# Generated deterministically by seda-macro-lef-normalizer-v1; recipe orfs-asap7-fakeram-m4-v1.
VERSION 5.8 ;
BUSBITCHARS "[]" ;
DIVIDERCHAR "/" ;

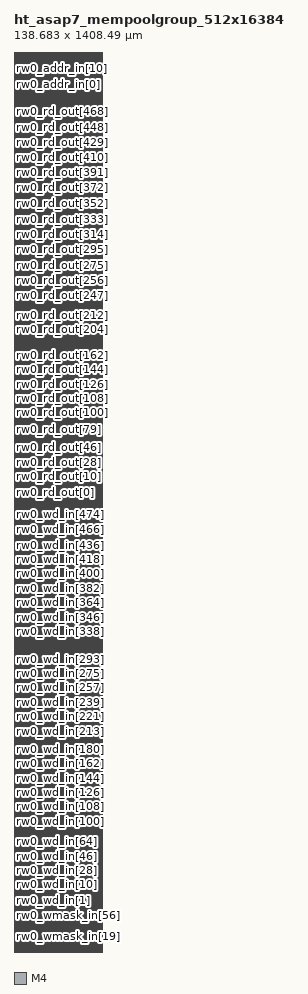
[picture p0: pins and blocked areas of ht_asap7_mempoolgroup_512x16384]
MACRO ht_asap7_mempoolgroup_512x16384
  FOREIGN ht_asap7_mempoolgroup_512x16384 0 0 ;
  CLASS BLOCK ;
  ORIGIN 0 0 ;
  SIZE 138.683 BY 1408.493 ;
  SYMMETRY X Y R90 ;
  PIN rw0_wmask_in[0]
    DIRECTION INPUT ;
    USE SIGNAL ;
    SHAPE ABUTMENT ;
    PORT
      LAYER M4 ;
      RECT 0 0.048 0.024 0.072 ;
    END
  END rw0_wmask_in[0]
  PIN rw0_wmask_in[1]
    DIRECTION INPUT ;
    USE SIGNAL ;
    SHAPE ABUTMENT ;
    PORT
      LAYER M4 ;
      RECT 0 1.296 0.024 1.32 ;
    END
  END rw0_wmask_in[1]
  PIN rw0_wmask_in[2]
    DIRECTION INPUT ;
    USE SIGNAL ;
    SHAPE ABUTMENT ;
    PORT
      LAYER M4 ;
      RECT 0 2.544 0.024 2.568 ;
    END
  END rw0_wmask_in[2]
  PIN rw0_wmask_in[3]
    DIRECTION INPUT ;
    USE SIGNAL ;
    SHAPE ABUTMENT ;
    PORT
      LAYER M4 ;
      RECT 0 3.792 0.024 3.816 ;
    END
  END rw0_wmask_in[3]
  PIN rw0_wmask_in[4]
    DIRECTION INPUT ;
    USE SIGNAL ;
    SHAPE ABUTMENT ;
    PORT
      LAYER M4 ;
      RECT 0 5.04 0.024 5.064 ;
    END
  END rw0_wmask_in[4]
  PIN rw0_wmask_in[5]
    DIRECTION INPUT ;
    USE SIGNAL ;
    SHAPE ABUTMENT ;
    PORT
      LAYER M4 ;
      RECT 0 6.288 0.024 6.312 ;
    END
  END rw0_wmask_in[5]
  PIN rw0_wmask_in[6]
    DIRECTION INPUT ;
    USE SIGNAL ;
    SHAPE ABUTMENT ;
    PORT
      LAYER M4 ;
      RECT 0 7.536 0.024 7.56 ;
    END
  END rw0_wmask_in[6]
  PIN rw0_wmask_in[7]
    DIRECTION INPUT ;
    USE SIGNAL ;
    SHAPE ABUTMENT ;
    PORT
      LAYER M4 ;
      RECT 0 8.784 0.024 8.808 ;
    END
  END rw0_wmask_in[7]
  PIN rw0_wmask_in[8]
    DIRECTION INPUT ;
    USE SIGNAL ;
    SHAPE ABUTMENT ;
    PORT
      LAYER M4 ;
      RECT 0 10.032 0.024 10.056 ;
    END
  END rw0_wmask_in[8]
  PIN rw0_wmask_in[9]
    DIRECTION INPUT ;
    USE SIGNAL ;
    SHAPE ABUTMENT ;
    PORT
      LAYER M4 ;
      RECT 0 11.28 0.024 11.304 ;
    END
  END rw0_wmask_in[9]
  PIN rw0_wmask_in[10]
    DIRECTION INPUT ;
    USE SIGNAL ;
    SHAPE ABUTMENT ;
    PORT
      LAYER M4 ;
      RECT 0 12.528 0.024 12.552 ;
    END
  END rw0_wmask_in[10]
  PIN rw0_wmask_in[11]
    DIRECTION INPUT ;
    USE SIGNAL ;
    SHAPE ABUTMENT ;
    PORT
      LAYER M4 ;
      RECT 0 13.776 0.024 13.8 ;
    END
  END rw0_wmask_in[11]
  PIN rw0_wmask_in[12]
    DIRECTION INPUT ;
    USE SIGNAL ;
    SHAPE ABUTMENT ;
    PORT
      LAYER M4 ;
      RECT 0 15.024 0.024 15.048 ;
    END
  END rw0_wmask_in[12]
  PIN rw0_wmask_in[13]
    DIRECTION INPUT ;
    USE SIGNAL ;
    SHAPE ABUTMENT ;
    PORT
      LAYER M4 ;
      RECT 0 16.272 0.024 16.296 ;
    END
  END rw0_wmask_in[13]
  PIN rw0_wmask_in[14]
    DIRECTION INPUT ;
    USE SIGNAL ;
    SHAPE ABUTMENT ;
    PORT
      LAYER M4 ;
      RECT 0 17.52 0.024 17.544 ;
    END
  END rw0_wmask_in[14]
  PIN rw0_wmask_in[15]
    DIRECTION INPUT ;
    USE SIGNAL ;
    SHAPE ABUTMENT ;
    PORT
      LAYER M4 ;
      RECT 0 18.768 0.024 18.792 ;
    END
  END rw0_wmask_in[15]
  PIN rw0_wmask_in[16]
    DIRECTION INPUT ;
    USE SIGNAL ;
    SHAPE ABUTMENT ;
    PORT
      LAYER M4 ;
      RECT 0 20.016 0.024 20.04 ;
    END
  END rw0_wmask_in[16]
  PIN rw0_wmask_in[17]
    DIRECTION INPUT ;
    USE SIGNAL ;
    SHAPE ABUTMENT ;
    PORT
      LAYER M4 ;
      RECT 0 21.264 0.024 21.288 ;
    END
  END rw0_wmask_in[17]
  PIN rw0_wmask_in[18]
    DIRECTION INPUT ;
    USE SIGNAL ;
    SHAPE ABUTMENT ;
    PORT
      LAYER M4 ;
      RECT 0 22.512 0.024 22.536 ;
    END
  END rw0_wmask_in[18]
  PIN rw0_wmask_in[19]
    DIRECTION INPUT ;
    USE SIGNAL ;
    SHAPE ABUTMENT ;
    PORT
      LAYER M4 ;
      RECT 0 23.76 0.024 23.784 ;
    END
  END rw0_wmask_in[19]
  PIN rw0_wmask_in[20]
    DIRECTION INPUT ;
    USE SIGNAL ;
    SHAPE ABUTMENT ;
    PORT
      LAYER M4 ;
      RECT 0 25.008 0.024 25.032 ;
    END
  END rw0_wmask_in[20]
  PIN rw0_wmask_in[21]
    DIRECTION INPUT ;
    USE SIGNAL ;
    SHAPE ABUTMENT ;
    PORT
      LAYER M4 ;
      RECT 0 26.256 0.024 26.28 ;
    END
  END rw0_wmask_in[21]
  PIN rw0_wmask_in[22]
    DIRECTION INPUT ;
    USE SIGNAL ;
    SHAPE ABUTMENT ;
    PORT
      LAYER M4 ;
      RECT 0 27.504 0.024 27.528 ;
    END
  END rw0_wmask_in[22]
  PIN rw0_wmask_in[23]
    DIRECTION INPUT ;
    USE SIGNAL ;
    SHAPE ABUTMENT ;
    PORT
      LAYER M4 ;
      RECT 0 28.752 0.024 28.776 ;
    END
  END rw0_wmask_in[23]
  PIN rw0_wmask_in[24]
    DIRECTION INPUT ;
    USE SIGNAL ;
    SHAPE ABUTMENT ;
    PORT
      LAYER M4 ;
      RECT 0 30 0.024 30.024 ;
    END
  END rw0_wmask_in[24]
  PIN rw0_wmask_in[25]
    DIRECTION INPUT ;
    USE SIGNAL ;
    SHAPE ABUTMENT ;
    PORT
      LAYER M4 ;
      RECT 0 31.248 0.024 31.272 ;
    END
  END rw0_wmask_in[25]
  PIN rw0_wmask_in[26]
    DIRECTION INPUT ;
    USE SIGNAL ;
    SHAPE ABUTMENT ;
    PORT
      LAYER M4 ;
      RECT 0 32.496 0.024 32.52 ;
    END
  END rw0_wmask_in[26]
  PIN rw0_wmask_in[27]
    DIRECTION INPUT ;
    USE SIGNAL ;
    SHAPE ABUTMENT ;
    PORT
      LAYER M4 ;
      RECT 0 33.744 0.024 33.768 ;
    END
  END rw0_wmask_in[27]
  PIN rw0_wmask_in[28]
    DIRECTION INPUT ;
    USE SIGNAL ;
    SHAPE ABUTMENT ;
    PORT
      LAYER M4 ;
      RECT 0 34.992 0.024 35.016 ;
    END
  END rw0_wmask_in[28]
  PIN rw0_wmask_in[29]
    DIRECTION INPUT ;
    USE SIGNAL ;
    SHAPE ABUTMENT ;
    PORT
      LAYER M4 ;
      RECT 0 36.24 0.024 36.264 ;
    END
  END rw0_wmask_in[29]
  PIN rw0_wmask_in[30]
    DIRECTION INPUT ;
    USE SIGNAL ;
    SHAPE ABUTMENT ;
    PORT
      LAYER M4 ;
      RECT 0 37.488 0.024 37.512 ;
    END
  END rw0_wmask_in[30]
  PIN rw0_wmask_in[31]
    DIRECTION INPUT ;
    USE SIGNAL ;
    SHAPE ABUTMENT ;
    PORT
      LAYER M4 ;
      RECT 0 38.736 0.024 38.76 ;
    END
  END rw0_wmask_in[31]
  PIN rw0_wmask_in[32]
    DIRECTION INPUT ;
    USE SIGNAL ;
    SHAPE ABUTMENT ;
    PORT
      LAYER M4 ;
      RECT 0 39.984 0.024 40.008 ;
    END
  END rw0_wmask_in[32]
  PIN rw0_wmask_in[33]
    DIRECTION INPUT ;
    USE SIGNAL ;
    SHAPE ABUTMENT ;
    PORT
      LAYER M4 ;
      RECT 0 41.232 0.024 41.256 ;
    END
  END rw0_wmask_in[33]
  PIN rw0_wmask_in[34]
    DIRECTION INPUT ;
    USE SIGNAL ;
    SHAPE ABUTMENT ;
    PORT
      LAYER M4 ;
      RECT 0 42.48 0.024 42.504 ;
    END
  END rw0_wmask_in[34]
  PIN rw0_wmask_in[35]
    DIRECTION INPUT ;
    USE SIGNAL ;
    SHAPE ABUTMENT ;
    PORT
      LAYER M4 ;
      RECT 0 43.728 0.024 43.752 ;
    END
  END rw0_wmask_in[35]
  PIN rw0_wmask_in[36]
    DIRECTION INPUT ;
    USE SIGNAL ;
    SHAPE ABUTMENT ;
    PORT
      LAYER M4 ;
      RECT 0 44.976 0.024 45 ;
    END
  END rw0_wmask_in[36]
  PIN rw0_wmask_in[37]
    DIRECTION INPUT ;
    USE SIGNAL ;
    SHAPE ABUTMENT ;
    PORT
      LAYER M4 ;
      RECT 0 46.224 0.024 46.248 ;
    END
  END rw0_wmask_in[37]
  PIN rw0_wmask_in[38]
    DIRECTION INPUT ;
    USE SIGNAL ;
    SHAPE ABUTMENT ;
    PORT
      LAYER M4 ;
      RECT 0 47.472 0.024 47.496 ;
    END
  END rw0_wmask_in[38]
  PIN rw0_wmask_in[39]
    DIRECTION INPUT ;
    USE SIGNAL ;
    SHAPE ABUTMENT ;
    PORT
      LAYER M4 ;
      RECT 0 48.72 0.024 48.744 ;
    END
  END rw0_wmask_in[39]
  PIN rw0_wmask_in[40]
    DIRECTION INPUT ;
    USE SIGNAL ;
    SHAPE ABUTMENT ;
    PORT
      LAYER M4 ;
      RECT 0 49.968 0.024 49.992 ;
    END
  END rw0_wmask_in[40]
  PIN rw0_wmask_in[41]
    DIRECTION INPUT ;
    USE SIGNAL ;
    SHAPE ABUTMENT ;
    PORT
      LAYER M4 ;
      RECT 0 51.216 0.024 51.24 ;
    END
  END rw0_wmask_in[41]
  PIN rw0_wmask_in[42]
    DIRECTION INPUT ;
    USE SIGNAL ;
    SHAPE ABUTMENT ;
    PORT
      LAYER M4 ;
      RECT 0 52.464 0.024 52.488 ;
    END
  END rw0_wmask_in[42]
  PIN rw0_wmask_in[43]
    DIRECTION INPUT ;
    USE SIGNAL ;
    SHAPE ABUTMENT ;
    PORT
      LAYER M4 ;
      RECT 0 53.712 0.024 53.736 ;
    END
  END rw0_wmask_in[43]
  PIN rw0_wmask_in[44]
    DIRECTION INPUT ;
    USE SIGNAL ;
    SHAPE ABUTMENT ;
    PORT
      LAYER M4 ;
      RECT 0 54.96 0.024 54.984 ;
    END
  END rw0_wmask_in[44]
  PIN rw0_wmask_in[45]
    DIRECTION INPUT ;
    USE SIGNAL ;
    SHAPE ABUTMENT ;
    PORT
      LAYER M4 ;
      RECT 0 56.208 0.024 56.232 ;
    END
  END rw0_wmask_in[45]
  PIN rw0_wmask_in[46]
    DIRECTION INPUT ;
    USE SIGNAL ;
    SHAPE ABUTMENT ;
    PORT
      LAYER M4 ;
      RECT 0 57.456 0.024 57.48 ;
    END
  END rw0_wmask_in[46]
  PIN rw0_wmask_in[47]
    DIRECTION INPUT ;
    USE SIGNAL ;
    SHAPE ABUTMENT ;
    PORT
      LAYER M4 ;
      RECT 0 58.704 0.024 58.728 ;
    END
  END rw0_wmask_in[47]
  PIN rw0_wmask_in[48]
    DIRECTION INPUT ;
    USE SIGNAL ;
    SHAPE ABUTMENT ;
    PORT
      LAYER M4 ;
      RECT 0 59.952 0.024 59.976 ;
    END
  END rw0_wmask_in[48]
  PIN rw0_wmask_in[49]
    DIRECTION INPUT ;
    USE SIGNAL ;
    SHAPE ABUTMENT ;
    PORT
      LAYER M4 ;
      RECT 0 61.2 0.024 61.224 ;
    END
  END rw0_wmask_in[49]
  PIN rw0_wmask_in[50]
    DIRECTION INPUT ;
    USE SIGNAL ;
    SHAPE ABUTMENT ;
    PORT
      LAYER M4 ;
      RECT 0 62.448 0.024 62.472 ;
    END
  END rw0_wmask_in[50]
  PIN rw0_wmask_in[51]
    DIRECTION INPUT ;
    USE SIGNAL ;
    SHAPE ABUTMENT ;
    PORT
      LAYER M4 ;
      RECT 0 63.696 0.024 63.72 ;
    END
  END rw0_wmask_in[51]
  PIN rw0_wmask_in[52]
    DIRECTION INPUT ;
    USE SIGNAL ;
    SHAPE ABUTMENT ;
    PORT
      LAYER M4 ;
      RECT 0 64.944 0.024 64.968 ;
    END
  END rw0_wmask_in[52]
  PIN rw0_wmask_in[53]
    DIRECTION INPUT ;
    USE SIGNAL ;
    SHAPE ABUTMENT ;
    PORT
      LAYER M4 ;
      RECT 0 66.192 0.024 66.216 ;
    END
  END rw0_wmask_in[53]
  PIN rw0_wmask_in[54]
    DIRECTION INPUT ;
    USE SIGNAL ;
    SHAPE ABUTMENT ;
    PORT
      LAYER M4 ;
      RECT 0 67.44 0.024 67.464 ;
    END
  END rw0_wmask_in[54]
  PIN rw0_wmask_in[55]
    DIRECTION INPUT ;
    USE SIGNAL ;
    SHAPE ABUTMENT ;
    PORT
      LAYER M4 ;
      RECT 0 68.688 0.024 68.712 ;
    END
  END rw0_wmask_in[55]
  PIN rw0_wmask_in[56]
    DIRECTION INPUT ;
    USE SIGNAL ;
    SHAPE ABUTMENT ;
    PORT
      LAYER M4 ;
      RECT 0 69.936 0.024 69.96 ;
    END
  END rw0_wmask_in[56]
  PIN rw0_wmask_in[57]
    DIRECTION INPUT ;
    USE SIGNAL ;
    SHAPE ABUTMENT ;
    PORT
      LAYER M4 ;
      RECT 0 71.184 0.024 71.208 ;
    END
  END rw0_wmask_in[57]
  PIN rw0_wmask_in[58]
    DIRECTION INPUT ;
    USE SIGNAL ;
    SHAPE ABUTMENT ;
    PORT
      LAYER M4 ;
      RECT 0 72.432 0.024 72.456 ;
    END
  END rw0_wmask_in[58]
  PIN rw0_wmask_in[59]
    DIRECTION INPUT ;
    USE SIGNAL ;
    SHAPE ABUTMENT ;
    PORT
      LAYER M4 ;
      RECT 0 73.68 0.024 73.704 ;
    END
  END rw0_wmask_in[59]
  PIN rw0_wmask_in[60]
    DIRECTION INPUT ;
    USE SIGNAL ;
    SHAPE ABUTMENT ;
    PORT
      LAYER M4 ;
      RECT 0 74.928 0.024 74.952 ;
    END
  END rw0_wmask_in[60]
  PIN rw0_wmask_in[61]
    DIRECTION INPUT ;
    USE SIGNAL ;
    SHAPE ABUTMENT ;
    PORT
      LAYER M4 ;
      RECT 0 76.176 0.024 76.2 ;
    END
  END rw0_wmask_in[61]
  PIN rw0_wmask_in[62]
    DIRECTION INPUT ;
    USE SIGNAL ;
    SHAPE ABUTMENT ;
    PORT
      LAYER M4 ;
      RECT 0 77.424 0.024 77.448 ;
    END
  END rw0_wmask_in[62]
  PIN rw0_wmask_in[63]
    DIRECTION INPUT ;
    USE SIGNAL ;
    SHAPE ABUTMENT ;
    PORT
      LAYER M4 ;
      RECT 0 78.672 0.024 78.696 ;
    END
  END rw0_wmask_in[63]
  PIN rw0_wd_in[0]
    DIRECTION INPUT ;
    USE SIGNAL ;
    SHAPE ABUTMENT ;
    PORT
      LAYER M4 ;
      RECT 0 79.92 0.024 79.944 ;
    END
  END rw0_wd_in[0]
  PIN rw0_wd_in[1]
    DIRECTION INPUT ;
    USE SIGNAL ;
    SHAPE ABUTMENT ;
    PORT
      LAYER M4 ;
      RECT 0 81.168 0.024 81.192 ;
    END
  END rw0_wd_in[1]
  PIN rw0_wd_in[2]
    DIRECTION INPUT ;
    USE SIGNAL ;
    SHAPE ABUTMENT ;
    PORT
      LAYER M4 ;
      RECT 0 82.416 0.024 82.44 ;
    END
  END rw0_wd_in[2]
  PIN rw0_wd_in[3]
    DIRECTION INPUT ;
    USE SIGNAL ;
    SHAPE ABUTMENT ;
    PORT
      LAYER M4 ;
      RECT 0 83.664 0.024 83.688 ;
    END
  END rw0_wd_in[3]
  PIN rw0_wd_in[4]
    DIRECTION INPUT ;
    USE SIGNAL ;
    SHAPE ABUTMENT ;
    PORT
      LAYER M4 ;
      RECT 0 84.912 0.024 84.936 ;
    END
  END rw0_wd_in[4]
  PIN rw0_wd_in[5]
    DIRECTION INPUT ;
    USE SIGNAL ;
    SHAPE ABUTMENT ;
    PORT
      LAYER M4 ;
      RECT 0 86.16 0.024 86.184 ;
    END
  END rw0_wd_in[5]
  PIN rw0_wd_in[6]
    DIRECTION INPUT ;
    USE SIGNAL ;
    SHAPE ABUTMENT ;
    PORT
      LAYER M4 ;
      RECT 0 87.408 0.024 87.432 ;
    END
  END rw0_wd_in[6]
  PIN rw0_wd_in[7]
    DIRECTION INPUT ;
    USE SIGNAL ;
    SHAPE ABUTMENT ;
    PORT
      LAYER M4 ;
      RECT 0 88.656 0.024 88.68 ;
    END
  END rw0_wd_in[7]
  PIN rw0_wd_in[8]
    DIRECTION INPUT ;
    USE SIGNAL ;
    SHAPE ABUTMENT ;
    PORT
      LAYER M4 ;
      RECT 0 89.904 0.024 89.928 ;
    END
  END rw0_wd_in[8]
  PIN rw0_wd_in[9]
    DIRECTION INPUT ;
    USE SIGNAL ;
    SHAPE ABUTMENT ;
    PORT
      LAYER M4 ;
      RECT 0 91.152 0.024 91.176 ;
    END
  END rw0_wd_in[9]
  PIN rw0_wd_in[10]
    DIRECTION INPUT ;
    USE SIGNAL ;
    SHAPE ABUTMENT ;
    PORT
      LAYER M4 ;
      RECT 0 92.4 0.024 92.424 ;
    END
  END rw0_wd_in[10]
  PIN rw0_wd_in[11]
    DIRECTION INPUT ;
    USE SIGNAL ;
    SHAPE ABUTMENT ;
    PORT
      LAYER M4 ;
      RECT 0 93.648 0.024 93.672 ;
    END
  END rw0_wd_in[11]
  PIN rw0_wd_in[12]
    DIRECTION INPUT ;
    USE SIGNAL ;
    SHAPE ABUTMENT ;
    PORT
      LAYER M4 ;
      RECT 0 94.896 0.024 94.92 ;
    END
  END rw0_wd_in[12]
  PIN rw0_wd_in[13]
    DIRECTION INPUT ;
    USE SIGNAL ;
    SHAPE ABUTMENT ;
    PORT
      LAYER M4 ;
      RECT 0 96.144 0.024 96.168 ;
    END
  END rw0_wd_in[13]
  PIN rw0_wd_in[14]
    DIRECTION INPUT ;
    USE SIGNAL ;
    SHAPE ABUTMENT ;
    PORT
      LAYER M4 ;
      RECT 0 97.392 0.024 97.416 ;
    END
  END rw0_wd_in[14]
  PIN rw0_wd_in[15]
    DIRECTION INPUT ;
    USE SIGNAL ;
    SHAPE ABUTMENT ;
    PORT
      LAYER M4 ;
      RECT 0 98.64 0.024 98.664 ;
    END
  END rw0_wd_in[15]
  PIN rw0_wd_in[16]
    DIRECTION INPUT ;
    USE SIGNAL ;
    SHAPE ABUTMENT ;
    PORT
      LAYER M4 ;
      RECT 0 99.888 0.024 99.912 ;
    END
  END rw0_wd_in[16]
  PIN rw0_wd_in[17]
    DIRECTION INPUT ;
    USE SIGNAL ;
    SHAPE ABUTMENT ;
    PORT
      LAYER M4 ;
      RECT 0 101.136 0.024 101.16 ;
    END
  END rw0_wd_in[17]
  PIN rw0_wd_in[18]
    DIRECTION INPUT ;
    USE SIGNAL ;
    SHAPE ABUTMENT ;
    PORT
      LAYER M4 ;
      RECT 0 102.384 0.024 102.408 ;
    END
  END rw0_wd_in[18]
  PIN rw0_wd_in[19]
    DIRECTION INPUT ;
    USE SIGNAL ;
    SHAPE ABUTMENT ;
    PORT
      LAYER M4 ;
      RECT 0 103.632 0.024 103.656 ;
    END
  END rw0_wd_in[19]
  PIN rw0_wd_in[20]
    DIRECTION INPUT ;
    USE SIGNAL ;
    SHAPE ABUTMENT ;
    PORT
      LAYER M4 ;
      RECT 0 104.88 0.024 104.904 ;
    END
  END rw0_wd_in[20]
  PIN rw0_wd_in[21]
    DIRECTION INPUT ;
    USE SIGNAL ;
    SHAPE ABUTMENT ;
    PORT
      LAYER M4 ;
      RECT 0 106.128 0.024 106.152 ;
    END
  END rw0_wd_in[21]
  PIN rw0_wd_in[22]
    DIRECTION INPUT ;
    USE SIGNAL ;
    SHAPE ABUTMENT ;
    PORT
      LAYER M4 ;
      RECT 0 107.376 0.024 107.4 ;
    END
  END rw0_wd_in[22]
  PIN rw0_wd_in[23]
    DIRECTION INPUT ;
    USE SIGNAL ;
    SHAPE ABUTMENT ;
    PORT
      LAYER M4 ;
      RECT 0 108.624 0.024 108.648 ;
    END
  END rw0_wd_in[23]
  PIN rw0_wd_in[24]
    DIRECTION INPUT ;
    USE SIGNAL ;
    SHAPE ABUTMENT ;
    PORT
      LAYER M4 ;
      RECT 0 109.872 0.024 109.896 ;
    END
  END rw0_wd_in[24]
  PIN rw0_wd_in[25]
    DIRECTION INPUT ;
    USE SIGNAL ;
    SHAPE ABUTMENT ;
    PORT
      LAYER M4 ;
      RECT 0 111.12 0.024 111.144 ;
    END
  END rw0_wd_in[25]
  PIN rw0_wd_in[26]
    DIRECTION INPUT ;
    USE SIGNAL ;
    SHAPE ABUTMENT ;
    PORT
      LAYER M4 ;
      RECT 0 112.368 0.024 112.392 ;
    END
  END rw0_wd_in[26]
  PIN rw0_wd_in[27]
    DIRECTION INPUT ;
    USE SIGNAL ;
    SHAPE ABUTMENT ;
    PORT
      LAYER M4 ;
      RECT 0 113.616 0.024 113.64 ;
    END
  END rw0_wd_in[27]
  PIN rw0_wd_in[28]
    DIRECTION INPUT ;
    USE SIGNAL ;
    SHAPE ABUTMENT ;
    PORT
      LAYER M4 ;
      RECT 0 114.864 0.024 114.888 ;
    END
  END rw0_wd_in[28]
  PIN rw0_wd_in[29]
    DIRECTION INPUT ;
    USE SIGNAL ;
    SHAPE ABUTMENT ;
    PORT
      LAYER M4 ;
      RECT 0 116.112 0.024 116.136 ;
    END
  END rw0_wd_in[29]
  PIN rw0_wd_in[30]
    DIRECTION INPUT ;
    USE SIGNAL ;
    SHAPE ABUTMENT ;
    PORT
      LAYER M4 ;
      RECT 0 117.36 0.024 117.384 ;
    END
  END rw0_wd_in[30]
  PIN rw0_wd_in[31]
    DIRECTION INPUT ;
    USE SIGNAL ;
    SHAPE ABUTMENT ;
    PORT
      LAYER M4 ;
      RECT 0 118.608 0.024 118.632 ;
    END
  END rw0_wd_in[31]
  PIN rw0_wd_in[32]
    DIRECTION INPUT ;
    USE SIGNAL ;
    SHAPE ABUTMENT ;
    PORT
      LAYER M4 ;
      RECT 0 119.856 0.024 119.88 ;
    END
  END rw0_wd_in[32]
  PIN rw0_wd_in[33]
    DIRECTION INPUT ;
    USE SIGNAL ;
    SHAPE ABUTMENT ;
    PORT
      LAYER M4 ;
      RECT 0 121.104 0.024 121.128 ;
    END
  END rw0_wd_in[33]
  PIN rw0_wd_in[34]
    DIRECTION INPUT ;
    USE SIGNAL ;
    SHAPE ABUTMENT ;
    PORT
      LAYER M4 ;
      RECT 0 122.352 0.024 122.376 ;
    END
  END rw0_wd_in[34]
  PIN rw0_wd_in[35]
    DIRECTION INPUT ;
    USE SIGNAL ;
    SHAPE ABUTMENT ;
    PORT
      LAYER M4 ;
      RECT 0 123.6 0.024 123.624 ;
    END
  END rw0_wd_in[35]
  PIN rw0_wd_in[36]
    DIRECTION INPUT ;
    USE SIGNAL ;
    SHAPE ABUTMENT ;
    PORT
      LAYER M4 ;
      RECT 0 124.848 0.024 124.872 ;
    END
  END rw0_wd_in[36]
  PIN rw0_wd_in[37]
    DIRECTION INPUT ;
    USE SIGNAL ;
    SHAPE ABUTMENT ;
    PORT
      LAYER M4 ;
      RECT 0 126.096 0.024 126.12 ;
    END
  END rw0_wd_in[37]
  PIN rw0_wd_in[38]
    DIRECTION INPUT ;
    USE SIGNAL ;
    SHAPE ABUTMENT ;
    PORT
      LAYER M4 ;
      RECT 0 127.344 0.024 127.368 ;
    END
  END rw0_wd_in[38]
  PIN rw0_wd_in[39]
    DIRECTION INPUT ;
    USE SIGNAL ;
    SHAPE ABUTMENT ;
    PORT
      LAYER M4 ;
      RECT 0 128.592 0.024 128.616 ;
    END
  END rw0_wd_in[39]
  PIN rw0_wd_in[40]
    DIRECTION INPUT ;
    USE SIGNAL ;
    SHAPE ABUTMENT ;
    PORT
      LAYER M4 ;
      RECT 0 129.84 0.024 129.864 ;
    END
  END rw0_wd_in[40]
  PIN rw0_wd_in[41]
    DIRECTION INPUT ;
    USE SIGNAL ;
    SHAPE ABUTMENT ;
    PORT
      LAYER M4 ;
      RECT 0 131.088 0.024 131.112 ;
    END
  END rw0_wd_in[41]
  PIN rw0_wd_in[42]
    DIRECTION INPUT ;
    USE SIGNAL ;
    SHAPE ABUTMENT ;
    PORT
      LAYER M4 ;
      RECT 0 132.336 0.024 132.36 ;
    END
  END rw0_wd_in[42]
  PIN rw0_wd_in[43]
    DIRECTION INPUT ;
    USE SIGNAL ;
    SHAPE ABUTMENT ;
    PORT
      LAYER M4 ;
      RECT 0 133.584 0.024 133.608 ;
    END
  END rw0_wd_in[43]
  PIN rw0_wd_in[44]
    DIRECTION INPUT ;
    USE SIGNAL ;
    SHAPE ABUTMENT ;
    PORT
      LAYER M4 ;
      RECT 0 134.832 0.024 134.856 ;
    END
  END rw0_wd_in[44]
  PIN rw0_wd_in[45]
    DIRECTION INPUT ;
    USE SIGNAL ;
    SHAPE ABUTMENT ;
    PORT
      LAYER M4 ;
      RECT 0 136.08 0.024 136.104 ;
    END
  END rw0_wd_in[45]
  PIN rw0_wd_in[46]
    DIRECTION INPUT ;
    USE SIGNAL ;
    SHAPE ABUTMENT ;
    PORT
      LAYER M4 ;
      RECT 0 137.328 0.024 137.352 ;
    END
  END rw0_wd_in[46]
  PIN rw0_wd_in[47]
    DIRECTION INPUT ;
    USE SIGNAL ;
    SHAPE ABUTMENT ;
    PORT
      LAYER M4 ;
      RECT 0 138.576 0.024 138.6 ;
    END
  END rw0_wd_in[47]
  PIN rw0_wd_in[48]
    DIRECTION INPUT ;
    USE SIGNAL ;
    SHAPE ABUTMENT ;
    PORT
      LAYER M4 ;
      RECT 0 139.824 0.024 139.848 ;
    END
  END rw0_wd_in[48]
  PIN rw0_wd_in[49]
    DIRECTION INPUT ;
    USE SIGNAL ;
    SHAPE ABUTMENT ;
    PORT
      LAYER M4 ;
      RECT 0 141.072 0.024 141.096 ;
    END
  END rw0_wd_in[49]
  PIN rw0_wd_in[50]
    DIRECTION INPUT ;
    USE SIGNAL ;
    SHAPE ABUTMENT ;
    PORT
      LAYER M4 ;
      RECT 0 142.32 0.024 142.344 ;
    END
  END rw0_wd_in[50]
  PIN rw0_wd_in[51]
    DIRECTION INPUT ;
    USE SIGNAL ;
    SHAPE ABUTMENT ;
    PORT
      LAYER M4 ;
      RECT 0 143.568 0.024 143.592 ;
    END
  END rw0_wd_in[51]
  PIN rw0_wd_in[52]
    DIRECTION INPUT ;
    USE SIGNAL ;
    SHAPE ABUTMENT ;
    PORT
      LAYER M4 ;
      RECT 0 144.816 0.024 144.84 ;
    END
  END rw0_wd_in[52]
  PIN rw0_wd_in[53]
    DIRECTION INPUT ;
    USE SIGNAL ;
    SHAPE ABUTMENT ;
    PORT
      LAYER M4 ;
      RECT 0 146.064 0.024 146.088 ;
    END
  END rw0_wd_in[53]
  PIN rw0_wd_in[54]
    DIRECTION INPUT ;
    USE SIGNAL ;
    SHAPE ABUTMENT ;
    PORT
      LAYER M4 ;
      RECT 0 147.312 0.024 147.336 ;
    END
  END rw0_wd_in[54]
  PIN rw0_wd_in[55]
    DIRECTION INPUT ;
    USE SIGNAL ;
    SHAPE ABUTMENT ;
    PORT
      LAYER M4 ;
      RECT 0 148.56 0.024 148.584 ;
    END
  END rw0_wd_in[55]
  PIN rw0_wd_in[56]
    DIRECTION INPUT ;
    USE SIGNAL ;
    SHAPE ABUTMENT ;
    PORT
      LAYER M4 ;
      RECT 0 149.808 0.024 149.832 ;
    END
  END rw0_wd_in[56]
  PIN rw0_wd_in[57]
    DIRECTION INPUT ;
    USE SIGNAL ;
    SHAPE ABUTMENT ;
    PORT
      LAYER M4 ;
      RECT 0 151.056 0.024 151.08 ;
    END
  END rw0_wd_in[57]
  PIN rw0_wd_in[58]
    DIRECTION INPUT ;
    USE SIGNAL ;
    SHAPE ABUTMENT ;
    PORT
      LAYER M4 ;
      RECT 0 152.304 0.024 152.328 ;
    END
  END rw0_wd_in[58]
  PIN rw0_wd_in[59]
    DIRECTION INPUT ;
    USE SIGNAL ;
    SHAPE ABUTMENT ;
    PORT
      LAYER M4 ;
      RECT 0 153.552 0.024 153.576 ;
    END
  END rw0_wd_in[59]
  PIN rw0_wd_in[60]
    DIRECTION INPUT ;
    USE SIGNAL ;
    SHAPE ABUTMENT ;
    PORT
      LAYER M4 ;
      RECT 0 154.8 0.024 154.824 ;
    END
  END rw0_wd_in[60]
  PIN rw0_wd_in[61]
    DIRECTION INPUT ;
    USE SIGNAL ;
    SHAPE ABUTMENT ;
    PORT
      LAYER M4 ;
      RECT 0 156.048 0.024 156.072 ;
    END
  END rw0_wd_in[61]
  PIN rw0_wd_in[62]
    DIRECTION INPUT ;
    USE SIGNAL ;
    SHAPE ABUTMENT ;
    PORT
      LAYER M4 ;
      RECT 0 157.296 0.024 157.32 ;
    END
  END rw0_wd_in[62]
  PIN rw0_wd_in[63]
    DIRECTION INPUT ;
    USE SIGNAL ;
    SHAPE ABUTMENT ;
    PORT
      LAYER M4 ;
      RECT 0 158.544 0.024 158.568 ;
    END
  END rw0_wd_in[63]
  PIN rw0_wd_in[64]
    DIRECTION INPUT ;
    USE SIGNAL ;
    SHAPE ABUTMENT ;
    PORT
      LAYER M4 ;
      RECT 0 159.792 0.024 159.816 ;
    END
  END rw0_wd_in[64]
  PIN rw0_wd_in[65]
    DIRECTION INPUT ;
    USE SIGNAL ;
    SHAPE ABUTMENT ;
    PORT
      LAYER M4 ;
      RECT 0 161.04 0.024 161.064 ;
    END
  END rw0_wd_in[65]
  PIN rw0_wd_in[66]
    DIRECTION INPUT ;
    USE SIGNAL ;
    SHAPE ABUTMENT ;
    PORT
      LAYER M4 ;
      RECT 0 162.288 0.024 162.312 ;
    END
  END rw0_wd_in[66]
  PIN rw0_wd_in[67]
    DIRECTION INPUT ;
    USE SIGNAL ;
    SHAPE ABUTMENT ;
    PORT
      LAYER M4 ;
      RECT 0 163.536 0.024 163.56 ;
    END
  END rw0_wd_in[67]
  PIN rw0_wd_in[68]
    DIRECTION INPUT ;
    USE SIGNAL ;
    SHAPE ABUTMENT ;
    PORT
      LAYER M4 ;
      RECT 0 164.784 0.024 164.808 ;
    END
  END rw0_wd_in[68]
  PIN rw0_wd_in[69]
    DIRECTION INPUT ;
    USE SIGNAL ;
    SHAPE ABUTMENT ;
    PORT
      LAYER M4 ;
      RECT 0 166.032 0.024 166.056 ;
    END
  END rw0_wd_in[69]
  PIN rw0_wd_in[70]
    DIRECTION INPUT ;
    USE SIGNAL ;
    SHAPE ABUTMENT ;
    PORT
      LAYER M4 ;
      RECT 0 167.28 0.024 167.304 ;
    END
  END rw0_wd_in[70]
  PIN rw0_wd_in[71]
    DIRECTION INPUT ;
    USE SIGNAL ;
    SHAPE ABUTMENT ;
    PORT
      LAYER M4 ;
      RECT 0 168.528 0.024 168.552 ;
    END
  END rw0_wd_in[71]
  PIN rw0_wd_in[72]
    DIRECTION INPUT ;
    USE SIGNAL ;
    SHAPE ABUTMENT ;
    PORT
      LAYER M4 ;
      RECT 0 169.776 0.024 169.8 ;
    END
  END rw0_wd_in[72]
  PIN rw0_wd_in[73]
    DIRECTION INPUT ;
    USE SIGNAL ;
    SHAPE ABUTMENT ;
    PORT
      LAYER M4 ;
      RECT 0 171.024 0.024 171.048 ;
    END
  END rw0_wd_in[73]
  PIN rw0_wd_in[74]
    DIRECTION INPUT ;
    USE SIGNAL ;
    SHAPE ABUTMENT ;
    PORT
      LAYER M4 ;
      RECT 0 172.272 0.024 172.296 ;
    END
  END rw0_wd_in[74]
  PIN rw0_wd_in[75]
    DIRECTION INPUT ;
    USE SIGNAL ;
    SHAPE ABUTMENT ;
    PORT
      LAYER M4 ;
      RECT 0 173.52 0.024 173.544 ;
    END
  END rw0_wd_in[75]
  PIN rw0_wd_in[76]
    DIRECTION INPUT ;
    USE SIGNAL ;
    SHAPE ABUTMENT ;
    PORT
      LAYER M4 ;
      RECT 0 174.768 0.024 174.792 ;
    END
  END rw0_wd_in[76]
  PIN rw0_wd_in[77]
    DIRECTION INPUT ;
    USE SIGNAL ;
    SHAPE ABUTMENT ;
    PORT
      LAYER M4 ;
      RECT 0 176.016 0.024 176.04 ;
    END
  END rw0_wd_in[77]
  PIN rw0_wd_in[78]
    DIRECTION INPUT ;
    USE SIGNAL ;
    SHAPE ABUTMENT ;
    PORT
      LAYER M4 ;
      RECT 0 177.264 0.024 177.288 ;
    END
  END rw0_wd_in[78]
  PIN rw0_wd_in[79]
    DIRECTION INPUT ;
    USE SIGNAL ;
    SHAPE ABUTMENT ;
    PORT
      LAYER M4 ;
      RECT 0 178.512 0.024 178.536 ;
    END
  END rw0_wd_in[79]
  PIN rw0_wd_in[80]
    DIRECTION INPUT ;
    USE SIGNAL ;
    SHAPE ABUTMENT ;
    PORT
      LAYER M4 ;
      RECT 0 179.76 0.024 179.784 ;
    END
  END rw0_wd_in[80]
  PIN rw0_wd_in[81]
    DIRECTION INPUT ;
    USE SIGNAL ;
    SHAPE ABUTMENT ;
    PORT
      LAYER M4 ;
      RECT 0 181.008 0.024 181.032 ;
    END
  END rw0_wd_in[81]
  PIN rw0_wd_in[82]
    DIRECTION INPUT ;
    USE SIGNAL ;
    SHAPE ABUTMENT ;
    PORT
      LAYER M4 ;
      RECT 0 182.256 0.024 182.28 ;
    END
  END rw0_wd_in[82]
  PIN rw0_wd_in[83]
    DIRECTION INPUT ;
    USE SIGNAL ;
    SHAPE ABUTMENT ;
    PORT
      LAYER M4 ;
      RECT 0 183.504 0.024 183.528 ;
    END
  END rw0_wd_in[83]
  PIN rw0_wd_in[84]
    DIRECTION INPUT ;
    USE SIGNAL ;
    SHAPE ABUTMENT ;
    PORT
      LAYER M4 ;
      RECT 0 184.752 0.024 184.776 ;
    END
  END rw0_wd_in[84]
  PIN rw0_wd_in[85]
    DIRECTION INPUT ;
    USE SIGNAL ;
    SHAPE ABUTMENT ;
    PORT
      LAYER M4 ;
      RECT 0 186 0.024 186.024 ;
    END
  END rw0_wd_in[85]
  PIN rw0_wd_in[86]
    DIRECTION INPUT ;
    USE SIGNAL ;
    SHAPE ABUTMENT ;
    PORT
      LAYER M4 ;
      RECT 0 187.248 0.024 187.272 ;
    END
  END rw0_wd_in[86]
  PIN rw0_wd_in[87]
    DIRECTION INPUT ;
    USE SIGNAL ;
    SHAPE ABUTMENT ;
    PORT
      LAYER M4 ;
      RECT 0 188.496 0.024 188.52 ;
    END
  END rw0_wd_in[87]
  PIN rw0_wd_in[88]
    DIRECTION INPUT ;
    USE SIGNAL ;
    SHAPE ABUTMENT ;
    PORT
      LAYER M4 ;
      RECT 0 189.744 0.024 189.768 ;
    END
  END rw0_wd_in[88]
  PIN rw0_wd_in[89]
    DIRECTION INPUT ;
    USE SIGNAL ;
    SHAPE ABUTMENT ;
    PORT
      LAYER M4 ;
      RECT 0 190.992 0.024 191.016 ;
    END
  END rw0_wd_in[89]
  PIN rw0_wd_in[90]
    DIRECTION INPUT ;
    USE SIGNAL ;
    SHAPE ABUTMENT ;
    PORT
      LAYER M4 ;
      RECT 0 192.24 0.024 192.264 ;
    END
  END rw0_wd_in[90]
  PIN rw0_wd_in[91]
    DIRECTION INPUT ;
    USE SIGNAL ;
    SHAPE ABUTMENT ;
    PORT
      LAYER M4 ;
      RECT 0 193.488 0.024 193.512 ;
    END
  END rw0_wd_in[91]
  PIN rw0_wd_in[92]
    DIRECTION INPUT ;
    USE SIGNAL ;
    SHAPE ABUTMENT ;
    PORT
      LAYER M4 ;
      RECT 0 194.736 0.024 194.76 ;
    END
  END rw0_wd_in[92]
  PIN rw0_wd_in[93]
    DIRECTION INPUT ;
    USE SIGNAL ;
    SHAPE ABUTMENT ;
    PORT
      LAYER M4 ;
      RECT 0 195.984 0.024 196.008 ;
    END
  END rw0_wd_in[93]
  PIN rw0_wd_in[94]
    DIRECTION INPUT ;
    USE SIGNAL ;
    SHAPE ABUTMENT ;
    PORT
      LAYER M4 ;
      RECT 0 197.232 0.024 197.256 ;
    END
  END rw0_wd_in[94]
  PIN rw0_wd_in[95]
    DIRECTION INPUT ;
    USE SIGNAL ;
    SHAPE ABUTMENT ;
    PORT
      LAYER M4 ;
      RECT 0 198.48 0.024 198.504 ;
    END
  END rw0_wd_in[95]
  PIN rw0_wd_in[96]
    DIRECTION INPUT ;
    USE SIGNAL ;
    SHAPE ABUTMENT ;
    PORT
      LAYER M4 ;
      RECT 0 199.728 0.024 199.752 ;
    END
  END rw0_wd_in[96]
  PIN rw0_wd_in[97]
    DIRECTION INPUT ;
    USE SIGNAL ;
    SHAPE ABUTMENT ;
    PORT
      LAYER M4 ;
      RECT 0 200.976 0.024 201 ;
    END
  END rw0_wd_in[97]
  PIN rw0_wd_in[98]
    DIRECTION INPUT ;
    USE SIGNAL ;
    SHAPE ABUTMENT ;
    PORT
      LAYER M4 ;
      RECT 0 202.224 0.024 202.248 ;
    END
  END rw0_wd_in[98]
  PIN rw0_wd_in[99]
    DIRECTION INPUT ;
    USE SIGNAL ;
    SHAPE ABUTMENT ;
    PORT
      LAYER M4 ;
      RECT 0 203.472 0.024 203.496 ;
    END
  END rw0_wd_in[99]
  PIN rw0_wd_in[100]
    DIRECTION INPUT ;
    USE SIGNAL ;
    SHAPE ABUTMENT ;
    PORT
      LAYER M4 ;
      RECT 0 204.72 0.024 204.744 ;
    END
  END rw0_wd_in[100]
  PIN rw0_wd_in[101]
    DIRECTION INPUT ;
    USE SIGNAL ;
    SHAPE ABUTMENT ;
    PORT
      LAYER M4 ;
      RECT 0 205.968 0.024 205.992 ;
    END
  END rw0_wd_in[101]
  PIN rw0_wd_in[102]
    DIRECTION INPUT ;
    USE SIGNAL ;
    SHAPE ABUTMENT ;
    PORT
      LAYER M4 ;
      RECT 0 207.216 0.024 207.24 ;
    END
  END rw0_wd_in[102]
  PIN rw0_wd_in[103]
    DIRECTION INPUT ;
    USE SIGNAL ;
    SHAPE ABUTMENT ;
    PORT
      LAYER M4 ;
      RECT 0 208.464 0.024 208.488 ;
    END
  END rw0_wd_in[103]
  PIN rw0_wd_in[104]
    DIRECTION INPUT ;
    USE SIGNAL ;
    SHAPE ABUTMENT ;
    PORT
      LAYER M4 ;
      RECT 0 209.712 0.024 209.736 ;
    END
  END rw0_wd_in[104]
  PIN rw0_wd_in[105]
    DIRECTION INPUT ;
    USE SIGNAL ;
    SHAPE ABUTMENT ;
    PORT
      LAYER M4 ;
      RECT 0 210.96 0.024 210.984 ;
    END
  END rw0_wd_in[105]
  PIN rw0_wd_in[106]
    DIRECTION INPUT ;
    USE SIGNAL ;
    SHAPE ABUTMENT ;
    PORT
      LAYER M4 ;
      RECT 0 212.208 0.024 212.232 ;
    END
  END rw0_wd_in[106]
  PIN rw0_wd_in[107]
    DIRECTION INPUT ;
    USE SIGNAL ;
    SHAPE ABUTMENT ;
    PORT
      LAYER M4 ;
      RECT 0 213.456 0.024 213.48 ;
    END
  END rw0_wd_in[107]
  PIN rw0_wd_in[108]
    DIRECTION INPUT ;
    USE SIGNAL ;
    SHAPE ABUTMENT ;
    PORT
      LAYER M4 ;
      RECT 0 214.704 0.024 214.728 ;
    END
  END rw0_wd_in[108]
  PIN rw0_wd_in[109]
    DIRECTION INPUT ;
    USE SIGNAL ;
    SHAPE ABUTMENT ;
    PORT
      LAYER M4 ;
      RECT 0 215.952 0.024 215.976 ;
    END
  END rw0_wd_in[109]
  PIN rw0_wd_in[110]
    DIRECTION INPUT ;
    USE SIGNAL ;
    SHAPE ABUTMENT ;
    PORT
      LAYER M4 ;
      RECT 0 217.2 0.024 217.224 ;
    END
  END rw0_wd_in[110]
  PIN rw0_wd_in[111]
    DIRECTION INPUT ;
    USE SIGNAL ;
    SHAPE ABUTMENT ;
    PORT
      LAYER M4 ;
      RECT 0 218.448 0.024 218.472 ;
    END
  END rw0_wd_in[111]
  PIN rw0_wd_in[112]
    DIRECTION INPUT ;
    USE SIGNAL ;
    SHAPE ABUTMENT ;
    PORT
      LAYER M4 ;
      RECT 0 219.696 0.024 219.72 ;
    END
  END rw0_wd_in[112]
  PIN rw0_wd_in[113]
    DIRECTION INPUT ;
    USE SIGNAL ;
    SHAPE ABUTMENT ;
    PORT
      LAYER M4 ;
      RECT 0 220.944 0.024 220.968 ;
    END
  END rw0_wd_in[113]
  PIN rw0_wd_in[114]
    DIRECTION INPUT ;
    USE SIGNAL ;
    SHAPE ABUTMENT ;
    PORT
      LAYER M4 ;
      RECT 0 222.192 0.024 222.216 ;
    END
  END rw0_wd_in[114]
  PIN rw0_wd_in[115]
    DIRECTION INPUT ;
    USE SIGNAL ;
    SHAPE ABUTMENT ;
    PORT
      LAYER M4 ;
      RECT 0 223.44 0.024 223.464 ;
    END
  END rw0_wd_in[115]
  PIN rw0_wd_in[116]
    DIRECTION INPUT ;
    USE SIGNAL ;
    SHAPE ABUTMENT ;
    PORT
      LAYER M4 ;
      RECT 0 224.688 0.024 224.712 ;
    END
  END rw0_wd_in[116]
  PIN rw0_wd_in[117]
    DIRECTION INPUT ;
    USE SIGNAL ;
    SHAPE ABUTMENT ;
    PORT
      LAYER M4 ;
      RECT 0 225.936 0.024 225.96 ;
    END
  END rw0_wd_in[117]
  PIN rw0_wd_in[118]
    DIRECTION INPUT ;
    USE SIGNAL ;
    SHAPE ABUTMENT ;
    PORT
      LAYER M4 ;
      RECT 0 227.184 0.024 227.208 ;
    END
  END rw0_wd_in[118]
  PIN rw0_wd_in[119]
    DIRECTION INPUT ;
    USE SIGNAL ;
    SHAPE ABUTMENT ;
    PORT
      LAYER M4 ;
      RECT 0 228.432 0.024 228.456 ;
    END
  END rw0_wd_in[119]
  PIN rw0_wd_in[120]
    DIRECTION INPUT ;
    USE SIGNAL ;
    SHAPE ABUTMENT ;
    PORT
      LAYER M4 ;
      RECT 0 229.68 0.024 229.704 ;
    END
  END rw0_wd_in[120]
  PIN rw0_wd_in[121]
    DIRECTION INPUT ;
    USE SIGNAL ;
    SHAPE ABUTMENT ;
    PORT
      LAYER M4 ;
      RECT 0 230.928 0.024 230.952 ;
    END
  END rw0_wd_in[121]
  PIN rw0_wd_in[122]
    DIRECTION INPUT ;
    USE SIGNAL ;
    SHAPE ABUTMENT ;
    PORT
      LAYER M4 ;
      RECT 0 232.176 0.024 232.2 ;
    END
  END rw0_wd_in[122]
  PIN rw0_wd_in[123]
    DIRECTION INPUT ;
    USE SIGNAL ;
    SHAPE ABUTMENT ;
    PORT
      LAYER M4 ;
      RECT 0 233.424 0.024 233.448 ;
    END
  END rw0_wd_in[123]
  PIN rw0_wd_in[124]
    DIRECTION INPUT ;
    USE SIGNAL ;
    SHAPE ABUTMENT ;
    PORT
      LAYER M4 ;
      RECT 0 234.672 0.024 234.696 ;
    END
  END rw0_wd_in[124]
  PIN rw0_wd_in[125]
    DIRECTION INPUT ;
    USE SIGNAL ;
    SHAPE ABUTMENT ;
    PORT
      LAYER M4 ;
      RECT 0 235.92 0.024 235.944 ;
    END
  END rw0_wd_in[125]
  PIN rw0_wd_in[126]
    DIRECTION INPUT ;
    USE SIGNAL ;
    SHAPE ABUTMENT ;
    PORT
      LAYER M4 ;
      RECT 0 237.168 0.024 237.192 ;
    END
  END rw0_wd_in[126]
  PIN rw0_wd_in[127]
    DIRECTION INPUT ;
    USE SIGNAL ;
    SHAPE ABUTMENT ;
    PORT
      LAYER M4 ;
      RECT 0 238.416 0.024 238.44 ;
    END
  END rw0_wd_in[127]
  PIN rw0_wd_in[128]
    DIRECTION INPUT ;
    USE SIGNAL ;
    SHAPE ABUTMENT ;
    PORT
      LAYER M4 ;
      RECT 0 239.664 0.024 239.688 ;
    END
  END rw0_wd_in[128]
  PIN rw0_wd_in[129]
    DIRECTION INPUT ;
    USE SIGNAL ;
    SHAPE ABUTMENT ;
    PORT
      LAYER M4 ;
      RECT 0 240.912 0.024 240.936 ;
    END
  END rw0_wd_in[129]
  PIN rw0_wd_in[130]
    DIRECTION INPUT ;
    USE SIGNAL ;
    SHAPE ABUTMENT ;
    PORT
      LAYER M4 ;
      RECT 0 242.16 0.024 242.184 ;
    END
  END rw0_wd_in[130]
  PIN rw0_wd_in[131]
    DIRECTION INPUT ;
    USE SIGNAL ;
    SHAPE ABUTMENT ;
    PORT
      LAYER M4 ;
      RECT 0 243.408 0.024 243.432 ;
    END
  END rw0_wd_in[131]
  PIN rw0_wd_in[132]
    DIRECTION INPUT ;
    USE SIGNAL ;
    SHAPE ABUTMENT ;
    PORT
      LAYER M4 ;
      RECT 0 244.656 0.024 244.68 ;
    END
  END rw0_wd_in[132]
  PIN rw0_wd_in[133]
    DIRECTION INPUT ;
    USE SIGNAL ;
    SHAPE ABUTMENT ;
    PORT
      LAYER M4 ;
      RECT 0 245.904 0.024 245.928 ;
    END
  END rw0_wd_in[133]
  PIN rw0_wd_in[134]
    DIRECTION INPUT ;
    USE SIGNAL ;
    SHAPE ABUTMENT ;
    PORT
      LAYER M4 ;
      RECT 0 247.152 0.024 247.176 ;
    END
  END rw0_wd_in[134]
  PIN rw0_wd_in[135]
    DIRECTION INPUT ;
    USE SIGNAL ;
    SHAPE ABUTMENT ;
    PORT
      LAYER M4 ;
      RECT 0 248.4 0.024 248.424 ;
    END
  END rw0_wd_in[135]
  PIN rw0_wd_in[136]
    DIRECTION INPUT ;
    USE SIGNAL ;
    SHAPE ABUTMENT ;
    PORT
      LAYER M4 ;
      RECT 0 249.648 0.024 249.672 ;
    END
  END rw0_wd_in[136]
  PIN rw0_wd_in[137]
    DIRECTION INPUT ;
    USE SIGNAL ;
    SHAPE ABUTMENT ;
    PORT
      LAYER M4 ;
      RECT 0 250.896 0.024 250.92 ;
    END
  END rw0_wd_in[137]
  PIN rw0_wd_in[138]
    DIRECTION INPUT ;
    USE SIGNAL ;
    SHAPE ABUTMENT ;
    PORT
      LAYER M4 ;
      RECT 0 252.144 0.024 252.168 ;
    END
  END rw0_wd_in[138]
  PIN rw0_wd_in[139]
    DIRECTION INPUT ;
    USE SIGNAL ;
    SHAPE ABUTMENT ;
    PORT
      LAYER M4 ;
      RECT 0 253.392 0.024 253.416 ;
    END
  END rw0_wd_in[139]
  PIN rw0_wd_in[140]
    DIRECTION INPUT ;
    USE SIGNAL ;
    SHAPE ABUTMENT ;
    PORT
      LAYER M4 ;
      RECT 0 254.64 0.024 254.664 ;
    END
  END rw0_wd_in[140]
  PIN rw0_wd_in[141]
    DIRECTION INPUT ;
    USE SIGNAL ;
    SHAPE ABUTMENT ;
    PORT
      LAYER M4 ;
      RECT 0 255.888 0.024 255.912 ;
    END
  END rw0_wd_in[141]
  PIN rw0_wd_in[142]
    DIRECTION INPUT ;
    USE SIGNAL ;
    SHAPE ABUTMENT ;
    PORT
      LAYER M4 ;
      RECT 0 257.136 0.024 257.16 ;
    END
  END rw0_wd_in[142]
  PIN rw0_wd_in[143]
    DIRECTION INPUT ;
    USE SIGNAL ;
    SHAPE ABUTMENT ;
    PORT
      LAYER M4 ;
      RECT 0 258.384 0.024 258.408 ;
    END
  END rw0_wd_in[143]
  PIN rw0_wd_in[144]
    DIRECTION INPUT ;
    USE SIGNAL ;
    SHAPE ABUTMENT ;
    PORT
      LAYER M4 ;
      RECT 0 259.632 0.024 259.656 ;
    END
  END rw0_wd_in[144]
  PIN rw0_wd_in[145]
    DIRECTION INPUT ;
    USE SIGNAL ;
    SHAPE ABUTMENT ;
    PORT
      LAYER M4 ;
      RECT 0 260.88 0.024 260.904 ;
    END
  END rw0_wd_in[145]
  PIN rw0_wd_in[146]
    DIRECTION INPUT ;
    USE SIGNAL ;
    SHAPE ABUTMENT ;
    PORT
      LAYER M4 ;
      RECT 0 262.128 0.024 262.152 ;
    END
  END rw0_wd_in[146]
  PIN rw0_wd_in[147]
    DIRECTION INPUT ;
    USE SIGNAL ;
    SHAPE ABUTMENT ;
    PORT
      LAYER M4 ;
      RECT 0 263.376 0.024 263.4 ;
    END
  END rw0_wd_in[147]
  PIN rw0_wd_in[148]
    DIRECTION INPUT ;
    USE SIGNAL ;
    SHAPE ABUTMENT ;
    PORT
      LAYER M4 ;
      RECT 0 264.624 0.024 264.648 ;
    END
  END rw0_wd_in[148]
  PIN rw0_wd_in[149]
    DIRECTION INPUT ;
    USE SIGNAL ;
    SHAPE ABUTMENT ;
    PORT
      LAYER M4 ;
      RECT 0 265.872 0.024 265.896 ;
    END
  END rw0_wd_in[149]
  PIN rw0_wd_in[150]
    DIRECTION INPUT ;
    USE SIGNAL ;
    SHAPE ABUTMENT ;
    PORT
      LAYER M4 ;
      RECT 0 267.12 0.024 267.144 ;
    END
  END rw0_wd_in[150]
  PIN rw0_wd_in[151]
    DIRECTION INPUT ;
    USE SIGNAL ;
    SHAPE ABUTMENT ;
    PORT
      LAYER M4 ;
      RECT 0 268.368 0.024 268.392 ;
    END
  END rw0_wd_in[151]
  PIN rw0_wd_in[152]
    DIRECTION INPUT ;
    USE SIGNAL ;
    SHAPE ABUTMENT ;
    PORT
      LAYER M4 ;
      RECT 0 269.616 0.024 269.64 ;
    END
  END rw0_wd_in[152]
  PIN rw0_wd_in[153]
    DIRECTION INPUT ;
    USE SIGNAL ;
    SHAPE ABUTMENT ;
    PORT
      LAYER M4 ;
      RECT 0 270.864 0.024 270.888 ;
    END
  END rw0_wd_in[153]
  PIN rw0_wd_in[154]
    DIRECTION INPUT ;
    USE SIGNAL ;
    SHAPE ABUTMENT ;
    PORT
      LAYER M4 ;
      RECT 0 272.112 0.024 272.136 ;
    END
  END rw0_wd_in[154]
  PIN rw0_wd_in[155]
    DIRECTION INPUT ;
    USE SIGNAL ;
    SHAPE ABUTMENT ;
    PORT
      LAYER M4 ;
      RECT 0 273.36 0.024 273.384 ;
    END
  END rw0_wd_in[155]
  PIN rw0_wd_in[156]
    DIRECTION INPUT ;
    USE SIGNAL ;
    SHAPE ABUTMENT ;
    PORT
      LAYER M4 ;
      RECT 0 274.608 0.024 274.632 ;
    END
  END rw0_wd_in[156]
  PIN rw0_wd_in[157]
    DIRECTION INPUT ;
    USE SIGNAL ;
    SHAPE ABUTMENT ;
    PORT
      LAYER M4 ;
      RECT 0 275.856 0.024 275.88 ;
    END
  END rw0_wd_in[157]
  PIN rw0_wd_in[158]
    DIRECTION INPUT ;
    USE SIGNAL ;
    SHAPE ABUTMENT ;
    PORT
      LAYER M4 ;
      RECT 0 277.104 0.024 277.128 ;
    END
  END rw0_wd_in[158]
  PIN rw0_wd_in[159]
    DIRECTION INPUT ;
    USE SIGNAL ;
    SHAPE ABUTMENT ;
    PORT
      LAYER M4 ;
      RECT 0 278.352 0.024 278.376 ;
    END
  END rw0_wd_in[159]
  PIN rw0_wd_in[160]
    DIRECTION INPUT ;
    USE SIGNAL ;
    SHAPE ABUTMENT ;
    PORT
      LAYER M4 ;
      RECT 0 279.6 0.024 279.624 ;
    END
  END rw0_wd_in[160]
  PIN rw0_wd_in[161]
    DIRECTION INPUT ;
    USE SIGNAL ;
    SHAPE ABUTMENT ;
    PORT
      LAYER M4 ;
      RECT 0 280.848 0.024 280.872 ;
    END
  END rw0_wd_in[161]
  PIN rw0_wd_in[162]
    DIRECTION INPUT ;
    USE SIGNAL ;
    SHAPE ABUTMENT ;
    PORT
      LAYER M4 ;
      RECT 0 282.096 0.024 282.12 ;
    END
  END rw0_wd_in[162]
  PIN rw0_wd_in[163]
    DIRECTION INPUT ;
    USE SIGNAL ;
    SHAPE ABUTMENT ;
    PORT
      LAYER M4 ;
      RECT 0 283.344 0.024 283.368 ;
    END
  END rw0_wd_in[163]
  PIN rw0_wd_in[164]
    DIRECTION INPUT ;
    USE SIGNAL ;
    SHAPE ABUTMENT ;
    PORT
      LAYER M4 ;
      RECT 0 284.592 0.024 284.616 ;
    END
  END rw0_wd_in[164]
  PIN rw0_wd_in[165]
    DIRECTION INPUT ;
    USE SIGNAL ;
    SHAPE ABUTMENT ;
    PORT
      LAYER M4 ;
      RECT 0 285.84 0.024 285.864 ;
    END
  END rw0_wd_in[165]
  PIN rw0_wd_in[166]
    DIRECTION INPUT ;
    USE SIGNAL ;
    SHAPE ABUTMENT ;
    PORT
      LAYER M4 ;
      RECT 0 287.088 0.024 287.112 ;
    END
  END rw0_wd_in[166]
  PIN rw0_wd_in[167]
    DIRECTION INPUT ;
    USE SIGNAL ;
    SHAPE ABUTMENT ;
    PORT
      LAYER M4 ;
      RECT 0 288.336 0.024 288.36 ;
    END
  END rw0_wd_in[167]
  PIN rw0_wd_in[168]
    DIRECTION INPUT ;
    USE SIGNAL ;
    SHAPE ABUTMENT ;
    PORT
      LAYER M4 ;
      RECT 0 289.584 0.024 289.608 ;
    END
  END rw0_wd_in[168]
  PIN rw0_wd_in[169]
    DIRECTION INPUT ;
    USE SIGNAL ;
    SHAPE ABUTMENT ;
    PORT
      LAYER M4 ;
      RECT 0 290.832 0.024 290.856 ;
    END
  END rw0_wd_in[169]
  PIN rw0_wd_in[170]
    DIRECTION INPUT ;
    USE SIGNAL ;
    SHAPE ABUTMENT ;
    PORT
      LAYER M4 ;
      RECT 0 292.08 0.024 292.104 ;
    END
  END rw0_wd_in[170]
  PIN rw0_wd_in[171]
    DIRECTION INPUT ;
    USE SIGNAL ;
    SHAPE ABUTMENT ;
    PORT
      LAYER M4 ;
      RECT 0 293.328 0.024 293.352 ;
    END
  END rw0_wd_in[171]
  PIN rw0_wd_in[172]
    DIRECTION INPUT ;
    USE SIGNAL ;
    SHAPE ABUTMENT ;
    PORT
      LAYER M4 ;
      RECT 0 294.576 0.024 294.6 ;
    END
  END rw0_wd_in[172]
  PIN rw0_wd_in[173]
    DIRECTION INPUT ;
    USE SIGNAL ;
    SHAPE ABUTMENT ;
    PORT
      LAYER M4 ;
      RECT 0 295.824 0.024 295.848 ;
    END
  END rw0_wd_in[173]
  PIN rw0_wd_in[174]
    DIRECTION INPUT ;
    USE SIGNAL ;
    SHAPE ABUTMENT ;
    PORT
      LAYER M4 ;
      RECT 0 297.072 0.024 297.096 ;
    END
  END rw0_wd_in[174]
  PIN rw0_wd_in[175]
    DIRECTION INPUT ;
    USE SIGNAL ;
    SHAPE ABUTMENT ;
    PORT
      LAYER M4 ;
      RECT 0 298.32 0.024 298.344 ;
    END
  END rw0_wd_in[175]
  PIN rw0_wd_in[176]
    DIRECTION INPUT ;
    USE SIGNAL ;
    SHAPE ABUTMENT ;
    PORT
      LAYER M4 ;
      RECT 0 299.568 0.024 299.592 ;
    END
  END rw0_wd_in[176]
  PIN rw0_wd_in[177]
    DIRECTION INPUT ;
    USE SIGNAL ;
    SHAPE ABUTMENT ;
    PORT
      LAYER M4 ;
      RECT 0 300.816 0.024 300.84 ;
    END
  END rw0_wd_in[177]
  PIN rw0_wd_in[178]
    DIRECTION INPUT ;
    USE SIGNAL ;
    SHAPE ABUTMENT ;
    PORT
      LAYER M4 ;
      RECT 0 302.064 0.024 302.088 ;
    END
  END rw0_wd_in[178]
  PIN rw0_wd_in[179]
    DIRECTION INPUT ;
    USE SIGNAL ;
    SHAPE ABUTMENT ;
    PORT
      LAYER M4 ;
      RECT 0 303.312 0.024 303.336 ;
    END
  END rw0_wd_in[179]
  PIN rw0_wd_in[180]
    DIRECTION INPUT ;
    USE SIGNAL ;
    SHAPE ABUTMENT ;
    PORT
      LAYER M4 ;
      RECT 0 304.56 0.024 304.584 ;
    END
  END rw0_wd_in[180]
  PIN rw0_wd_in[181]
    DIRECTION INPUT ;
    USE SIGNAL ;
    SHAPE ABUTMENT ;
    PORT
      LAYER M4 ;
      RECT 0 305.808 0.024 305.832 ;
    END
  END rw0_wd_in[181]
  PIN rw0_wd_in[182]
    DIRECTION INPUT ;
    USE SIGNAL ;
    SHAPE ABUTMENT ;
    PORT
      LAYER M4 ;
      RECT 0 307.056 0.024 307.08 ;
    END
  END rw0_wd_in[182]
  PIN rw0_wd_in[183]
    DIRECTION INPUT ;
    USE SIGNAL ;
    SHAPE ABUTMENT ;
    PORT
      LAYER M4 ;
      RECT 0 308.304 0.024 308.328 ;
    END
  END rw0_wd_in[183]
  PIN rw0_wd_in[184]
    DIRECTION INPUT ;
    USE SIGNAL ;
    SHAPE ABUTMENT ;
    PORT
      LAYER M4 ;
      RECT 0 309.552 0.024 309.576 ;
    END
  END rw0_wd_in[184]
  PIN rw0_wd_in[185]
    DIRECTION INPUT ;
    USE SIGNAL ;
    SHAPE ABUTMENT ;
    PORT
      LAYER M4 ;
      RECT 0 310.8 0.024 310.824 ;
    END
  END rw0_wd_in[185]
  PIN rw0_wd_in[186]
    DIRECTION INPUT ;
    USE SIGNAL ;
    SHAPE ABUTMENT ;
    PORT
      LAYER M4 ;
      RECT 0 312.048 0.024 312.072 ;
    END
  END rw0_wd_in[186]
  PIN rw0_wd_in[187]
    DIRECTION INPUT ;
    USE SIGNAL ;
    SHAPE ABUTMENT ;
    PORT
      LAYER M4 ;
      RECT 0 313.296 0.024 313.32 ;
    END
  END rw0_wd_in[187]
  PIN rw0_wd_in[188]
    DIRECTION INPUT ;
    USE SIGNAL ;
    SHAPE ABUTMENT ;
    PORT
      LAYER M4 ;
      RECT 0 314.544 0.024 314.568 ;
    END
  END rw0_wd_in[188]
  PIN rw0_wd_in[189]
    DIRECTION INPUT ;
    USE SIGNAL ;
    SHAPE ABUTMENT ;
    PORT
      LAYER M4 ;
      RECT 0 315.792 0.024 315.816 ;
    END
  END rw0_wd_in[189]
  PIN rw0_wd_in[190]
    DIRECTION INPUT ;
    USE SIGNAL ;
    SHAPE ABUTMENT ;
    PORT
      LAYER M4 ;
      RECT 0 317.04 0.024 317.064 ;
    END
  END rw0_wd_in[190]
  PIN rw0_wd_in[191]
    DIRECTION INPUT ;
    USE SIGNAL ;
    SHAPE ABUTMENT ;
    PORT
      LAYER M4 ;
      RECT 0 318.288 0.024 318.312 ;
    END
  END rw0_wd_in[191]
  PIN rw0_wd_in[192]
    DIRECTION INPUT ;
    USE SIGNAL ;
    SHAPE ABUTMENT ;
    PORT
      LAYER M4 ;
      RECT 0 319.536 0.024 319.56 ;
    END
  END rw0_wd_in[192]
  PIN rw0_wd_in[193]
    DIRECTION INPUT ;
    USE SIGNAL ;
    SHAPE ABUTMENT ;
    PORT
      LAYER M4 ;
      RECT 0 320.784 0.024 320.808 ;
    END
  END rw0_wd_in[193]
  PIN rw0_wd_in[194]
    DIRECTION INPUT ;
    USE SIGNAL ;
    SHAPE ABUTMENT ;
    PORT
      LAYER M4 ;
      RECT 0 322.032 0.024 322.056 ;
    END
  END rw0_wd_in[194]
  PIN rw0_wd_in[195]
    DIRECTION INPUT ;
    USE SIGNAL ;
    SHAPE ABUTMENT ;
    PORT
      LAYER M4 ;
      RECT 0 323.28 0.024 323.304 ;
    END
  END rw0_wd_in[195]
  PIN rw0_wd_in[196]
    DIRECTION INPUT ;
    USE SIGNAL ;
    SHAPE ABUTMENT ;
    PORT
      LAYER M4 ;
      RECT 0 324.528 0.024 324.552 ;
    END
  END rw0_wd_in[196]
  PIN rw0_wd_in[197]
    DIRECTION INPUT ;
    USE SIGNAL ;
    SHAPE ABUTMENT ;
    PORT
      LAYER M4 ;
      RECT 0 325.776 0.024 325.8 ;
    END
  END rw0_wd_in[197]
  PIN rw0_wd_in[198]
    DIRECTION INPUT ;
    USE SIGNAL ;
    SHAPE ABUTMENT ;
    PORT
      LAYER M4 ;
      RECT 0 327.024 0.024 327.048 ;
    END
  END rw0_wd_in[198]
  PIN rw0_wd_in[199]
    DIRECTION INPUT ;
    USE SIGNAL ;
    SHAPE ABUTMENT ;
    PORT
      LAYER M4 ;
      RECT 0 328.272 0.024 328.296 ;
    END
  END rw0_wd_in[199]
  PIN rw0_wd_in[200]
    DIRECTION INPUT ;
    USE SIGNAL ;
    SHAPE ABUTMENT ;
    PORT
      LAYER M4 ;
      RECT 0 329.52 0.024 329.544 ;
    END
  END rw0_wd_in[200]
  PIN rw0_wd_in[201]
    DIRECTION INPUT ;
    USE SIGNAL ;
    SHAPE ABUTMENT ;
    PORT
      LAYER M4 ;
      RECT 0 330.768 0.024 330.792 ;
    END
  END rw0_wd_in[201]
  PIN rw0_wd_in[202]
    DIRECTION INPUT ;
    USE SIGNAL ;
    SHAPE ABUTMENT ;
    PORT
      LAYER M4 ;
      RECT 0 332.016 0.024 332.04 ;
    END
  END rw0_wd_in[202]
  PIN rw0_wd_in[203]
    DIRECTION INPUT ;
    USE SIGNAL ;
    SHAPE ABUTMENT ;
    PORT
      LAYER M4 ;
      RECT 0 333.264 0.024 333.288 ;
    END
  END rw0_wd_in[203]
  PIN rw0_wd_in[204]
    DIRECTION INPUT ;
    USE SIGNAL ;
    SHAPE ABUTMENT ;
    PORT
      LAYER M4 ;
      RECT 0 334.512 0.024 334.536 ;
    END
  END rw0_wd_in[204]
  PIN rw0_wd_in[205]
    DIRECTION INPUT ;
    USE SIGNAL ;
    SHAPE ABUTMENT ;
    PORT
      LAYER M4 ;
      RECT 0 335.76 0.024 335.784 ;
    END
  END rw0_wd_in[205]
  PIN rw0_wd_in[206]
    DIRECTION INPUT ;
    USE SIGNAL ;
    SHAPE ABUTMENT ;
    PORT
      LAYER M4 ;
      RECT 0 337.008 0.024 337.032 ;
    END
  END rw0_wd_in[206]
  PIN rw0_wd_in[207]
    DIRECTION INPUT ;
    USE SIGNAL ;
    SHAPE ABUTMENT ;
    PORT
      LAYER M4 ;
      RECT 0 338.256 0.024 338.28 ;
    END
  END rw0_wd_in[207]
  PIN rw0_wd_in[208]
    DIRECTION INPUT ;
    USE SIGNAL ;
    SHAPE ABUTMENT ;
    PORT
      LAYER M4 ;
      RECT 0 339.504 0.024 339.528 ;
    END
  END rw0_wd_in[208]
  PIN rw0_wd_in[209]
    DIRECTION INPUT ;
    USE SIGNAL ;
    SHAPE ABUTMENT ;
    PORT
      LAYER M4 ;
      RECT 0 340.752 0.024 340.776 ;
    END
  END rw0_wd_in[209]
  PIN rw0_wd_in[210]
    DIRECTION INPUT ;
    USE SIGNAL ;
    SHAPE ABUTMENT ;
    PORT
      LAYER M4 ;
      RECT 0 342 0.024 342.024 ;
    END
  END rw0_wd_in[210]
  PIN rw0_wd_in[211]
    DIRECTION INPUT ;
    USE SIGNAL ;
    SHAPE ABUTMENT ;
    PORT
      LAYER M4 ;
      RECT 0 343.248 0.024 343.272 ;
    END
  END rw0_wd_in[211]
  PIN rw0_wd_in[212]
    DIRECTION INPUT ;
    USE SIGNAL ;
    SHAPE ABUTMENT ;
    PORT
      LAYER M4 ;
      RECT 0 344.496 0.024 344.52 ;
    END
  END rw0_wd_in[212]
  PIN rw0_wd_in[213]
    DIRECTION INPUT ;
    USE SIGNAL ;
    SHAPE ABUTMENT ;
    PORT
      LAYER M4 ;
      RECT 0 345.744 0.024 345.768 ;
    END
  END rw0_wd_in[213]
  PIN rw0_wd_in[214]
    DIRECTION INPUT ;
    USE SIGNAL ;
    SHAPE ABUTMENT ;
    PORT
      LAYER M4 ;
      RECT 0 346.992 0.024 347.016 ;
    END
  END rw0_wd_in[214]
  PIN rw0_wd_in[215]
    DIRECTION INPUT ;
    USE SIGNAL ;
    SHAPE ABUTMENT ;
    PORT
      LAYER M4 ;
      RECT 0 348.24 0.024 348.264 ;
    END
  END rw0_wd_in[215]
  PIN rw0_wd_in[216]
    DIRECTION INPUT ;
    USE SIGNAL ;
    SHAPE ABUTMENT ;
    PORT
      LAYER M4 ;
      RECT 0 349.488 0.024 349.512 ;
    END
  END rw0_wd_in[216]
  PIN rw0_wd_in[217]
    DIRECTION INPUT ;
    USE SIGNAL ;
    SHAPE ABUTMENT ;
    PORT
      LAYER M4 ;
      RECT 0 350.736 0.024 350.76 ;
    END
  END rw0_wd_in[217]
  PIN rw0_wd_in[218]
    DIRECTION INPUT ;
    USE SIGNAL ;
    SHAPE ABUTMENT ;
    PORT
      LAYER M4 ;
      RECT 0 351.984 0.024 352.008 ;
    END
  END rw0_wd_in[218]
  PIN rw0_wd_in[219]
    DIRECTION INPUT ;
    USE SIGNAL ;
    SHAPE ABUTMENT ;
    PORT
      LAYER M4 ;
      RECT 0 353.232 0.024 353.256 ;
    END
  END rw0_wd_in[219]
  PIN rw0_wd_in[220]
    DIRECTION INPUT ;
    USE SIGNAL ;
    SHAPE ABUTMENT ;
    PORT
      LAYER M4 ;
      RECT 0 354.48 0.024 354.504 ;
    END
  END rw0_wd_in[220]
  PIN rw0_wd_in[221]
    DIRECTION INPUT ;
    USE SIGNAL ;
    SHAPE ABUTMENT ;
    PORT
      LAYER M4 ;
      RECT 0 355.728 0.024 355.752 ;
    END
  END rw0_wd_in[221]
  PIN rw0_wd_in[222]
    DIRECTION INPUT ;
    USE SIGNAL ;
    SHAPE ABUTMENT ;
    PORT
      LAYER M4 ;
      RECT 0 356.976 0.024 357 ;
    END
  END rw0_wd_in[222]
  PIN rw0_wd_in[223]
    DIRECTION INPUT ;
    USE SIGNAL ;
    SHAPE ABUTMENT ;
    PORT
      LAYER M4 ;
      RECT 0 358.224 0.024 358.248 ;
    END
  END rw0_wd_in[223]
  PIN rw0_wd_in[224]
    DIRECTION INPUT ;
    USE SIGNAL ;
    SHAPE ABUTMENT ;
    PORT
      LAYER M4 ;
      RECT 0 359.472 0.024 359.496 ;
    END
  END rw0_wd_in[224]
  PIN rw0_wd_in[225]
    DIRECTION INPUT ;
    USE SIGNAL ;
    SHAPE ABUTMENT ;
    PORT
      LAYER M4 ;
      RECT 0 360.72 0.024 360.744 ;
    END
  END rw0_wd_in[225]
  PIN rw0_wd_in[226]
    DIRECTION INPUT ;
    USE SIGNAL ;
    SHAPE ABUTMENT ;
    PORT
      LAYER M4 ;
      RECT 0 361.968 0.024 361.992 ;
    END
  END rw0_wd_in[226]
  PIN rw0_wd_in[227]
    DIRECTION INPUT ;
    USE SIGNAL ;
    SHAPE ABUTMENT ;
    PORT
      LAYER M4 ;
      RECT 0 363.216 0.024 363.24 ;
    END
  END rw0_wd_in[227]
  PIN rw0_wd_in[228]
    DIRECTION INPUT ;
    USE SIGNAL ;
    SHAPE ABUTMENT ;
    PORT
      LAYER M4 ;
      RECT 0 364.464 0.024 364.488 ;
    END
  END rw0_wd_in[228]
  PIN rw0_wd_in[229]
    DIRECTION INPUT ;
    USE SIGNAL ;
    SHAPE ABUTMENT ;
    PORT
      LAYER M4 ;
      RECT 0 365.712 0.024 365.736 ;
    END
  END rw0_wd_in[229]
  PIN rw0_wd_in[230]
    DIRECTION INPUT ;
    USE SIGNAL ;
    SHAPE ABUTMENT ;
    PORT
      LAYER M4 ;
      RECT 0 366.96 0.024 366.984 ;
    END
  END rw0_wd_in[230]
  PIN rw0_wd_in[231]
    DIRECTION INPUT ;
    USE SIGNAL ;
    SHAPE ABUTMENT ;
    PORT
      LAYER M4 ;
      RECT 0 368.208 0.024 368.232 ;
    END
  END rw0_wd_in[231]
  PIN rw0_wd_in[232]
    DIRECTION INPUT ;
    USE SIGNAL ;
    SHAPE ABUTMENT ;
    PORT
      LAYER M4 ;
      RECT 0 369.456 0.024 369.48 ;
    END
  END rw0_wd_in[232]
  PIN rw0_wd_in[233]
    DIRECTION INPUT ;
    USE SIGNAL ;
    SHAPE ABUTMENT ;
    PORT
      LAYER M4 ;
      RECT 0 370.704 0.024 370.728 ;
    END
  END rw0_wd_in[233]
  PIN rw0_wd_in[234]
    DIRECTION INPUT ;
    USE SIGNAL ;
    SHAPE ABUTMENT ;
    PORT
      LAYER M4 ;
      RECT 0 371.952 0.024 371.976 ;
    END
  END rw0_wd_in[234]
  PIN rw0_wd_in[235]
    DIRECTION INPUT ;
    USE SIGNAL ;
    SHAPE ABUTMENT ;
    PORT
      LAYER M4 ;
      RECT 0 373.2 0.024 373.224 ;
    END
  END rw0_wd_in[235]
  PIN rw0_wd_in[236]
    DIRECTION INPUT ;
    USE SIGNAL ;
    SHAPE ABUTMENT ;
    PORT
      LAYER M4 ;
      RECT 0 374.448 0.024 374.472 ;
    END
  END rw0_wd_in[236]
  PIN rw0_wd_in[237]
    DIRECTION INPUT ;
    USE SIGNAL ;
    SHAPE ABUTMENT ;
    PORT
      LAYER M4 ;
      RECT 0 375.696 0.024 375.72 ;
    END
  END rw0_wd_in[237]
  PIN rw0_wd_in[238]
    DIRECTION INPUT ;
    USE SIGNAL ;
    SHAPE ABUTMENT ;
    PORT
      LAYER M4 ;
      RECT 0 376.944 0.024 376.968 ;
    END
  END rw0_wd_in[238]
  PIN rw0_wd_in[239]
    DIRECTION INPUT ;
    USE SIGNAL ;
    SHAPE ABUTMENT ;
    PORT
      LAYER M4 ;
      RECT 0 378.192 0.024 378.216 ;
    END
  END rw0_wd_in[239]
  PIN rw0_wd_in[240]
    DIRECTION INPUT ;
    USE SIGNAL ;
    SHAPE ABUTMENT ;
    PORT
      LAYER M4 ;
      RECT 0 379.44 0.024 379.464 ;
    END
  END rw0_wd_in[240]
  PIN rw0_wd_in[241]
    DIRECTION INPUT ;
    USE SIGNAL ;
    SHAPE ABUTMENT ;
    PORT
      LAYER M4 ;
      RECT 0 380.688 0.024 380.712 ;
    END
  END rw0_wd_in[241]
  PIN rw0_wd_in[242]
    DIRECTION INPUT ;
    USE SIGNAL ;
    SHAPE ABUTMENT ;
    PORT
      LAYER M4 ;
      RECT 0 381.936 0.024 381.96 ;
    END
  END rw0_wd_in[242]
  PIN rw0_wd_in[243]
    DIRECTION INPUT ;
    USE SIGNAL ;
    SHAPE ABUTMENT ;
    PORT
      LAYER M4 ;
      RECT 0 383.184 0.024 383.208 ;
    END
  END rw0_wd_in[243]
  PIN rw0_wd_in[244]
    DIRECTION INPUT ;
    USE SIGNAL ;
    SHAPE ABUTMENT ;
    PORT
      LAYER M4 ;
      RECT 0 384.432 0.024 384.456 ;
    END
  END rw0_wd_in[244]
  PIN rw0_wd_in[245]
    DIRECTION INPUT ;
    USE SIGNAL ;
    SHAPE ABUTMENT ;
    PORT
      LAYER M4 ;
      RECT 0 385.68 0.024 385.704 ;
    END
  END rw0_wd_in[245]
  PIN rw0_wd_in[246]
    DIRECTION INPUT ;
    USE SIGNAL ;
    SHAPE ABUTMENT ;
    PORT
      LAYER M4 ;
      RECT 0 386.928 0.024 386.952 ;
    END
  END rw0_wd_in[246]
  PIN rw0_wd_in[247]
    DIRECTION INPUT ;
    USE SIGNAL ;
    SHAPE ABUTMENT ;
    PORT
      LAYER M4 ;
      RECT 0 388.176 0.024 388.2 ;
    END
  END rw0_wd_in[247]
  PIN rw0_wd_in[248]
    DIRECTION INPUT ;
    USE SIGNAL ;
    SHAPE ABUTMENT ;
    PORT
      LAYER M4 ;
      RECT 0 389.424 0.024 389.448 ;
    END
  END rw0_wd_in[248]
  PIN rw0_wd_in[249]
    DIRECTION INPUT ;
    USE SIGNAL ;
    SHAPE ABUTMENT ;
    PORT
      LAYER M4 ;
      RECT 0 390.672 0.024 390.696 ;
    END
  END rw0_wd_in[249]
  PIN rw0_wd_in[250]
    DIRECTION INPUT ;
    USE SIGNAL ;
    SHAPE ABUTMENT ;
    PORT
      LAYER M4 ;
      RECT 0 391.92 0.024 391.944 ;
    END
  END rw0_wd_in[250]
  PIN rw0_wd_in[251]
    DIRECTION INPUT ;
    USE SIGNAL ;
    SHAPE ABUTMENT ;
    PORT
      LAYER M4 ;
      RECT 0 393.168 0.024 393.192 ;
    END
  END rw0_wd_in[251]
  PIN rw0_wd_in[252]
    DIRECTION INPUT ;
    USE SIGNAL ;
    SHAPE ABUTMENT ;
    PORT
      LAYER M4 ;
      RECT 0 394.416 0.024 394.44 ;
    END
  END rw0_wd_in[252]
  PIN rw0_wd_in[253]
    DIRECTION INPUT ;
    USE SIGNAL ;
    SHAPE ABUTMENT ;
    PORT
      LAYER M4 ;
      RECT 0 395.664 0.024 395.688 ;
    END
  END rw0_wd_in[253]
  PIN rw0_wd_in[254]
    DIRECTION INPUT ;
    USE SIGNAL ;
    SHAPE ABUTMENT ;
    PORT
      LAYER M4 ;
      RECT 0 396.912 0.024 396.936 ;
    END
  END rw0_wd_in[254]
  PIN rw0_wd_in[255]
    DIRECTION INPUT ;
    USE SIGNAL ;
    SHAPE ABUTMENT ;
    PORT
      LAYER M4 ;
      RECT 0 398.16 0.024 398.184 ;
    END
  END rw0_wd_in[255]
  PIN rw0_wd_in[256]
    DIRECTION INPUT ;
    USE SIGNAL ;
    SHAPE ABUTMENT ;
    PORT
      LAYER M4 ;
      RECT 0 399.408 0.024 399.432 ;
    END
  END rw0_wd_in[256]
  PIN rw0_wd_in[257]
    DIRECTION INPUT ;
    USE SIGNAL ;
    SHAPE ABUTMENT ;
    PORT
      LAYER M4 ;
      RECT 0 400.656 0.024 400.68 ;
    END
  END rw0_wd_in[257]
  PIN rw0_wd_in[258]
    DIRECTION INPUT ;
    USE SIGNAL ;
    SHAPE ABUTMENT ;
    PORT
      LAYER M4 ;
      RECT 0 401.904 0.024 401.928 ;
    END
  END rw0_wd_in[258]
  PIN rw0_wd_in[259]
    DIRECTION INPUT ;
    USE SIGNAL ;
    SHAPE ABUTMENT ;
    PORT
      LAYER M4 ;
      RECT 0 403.152 0.024 403.176 ;
    END
  END rw0_wd_in[259]
  PIN rw0_wd_in[260]
    DIRECTION INPUT ;
    USE SIGNAL ;
    SHAPE ABUTMENT ;
    PORT
      LAYER M4 ;
      RECT 0 404.4 0.024 404.424 ;
    END
  END rw0_wd_in[260]
  PIN rw0_wd_in[261]
    DIRECTION INPUT ;
    USE SIGNAL ;
    SHAPE ABUTMENT ;
    PORT
      LAYER M4 ;
      RECT 0 405.648 0.024 405.672 ;
    END
  END rw0_wd_in[261]
  PIN rw0_wd_in[262]
    DIRECTION INPUT ;
    USE SIGNAL ;
    SHAPE ABUTMENT ;
    PORT
      LAYER M4 ;
      RECT 0 406.896 0.024 406.92 ;
    END
  END rw0_wd_in[262]
  PIN rw0_wd_in[263]
    DIRECTION INPUT ;
    USE SIGNAL ;
    SHAPE ABUTMENT ;
    PORT
      LAYER M4 ;
      RECT 0 408.144 0.024 408.168 ;
    END
  END rw0_wd_in[263]
  PIN rw0_wd_in[264]
    DIRECTION INPUT ;
    USE SIGNAL ;
    SHAPE ABUTMENT ;
    PORT
      LAYER M4 ;
      RECT 0 409.392 0.024 409.416 ;
    END
  END rw0_wd_in[264]
  PIN rw0_wd_in[265]
    DIRECTION INPUT ;
    USE SIGNAL ;
    SHAPE ABUTMENT ;
    PORT
      LAYER M4 ;
      RECT 0 410.64 0.024 410.664 ;
    END
  END rw0_wd_in[265]
  PIN rw0_wd_in[266]
    DIRECTION INPUT ;
    USE SIGNAL ;
    SHAPE ABUTMENT ;
    PORT
      LAYER M4 ;
      RECT 0 411.888 0.024 411.912 ;
    END
  END rw0_wd_in[266]
  PIN rw0_wd_in[267]
    DIRECTION INPUT ;
    USE SIGNAL ;
    SHAPE ABUTMENT ;
    PORT
      LAYER M4 ;
      RECT 0 413.136 0.024 413.16 ;
    END
  END rw0_wd_in[267]
  PIN rw0_wd_in[268]
    DIRECTION INPUT ;
    USE SIGNAL ;
    SHAPE ABUTMENT ;
    PORT
      LAYER M4 ;
      RECT 0 414.384 0.024 414.408 ;
    END
  END rw0_wd_in[268]
  PIN rw0_wd_in[269]
    DIRECTION INPUT ;
    USE SIGNAL ;
    SHAPE ABUTMENT ;
    PORT
      LAYER M4 ;
      RECT 0 415.632 0.024 415.656 ;
    END
  END rw0_wd_in[269]
  PIN rw0_wd_in[270]
    DIRECTION INPUT ;
    USE SIGNAL ;
    SHAPE ABUTMENT ;
    PORT
      LAYER M4 ;
      RECT 0 416.88 0.024 416.904 ;
    END
  END rw0_wd_in[270]
  PIN rw0_wd_in[271]
    DIRECTION INPUT ;
    USE SIGNAL ;
    SHAPE ABUTMENT ;
    PORT
      LAYER M4 ;
      RECT 0 418.128 0.024 418.152 ;
    END
  END rw0_wd_in[271]
  PIN rw0_wd_in[272]
    DIRECTION INPUT ;
    USE SIGNAL ;
    SHAPE ABUTMENT ;
    PORT
      LAYER M4 ;
      RECT 0 419.376 0.024 419.4 ;
    END
  END rw0_wd_in[272]
  PIN rw0_wd_in[273]
    DIRECTION INPUT ;
    USE SIGNAL ;
    SHAPE ABUTMENT ;
    PORT
      LAYER M4 ;
      RECT 0 420.624 0.024 420.648 ;
    END
  END rw0_wd_in[273]
  PIN rw0_wd_in[274]
    DIRECTION INPUT ;
    USE SIGNAL ;
    SHAPE ABUTMENT ;
    PORT
      LAYER M4 ;
      RECT 0 421.872 0.024 421.896 ;
    END
  END rw0_wd_in[274]
  PIN rw0_wd_in[275]
    DIRECTION INPUT ;
    USE SIGNAL ;
    SHAPE ABUTMENT ;
    PORT
      LAYER M4 ;
      RECT 0 423.12 0.024 423.144 ;
    END
  END rw0_wd_in[275]
  PIN rw0_wd_in[276]
    DIRECTION INPUT ;
    USE SIGNAL ;
    SHAPE ABUTMENT ;
    PORT
      LAYER M4 ;
      RECT 0 424.368 0.024 424.392 ;
    END
  END rw0_wd_in[276]
  PIN rw0_wd_in[277]
    DIRECTION INPUT ;
    USE SIGNAL ;
    SHAPE ABUTMENT ;
    PORT
      LAYER M4 ;
      RECT 0 425.616 0.024 425.64 ;
    END
  END rw0_wd_in[277]
  PIN rw0_wd_in[278]
    DIRECTION INPUT ;
    USE SIGNAL ;
    SHAPE ABUTMENT ;
    PORT
      LAYER M4 ;
      RECT 0 426.864 0.024 426.888 ;
    END
  END rw0_wd_in[278]
  PIN rw0_wd_in[279]
    DIRECTION INPUT ;
    USE SIGNAL ;
    SHAPE ABUTMENT ;
    PORT
      LAYER M4 ;
      RECT 0 428.112 0.024 428.136 ;
    END
  END rw0_wd_in[279]
  PIN rw0_wd_in[280]
    DIRECTION INPUT ;
    USE SIGNAL ;
    SHAPE ABUTMENT ;
    PORT
      LAYER M4 ;
      RECT 0 429.36 0.024 429.384 ;
    END
  END rw0_wd_in[280]
  PIN rw0_wd_in[281]
    DIRECTION INPUT ;
    USE SIGNAL ;
    SHAPE ABUTMENT ;
    PORT
      LAYER M4 ;
      RECT 0 430.608 0.024 430.632 ;
    END
  END rw0_wd_in[281]
  PIN rw0_wd_in[282]
    DIRECTION INPUT ;
    USE SIGNAL ;
    SHAPE ABUTMENT ;
    PORT
      LAYER M4 ;
      RECT 0 431.856 0.024 431.88 ;
    END
  END rw0_wd_in[282]
  PIN rw0_wd_in[283]
    DIRECTION INPUT ;
    USE SIGNAL ;
    SHAPE ABUTMENT ;
    PORT
      LAYER M4 ;
      RECT 0 433.104 0.024 433.128 ;
    END
  END rw0_wd_in[283]
  PIN rw0_wd_in[284]
    DIRECTION INPUT ;
    USE SIGNAL ;
    SHAPE ABUTMENT ;
    PORT
      LAYER M4 ;
      RECT 0 434.352 0.024 434.376 ;
    END
  END rw0_wd_in[284]
  PIN rw0_wd_in[285]
    DIRECTION INPUT ;
    USE SIGNAL ;
    SHAPE ABUTMENT ;
    PORT
      LAYER M4 ;
      RECT 0 435.6 0.024 435.624 ;
    END
  END rw0_wd_in[285]
  PIN rw0_wd_in[286]
    DIRECTION INPUT ;
    USE SIGNAL ;
    SHAPE ABUTMENT ;
    PORT
      LAYER M4 ;
      RECT 0 436.848 0.024 436.872 ;
    END
  END rw0_wd_in[286]
  PIN rw0_wd_in[287]
    DIRECTION INPUT ;
    USE SIGNAL ;
    SHAPE ABUTMENT ;
    PORT
      LAYER M4 ;
      RECT 0 438.096 0.024 438.12 ;
    END
  END rw0_wd_in[287]
  PIN rw0_wd_in[288]
    DIRECTION INPUT ;
    USE SIGNAL ;
    SHAPE ABUTMENT ;
    PORT
      LAYER M4 ;
      RECT 0 439.344 0.024 439.368 ;
    END
  END rw0_wd_in[288]
  PIN rw0_wd_in[289]
    DIRECTION INPUT ;
    USE SIGNAL ;
    SHAPE ABUTMENT ;
    PORT
      LAYER M4 ;
      RECT 0 440.592 0.024 440.616 ;
    END
  END rw0_wd_in[289]
  PIN rw0_wd_in[290]
    DIRECTION INPUT ;
    USE SIGNAL ;
    SHAPE ABUTMENT ;
    PORT
      LAYER M4 ;
      RECT 0 441.84 0.024 441.864 ;
    END
  END rw0_wd_in[290]
  PIN rw0_wd_in[291]
    DIRECTION INPUT ;
    USE SIGNAL ;
    SHAPE ABUTMENT ;
    PORT
      LAYER M4 ;
      RECT 0 443.088 0.024 443.112 ;
    END
  END rw0_wd_in[291]
  PIN rw0_wd_in[292]
    DIRECTION INPUT ;
    USE SIGNAL ;
    SHAPE ABUTMENT ;
    PORT
      LAYER M4 ;
      RECT 0 444.336 0.024 444.36 ;
    END
  END rw0_wd_in[292]
  PIN rw0_wd_in[293]
    DIRECTION INPUT ;
    USE SIGNAL ;
    SHAPE ABUTMENT ;
    PORT
      LAYER M4 ;
      RECT 0 445.584 0.024 445.608 ;
    END
  END rw0_wd_in[293]
  PIN rw0_wd_in[294]
    DIRECTION INPUT ;
    USE SIGNAL ;
    SHAPE ABUTMENT ;
    PORT
      LAYER M4 ;
      RECT 0 446.832 0.024 446.856 ;
    END
  END rw0_wd_in[294]
  PIN rw0_wd_in[295]
    DIRECTION INPUT ;
    USE SIGNAL ;
    SHAPE ABUTMENT ;
    PORT
      LAYER M4 ;
      RECT 0 448.08 0.024 448.104 ;
    END
  END rw0_wd_in[295]
  PIN rw0_wd_in[296]
    DIRECTION INPUT ;
    USE SIGNAL ;
    SHAPE ABUTMENT ;
    PORT
      LAYER M4 ;
      RECT 0 449.328 0.024 449.352 ;
    END
  END rw0_wd_in[296]
  PIN rw0_wd_in[297]
    DIRECTION INPUT ;
    USE SIGNAL ;
    SHAPE ABUTMENT ;
    PORT
      LAYER M4 ;
      RECT 0 450.576 0.024 450.6 ;
    END
  END rw0_wd_in[297]
  PIN rw0_wd_in[298]
    DIRECTION INPUT ;
    USE SIGNAL ;
    SHAPE ABUTMENT ;
    PORT
      LAYER M4 ;
      RECT 0 451.824 0.024 451.848 ;
    END
  END rw0_wd_in[298]
  PIN rw0_wd_in[299]
    DIRECTION INPUT ;
    USE SIGNAL ;
    SHAPE ABUTMENT ;
    PORT
      LAYER M4 ;
      RECT 0 453.072 0.024 453.096 ;
    END
  END rw0_wd_in[299]
  PIN rw0_wd_in[300]
    DIRECTION INPUT ;
    USE SIGNAL ;
    SHAPE ABUTMENT ;
    PORT
      LAYER M4 ;
      RECT 0 454.32 0.024 454.344 ;
    END
  END rw0_wd_in[300]
  PIN rw0_wd_in[301]
    DIRECTION INPUT ;
    USE SIGNAL ;
    SHAPE ABUTMENT ;
    PORT
      LAYER M4 ;
      RECT 0 455.568 0.024 455.592 ;
    END
  END rw0_wd_in[301]
  PIN rw0_wd_in[302]
    DIRECTION INPUT ;
    USE SIGNAL ;
    SHAPE ABUTMENT ;
    PORT
      LAYER M4 ;
      RECT 0 456.816 0.024 456.84 ;
    END
  END rw0_wd_in[302]
  PIN rw0_wd_in[303]
    DIRECTION INPUT ;
    USE SIGNAL ;
    SHAPE ABUTMENT ;
    PORT
      LAYER M4 ;
      RECT 0 458.064 0.024 458.088 ;
    END
  END rw0_wd_in[303]
  PIN rw0_wd_in[304]
    DIRECTION INPUT ;
    USE SIGNAL ;
    SHAPE ABUTMENT ;
    PORT
      LAYER M4 ;
      RECT 0 459.312 0.024 459.336 ;
    END
  END rw0_wd_in[304]
  PIN rw0_wd_in[305]
    DIRECTION INPUT ;
    USE SIGNAL ;
    SHAPE ABUTMENT ;
    PORT
      LAYER M4 ;
      RECT 0 460.56 0.024 460.584 ;
    END
  END rw0_wd_in[305]
  PIN rw0_wd_in[306]
    DIRECTION INPUT ;
    USE SIGNAL ;
    SHAPE ABUTMENT ;
    PORT
      LAYER M4 ;
      RECT 0 461.808 0.024 461.832 ;
    END
  END rw0_wd_in[306]
  PIN rw0_wd_in[307]
    DIRECTION INPUT ;
    USE SIGNAL ;
    SHAPE ABUTMENT ;
    PORT
      LAYER M4 ;
      RECT 0 463.056 0.024 463.08 ;
    END
  END rw0_wd_in[307]
  PIN rw0_wd_in[308]
    DIRECTION INPUT ;
    USE SIGNAL ;
    SHAPE ABUTMENT ;
    PORT
      LAYER M4 ;
      RECT 0 464.304 0.024 464.328 ;
    END
  END rw0_wd_in[308]
  PIN rw0_wd_in[309]
    DIRECTION INPUT ;
    USE SIGNAL ;
    SHAPE ABUTMENT ;
    PORT
      LAYER M4 ;
      RECT 0 465.552 0.024 465.576 ;
    END
  END rw0_wd_in[309]
  PIN rw0_wd_in[310]
    DIRECTION INPUT ;
    USE SIGNAL ;
    SHAPE ABUTMENT ;
    PORT
      LAYER M4 ;
      RECT 0 466.8 0.024 466.824 ;
    END
  END rw0_wd_in[310]
  PIN rw0_wd_in[311]
    DIRECTION INPUT ;
    USE SIGNAL ;
    SHAPE ABUTMENT ;
    PORT
      LAYER M4 ;
      RECT 0 468.048 0.024 468.072 ;
    END
  END rw0_wd_in[311]
  PIN rw0_wd_in[312]
    DIRECTION INPUT ;
    USE SIGNAL ;
    SHAPE ABUTMENT ;
    PORT
      LAYER M4 ;
      RECT 0 469.296 0.024 469.32 ;
    END
  END rw0_wd_in[312]
  PIN rw0_wd_in[313]
    DIRECTION INPUT ;
    USE SIGNAL ;
    SHAPE ABUTMENT ;
    PORT
      LAYER M4 ;
      RECT 0 470.544 0.024 470.568 ;
    END
  END rw0_wd_in[313]
  PIN rw0_wd_in[314]
    DIRECTION INPUT ;
    USE SIGNAL ;
    SHAPE ABUTMENT ;
    PORT
      LAYER M4 ;
      RECT 0 471.792 0.024 471.816 ;
    END
  END rw0_wd_in[314]
  PIN rw0_wd_in[315]
    DIRECTION INPUT ;
    USE SIGNAL ;
    SHAPE ABUTMENT ;
    PORT
      LAYER M4 ;
      RECT 0 473.04 0.024 473.064 ;
    END
  END rw0_wd_in[315]
  PIN rw0_wd_in[316]
    DIRECTION INPUT ;
    USE SIGNAL ;
    SHAPE ABUTMENT ;
    PORT
      LAYER M4 ;
      RECT 0 474.288 0.024 474.312 ;
    END
  END rw0_wd_in[316]
  PIN rw0_wd_in[317]
    DIRECTION INPUT ;
    USE SIGNAL ;
    SHAPE ABUTMENT ;
    PORT
      LAYER M4 ;
      RECT 0 475.536 0.024 475.56 ;
    END
  END rw0_wd_in[317]
  PIN rw0_wd_in[318]
    DIRECTION INPUT ;
    USE SIGNAL ;
    SHAPE ABUTMENT ;
    PORT
      LAYER M4 ;
      RECT 0 476.784 0.024 476.808 ;
    END
  END rw0_wd_in[318]
  PIN rw0_wd_in[319]
    DIRECTION INPUT ;
    USE SIGNAL ;
    SHAPE ABUTMENT ;
    PORT
      LAYER M4 ;
      RECT 0 478.032 0.024 478.056 ;
    END
  END rw0_wd_in[319]
  PIN rw0_wd_in[320]
    DIRECTION INPUT ;
    USE SIGNAL ;
    SHAPE ABUTMENT ;
    PORT
      LAYER M4 ;
      RECT 0 479.28 0.024 479.304 ;
    END
  END rw0_wd_in[320]
  PIN rw0_wd_in[321]
    DIRECTION INPUT ;
    USE SIGNAL ;
    SHAPE ABUTMENT ;
    PORT
      LAYER M4 ;
      RECT 0 480.528 0.024 480.552 ;
    END
  END rw0_wd_in[321]
  PIN rw0_wd_in[322]
    DIRECTION INPUT ;
    USE SIGNAL ;
    SHAPE ABUTMENT ;
    PORT
      LAYER M4 ;
      RECT 0 481.776 0.024 481.8 ;
    END
  END rw0_wd_in[322]
  PIN rw0_wd_in[323]
    DIRECTION INPUT ;
    USE SIGNAL ;
    SHAPE ABUTMENT ;
    PORT
      LAYER M4 ;
      RECT 0 483.024 0.024 483.048 ;
    END
  END rw0_wd_in[323]
  PIN rw0_wd_in[324]
    DIRECTION INPUT ;
    USE SIGNAL ;
    SHAPE ABUTMENT ;
    PORT
      LAYER M4 ;
      RECT 0 484.272 0.024 484.296 ;
    END
  END rw0_wd_in[324]
  PIN rw0_wd_in[325]
    DIRECTION INPUT ;
    USE SIGNAL ;
    SHAPE ABUTMENT ;
    PORT
      LAYER M4 ;
      RECT 0 485.52 0.024 485.544 ;
    END
  END rw0_wd_in[325]
  PIN rw0_wd_in[326]
    DIRECTION INPUT ;
    USE SIGNAL ;
    SHAPE ABUTMENT ;
    PORT
      LAYER M4 ;
      RECT 0 486.768 0.024 486.792 ;
    END
  END rw0_wd_in[326]
  PIN rw0_wd_in[327]
    DIRECTION INPUT ;
    USE SIGNAL ;
    SHAPE ABUTMENT ;
    PORT
      LAYER M4 ;
      RECT 0 488.016 0.024 488.04 ;
    END
  END rw0_wd_in[327]
  PIN rw0_wd_in[328]
    DIRECTION INPUT ;
    USE SIGNAL ;
    SHAPE ABUTMENT ;
    PORT
      LAYER M4 ;
      RECT 0 489.264 0.024 489.288 ;
    END
  END rw0_wd_in[328]
  PIN rw0_wd_in[329]
    DIRECTION INPUT ;
    USE SIGNAL ;
    SHAPE ABUTMENT ;
    PORT
      LAYER M4 ;
      RECT 0 490.512 0.024 490.536 ;
    END
  END rw0_wd_in[329]
  PIN rw0_wd_in[330]
    DIRECTION INPUT ;
    USE SIGNAL ;
    SHAPE ABUTMENT ;
    PORT
      LAYER M4 ;
      RECT 0 491.76 0.024 491.784 ;
    END
  END rw0_wd_in[330]
  PIN rw0_wd_in[331]
    DIRECTION INPUT ;
    USE SIGNAL ;
    SHAPE ABUTMENT ;
    PORT
      LAYER M4 ;
      RECT 0 493.008 0.024 493.032 ;
    END
  END rw0_wd_in[331]
  PIN rw0_wd_in[332]
    DIRECTION INPUT ;
    USE SIGNAL ;
    SHAPE ABUTMENT ;
    PORT
      LAYER M4 ;
      RECT 0 494.256 0.024 494.28 ;
    END
  END rw0_wd_in[332]
  PIN rw0_wd_in[333]
    DIRECTION INPUT ;
    USE SIGNAL ;
    SHAPE ABUTMENT ;
    PORT
      LAYER M4 ;
      RECT 0 495.504 0.024 495.528 ;
    END
  END rw0_wd_in[333]
  PIN rw0_wd_in[334]
    DIRECTION INPUT ;
    USE SIGNAL ;
    SHAPE ABUTMENT ;
    PORT
      LAYER M4 ;
      RECT 0 496.752 0.024 496.776 ;
    END
  END rw0_wd_in[334]
  PIN rw0_wd_in[335]
    DIRECTION INPUT ;
    USE SIGNAL ;
    SHAPE ABUTMENT ;
    PORT
      LAYER M4 ;
      RECT 0 498 0.024 498.024 ;
    END
  END rw0_wd_in[335]
  PIN rw0_wd_in[336]
    DIRECTION INPUT ;
    USE SIGNAL ;
    SHAPE ABUTMENT ;
    PORT
      LAYER M4 ;
      RECT 0 499.248 0.024 499.272 ;
    END
  END rw0_wd_in[336]
  PIN rw0_wd_in[337]
    DIRECTION INPUT ;
    USE SIGNAL ;
    SHAPE ABUTMENT ;
    PORT
      LAYER M4 ;
      RECT 0 500.496 0.024 500.52 ;
    END
  END rw0_wd_in[337]
  PIN rw0_wd_in[338]
    DIRECTION INPUT ;
    USE SIGNAL ;
    SHAPE ABUTMENT ;
    PORT
      LAYER M4 ;
      RECT 0 501.744 0.024 501.768 ;
    END
  END rw0_wd_in[338]
  PIN rw0_wd_in[339]
    DIRECTION INPUT ;
    USE SIGNAL ;
    SHAPE ABUTMENT ;
    PORT
      LAYER M4 ;
      RECT 0 502.992 0.024 503.016 ;
    END
  END rw0_wd_in[339]
  PIN rw0_wd_in[340]
    DIRECTION INPUT ;
    USE SIGNAL ;
    SHAPE ABUTMENT ;
    PORT
      LAYER M4 ;
      RECT 0 504.24 0.024 504.264 ;
    END
  END rw0_wd_in[340]
  PIN rw0_wd_in[341]
    DIRECTION INPUT ;
    USE SIGNAL ;
    SHAPE ABUTMENT ;
    PORT
      LAYER M4 ;
      RECT 0 505.488 0.024 505.512 ;
    END
  END rw0_wd_in[341]
  PIN rw0_wd_in[342]
    DIRECTION INPUT ;
    USE SIGNAL ;
    SHAPE ABUTMENT ;
    PORT
      LAYER M4 ;
      RECT 0 506.736 0.024 506.76 ;
    END
  END rw0_wd_in[342]
  PIN rw0_wd_in[343]
    DIRECTION INPUT ;
    USE SIGNAL ;
    SHAPE ABUTMENT ;
    PORT
      LAYER M4 ;
      RECT 0 507.984 0.024 508.008 ;
    END
  END rw0_wd_in[343]
  PIN rw0_wd_in[344]
    DIRECTION INPUT ;
    USE SIGNAL ;
    SHAPE ABUTMENT ;
    PORT
      LAYER M4 ;
      RECT 0 509.232 0.024 509.256 ;
    END
  END rw0_wd_in[344]
  PIN rw0_wd_in[345]
    DIRECTION INPUT ;
    USE SIGNAL ;
    SHAPE ABUTMENT ;
    PORT
      LAYER M4 ;
      RECT 0 510.48 0.024 510.504 ;
    END
  END rw0_wd_in[345]
  PIN rw0_wd_in[346]
    DIRECTION INPUT ;
    USE SIGNAL ;
    SHAPE ABUTMENT ;
    PORT
      LAYER M4 ;
      RECT 0 511.728 0.024 511.752 ;
    END
  END rw0_wd_in[346]
  PIN rw0_wd_in[347]
    DIRECTION INPUT ;
    USE SIGNAL ;
    SHAPE ABUTMENT ;
    PORT
      LAYER M4 ;
      RECT 0 512.976 0.024 513 ;
    END
  END rw0_wd_in[347]
  PIN rw0_wd_in[348]
    DIRECTION INPUT ;
    USE SIGNAL ;
    SHAPE ABUTMENT ;
    PORT
      LAYER M4 ;
      RECT 0 514.224 0.024 514.248 ;
    END
  END rw0_wd_in[348]
  PIN rw0_wd_in[349]
    DIRECTION INPUT ;
    USE SIGNAL ;
    SHAPE ABUTMENT ;
    PORT
      LAYER M4 ;
      RECT 0 515.472 0.024 515.496 ;
    END
  END rw0_wd_in[349]
  PIN rw0_wd_in[350]
    DIRECTION INPUT ;
    USE SIGNAL ;
    SHAPE ABUTMENT ;
    PORT
      LAYER M4 ;
      RECT 0 516.72 0.024 516.744 ;
    END
  END rw0_wd_in[350]
  PIN rw0_wd_in[351]
    DIRECTION INPUT ;
    USE SIGNAL ;
    SHAPE ABUTMENT ;
    PORT
      LAYER M4 ;
      RECT 0 517.968 0.024 517.992 ;
    END
  END rw0_wd_in[351]
  PIN rw0_wd_in[352]
    DIRECTION INPUT ;
    USE SIGNAL ;
    SHAPE ABUTMENT ;
    PORT
      LAYER M4 ;
      RECT 0 519.216 0.024 519.24 ;
    END
  END rw0_wd_in[352]
  PIN rw0_wd_in[353]
    DIRECTION INPUT ;
    USE SIGNAL ;
    SHAPE ABUTMENT ;
    PORT
      LAYER M4 ;
      RECT 0 520.464 0.024 520.488 ;
    END
  END rw0_wd_in[353]
  PIN rw0_wd_in[354]
    DIRECTION INPUT ;
    USE SIGNAL ;
    SHAPE ABUTMENT ;
    PORT
      LAYER M4 ;
      RECT 0 521.712 0.024 521.736 ;
    END
  END rw0_wd_in[354]
  PIN rw0_wd_in[355]
    DIRECTION INPUT ;
    USE SIGNAL ;
    SHAPE ABUTMENT ;
    PORT
      LAYER M4 ;
      RECT 0 522.96 0.024 522.984 ;
    END
  END rw0_wd_in[355]
  PIN rw0_wd_in[356]
    DIRECTION INPUT ;
    USE SIGNAL ;
    SHAPE ABUTMENT ;
    PORT
      LAYER M4 ;
      RECT 0 524.208 0.024 524.232 ;
    END
  END rw0_wd_in[356]
  PIN rw0_wd_in[357]
    DIRECTION INPUT ;
    USE SIGNAL ;
    SHAPE ABUTMENT ;
    PORT
      LAYER M4 ;
      RECT 0 525.456 0.024 525.48 ;
    END
  END rw0_wd_in[357]
  PIN rw0_wd_in[358]
    DIRECTION INPUT ;
    USE SIGNAL ;
    SHAPE ABUTMENT ;
    PORT
      LAYER M4 ;
      RECT 0 526.704 0.024 526.728 ;
    END
  END rw0_wd_in[358]
  PIN rw0_wd_in[359]
    DIRECTION INPUT ;
    USE SIGNAL ;
    SHAPE ABUTMENT ;
    PORT
      LAYER M4 ;
      RECT 0 527.952 0.024 527.976 ;
    END
  END rw0_wd_in[359]
  PIN rw0_wd_in[360]
    DIRECTION INPUT ;
    USE SIGNAL ;
    SHAPE ABUTMENT ;
    PORT
      LAYER M4 ;
      RECT 0 529.2 0.024 529.224 ;
    END
  END rw0_wd_in[360]
  PIN rw0_wd_in[361]
    DIRECTION INPUT ;
    USE SIGNAL ;
    SHAPE ABUTMENT ;
    PORT
      LAYER M4 ;
      RECT 0 530.448 0.024 530.472 ;
    END
  END rw0_wd_in[361]
  PIN rw0_wd_in[362]
    DIRECTION INPUT ;
    USE SIGNAL ;
    SHAPE ABUTMENT ;
    PORT
      LAYER M4 ;
      RECT 0 531.696 0.024 531.72 ;
    END
  END rw0_wd_in[362]
  PIN rw0_wd_in[363]
    DIRECTION INPUT ;
    USE SIGNAL ;
    SHAPE ABUTMENT ;
    PORT
      LAYER M4 ;
      RECT 0 532.944 0.024 532.968 ;
    END
  END rw0_wd_in[363]
  PIN rw0_wd_in[364]
    DIRECTION INPUT ;
    USE SIGNAL ;
    SHAPE ABUTMENT ;
    PORT
      LAYER M4 ;
      RECT 0 534.192 0.024 534.216 ;
    END
  END rw0_wd_in[364]
  PIN rw0_wd_in[365]
    DIRECTION INPUT ;
    USE SIGNAL ;
    SHAPE ABUTMENT ;
    PORT
      LAYER M4 ;
      RECT 0 535.44 0.024 535.464 ;
    END
  END rw0_wd_in[365]
  PIN rw0_wd_in[366]
    DIRECTION INPUT ;
    USE SIGNAL ;
    SHAPE ABUTMENT ;
    PORT
      LAYER M4 ;
      RECT 0 536.688 0.024 536.712 ;
    END
  END rw0_wd_in[366]
  PIN rw0_wd_in[367]
    DIRECTION INPUT ;
    USE SIGNAL ;
    SHAPE ABUTMENT ;
    PORT
      LAYER M4 ;
      RECT 0 537.936 0.024 537.96 ;
    END
  END rw0_wd_in[367]
  PIN rw0_wd_in[368]
    DIRECTION INPUT ;
    USE SIGNAL ;
    SHAPE ABUTMENT ;
    PORT
      LAYER M4 ;
      RECT 0 539.184 0.024 539.208 ;
    END
  END rw0_wd_in[368]
  PIN rw0_wd_in[369]
    DIRECTION INPUT ;
    USE SIGNAL ;
    SHAPE ABUTMENT ;
    PORT
      LAYER M4 ;
      RECT 0 540.432 0.024 540.456 ;
    END
  END rw0_wd_in[369]
  PIN rw0_wd_in[370]
    DIRECTION INPUT ;
    USE SIGNAL ;
    SHAPE ABUTMENT ;
    PORT
      LAYER M4 ;
      RECT 0 541.68 0.024 541.704 ;
    END
  END rw0_wd_in[370]
  PIN rw0_wd_in[371]
    DIRECTION INPUT ;
    USE SIGNAL ;
    SHAPE ABUTMENT ;
    PORT
      LAYER M4 ;
      RECT 0 542.928 0.024 542.952 ;
    END
  END rw0_wd_in[371]
  PIN rw0_wd_in[372]
    DIRECTION INPUT ;
    USE SIGNAL ;
    SHAPE ABUTMENT ;
    PORT
      LAYER M4 ;
      RECT 0 544.176 0.024 544.2 ;
    END
  END rw0_wd_in[372]
  PIN rw0_wd_in[373]
    DIRECTION INPUT ;
    USE SIGNAL ;
    SHAPE ABUTMENT ;
    PORT
      LAYER M4 ;
      RECT 0 545.424 0.024 545.448 ;
    END
  END rw0_wd_in[373]
  PIN rw0_wd_in[374]
    DIRECTION INPUT ;
    USE SIGNAL ;
    SHAPE ABUTMENT ;
    PORT
      LAYER M4 ;
      RECT 0 546.672 0.024 546.696 ;
    END
  END rw0_wd_in[374]
  PIN rw0_wd_in[375]
    DIRECTION INPUT ;
    USE SIGNAL ;
    SHAPE ABUTMENT ;
    PORT
      LAYER M4 ;
      RECT 0 547.92 0.024 547.944 ;
    END
  END rw0_wd_in[375]
  PIN rw0_wd_in[376]
    DIRECTION INPUT ;
    USE SIGNAL ;
    SHAPE ABUTMENT ;
    PORT
      LAYER M4 ;
      RECT 0 549.168 0.024 549.192 ;
    END
  END rw0_wd_in[376]
  PIN rw0_wd_in[377]
    DIRECTION INPUT ;
    USE SIGNAL ;
    SHAPE ABUTMENT ;
    PORT
      LAYER M4 ;
      RECT 0 550.416 0.024 550.44 ;
    END
  END rw0_wd_in[377]
  PIN rw0_wd_in[378]
    DIRECTION INPUT ;
    USE SIGNAL ;
    SHAPE ABUTMENT ;
    PORT
      LAYER M4 ;
      RECT 0 551.664 0.024 551.688 ;
    END
  END rw0_wd_in[378]
  PIN rw0_wd_in[379]
    DIRECTION INPUT ;
    USE SIGNAL ;
    SHAPE ABUTMENT ;
    PORT
      LAYER M4 ;
      RECT 0 552.912 0.024 552.936 ;
    END
  END rw0_wd_in[379]
  PIN rw0_wd_in[380]
    DIRECTION INPUT ;
    USE SIGNAL ;
    SHAPE ABUTMENT ;
    PORT
      LAYER M4 ;
      RECT 0 554.16 0.024 554.184 ;
    END
  END rw0_wd_in[380]
  PIN rw0_wd_in[381]
    DIRECTION INPUT ;
    USE SIGNAL ;
    SHAPE ABUTMENT ;
    PORT
      LAYER M4 ;
      RECT 0 555.408 0.024 555.432 ;
    END
  END rw0_wd_in[381]
  PIN rw0_wd_in[382]
    DIRECTION INPUT ;
    USE SIGNAL ;
    SHAPE ABUTMENT ;
    PORT
      LAYER M4 ;
      RECT 0 556.656 0.024 556.68 ;
    END
  END rw0_wd_in[382]
  PIN rw0_wd_in[383]
    DIRECTION INPUT ;
    USE SIGNAL ;
    SHAPE ABUTMENT ;
    PORT
      LAYER M4 ;
      RECT 0 557.904 0.024 557.928 ;
    END
  END rw0_wd_in[383]
  PIN rw0_wd_in[384]
    DIRECTION INPUT ;
    USE SIGNAL ;
    SHAPE ABUTMENT ;
    PORT
      LAYER M4 ;
      RECT 0 559.152 0.024 559.176 ;
    END
  END rw0_wd_in[384]
  PIN rw0_wd_in[385]
    DIRECTION INPUT ;
    USE SIGNAL ;
    SHAPE ABUTMENT ;
    PORT
      LAYER M4 ;
      RECT 0 560.4 0.024 560.424 ;
    END
  END rw0_wd_in[385]
  PIN rw0_wd_in[386]
    DIRECTION INPUT ;
    USE SIGNAL ;
    SHAPE ABUTMENT ;
    PORT
      LAYER M4 ;
      RECT 0 561.648 0.024 561.672 ;
    END
  END rw0_wd_in[386]
  PIN rw0_wd_in[387]
    DIRECTION INPUT ;
    USE SIGNAL ;
    SHAPE ABUTMENT ;
    PORT
      LAYER M4 ;
      RECT 0 562.896 0.024 562.92 ;
    END
  END rw0_wd_in[387]
  PIN rw0_wd_in[388]
    DIRECTION INPUT ;
    USE SIGNAL ;
    SHAPE ABUTMENT ;
    PORT
      LAYER M4 ;
      RECT 0 564.144 0.024 564.168 ;
    END
  END rw0_wd_in[388]
  PIN rw0_wd_in[389]
    DIRECTION INPUT ;
    USE SIGNAL ;
    SHAPE ABUTMENT ;
    PORT
      LAYER M4 ;
      RECT 0 565.392 0.024 565.416 ;
    END
  END rw0_wd_in[389]
  PIN rw0_wd_in[390]
    DIRECTION INPUT ;
    USE SIGNAL ;
    SHAPE ABUTMENT ;
    PORT
      LAYER M4 ;
      RECT 0 566.64 0.024 566.664 ;
    END
  END rw0_wd_in[390]
  PIN rw0_wd_in[391]
    DIRECTION INPUT ;
    USE SIGNAL ;
    SHAPE ABUTMENT ;
    PORT
      LAYER M4 ;
      RECT 0 567.888 0.024 567.912 ;
    END
  END rw0_wd_in[391]
  PIN rw0_wd_in[392]
    DIRECTION INPUT ;
    USE SIGNAL ;
    SHAPE ABUTMENT ;
    PORT
      LAYER M4 ;
      RECT 0 569.136 0.024 569.16 ;
    END
  END rw0_wd_in[392]
  PIN rw0_wd_in[393]
    DIRECTION INPUT ;
    USE SIGNAL ;
    SHAPE ABUTMENT ;
    PORT
      LAYER M4 ;
      RECT 0 570.384 0.024 570.408 ;
    END
  END rw0_wd_in[393]
  PIN rw0_wd_in[394]
    DIRECTION INPUT ;
    USE SIGNAL ;
    SHAPE ABUTMENT ;
    PORT
      LAYER M4 ;
      RECT 0 571.632 0.024 571.656 ;
    END
  END rw0_wd_in[394]
  PIN rw0_wd_in[395]
    DIRECTION INPUT ;
    USE SIGNAL ;
    SHAPE ABUTMENT ;
    PORT
      LAYER M4 ;
      RECT 0 572.88 0.024 572.904 ;
    END
  END rw0_wd_in[395]
  PIN rw0_wd_in[396]
    DIRECTION INPUT ;
    USE SIGNAL ;
    SHAPE ABUTMENT ;
    PORT
      LAYER M4 ;
      RECT 0 574.128 0.024 574.152 ;
    END
  END rw0_wd_in[396]
  PIN rw0_wd_in[397]
    DIRECTION INPUT ;
    USE SIGNAL ;
    SHAPE ABUTMENT ;
    PORT
      LAYER M4 ;
      RECT 0 575.376 0.024 575.4 ;
    END
  END rw0_wd_in[397]
  PIN rw0_wd_in[398]
    DIRECTION INPUT ;
    USE SIGNAL ;
    SHAPE ABUTMENT ;
    PORT
      LAYER M4 ;
      RECT 0 576.624 0.024 576.648 ;
    END
  END rw0_wd_in[398]
  PIN rw0_wd_in[399]
    DIRECTION INPUT ;
    USE SIGNAL ;
    SHAPE ABUTMENT ;
    PORT
      LAYER M4 ;
      RECT 0 577.872 0.024 577.896 ;
    END
  END rw0_wd_in[399]
  PIN rw0_wd_in[400]
    DIRECTION INPUT ;
    USE SIGNAL ;
    SHAPE ABUTMENT ;
    PORT
      LAYER M4 ;
      RECT 0 579.12 0.024 579.144 ;
    END
  END rw0_wd_in[400]
  PIN rw0_wd_in[401]
    DIRECTION INPUT ;
    USE SIGNAL ;
    SHAPE ABUTMENT ;
    PORT
      LAYER M4 ;
      RECT 0 580.368 0.024 580.392 ;
    END
  END rw0_wd_in[401]
  PIN rw0_wd_in[402]
    DIRECTION INPUT ;
    USE SIGNAL ;
    SHAPE ABUTMENT ;
    PORT
      LAYER M4 ;
      RECT 0 581.616 0.024 581.64 ;
    END
  END rw0_wd_in[402]
  PIN rw0_wd_in[403]
    DIRECTION INPUT ;
    USE SIGNAL ;
    SHAPE ABUTMENT ;
    PORT
      LAYER M4 ;
      RECT 0 582.864 0.024 582.888 ;
    END
  END rw0_wd_in[403]
  PIN rw0_wd_in[404]
    DIRECTION INPUT ;
    USE SIGNAL ;
    SHAPE ABUTMENT ;
    PORT
      LAYER M4 ;
      RECT 0 584.112 0.024 584.136 ;
    END
  END rw0_wd_in[404]
  PIN rw0_wd_in[405]
    DIRECTION INPUT ;
    USE SIGNAL ;
    SHAPE ABUTMENT ;
    PORT
      LAYER M4 ;
      RECT 0 585.36 0.024 585.384 ;
    END
  END rw0_wd_in[405]
  PIN rw0_wd_in[406]
    DIRECTION INPUT ;
    USE SIGNAL ;
    SHAPE ABUTMENT ;
    PORT
      LAYER M4 ;
      RECT 0 586.608 0.024 586.632 ;
    END
  END rw0_wd_in[406]
  PIN rw0_wd_in[407]
    DIRECTION INPUT ;
    USE SIGNAL ;
    SHAPE ABUTMENT ;
    PORT
      LAYER M4 ;
      RECT 0 587.856 0.024 587.88 ;
    END
  END rw0_wd_in[407]
  PIN rw0_wd_in[408]
    DIRECTION INPUT ;
    USE SIGNAL ;
    SHAPE ABUTMENT ;
    PORT
      LAYER M4 ;
      RECT 0 589.104 0.024 589.128 ;
    END
  END rw0_wd_in[408]
  PIN rw0_wd_in[409]
    DIRECTION INPUT ;
    USE SIGNAL ;
    SHAPE ABUTMENT ;
    PORT
      LAYER M4 ;
      RECT 0 590.352 0.024 590.376 ;
    END
  END rw0_wd_in[409]
  PIN rw0_wd_in[410]
    DIRECTION INPUT ;
    USE SIGNAL ;
    SHAPE ABUTMENT ;
    PORT
      LAYER M4 ;
      RECT 0 591.6 0.024 591.624 ;
    END
  END rw0_wd_in[410]
  PIN rw0_wd_in[411]
    DIRECTION INPUT ;
    USE SIGNAL ;
    SHAPE ABUTMENT ;
    PORT
      LAYER M4 ;
      RECT 0 592.848 0.024 592.872 ;
    END
  END rw0_wd_in[411]
  PIN rw0_wd_in[412]
    DIRECTION INPUT ;
    USE SIGNAL ;
    SHAPE ABUTMENT ;
    PORT
      LAYER M4 ;
      RECT 0 594.096 0.024 594.12 ;
    END
  END rw0_wd_in[412]
  PIN rw0_wd_in[413]
    DIRECTION INPUT ;
    USE SIGNAL ;
    SHAPE ABUTMENT ;
    PORT
      LAYER M4 ;
      RECT 0 595.344 0.024 595.368 ;
    END
  END rw0_wd_in[413]
  PIN rw0_wd_in[414]
    DIRECTION INPUT ;
    USE SIGNAL ;
    SHAPE ABUTMENT ;
    PORT
      LAYER M4 ;
      RECT 0 596.592 0.024 596.616 ;
    END
  END rw0_wd_in[414]
  PIN rw0_wd_in[415]
    DIRECTION INPUT ;
    USE SIGNAL ;
    SHAPE ABUTMENT ;
    PORT
      LAYER M4 ;
      RECT 0 597.84 0.024 597.864 ;
    END
  END rw0_wd_in[415]
  PIN rw0_wd_in[416]
    DIRECTION INPUT ;
    USE SIGNAL ;
    SHAPE ABUTMENT ;
    PORT
      LAYER M4 ;
      RECT 0 599.088 0.024 599.112 ;
    END
  END rw0_wd_in[416]
  PIN rw0_wd_in[417]
    DIRECTION INPUT ;
    USE SIGNAL ;
    SHAPE ABUTMENT ;
    PORT
      LAYER M4 ;
      RECT 0 600.336 0.024 600.36 ;
    END
  END rw0_wd_in[417]
  PIN rw0_wd_in[418]
    DIRECTION INPUT ;
    USE SIGNAL ;
    SHAPE ABUTMENT ;
    PORT
      LAYER M4 ;
      RECT 0 601.584 0.024 601.608 ;
    END
  END rw0_wd_in[418]
  PIN rw0_wd_in[419]
    DIRECTION INPUT ;
    USE SIGNAL ;
    SHAPE ABUTMENT ;
    PORT
      LAYER M4 ;
      RECT 0 602.832 0.024 602.856 ;
    END
  END rw0_wd_in[419]
  PIN rw0_wd_in[420]
    DIRECTION INPUT ;
    USE SIGNAL ;
    SHAPE ABUTMENT ;
    PORT
      LAYER M4 ;
      RECT 0 604.08 0.024 604.104 ;
    END
  END rw0_wd_in[420]
  PIN rw0_wd_in[421]
    DIRECTION INPUT ;
    USE SIGNAL ;
    SHAPE ABUTMENT ;
    PORT
      LAYER M4 ;
      RECT 0 605.328 0.024 605.352 ;
    END
  END rw0_wd_in[421]
  PIN rw0_wd_in[422]
    DIRECTION INPUT ;
    USE SIGNAL ;
    SHAPE ABUTMENT ;
    PORT
      LAYER M4 ;
      RECT 0 606.576 0.024 606.6 ;
    END
  END rw0_wd_in[422]
  PIN rw0_wd_in[423]
    DIRECTION INPUT ;
    USE SIGNAL ;
    SHAPE ABUTMENT ;
    PORT
      LAYER M4 ;
      RECT 0 607.824 0.024 607.848 ;
    END
  END rw0_wd_in[423]
  PIN rw0_wd_in[424]
    DIRECTION INPUT ;
    USE SIGNAL ;
    SHAPE ABUTMENT ;
    PORT
      LAYER M4 ;
      RECT 0 609.072 0.024 609.096 ;
    END
  END rw0_wd_in[424]
  PIN rw0_wd_in[425]
    DIRECTION INPUT ;
    USE SIGNAL ;
    SHAPE ABUTMENT ;
    PORT
      LAYER M4 ;
      RECT 0 610.32 0.024 610.344 ;
    END
  END rw0_wd_in[425]
  PIN rw0_wd_in[426]
    DIRECTION INPUT ;
    USE SIGNAL ;
    SHAPE ABUTMENT ;
    PORT
      LAYER M4 ;
      RECT 0 611.568 0.024 611.592 ;
    END
  END rw0_wd_in[426]
  PIN rw0_wd_in[427]
    DIRECTION INPUT ;
    USE SIGNAL ;
    SHAPE ABUTMENT ;
    PORT
      LAYER M4 ;
      RECT 0 612.816 0.024 612.84 ;
    END
  END rw0_wd_in[427]
  PIN rw0_wd_in[428]
    DIRECTION INPUT ;
    USE SIGNAL ;
    SHAPE ABUTMENT ;
    PORT
      LAYER M4 ;
      RECT 0 614.064 0.024 614.088 ;
    END
  END rw0_wd_in[428]
  PIN rw0_wd_in[429]
    DIRECTION INPUT ;
    USE SIGNAL ;
    SHAPE ABUTMENT ;
    PORT
      LAYER M4 ;
      RECT 0 615.312 0.024 615.336 ;
    END
  END rw0_wd_in[429]
  PIN rw0_wd_in[430]
    DIRECTION INPUT ;
    USE SIGNAL ;
    SHAPE ABUTMENT ;
    PORT
      LAYER M4 ;
      RECT 0 616.56 0.024 616.584 ;
    END
  END rw0_wd_in[430]
  PIN rw0_wd_in[431]
    DIRECTION INPUT ;
    USE SIGNAL ;
    SHAPE ABUTMENT ;
    PORT
      LAYER M4 ;
      RECT 0 617.808 0.024 617.832 ;
    END
  END rw0_wd_in[431]
  PIN rw0_wd_in[432]
    DIRECTION INPUT ;
    USE SIGNAL ;
    SHAPE ABUTMENT ;
    PORT
      LAYER M4 ;
      RECT 0 619.056 0.024 619.08 ;
    END
  END rw0_wd_in[432]
  PIN rw0_wd_in[433]
    DIRECTION INPUT ;
    USE SIGNAL ;
    SHAPE ABUTMENT ;
    PORT
      LAYER M4 ;
      RECT 0 620.304 0.024 620.328 ;
    END
  END rw0_wd_in[433]
  PIN rw0_wd_in[434]
    DIRECTION INPUT ;
    USE SIGNAL ;
    SHAPE ABUTMENT ;
    PORT
      LAYER M4 ;
      RECT 0 621.552 0.024 621.576 ;
    END
  END rw0_wd_in[434]
  PIN rw0_wd_in[435]
    DIRECTION INPUT ;
    USE SIGNAL ;
    SHAPE ABUTMENT ;
    PORT
      LAYER M4 ;
      RECT 0 622.8 0.024 622.824 ;
    END
  END rw0_wd_in[435]
  PIN rw0_wd_in[436]
    DIRECTION INPUT ;
    USE SIGNAL ;
    SHAPE ABUTMENT ;
    PORT
      LAYER M4 ;
      RECT 0 624.048 0.024 624.072 ;
    END
  END rw0_wd_in[436]
  PIN rw0_wd_in[437]
    DIRECTION INPUT ;
    USE SIGNAL ;
    SHAPE ABUTMENT ;
    PORT
      LAYER M4 ;
      RECT 0 625.296 0.024 625.32 ;
    END
  END rw0_wd_in[437]
  PIN rw0_wd_in[438]
    DIRECTION INPUT ;
    USE SIGNAL ;
    SHAPE ABUTMENT ;
    PORT
      LAYER M4 ;
      RECT 0 626.544 0.024 626.568 ;
    END
  END rw0_wd_in[438]
  PIN rw0_wd_in[439]
    DIRECTION INPUT ;
    USE SIGNAL ;
    SHAPE ABUTMENT ;
    PORT
      LAYER M4 ;
      RECT 0 627.792 0.024 627.816 ;
    END
  END rw0_wd_in[439]
  PIN rw0_wd_in[440]
    DIRECTION INPUT ;
    USE SIGNAL ;
    SHAPE ABUTMENT ;
    PORT
      LAYER M4 ;
      RECT 0 629.04 0.024 629.064 ;
    END
  END rw0_wd_in[440]
  PIN rw0_wd_in[441]
    DIRECTION INPUT ;
    USE SIGNAL ;
    SHAPE ABUTMENT ;
    PORT
      LAYER M4 ;
      RECT 0 630.288 0.024 630.312 ;
    END
  END rw0_wd_in[441]
  PIN rw0_wd_in[442]
    DIRECTION INPUT ;
    USE SIGNAL ;
    SHAPE ABUTMENT ;
    PORT
      LAYER M4 ;
      RECT 0 631.536 0.024 631.56 ;
    END
  END rw0_wd_in[442]
  PIN rw0_wd_in[443]
    DIRECTION INPUT ;
    USE SIGNAL ;
    SHAPE ABUTMENT ;
    PORT
      LAYER M4 ;
      RECT 0 632.784 0.024 632.808 ;
    END
  END rw0_wd_in[443]
  PIN rw0_wd_in[444]
    DIRECTION INPUT ;
    USE SIGNAL ;
    SHAPE ABUTMENT ;
    PORT
      LAYER M4 ;
      RECT 0 634.032 0.024 634.056 ;
    END
  END rw0_wd_in[444]
  PIN rw0_wd_in[445]
    DIRECTION INPUT ;
    USE SIGNAL ;
    SHAPE ABUTMENT ;
    PORT
      LAYER M4 ;
      RECT 0 635.28 0.024 635.304 ;
    END
  END rw0_wd_in[445]
  PIN rw0_wd_in[446]
    DIRECTION INPUT ;
    USE SIGNAL ;
    SHAPE ABUTMENT ;
    PORT
      LAYER M4 ;
      RECT 0 636.528 0.024 636.552 ;
    END
  END rw0_wd_in[446]
  PIN rw0_wd_in[447]
    DIRECTION INPUT ;
    USE SIGNAL ;
    SHAPE ABUTMENT ;
    PORT
      LAYER M4 ;
      RECT 0 637.776 0.024 637.8 ;
    END
  END rw0_wd_in[447]
  PIN rw0_wd_in[448]
    DIRECTION INPUT ;
    USE SIGNAL ;
    SHAPE ABUTMENT ;
    PORT
      LAYER M4 ;
      RECT 0 639.024 0.024 639.048 ;
    END
  END rw0_wd_in[448]
  PIN rw0_wd_in[449]
    DIRECTION INPUT ;
    USE SIGNAL ;
    SHAPE ABUTMENT ;
    PORT
      LAYER M4 ;
      RECT 0 640.272 0.024 640.296 ;
    END
  END rw0_wd_in[449]
  PIN rw0_wd_in[450]
    DIRECTION INPUT ;
    USE SIGNAL ;
    SHAPE ABUTMENT ;
    PORT
      LAYER M4 ;
      RECT 0 641.52 0.024 641.544 ;
    END
  END rw0_wd_in[450]
  PIN rw0_wd_in[451]
    DIRECTION INPUT ;
    USE SIGNAL ;
    SHAPE ABUTMENT ;
    PORT
      LAYER M4 ;
      RECT 0 642.768 0.024 642.792 ;
    END
  END rw0_wd_in[451]
  PIN rw0_wd_in[452]
    DIRECTION INPUT ;
    USE SIGNAL ;
    SHAPE ABUTMENT ;
    PORT
      LAYER M4 ;
      RECT 0 644.016 0.024 644.04 ;
    END
  END rw0_wd_in[452]
  PIN rw0_wd_in[453]
    DIRECTION INPUT ;
    USE SIGNAL ;
    SHAPE ABUTMENT ;
    PORT
      LAYER M4 ;
      RECT 0 645.264 0.024 645.288 ;
    END
  END rw0_wd_in[453]
  PIN rw0_wd_in[454]
    DIRECTION INPUT ;
    USE SIGNAL ;
    SHAPE ABUTMENT ;
    PORT
      LAYER M4 ;
      RECT 0 646.512 0.024 646.536 ;
    END
  END rw0_wd_in[454]
  PIN rw0_wd_in[455]
    DIRECTION INPUT ;
    USE SIGNAL ;
    SHAPE ABUTMENT ;
    PORT
      LAYER M4 ;
      RECT 0 647.76 0.024 647.784 ;
    END
  END rw0_wd_in[455]
  PIN rw0_wd_in[456]
    DIRECTION INPUT ;
    USE SIGNAL ;
    SHAPE ABUTMENT ;
    PORT
      LAYER M4 ;
      RECT 0 649.008 0.024 649.032 ;
    END
  END rw0_wd_in[456]
  PIN rw0_wd_in[457]
    DIRECTION INPUT ;
    USE SIGNAL ;
    SHAPE ABUTMENT ;
    PORT
      LAYER M4 ;
      RECT 0 650.256 0.024 650.28 ;
    END
  END rw0_wd_in[457]
  PIN rw0_wd_in[458]
    DIRECTION INPUT ;
    USE SIGNAL ;
    SHAPE ABUTMENT ;
    PORT
      LAYER M4 ;
      RECT 0 651.504 0.024 651.528 ;
    END
  END rw0_wd_in[458]
  PIN rw0_wd_in[459]
    DIRECTION INPUT ;
    USE SIGNAL ;
    SHAPE ABUTMENT ;
    PORT
      LAYER M4 ;
      RECT 0 652.752 0.024 652.776 ;
    END
  END rw0_wd_in[459]
  PIN rw0_wd_in[460]
    DIRECTION INPUT ;
    USE SIGNAL ;
    SHAPE ABUTMENT ;
    PORT
      LAYER M4 ;
      RECT 0 654 0.024 654.024 ;
    END
  END rw0_wd_in[460]
  PIN rw0_wd_in[461]
    DIRECTION INPUT ;
    USE SIGNAL ;
    SHAPE ABUTMENT ;
    PORT
      LAYER M4 ;
      RECT 0 655.248 0.024 655.272 ;
    END
  END rw0_wd_in[461]
  PIN rw0_wd_in[462]
    DIRECTION INPUT ;
    USE SIGNAL ;
    SHAPE ABUTMENT ;
    PORT
      LAYER M4 ;
      RECT 0 656.496 0.024 656.52 ;
    END
  END rw0_wd_in[462]
  PIN rw0_wd_in[463]
    DIRECTION INPUT ;
    USE SIGNAL ;
    SHAPE ABUTMENT ;
    PORT
      LAYER M4 ;
      RECT 0 657.744 0.024 657.768 ;
    END
  END rw0_wd_in[463]
  PIN rw0_wd_in[464]
    DIRECTION INPUT ;
    USE SIGNAL ;
    SHAPE ABUTMENT ;
    PORT
      LAYER M4 ;
      RECT 0 658.992 0.024 659.016 ;
    END
  END rw0_wd_in[464]
  PIN rw0_wd_in[465]
    DIRECTION INPUT ;
    USE SIGNAL ;
    SHAPE ABUTMENT ;
    PORT
      LAYER M4 ;
      RECT 0 660.24 0.024 660.264 ;
    END
  END rw0_wd_in[465]
  PIN rw0_wd_in[466]
    DIRECTION INPUT ;
    USE SIGNAL ;
    SHAPE ABUTMENT ;
    PORT
      LAYER M4 ;
      RECT 0 661.488 0.024 661.512 ;
    END
  END rw0_wd_in[466]
  PIN rw0_wd_in[467]
    DIRECTION INPUT ;
    USE SIGNAL ;
    SHAPE ABUTMENT ;
    PORT
      LAYER M4 ;
      RECT 0 662.736 0.024 662.76 ;
    END
  END rw0_wd_in[467]
  PIN rw0_wd_in[468]
    DIRECTION INPUT ;
    USE SIGNAL ;
    SHAPE ABUTMENT ;
    PORT
      LAYER M4 ;
      RECT 0 663.984 0.024 664.008 ;
    END
  END rw0_wd_in[468]
  PIN rw0_wd_in[469]
    DIRECTION INPUT ;
    USE SIGNAL ;
    SHAPE ABUTMENT ;
    PORT
      LAYER M4 ;
      RECT 0 665.232 0.024 665.256 ;
    END
  END rw0_wd_in[469]
  PIN rw0_wd_in[470]
    DIRECTION INPUT ;
    USE SIGNAL ;
    SHAPE ABUTMENT ;
    PORT
      LAYER M4 ;
      RECT 0 666.48 0.024 666.504 ;
    END
  END rw0_wd_in[470]
  PIN rw0_wd_in[471]
    DIRECTION INPUT ;
    USE SIGNAL ;
    SHAPE ABUTMENT ;
    PORT
      LAYER M4 ;
      RECT 0 667.728 0.024 667.752 ;
    END
  END rw0_wd_in[471]
  PIN rw0_wd_in[472]
    DIRECTION INPUT ;
    USE SIGNAL ;
    SHAPE ABUTMENT ;
    PORT
      LAYER M4 ;
      RECT 0 668.976 0.024 669 ;
    END
  END rw0_wd_in[472]
  PIN rw0_wd_in[473]
    DIRECTION INPUT ;
    USE SIGNAL ;
    SHAPE ABUTMENT ;
    PORT
      LAYER M4 ;
      RECT 0 670.224 0.024 670.248 ;
    END
  END rw0_wd_in[473]
  PIN rw0_wd_in[474]
    DIRECTION INPUT ;
    USE SIGNAL ;
    SHAPE ABUTMENT ;
    PORT
      LAYER M4 ;
      RECT 0 671.472 0.024 671.496 ;
    END
  END rw0_wd_in[474]
  PIN rw0_wd_in[475]
    DIRECTION INPUT ;
    USE SIGNAL ;
    SHAPE ABUTMENT ;
    PORT
      LAYER M4 ;
      RECT 0 672.72 0.024 672.744 ;
    END
  END rw0_wd_in[475]
  PIN rw0_wd_in[476]
    DIRECTION INPUT ;
    USE SIGNAL ;
    SHAPE ABUTMENT ;
    PORT
      LAYER M4 ;
      RECT 0 673.968 0.024 673.992 ;
    END
  END rw0_wd_in[476]
  PIN rw0_wd_in[477]
    DIRECTION INPUT ;
    USE SIGNAL ;
    SHAPE ABUTMENT ;
    PORT
      LAYER M4 ;
      RECT 0 675.216 0.024 675.24 ;
    END
  END rw0_wd_in[477]
  PIN rw0_wd_in[478]
    DIRECTION INPUT ;
    USE SIGNAL ;
    SHAPE ABUTMENT ;
    PORT
      LAYER M4 ;
      RECT 0 676.464 0.024 676.488 ;
    END
  END rw0_wd_in[478]
  PIN rw0_wd_in[479]
    DIRECTION INPUT ;
    USE SIGNAL ;
    SHAPE ABUTMENT ;
    PORT
      LAYER M4 ;
      RECT 0 677.712 0.024 677.736 ;
    END
  END rw0_wd_in[479]
  PIN rw0_wd_in[480]
    DIRECTION INPUT ;
    USE SIGNAL ;
    SHAPE ABUTMENT ;
    PORT
      LAYER M4 ;
      RECT 0 678.96 0.024 678.984 ;
    END
  END rw0_wd_in[480]
  PIN rw0_wd_in[481]
    DIRECTION INPUT ;
    USE SIGNAL ;
    SHAPE ABUTMENT ;
    PORT
      LAYER M4 ;
      RECT 0 680.208 0.024 680.232 ;
    END
  END rw0_wd_in[481]
  PIN rw0_wd_in[482]
    DIRECTION INPUT ;
    USE SIGNAL ;
    SHAPE ABUTMENT ;
    PORT
      LAYER M4 ;
      RECT 0 681.456 0.024 681.48 ;
    END
  END rw0_wd_in[482]
  PIN rw0_wd_in[483]
    DIRECTION INPUT ;
    USE SIGNAL ;
    SHAPE ABUTMENT ;
    PORT
      LAYER M4 ;
      RECT 0 682.704 0.024 682.728 ;
    END
  END rw0_wd_in[483]
  PIN rw0_wd_in[484]
    DIRECTION INPUT ;
    USE SIGNAL ;
    SHAPE ABUTMENT ;
    PORT
      LAYER M4 ;
      RECT 0 683.952 0.024 683.976 ;
    END
  END rw0_wd_in[484]
  PIN rw0_wd_in[485]
    DIRECTION INPUT ;
    USE SIGNAL ;
    SHAPE ABUTMENT ;
    PORT
      LAYER M4 ;
      RECT 0 685.2 0.024 685.224 ;
    END
  END rw0_wd_in[485]
  PIN rw0_wd_in[486]
    DIRECTION INPUT ;
    USE SIGNAL ;
    SHAPE ABUTMENT ;
    PORT
      LAYER M4 ;
      RECT 0 686.448 0.024 686.472 ;
    END
  END rw0_wd_in[486]
  PIN rw0_wd_in[487]
    DIRECTION INPUT ;
    USE SIGNAL ;
    SHAPE ABUTMENT ;
    PORT
      LAYER M4 ;
      RECT 0 687.696 0.024 687.72 ;
    END
  END rw0_wd_in[487]
  PIN rw0_wd_in[488]
    DIRECTION INPUT ;
    USE SIGNAL ;
    SHAPE ABUTMENT ;
    PORT
      LAYER M4 ;
      RECT 0 688.944 0.024 688.968 ;
    END
  END rw0_wd_in[488]
  PIN rw0_wd_in[489]
    DIRECTION INPUT ;
    USE SIGNAL ;
    SHAPE ABUTMENT ;
    PORT
      LAYER M4 ;
      RECT 0 690.192 0.024 690.216 ;
    END
  END rw0_wd_in[489]
  PIN rw0_wd_in[490]
    DIRECTION INPUT ;
    USE SIGNAL ;
    SHAPE ABUTMENT ;
    PORT
      LAYER M4 ;
      RECT 0 691.44 0.024 691.464 ;
    END
  END rw0_wd_in[490]
  PIN rw0_wd_in[491]
    DIRECTION INPUT ;
    USE SIGNAL ;
    SHAPE ABUTMENT ;
    PORT
      LAYER M4 ;
      RECT 0 692.688 0.024 692.712 ;
    END
  END rw0_wd_in[491]
  PIN rw0_wd_in[492]
    DIRECTION INPUT ;
    USE SIGNAL ;
    SHAPE ABUTMENT ;
    PORT
      LAYER M4 ;
      RECT 0 693.936 0.024 693.96 ;
    END
  END rw0_wd_in[492]
  PIN rw0_wd_in[493]
    DIRECTION INPUT ;
    USE SIGNAL ;
    SHAPE ABUTMENT ;
    PORT
      LAYER M4 ;
      RECT 0 695.184 0.024 695.208 ;
    END
  END rw0_wd_in[493]
  PIN rw0_wd_in[494]
    DIRECTION INPUT ;
    USE SIGNAL ;
    SHAPE ABUTMENT ;
    PORT
      LAYER M4 ;
      RECT 0 696.432 0.024 696.456 ;
    END
  END rw0_wd_in[494]
  PIN rw0_wd_in[495]
    DIRECTION INPUT ;
    USE SIGNAL ;
    SHAPE ABUTMENT ;
    PORT
      LAYER M4 ;
      RECT 0 697.68 0.024 697.704 ;
    END
  END rw0_wd_in[495]
  PIN rw0_wd_in[496]
    DIRECTION INPUT ;
    USE SIGNAL ;
    SHAPE ABUTMENT ;
    PORT
      LAYER M4 ;
      RECT 0 698.928 0.024 698.952 ;
    END
  END rw0_wd_in[496]
  PIN rw0_wd_in[497]
    DIRECTION INPUT ;
    USE SIGNAL ;
    SHAPE ABUTMENT ;
    PORT
      LAYER M4 ;
      RECT 0 700.176 0.024 700.2 ;
    END
  END rw0_wd_in[497]
  PIN rw0_wd_in[498]
    DIRECTION INPUT ;
    USE SIGNAL ;
    SHAPE ABUTMENT ;
    PORT
      LAYER M4 ;
      RECT 0 701.424 0.024 701.448 ;
    END
  END rw0_wd_in[498]
  PIN rw0_wd_in[499]
    DIRECTION INPUT ;
    USE SIGNAL ;
    SHAPE ABUTMENT ;
    PORT
      LAYER M4 ;
      RECT 0 702.672 0.024 702.696 ;
    END
  END rw0_wd_in[499]
  PIN rw0_wd_in[500]
    DIRECTION INPUT ;
    USE SIGNAL ;
    SHAPE ABUTMENT ;
    PORT
      LAYER M4 ;
      RECT 0 703.92 0.024 703.944 ;
    END
  END rw0_wd_in[500]
  PIN rw0_wd_in[501]
    DIRECTION INPUT ;
    USE SIGNAL ;
    SHAPE ABUTMENT ;
    PORT
      LAYER M4 ;
      RECT 0 705.168 0.024 705.192 ;
    END
  END rw0_wd_in[501]
  PIN rw0_wd_in[502]
    DIRECTION INPUT ;
    USE SIGNAL ;
    SHAPE ABUTMENT ;
    PORT
      LAYER M4 ;
      RECT 0 706.416 0.024 706.44 ;
    END
  END rw0_wd_in[502]
  PIN rw0_wd_in[503]
    DIRECTION INPUT ;
    USE SIGNAL ;
    SHAPE ABUTMENT ;
    PORT
      LAYER M4 ;
      RECT 0 707.664 0.024 707.688 ;
    END
  END rw0_wd_in[503]
  PIN rw0_wd_in[504]
    DIRECTION INPUT ;
    USE SIGNAL ;
    SHAPE ABUTMENT ;
    PORT
      LAYER M4 ;
      RECT 0 708.912 0.024 708.936 ;
    END
  END rw0_wd_in[504]
  PIN rw0_wd_in[505]
    DIRECTION INPUT ;
    USE SIGNAL ;
    SHAPE ABUTMENT ;
    PORT
      LAYER M4 ;
      RECT 0 710.16 0.024 710.184 ;
    END
  END rw0_wd_in[505]
  PIN rw0_wd_in[506]
    DIRECTION INPUT ;
    USE SIGNAL ;
    SHAPE ABUTMENT ;
    PORT
      LAYER M4 ;
      RECT 0 711.408 0.024 711.432 ;
    END
  END rw0_wd_in[506]
  PIN rw0_wd_in[507]
    DIRECTION INPUT ;
    USE SIGNAL ;
    SHAPE ABUTMENT ;
    PORT
      LAYER M4 ;
      RECT 0 712.656 0.024 712.68 ;
    END
  END rw0_wd_in[507]
  PIN rw0_wd_in[508]
    DIRECTION INPUT ;
    USE SIGNAL ;
    SHAPE ABUTMENT ;
    PORT
      LAYER M4 ;
      RECT 0 713.904 0.024 713.928 ;
    END
  END rw0_wd_in[508]
  PIN rw0_wd_in[509]
    DIRECTION INPUT ;
    USE SIGNAL ;
    SHAPE ABUTMENT ;
    PORT
      LAYER M4 ;
      RECT 0 715.152 0.024 715.176 ;
    END
  END rw0_wd_in[509]
  PIN rw0_wd_in[510]
    DIRECTION INPUT ;
    USE SIGNAL ;
    SHAPE ABUTMENT ;
    PORT
      LAYER M4 ;
      RECT 0 716.4 0.024 716.424 ;
    END
  END rw0_wd_in[510]
  PIN rw0_wd_in[511]
    DIRECTION INPUT ;
    USE SIGNAL ;
    SHAPE ABUTMENT ;
    PORT
      LAYER M4 ;
      RECT 0 717.648 0.024 717.672 ;
    END
  END rw0_wd_in[511]
  PIN rw0_rd_out[0]
    DIRECTION OUTPUT ;
    USE SIGNAL ;
    SHAPE ABUTMENT ;
    PORT
      LAYER M4 ;
      RECT 0 718.896 0.024 718.92 ;
    END
  END rw0_rd_out[0]
  PIN rw0_rd_out[1]
    DIRECTION OUTPUT ;
    USE SIGNAL ;
    SHAPE ABUTMENT ;
    PORT
      LAYER M4 ;
      RECT 0 720.144 0.024 720.168 ;
    END
  END rw0_rd_out[1]
  PIN rw0_rd_out[2]
    DIRECTION OUTPUT ;
    USE SIGNAL ;
    SHAPE ABUTMENT ;
    PORT
      LAYER M4 ;
      RECT 0 721.392 0.024 721.416 ;
    END
  END rw0_rd_out[2]
  PIN rw0_rd_out[3]
    DIRECTION OUTPUT ;
    USE SIGNAL ;
    SHAPE ABUTMENT ;
    PORT
      LAYER M4 ;
      RECT 0 722.64 0.024 722.664 ;
    END
  END rw0_rd_out[3]
  PIN rw0_rd_out[4]
    DIRECTION OUTPUT ;
    USE SIGNAL ;
    SHAPE ABUTMENT ;
    PORT
      LAYER M4 ;
      RECT 0 723.888 0.024 723.912 ;
    END
  END rw0_rd_out[4]
  PIN rw0_rd_out[5]
    DIRECTION OUTPUT ;
    USE SIGNAL ;
    SHAPE ABUTMENT ;
    PORT
      LAYER M4 ;
      RECT 0 725.136 0.024 725.16 ;
    END
  END rw0_rd_out[5]
  PIN rw0_rd_out[6]
    DIRECTION OUTPUT ;
    USE SIGNAL ;
    SHAPE ABUTMENT ;
    PORT
      LAYER M4 ;
      RECT 0 726.384 0.024 726.408 ;
    END
  END rw0_rd_out[6]
  PIN rw0_rd_out[7]
    DIRECTION OUTPUT ;
    USE SIGNAL ;
    SHAPE ABUTMENT ;
    PORT
      LAYER M4 ;
      RECT 0 727.632 0.024 727.656 ;
    END
  END rw0_rd_out[7]
  PIN rw0_rd_out[8]
    DIRECTION OUTPUT ;
    USE SIGNAL ;
    SHAPE ABUTMENT ;
    PORT
      LAYER M4 ;
      RECT 0 728.88 0.024 728.904 ;
    END
  END rw0_rd_out[8]
  PIN rw0_rd_out[9]
    DIRECTION OUTPUT ;
    USE SIGNAL ;
    SHAPE ABUTMENT ;
    PORT
      LAYER M4 ;
      RECT 0 730.128 0.024 730.152 ;
    END
  END rw0_rd_out[9]
  PIN rw0_rd_out[10]
    DIRECTION OUTPUT ;
    USE SIGNAL ;
    SHAPE ABUTMENT ;
    PORT
      LAYER M4 ;
      RECT 0 731.376 0.024 731.4 ;
    END
  END rw0_rd_out[10]
  PIN rw0_rd_out[11]
    DIRECTION OUTPUT ;
    USE SIGNAL ;
    SHAPE ABUTMENT ;
    PORT
      LAYER M4 ;
      RECT 0 732.624 0.024 732.648 ;
    END
  END rw0_rd_out[11]
  PIN rw0_rd_out[12]
    DIRECTION OUTPUT ;
    USE SIGNAL ;
    SHAPE ABUTMENT ;
    PORT
      LAYER M4 ;
      RECT 0 733.872 0.024 733.896 ;
    END
  END rw0_rd_out[12]
  PIN rw0_rd_out[13]
    DIRECTION OUTPUT ;
    USE SIGNAL ;
    SHAPE ABUTMENT ;
    PORT
      LAYER M4 ;
      RECT 0 735.12 0.024 735.144 ;
    END
  END rw0_rd_out[13]
  PIN rw0_rd_out[14]
    DIRECTION OUTPUT ;
    USE SIGNAL ;
    SHAPE ABUTMENT ;
    PORT
      LAYER M4 ;
      RECT 0 736.368 0.024 736.392 ;
    END
  END rw0_rd_out[14]
  PIN rw0_rd_out[15]
    DIRECTION OUTPUT ;
    USE SIGNAL ;
    SHAPE ABUTMENT ;
    PORT
      LAYER M4 ;
      RECT 0 737.616 0.024 737.64 ;
    END
  END rw0_rd_out[15]
  PIN rw0_rd_out[16]
    DIRECTION OUTPUT ;
    USE SIGNAL ;
    SHAPE ABUTMENT ;
    PORT
      LAYER M4 ;
      RECT 0 738.864 0.024 738.888 ;
    END
  END rw0_rd_out[16]
  PIN rw0_rd_out[17]
    DIRECTION OUTPUT ;
    USE SIGNAL ;
    SHAPE ABUTMENT ;
    PORT
      LAYER M4 ;
      RECT 0 740.112 0.024 740.136 ;
    END
  END rw0_rd_out[17]
  PIN rw0_rd_out[18]
    DIRECTION OUTPUT ;
    USE SIGNAL ;
    SHAPE ABUTMENT ;
    PORT
      LAYER M4 ;
      RECT 0 741.36 0.024 741.384 ;
    END
  END rw0_rd_out[18]
  PIN rw0_rd_out[19]
    DIRECTION OUTPUT ;
    USE SIGNAL ;
    SHAPE ABUTMENT ;
    PORT
      LAYER M4 ;
      RECT 0 742.608 0.024 742.632 ;
    END
  END rw0_rd_out[19]
  PIN rw0_rd_out[20]
    DIRECTION OUTPUT ;
    USE SIGNAL ;
    SHAPE ABUTMENT ;
    PORT
      LAYER M4 ;
      RECT 0 743.856 0.024 743.88 ;
    END
  END rw0_rd_out[20]
  PIN rw0_rd_out[21]
    DIRECTION OUTPUT ;
    USE SIGNAL ;
    SHAPE ABUTMENT ;
    PORT
      LAYER M4 ;
      RECT 0 745.104 0.024 745.128 ;
    END
  END rw0_rd_out[21]
  PIN rw0_rd_out[22]
    DIRECTION OUTPUT ;
    USE SIGNAL ;
    SHAPE ABUTMENT ;
    PORT
      LAYER M4 ;
      RECT 0 746.352 0.024 746.376 ;
    END
  END rw0_rd_out[22]
  PIN rw0_rd_out[23]
    DIRECTION OUTPUT ;
    USE SIGNAL ;
    SHAPE ABUTMENT ;
    PORT
      LAYER M4 ;
      RECT 0 747.6 0.024 747.624 ;
    END
  END rw0_rd_out[23]
  PIN rw0_rd_out[24]
    DIRECTION OUTPUT ;
    USE SIGNAL ;
    SHAPE ABUTMENT ;
    PORT
      LAYER M4 ;
      RECT 0 748.848 0.024 748.872 ;
    END
  END rw0_rd_out[24]
  PIN rw0_rd_out[25]
    DIRECTION OUTPUT ;
    USE SIGNAL ;
    SHAPE ABUTMENT ;
    PORT
      LAYER M4 ;
      RECT 0 750.096 0.024 750.12 ;
    END
  END rw0_rd_out[25]
  PIN rw0_rd_out[26]
    DIRECTION OUTPUT ;
    USE SIGNAL ;
    SHAPE ABUTMENT ;
    PORT
      LAYER M4 ;
      RECT 0 751.344 0.024 751.368 ;
    END
  END rw0_rd_out[26]
  PIN rw0_rd_out[27]
    DIRECTION OUTPUT ;
    USE SIGNAL ;
    SHAPE ABUTMENT ;
    PORT
      LAYER M4 ;
      RECT 0 752.592 0.024 752.616 ;
    END
  END rw0_rd_out[27]
  PIN rw0_rd_out[28]
    DIRECTION OUTPUT ;
    USE SIGNAL ;
    SHAPE ABUTMENT ;
    PORT
      LAYER M4 ;
      RECT 0 753.84 0.024 753.864 ;
    END
  END rw0_rd_out[28]
  PIN rw0_rd_out[29]
    DIRECTION OUTPUT ;
    USE SIGNAL ;
    SHAPE ABUTMENT ;
    PORT
      LAYER M4 ;
      RECT 0 755.088 0.024 755.112 ;
    END
  END rw0_rd_out[29]
  PIN rw0_rd_out[30]
    DIRECTION OUTPUT ;
    USE SIGNAL ;
    SHAPE ABUTMENT ;
    PORT
      LAYER M4 ;
      RECT 0 756.336 0.024 756.36 ;
    END
  END rw0_rd_out[30]
  PIN rw0_rd_out[31]
    DIRECTION OUTPUT ;
    USE SIGNAL ;
    SHAPE ABUTMENT ;
    PORT
      LAYER M4 ;
      RECT 0 757.584 0.024 757.608 ;
    END
  END rw0_rd_out[31]
  PIN rw0_rd_out[32]
    DIRECTION OUTPUT ;
    USE SIGNAL ;
    SHAPE ABUTMENT ;
    PORT
      LAYER M4 ;
      RECT 0 758.832 0.024 758.856 ;
    END
  END rw0_rd_out[32]
  PIN rw0_rd_out[33]
    DIRECTION OUTPUT ;
    USE SIGNAL ;
    SHAPE ABUTMENT ;
    PORT
      LAYER M4 ;
      RECT 0 760.08 0.024 760.104 ;
    END
  END rw0_rd_out[33]
  PIN rw0_rd_out[34]
    DIRECTION OUTPUT ;
    USE SIGNAL ;
    SHAPE ABUTMENT ;
    PORT
      LAYER M4 ;
      RECT 0 761.328 0.024 761.352 ;
    END
  END rw0_rd_out[34]
  PIN rw0_rd_out[35]
    DIRECTION OUTPUT ;
    USE SIGNAL ;
    SHAPE ABUTMENT ;
    PORT
      LAYER M4 ;
      RECT 0 762.576 0.024 762.6 ;
    END
  END rw0_rd_out[35]
  PIN rw0_rd_out[36]
    DIRECTION OUTPUT ;
    USE SIGNAL ;
    SHAPE ABUTMENT ;
    PORT
      LAYER M4 ;
      RECT 0 763.824 0.024 763.848 ;
    END
  END rw0_rd_out[36]
  PIN rw0_rd_out[37]
    DIRECTION OUTPUT ;
    USE SIGNAL ;
    SHAPE ABUTMENT ;
    PORT
      LAYER M4 ;
      RECT 0 765.072 0.024 765.096 ;
    END
  END rw0_rd_out[37]
  PIN rw0_rd_out[38]
    DIRECTION OUTPUT ;
    USE SIGNAL ;
    SHAPE ABUTMENT ;
    PORT
      LAYER M4 ;
      RECT 0 766.32 0.024 766.344 ;
    END
  END rw0_rd_out[38]
  PIN rw0_rd_out[39]
    DIRECTION OUTPUT ;
    USE SIGNAL ;
    SHAPE ABUTMENT ;
    PORT
      LAYER M4 ;
      RECT 0 767.568 0.024 767.592 ;
    END
  END rw0_rd_out[39]
  PIN rw0_rd_out[40]
    DIRECTION OUTPUT ;
    USE SIGNAL ;
    SHAPE ABUTMENT ;
    PORT
      LAYER M4 ;
      RECT 0 768.816 0.024 768.84 ;
    END
  END rw0_rd_out[40]
  PIN rw0_rd_out[41]
    DIRECTION OUTPUT ;
    USE SIGNAL ;
    SHAPE ABUTMENT ;
    PORT
      LAYER M4 ;
      RECT 0 770.064 0.024 770.088 ;
    END
  END rw0_rd_out[41]
  PIN rw0_rd_out[42]
    DIRECTION OUTPUT ;
    USE SIGNAL ;
    SHAPE ABUTMENT ;
    PORT
      LAYER M4 ;
      RECT 0 771.312 0.024 771.336 ;
    END
  END rw0_rd_out[42]
  PIN rw0_rd_out[43]
    DIRECTION OUTPUT ;
    USE SIGNAL ;
    SHAPE ABUTMENT ;
    PORT
      LAYER M4 ;
      RECT 0 772.56 0.024 772.584 ;
    END
  END rw0_rd_out[43]
  PIN rw0_rd_out[44]
    DIRECTION OUTPUT ;
    USE SIGNAL ;
    SHAPE ABUTMENT ;
    PORT
      LAYER M4 ;
      RECT 0 773.808 0.024 773.832 ;
    END
  END rw0_rd_out[44]
  PIN rw0_rd_out[45]
    DIRECTION OUTPUT ;
    USE SIGNAL ;
    SHAPE ABUTMENT ;
    PORT
      LAYER M4 ;
      RECT 0 775.056 0.024 775.08 ;
    END
  END rw0_rd_out[45]
  PIN rw0_rd_out[46]
    DIRECTION OUTPUT ;
    USE SIGNAL ;
    SHAPE ABUTMENT ;
    PORT
      LAYER M4 ;
      RECT 0 776.304 0.024 776.328 ;
    END
  END rw0_rd_out[46]
  PIN rw0_rd_out[47]
    DIRECTION OUTPUT ;
    USE SIGNAL ;
    SHAPE ABUTMENT ;
    PORT
      LAYER M4 ;
      RECT 0 777.552 0.024 777.576 ;
    END
  END rw0_rd_out[47]
  PIN rw0_rd_out[48]
    DIRECTION OUTPUT ;
    USE SIGNAL ;
    SHAPE ABUTMENT ;
    PORT
      LAYER M4 ;
      RECT 0 778.8 0.024 778.824 ;
    END
  END rw0_rd_out[48]
  PIN rw0_rd_out[49]
    DIRECTION OUTPUT ;
    USE SIGNAL ;
    SHAPE ABUTMENT ;
    PORT
      LAYER M4 ;
      RECT 0 780.048 0.024 780.072 ;
    END
  END rw0_rd_out[49]
  PIN rw0_rd_out[50]
    DIRECTION OUTPUT ;
    USE SIGNAL ;
    SHAPE ABUTMENT ;
    PORT
      LAYER M4 ;
      RECT 0 781.296 0.024 781.32 ;
    END
  END rw0_rd_out[50]
  PIN rw0_rd_out[51]
    DIRECTION OUTPUT ;
    USE SIGNAL ;
    SHAPE ABUTMENT ;
    PORT
      LAYER M4 ;
      RECT 0 782.544 0.024 782.568 ;
    END
  END rw0_rd_out[51]
  PIN rw0_rd_out[52]
    DIRECTION OUTPUT ;
    USE SIGNAL ;
    SHAPE ABUTMENT ;
    PORT
      LAYER M4 ;
      RECT 0 783.792 0.024 783.816 ;
    END
  END rw0_rd_out[52]
  PIN rw0_rd_out[53]
    DIRECTION OUTPUT ;
    USE SIGNAL ;
    SHAPE ABUTMENT ;
    PORT
      LAYER M4 ;
      RECT 0 785.04 0.024 785.064 ;
    END
  END rw0_rd_out[53]
  PIN rw0_rd_out[54]
    DIRECTION OUTPUT ;
    USE SIGNAL ;
    SHAPE ABUTMENT ;
    PORT
      LAYER M4 ;
      RECT 0 786.288 0.024 786.312 ;
    END
  END rw0_rd_out[54]
  PIN rw0_rd_out[55]
    DIRECTION OUTPUT ;
    USE SIGNAL ;
    SHAPE ABUTMENT ;
    PORT
      LAYER M4 ;
      RECT 0 787.536 0.024 787.56 ;
    END
  END rw0_rd_out[55]
  PIN rw0_rd_out[56]
    DIRECTION OUTPUT ;
    USE SIGNAL ;
    SHAPE ABUTMENT ;
    PORT
      LAYER M4 ;
      RECT 0 788.784 0.024 788.808 ;
    END
  END rw0_rd_out[56]
  PIN rw0_rd_out[57]
    DIRECTION OUTPUT ;
    USE SIGNAL ;
    SHAPE ABUTMENT ;
    PORT
      LAYER M4 ;
      RECT 0 790.032 0.024 790.056 ;
    END
  END rw0_rd_out[57]
  PIN rw0_rd_out[58]
    DIRECTION OUTPUT ;
    USE SIGNAL ;
    SHAPE ABUTMENT ;
    PORT
      LAYER M4 ;
      RECT 0 791.28 0.024 791.304 ;
    END
  END rw0_rd_out[58]
  PIN rw0_rd_out[59]
    DIRECTION OUTPUT ;
    USE SIGNAL ;
    SHAPE ABUTMENT ;
    PORT
      LAYER M4 ;
      RECT 0 792.528 0.024 792.552 ;
    END
  END rw0_rd_out[59]
  PIN rw0_rd_out[60]
    DIRECTION OUTPUT ;
    USE SIGNAL ;
    SHAPE ABUTMENT ;
    PORT
      LAYER M4 ;
      RECT 0 793.776 0.024 793.8 ;
    END
  END rw0_rd_out[60]
  PIN rw0_rd_out[61]
    DIRECTION OUTPUT ;
    USE SIGNAL ;
    SHAPE ABUTMENT ;
    PORT
      LAYER M4 ;
      RECT 0 795.024 0.024 795.048 ;
    END
  END rw0_rd_out[61]
  PIN rw0_rd_out[62]
    DIRECTION OUTPUT ;
    USE SIGNAL ;
    SHAPE ABUTMENT ;
    PORT
      LAYER M4 ;
      RECT 0 796.272 0.024 796.296 ;
    END
  END rw0_rd_out[62]
  PIN rw0_rd_out[63]
    DIRECTION OUTPUT ;
    USE SIGNAL ;
    SHAPE ABUTMENT ;
    PORT
      LAYER M4 ;
      RECT 0 797.52 0.024 797.544 ;
    END
  END rw0_rd_out[63]
  PIN rw0_rd_out[64]
    DIRECTION OUTPUT ;
    USE SIGNAL ;
    SHAPE ABUTMENT ;
    PORT
      LAYER M4 ;
      RECT 0 798.768 0.024 798.792 ;
    END
  END rw0_rd_out[64]
  PIN rw0_rd_out[65]
    DIRECTION OUTPUT ;
    USE SIGNAL ;
    SHAPE ABUTMENT ;
    PORT
      LAYER M4 ;
      RECT 0 800.016 0.024 800.04 ;
    END
  END rw0_rd_out[65]
  PIN rw0_rd_out[66]
    DIRECTION OUTPUT ;
    USE SIGNAL ;
    SHAPE ABUTMENT ;
    PORT
      LAYER M4 ;
      RECT 0 801.264 0.024 801.288 ;
    END
  END rw0_rd_out[66]
  PIN rw0_rd_out[67]
    DIRECTION OUTPUT ;
    USE SIGNAL ;
    SHAPE ABUTMENT ;
    PORT
      LAYER M4 ;
      RECT 0 802.512 0.024 802.536 ;
    END
  END rw0_rd_out[67]
  PIN rw0_rd_out[68]
    DIRECTION OUTPUT ;
    USE SIGNAL ;
    SHAPE ABUTMENT ;
    PORT
      LAYER M4 ;
      RECT 0 803.76 0.024 803.784 ;
    END
  END rw0_rd_out[68]
  PIN rw0_rd_out[69]
    DIRECTION OUTPUT ;
    USE SIGNAL ;
    SHAPE ABUTMENT ;
    PORT
      LAYER M4 ;
      RECT 0 805.008 0.024 805.032 ;
    END
  END rw0_rd_out[69]
  PIN rw0_rd_out[70]
    DIRECTION OUTPUT ;
    USE SIGNAL ;
    SHAPE ABUTMENT ;
    PORT
      LAYER M4 ;
      RECT 0 806.256 0.024 806.28 ;
    END
  END rw0_rd_out[70]
  PIN rw0_rd_out[71]
    DIRECTION OUTPUT ;
    USE SIGNAL ;
    SHAPE ABUTMENT ;
    PORT
      LAYER M4 ;
      RECT 0 807.504 0.024 807.528 ;
    END
  END rw0_rd_out[71]
  PIN rw0_rd_out[72]
    DIRECTION OUTPUT ;
    USE SIGNAL ;
    SHAPE ABUTMENT ;
    PORT
      LAYER M4 ;
      RECT 0 808.752 0.024 808.776 ;
    END
  END rw0_rd_out[72]
  PIN rw0_rd_out[73]
    DIRECTION OUTPUT ;
    USE SIGNAL ;
    SHAPE ABUTMENT ;
    PORT
      LAYER M4 ;
      RECT 0 810 0.024 810.024 ;
    END
  END rw0_rd_out[73]
  PIN rw0_rd_out[74]
    DIRECTION OUTPUT ;
    USE SIGNAL ;
    SHAPE ABUTMENT ;
    PORT
      LAYER M4 ;
      RECT 0 811.248 0.024 811.272 ;
    END
  END rw0_rd_out[74]
  PIN rw0_rd_out[75]
    DIRECTION OUTPUT ;
    USE SIGNAL ;
    SHAPE ABUTMENT ;
    PORT
      LAYER M4 ;
      RECT 0 812.496 0.024 812.52 ;
    END
  END rw0_rd_out[75]
  PIN rw0_rd_out[76]
    DIRECTION OUTPUT ;
    USE SIGNAL ;
    SHAPE ABUTMENT ;
    PORT
      LAYER M4 ;
      RECT 0 813.744 0.024 813.768 ;
    END
  END rw0_rd_out[76]
  PIN rw0_rd_out[77]
    DIRECTION OUTPUT ;
    USE SIGNAL ;
    SHAPE ABUTMENT ;
    PORT
      LAYER M4 ;
      RECT 0 814.992 0.024 815.016 ;
    END
  END rw0_rd_out[77]
  PIN rw0_rd_out[78]
    DIRECTION OUTPUT ;
    USE SIGNAL ;
    SHAPE ABUTMENT ;
    PORT
      LAYER M4 ;
      RECT 0 816.24 0.024 816.264 ;
    END
  END rw0_rd_out[78]
  PIN rw0_rd_out[79]
    DIRECTION OUTPUT ;
    USE SIGNAL ;
    SHAPE ABUTMENT ;
    PORT
      LAYER M4 ;
      RECT 0 817.488 0.024 817.512 ;
    END
  END rw0_rd_out[79]
  PIN rw0_rd_out[80]
    DIRECTION OUTPUT ;
    USE SIGNAL ;
    SHAPE ABUTMENT ;
    PORT
      LAYER M4 ;
      RECT 0 818.736 0.024 818.76 ;
    END
  END rw0_rd_out[80]
  PIN rw0_rd_out[81]
    DIRECTION OUTPUT ;
    USE SIGNAL ;
    SHAPE ABUTMENT ;
    PORT
      LAYER M4 ;
      RECT 0 819.984 0.024 820.008 ;
    END
  END rw0_rd_out[81]
  PIN rw0_rd_out[82]
    DIRECTION OUTPUT ;
    USE SIGNAL ;
    SHAPE ABUTMENT ;
    PORT
      LAYER M4 ;
      RECT 0 821.232 0.024 821.256 ;
    END
  END rw0_rd_out[82]
  PIN rw0_rd_out[83]
    DIRECTION OUTPUT ;
    USE SIGNAL ;
    SHAPE ABUTMENT ;
    PORT
      LAYER M4 ;
      RECT 0 822.48 0.024 822.504 ;
    END
  END rw0_rd_out[83]
  PIN rw0_rd_out[84]
    DIRECTION OUTPUT ;
    USE SIGNAL ;
    SHAPE ABUTMENT ;
    PORT
      LAYER M4 ;
      RECT 0 823.728 0.024 823.752 ;
    END
  END rw0_rd_out[84]
  PIN rw0_rd_out[85]
    DIRECTION OUTPUT ;
    USE SIGNAL ;
    SHAPE ABUTMENT ;
    PORT
      LAYER M4 ;
      RECT 0 824.976 0.024 825 ;
    END
  END rw0_rd_out[85]
  PIN rw0_rd_out[86]
    DIRECTION OUTPUT ;
    USE SIGNAL ;
    SHAPE ABUTMENT ;
    PORT
      LAYER M4 ;
      RECT 0 826.224 0.024 826.248 ;
    END
  END rw0_rd_out[86]
  PIN rw0_rd_out[87]
    DIRECTION OUTPUT ;
    USE SIGNAL ;
    SHAPE ABUTMENT ;
    PORT
      LAYER M4 ;
      RECT 0 827.472 0.024 827.496 ;
    END
  END rw0_rd_out[87]
  PIN rw0_rd_out[88]
    DIRECTION OUTPUT ;
    USE SIGNAL ;
    SHAPE ABUTMENT ;
    PORT
      LAYER M4 ;
      RECT 0 828.72 0.024 828.744 ;
    END
  END rw0_rd_out[88]
  PIN rw0_rd_out[89]
    DIRECTION OUTPUT ;
    USE SIGNAL ;
    SHAPE ABUTMENT ;
    PORT
      LAYER M4 ;
      RECT 0 829.968 0.024 829.992 ;
    END
  END rw0_rd_out[89]
  PIN rw0_rd_out[90]
    DIRECTION OUTPUT ;
    USE SIGNAL ;
    SHAPE ABUTMENT ;
    PORT
      LAYER M4 ;
      RECT 0 831.216 0.024 831.24 ;
    END
  END rw0_rd_out[90]
  PIN rw0_rd_out[91]
    DIRECTION OUTPUT ;
    USE SIGNAL ;
    SHAPE ABUTMENT ;
    PORT
      LAYER M4 ;
      RECT 0 832.464 0.024 832.488 ;
    END
  END rw0_rd_out[91]
  PIN rw0_rd_out[92]
    DIRECTION OUTPUT ;
    USE SIGNAL ;
    SHAPE ABUTMENT ;
    PORT
      LAYER M4 ;
      RECT 0 833.712 0.024 833.736 ;
    END
  END rw0_rd_out[92]
  PIN rw0_rd_out[93]
    DIRECTION OUTPUT ;
    USE SIGNAL ;
    SHAPE ABUTMENT ;
    PORT
      LAYER M4 ;
      RECT 0 834.96 0.024 834.984 ;
    END
  END rw0_rd_out[93]
  PIN rw0_rd_out[94]
    DIRECTION OUTPUT ;
    USE SIGNAL ;
    SHAPE ABUTMENT ;
    PORT
      LAYER M4 ;
      RECT 0 836.208 0.024 836.232 ;
    END
  END rw0_rd_out[94]
  PIN rw0_rd_out[95]
    DIRECTION OUTPUT ;
    USE SIGNAL ;
    SHAPE ABUTMENT ;
    PORT
      LAYER M4 ;
      RECT 0 837.456 0.024 837.48 ;
    END
  END rw0_rd_out[95]
  PIN rw0_rd_out[96]
    DIRECTION OUTPUT ;
    USE SIGNAL ;
    SHAPE ABUTMENT ;
    PORT
      LAYER M4 ;
      RECT 0 838.704 0.024 838.728 ;
    END
  END rw0_rd_out[96]
  PIN rw0_rd_out[97]
    DIRECTION OUTPUT ;
    USE SIGNAL ;
    SHAPE ABUTMENT ;
    PORT
      LAYER M4 ;
      RECT 0 839.952 0.024 839.976 ;
    END
  END rw0_rd_out[97]
  PIN rw0_rd_out[98]
    DIRECTION OUTPUT ;
    USE SIGNAL ;
    SHAPE ABUTMENT ;
    PORT
      LAYER M4 ;
      RECT 0 841.2 0.024 841.224 ;
    END
  END rw0_rd_out[98]
  PIN rw0_rd_out[99]
    DIRECTION OUTPUT ;
    USE SIGNAL ;
    SHAPE ABUTMENT ;
    PORT
      LAYER M4 ;
      RECT 0 842.448 0.024 842.472 ;
    END
  END rw0_rd_out[99]
  PIN rw0_rd_out[100]
    DIRECTION OUTPUT ;
    USE SIGNAL ;
    SHAPE ABUTMENT ;
    PORT
      LAYER M4 ;
      RECT 0 843.696 0.024 843.72 ;
    END
  END rw0_rd_out[100]
  PIN rw0_rd_out[101]
    DIRECTION OUTPUT ;
    USE SIGNAL ;
    SHAPE ABUTMENT ;
    PORT
      LAYER M4 ;
      RECT 0 844.944 0.024 844.968 ;
    END
  END rw0_rd_out[101]
  PIN rw0_rd_out[102]
    DIRECTION OUTPUT ;
    USE SIGNAL ;
    SHAPE ABUTMENT ;
    PORT
      LAYER M4 ;
      RECT 0 846.192 0.024 846.216 ;
    END
  END rw0_rd_out[102]
  PIN rw0_rd_out[103]
    DIRECTION OUTPUT ;
    USE SIGNAL ;
    SHAPE ABUTMENT ;
    PORT
      LAYER M4 ;
      RECT 0 847.44 0.024 847.464 ;
    END
  END rw0_rd_out[103]
  PIN rw0_rd_out[104]
    DIRECTION OUTPUT ;
    USE SIGNAL ;
    SHAPE ABUTMENT ;
    PORT
      LAYER M4 ;
      RECT 0 848.688 0.024 848.712 ;
    END
  END rw0_rd_out[104]
  PIN rw0_rd_out[105]
    DIRECTION OUTPUT ;
    USE SIGNAL ;
    SHAPE ABUTMENT ;
    PORT
      LAYER M4 ;
      RECT 0 849.936 0.024 849.96 ;
    END
  END rw0_rd_out[105]
  PIN rw0_rd_out[106]
    DIRECTION OUTPUT ;
    USE SIGNAL ;
    SHAPE ABUTMENT ;
    PORT
      LAYER M4 ;
      RECT 0 851.184 0.024 851.208 ;
    END
  END rw0_rd_out[106]
  PIN rw0_rd_out[107]
    DIRECTION OUTPUT ;
    USE SIGNAL ;
    SHAPE ABUTMENT ;
    PORT
      LAYER M4 ;
      RECT 0 852.432 0.024 852.456 ;
    END
  END rw0_rd_out[107]
  PIN rw0_rd_out[108]
    DIRECTION OUTPUT ;
    USE SIGNAL ;
    SHAPE ABUTMENT ;
    PORT
      LAYER M4 ;
      RECT 0 853.68 0.024 853.704 ;
    END
  END rw0_rd_out[108]
  PIN rw0_rd_out[109]
    DIRECTION OUTPUT ;
    USE SIGNAL ;
    SHAPE ABUTMENT ;
    PORT
      LAYER M4 ;
      RECT 0 854.928 0.024 854.952 ;
    END
  END rw0_rd_out[109]
  PIN rw0_rd_out[110]
    DIRECTION OUTPUT ;
    USE SIGNAL ;
    SHAPE ABUTMENT ;
    PORT
      LAYER M4 ;
      RECT 0 856.176 0.024 856.2 ;
    END
  END rw0_rd_out[110]
  PIN rw0_rd_out[111]
    DIRECTION OUTPUT ;
    USE SIGNAL ;
    SHAPE ABUTMENT ;
    PORT
      LAYER M4 ;
      RECT 0 857.424 0.024 857.448 ;
    END
  END rw0_rd_out[111]
  PIN rw0_rd_out[112]
    DIRECTION OUTPUT ;
    USE SIGNAL ;
    SHAPE ABUTMENT ;
    PORT
      LAYER M4 ;
      RECT 0 858.672 0.024 858.696 ;
    END
  END rw0_rd_out[112]
  PIN rw0_rd_out[113]
    DIRECTION OUTPUT ;
    USE SIGNAL ;
    SHAPE ABUTMENT ;
    PORT
      LAYER M4 ;
      RECT 0 859.92 0.024 859.944 ;
    END
  END rw0_rd_out[113]
  PIN rw0_rd_out[114]
    DIRECTION OUTPUT ;
    USE SIGNAL ;
    SHAPE ABUTMENT ;
    PORT
      LAYER M4 ;
      RECT 0 861.168 0.024 861.192 ;
    END
  END rw0_rd_out[114]
  PIN rw0_rd_out[115]
    DIRECTION OUTPUT ;
    USE SIGNAL ;
    SHAPE ABUTMENT ;
    PORT
      LAYER M4 ;
      RECT 0 862.416 0.024 862.44 ;
    END
  END rw0_rd_out[115]
  PIN rw0_rd_out[116]
    DIRECTION OUTPUT ;
    USE SIGNAL ;
    SHAPE ABUTMENT ;
    PORT
      LAYER M4 ;
      RECT 0 863.664 0.024 863.688 ;
    END
  END rw0_rd_out[116]
  PIN rw0_rd_out[117]
    DIRECTION OUTPUT ;
    USE SIGNAL ;
    SHAPE ABUTMENT ;
    PORT
      LAYER M4 ;
      RECT 0 864.912 0.024 864.936 ;
    END
  END rw0_rd_out[117]
  PIN rw0_rd_out[118]
    DIRECTION OUTPUT ;
    USE SIGNAL ;
    SHAPE ABUTMENT ;
    PORT
      LAYER M4 ;
      RECT 0 866.16 0.024 866.184 ;
    END
  END rw0_rd_out[118]
  PIN rw0_rd_out[119]
    DIRECTION OUTPUT ;
    USE SIGNAL ;
    SHAPE ABUTMENT ;
    PORT
      LAYER M4 ;
      RECT 0 867.408 0.024 867.432 ;
    END
  END rw0_rd_out[119]
  PIN rw0_rd_out[120]
    DIRECTION OUTPUT ;
    USE SIGNAL ;
    SHAPE ABUTMENT ;
    PORT
      LAYER M4 ;
      RECT 0 868.656 0.024 868.68 ;
    END
  END rw0_rd_out[120]
  PIN rw0_rd_out[121]
    DIRECTION OUTPUT ;
    USE SIGNAL ;
    SHAPE ABUTMENT ;
    PORT
      LAYER M4 ;
      RECT 0 869.904 0.024 869.928 ;
    END
  END rw0_rd_out[121]
  PIN rw0_rd_out[122]
    DIRECTION OUTPUT ;
    USE SIGNAL ;
    SHAPE ABUTMENT ;
    PORT
      LAYER M4 ;
      RECT 0 871.152 0.024 871.176 ;
    END
  END rw0_rd_out[122]
  PIN rw0_rd_out[123]
    DIRECTION OUTPUT ;
    USE SIGNAL ;
    SHAPE ABUTMENT ;
    PORT
      LAYER M4 ;
      RECT 0 872.4 0.024 872.424 ;
    END
  END rw0_rd_out[123]
  PIN rw0_rd_out[124]
    DIRECTION OUTPUT ;
    USE SIGNAL ;
    SHAPE ABUTMENT ;
    PORT
      LAYER M4 ;
      RECT 0 873.648 0.024 873.672 ;
    END
  END rw0_rd_out[124]
  PIN rw0_rd_out[125]
    DIRECTION OUTPUT ;
    USE SIGNAL ;
    SHAPE ABUTMENT ;
    PORT
      LAYER M4 ;
      RECT 0 874.896 0.024 874.92 ;
    END
  END rw0_rd_out[125]
  PIN rw0_rd_out[126]
    DIRECTION OUTPUT ;
    USE SIGNAL ;
    SHAPE ABUTMENT ;
    PORT
      LAYER M4 ;
      RECT 0 876.144 0.024 876.168 ;
    END
  END rw0_rd_out[126]
  PIN rw0_rd_out[127]
    DIRECTION OUTPUT ;
    USE SIGNAL ;
    SHAPE ABUTMENT ;
    PORT
      LAYER M4 ;
      RECT 0 877.392 0.024 877.416 ;
    END
  END rw0_rd_out[127]
  PIN rw0_rd_out[128]
    DIRECTION OUTPUT ;
    USE SIGNAL ;
    SHAPE ABUTMENT ;
    PORT
      LAYER M4 ;
      RECT 0 878.64 0.024 878.664 ;
    END
  END rw0_rd_out[128]
  PIN rw0_rd_out[129]
    DIRECTION OUTPUT ;
    USE SIGNAL ;
    SHAPE ABUTMENT ;
    PORT
      LAYER M4 ;
      RECT 0 879.888 0.024 879.912 ;
    END
  END rw0_rd_out[129]
  PIN rw0_rd_out[130]
    DIRECTION OUTPUT ;
    USE SIGNAL ;
    SHAPE ABUTMENT ;
    PORT
      LAYER M4 ;
      RECT 0 881.136 0.024 881.16 ;
    END
  END rw0_rd_out[130]
  PIN rw0_rd_out[131]
    DIRECTION OUTPUT ;
    USE SIGNAL ;
    SHAPE ABUTMENT ;
    PORT
      LAYER M4 ;
      RECT 0 882.384 0.024 882.408 ;
    END
  END rw0_rd_out[131]
  PIN rw0_rd_out[132]
    DIRECTION OUTPUT ;
    USE SIGNAL ;
    SHAPE ABUTMENT ;
    PORT
      LAYER M4 ;
      RECT 0 883.632 0.024 883.656 ;
    END
  END rw0_rd_out[132]
  PIN rw0_rd_out[133]
    DIRECTION OUTPUT ;
    USE SIGNAL ;
    SHAPE ABUTMENT ;
    PORT
      LAYER M4 ;
      RECT 0 884.88 0.024 884.904 ;
    END
  END rw0_rd_out[133]
  PIN rw0_rd_out[134]
    DIRECTION OUTPUT ;
    USE SIGNAL ;
    SHAPE ABUTMENT ;
    PORT
      LAYER M4 ;
      RECT 0 886.128 0.024 886.152 ;
    END
  END rw0_rd_out[134]
  PIN rw0_rd_out[135]
    DIRECTION OUTPUT ;
    USE SIGNAL ;
    SHAPE ABUTMENT ;
    PORT
      LAYER M4 ;
      RECT 0 887.376 0.024 887.4 ;
    END
  END rw0_rd_out[135]
  PIN rw0_rd_out[136]
    DIRECTION OUTPUT ;
    USE SIGNAL ;
    SHAPE ABUTMENT ;
    PORT
      LAYER M4 ;
      RECT 0 888.624 0.024 888.648 ;
    END
  END rw0_rd_out[136]
  PIN rw0_rd_out[137]
    DIRECTION OUTPUT ;
    USE SIGNAL ;
    SHAPE ABUTMENT ;
    PORT
      LAYER M4 ;
      RECT 0 889.872 0.024 889.896 ;
    END
  END rw0_rd_out[137]
  PIN rw0_rd_out[138]
    DIRECTION OUTPUT ;
    USE SIGNAL ;
    SHAPE ABUTMENT ;
    PORT
      LAYER M4 ;
      RECT 0 891.12 0.024 891.144 ;
    END
  END rw0_rd_out[138]
  PIN rw0_rd_out[139]
    DIRECTION OUTPUT ;
    USE SIGNAL ;
    SHAPE ABUTMENT ;
    PORT
      LAYER M4 ;
      RECT 0 892.368 0.024 892.392 ;
    END
  END rw0_rd_out[139]
  PIN rw0_rd_out[140]
    DIRECTION OUTPUT ;
    USE SIGNAL ;
    SHAPE ABUTMENT ;
    PORT
      LAYER M4 ;
      RECT 0 893.616 0.024 893.64 ;
    END
  END rw0_rd_out[140]
  PIN rw0_rd_out[141]
    DIRECTION OUTPUT ;
    USE SIGNAL ;
    SHAPE ABUTMENT ;
    PORT
      LAYER M4 ;
      RECT 0 894.864 0.024 894.888 ;
    END
  END rw0_rd_out[141]
  PIN rw0_rd_out[142]
    DIRECTION OUTPUT ;
    USE SIGNAL ;
    SHAPE ABUTMENT ;
    PORT
      LAYER M4 ;
      RECT 0 896.112 0.024 896.136 ;
    END
  END rw0_rd_out[142]
  PIN rw0_rd_out[143]
    DIRECTION OUTPUT ;
    USE SIGNAL ;
    SHAPE ABUTMENT ;
    PORT
      LAYER M4 ;
      RECT 0 897.36 0.024 897.384 ;
    END
  END rw0_rd_out[143]
  PIN rw0_rd_out[144]
    DIRECTION OUTPUT ;
    USE SIGNAL ;
    SHAPE ABUTMENT ;
    PORT
      LAYER M4 ;
      RECT 0 898.608 0.024 898.632 ;
    END
  END rw0_rd_out[144]
  PIN rw0_rd_out[145]
    DIRECTION OUTPUT ;
    USE SIGNAL ;
    SHAPE ABUTMENT ;
    PORT
      LAYER M4 ;
      RECT 0 899.856 0.024 899.88 ;
    END
  END rw0_rd_out[145]
  PIN rw0_rd_out[146]
    DIRECTION OUTPUT ;
    USE SIGNAL ;
    SHAPE ABUTMENT ;
    PORT
      LAYER M4 ;
      RECT 0 901.104 0.024 901.128 ;
    END
  END rw0_rd_out[146]
  PIN rw0_rd_out[147]
    DIRECTION OUTPUT ;
    USE SIGNAL ;
    SHAPE ABUTMENT ;
    PORT
      LAYER M4 ;
      RECT 0 902.352 0.024 902.376 ;
    END
  END rw0_rd_out[147]
  PIN rw0_rd_out[148]
    DIRECTION OUTPUT ;
    USE SIGNAL ;
    SHAPE ABUTMENT ;
    PORT
      LAYER M4 ;
      RECT 0 903.6 0.024 903.624 ;
    END
  END rw0_rd_out[148]
  PIN rw0_rd_out[149]
    DIRECTION OUTPUT ;
    USE SIGNAL ;
    SHAPE ABUTMENT ;
    PORT
      LAYER M4 ;
      RECT 0 904.848 0.024 904.872 ;
    END
  END rw0_rd_out[149]
  PIN rw0_rd_out[150]
    DIRECTION OUTPUT ;
    USE SIGNAL ;
    SHAPE ABUTMENT ;
    PORT
      LAYER M4 ;
      RECT 0 906.096 0.024 906.12 ;
    END
  END rw0_rd_out[150]
  PIN rw0_rd_out[151]
    DIRECTION OUTPUT ;
    USE SIGNAL ;
    SHAPE ABUTMENT ;
    PORT
      LAYER M4 ;
      RECT 0 907.344 0.024 907.368 ;
    END
  END rw0_rd_out[151]
  PIN rw0_rd_out[152]
    DIRECTION OUTPUT ;
    USE SIGNAL ;
    SHAPE ABUTMENT ;
    PORT
      LAYER M4 ;
      RECT 0 908.592 0.024 908.616 ;
    END
  END rw0_rd_out[152]
  PIN rw0_rd_out[153]
    DIRECTION OUTPUT ;
    USE SIGNAL ;
    SHAPE ABUTMENT ;
    PORT
      LAYER M4 ;
      RECT 0 909.84 0.024 909.864 ;
    END
  END rw0_rd_out[153]
  PIN rw0_rd_out[154]
    DIRECTION OUTPUT ;
    USE SIGNAL ;
    SHAPE ABUTMENT ;
    PORT
      LAYER M4 ;
      RECT 0 911.088 0.024 911.112 ;
    END
  END rw0_rd_out[154]
  PIN rw0_rd_out[155]
    DIRECTION OUTPUT ;
    USE SIGNAL ;
    SHAPE ABUTMENT ;
    PORT
      LAYER M4 ;
      RECT 0 912.336 0.024 912.36 ;
    END
  END rw0_rd_out[155]
  PIN rw0_rd_out[156]
    DIRECTION OUTPUT ;
    USE SIGNAL ;
    SHAPE ABUTMENT ;
    PORT
      LAYER M4 ;
      RECT 0 913.584 0.024 913.608 ;
    END
  END rw0_rd_out[156]
  PIN rw0_rd_out[157]
    DIRECTION OUTPUT ;
    USE SIGNAL ;
    SHAPE ABUTMENT ;
    PORT
      LAYER M4 ;
      RECT 0 914.832 0.024 914.856 ;
    END
  END rw0_rd_out[157]
  PIN rw0_rd_out[158]
    DIRECTION OUTPUT ;
    USE SIGNAL ;
    SHAPE ABUTMENT ;
    PORT
      LAYER M4 ;
      RECT 0 916.08 0.024 916.104 ;
    END
  END rw0_rd_out[158]
  PIN rw0_rd_out[159]
    DIRECTION OUTPUT ;
    USE SIGNAL ;
    SHAPE ABUTMENT ;
    PORT
      LAYER M4 ;
      RECT 0 917.328 0.024 917.352 ;
    END
  END rw0_rd_out[159]
  PIN rw0_rd_out[160]
    DIRECTION OUTPUT ;
    USE SIGNAL ;
    SHAPE ABUTMENT ;
    PORT
      LAYER M4 ;
      RECT 0 918.576 0.024 918.6 ;
    END
  END rw0_rd_out[160]
  PIN rw0_rd_out[161]
    DIRECTION OUTPUT ;
    USE SIGNAL ;
    SHAPE ABUTMENT ;
    PORT
      LAYER M4 ;
      RECT 0 919.824 0.024 919.848 ;
    END
  END rw0_rd_out[161]
  PIN rw0_rd_out[162]
    DIRECTION OUTPUT ;
    USE SIGNAL ;
    SHAPE ABUTMENT ;
    PORT
      LAYER M4 ;
      RECT 0 921.072 0.024 921.096 ;
    END
  END rw0_rd_out[162]
  PIN rw0_rd_out[163]
    DIRECTION OUTPUT ;
    USE SIGNAL ;
    SHAPE ABUTMENT ;
    PORT
      LAYER M4 ;
      RECT 0 922.32 0.024 922.344 ;
    END
  END rw0_rd_out[163]
  PIN rw0_rd_out[164]
    DIRECTION OUTPUT ;
    USE SIGNAL ;
    SHAPE ABUTMENT ;
    PORT
      LAYER M4 ;
      RECT 0 923.568 0.024 923.592 ;
    END
  END rw0_rd_out[164]
  PIN rw0_rd_out[165]
    DIRECTION OUTPUT ;
    USE SIGNAL ;
    SHAPE ABUTMENT ;
    PORT
      LAYER M4 ;
      RECT 0 924.816 0.024 924.84 ;
    END
  END rw0_rd_out[165]
  PIN rw0_rd_out[166]
    DIRECTION OUTPUT ;
    USE SIGNAL ;
    SHAPE ABUTMENT ;
    PORT
      LAYER M4 ;
      RECT 0 926.064 0.024 926.088 ;
    END
  END rw0_rd_out[166]
  PIN rw0_rd_out[167]
    DIRECTION OUTPUT ;
    USE SIGNAL ;
    SHAPE ABUTMENT ;
    PORT
      LAYER M4 ;
      RECT 0 927.312 0.024 927.336 ;
    END
  END rw0_rd_out[167]
  PIN rw0_rd_out[168]
    DIRECTION OUTPUT ;
    USE SIGNAL ;
    SHAPE ABUTMENT ;
    PORT
      LAYER M4 ;
      RECT 0 928.56 0.024 928.584 ;
    END
  END rw0_rd_out[168]
  PIN rw0_rd_out[169]
    DIRECTION OUTPUT ;
    USE SIGNAL ;
    SHAPE ABUTMENT ;
    PORT
      LAYER M4 ;
      RECT 0 929.808 0.024 929.832 ;
    END
  END rw0_rd_out[169]
  PIN rw0_rd_out[170]
    DIRECTION OUTPUT ;
    USE SIGNAL ;
    SHAPE ABUTMENT ;
    PORT
      LAYER M4 ;
      RECT 0 931.056 0.024 931.08 ;
    END
  END rw0_rd_out[170]
  PIN rw0_rd_out[171]
    DIRECTION OUTPUT ;
    USE SIGNAL ;
    SHAPE ABUTMENT ;
    PORT
      LAYER M4 ;
      RECT 0 932.304 0.024 932.328 ;
    END
  END rw0_rd_out[171]
  PIN rw0_rd_out[172]
    DIRECTION OUTPUT ;
    USE SIGNAL ;
    SHAPE ABUTMENT ;
    PORT
      LAYER M4 ;
      RECT 0 933.552 0.024 933.576 ;
    END
  END rw0_rd_out[172]
  PIN rw0_rd_out[173]
    DIRECTION OUTPUT ;
    USE SIGNAL ;
    SHAPE ABUTMENT ;
    PORT
      LAYER M4 ;
      RECT 0 934.8 0.024 934.824 ;
    END
  END rw0_rd_out[173]
  PIN rw0_rd_out[174]
    DIRECTION OUTPUT ;
    USE SIGNAL ;
    SHAPE ABUTMENT ;
    PORT
      LAYER M4 ;
      RECT 0 936.048 0.024 936.072 ;
    END
  END rw0_rd_out[174]
  PIN rw0_rd_out[175]
    DIRECTION OUTPUT ;
    USE SIGNAL ;
    SHAPE ABUTMENT ;
    PORT
      LAYER M4 ;
      RECT 0 937.296 0.024 937.32 ;
    END
  END rw0_rd_out[175]
  PIN rw0_rd_out[176]
    DIRECTION OUTPUT ;
    USE SIGNAL ;
    SHAPE ABUTMENT ;
    PORT
      LAYER M4 ;
      RECT 0 938.544 0.024 938.568 ;
    END
  END rw0_rd_out[176]
  PIN rw0_rd_out[177]
    DIRECTION OUTPUT ;
    USE SIGNAL ;
    SHAPE ABUTMENT ;
    PORT
      LAYER M4 ;
      RECT 0 939.792 0.024 939.816 ;
    END
  END rw0_rd_out[177]
  PIN rw0_rd_out[178]
    DIRECTION OUTPUT ;
    USE SIGNAL ;
    SHAPE ABUTMENT ;
    PORT
      LAYER M4 ;
      RECT 0 941.04 0.024 941.064 ;
    END
  END rw0_rd_out[178]
  PIN rw0_rd_out[179]
    DIRECTION OUTPUT ;
    USE SIGNAL ;
    SHAPE ABUTMENT ;
    PORT
      LAYER M4 ;
      RECT 0 942.288 0.024 942.312 ;
    END
  END rw0_rd_out[179]
  PIN rw0_rd_out[180]
    DIRECTION OUTPUT ;
    USE SIGNAL ;
    SHAPE ABUTMENT ;
    PORT
      LAYER M4 ;
      RECT 0 943.536 0.024 943.56 ;
    END
  END rw0_rd_out[180]
  PIN rw0_rd_out[181]
    DIRECTION OUTPUT ;
    USE SIGNAL ;
    SHAPE ABUTMENT ;
    PORT
      LAYER M4 ;
      RECT 0 944.784 0.024 944.808 ;
    END
  END rw0_rd_out[181]
  PIN rw0_rd_out[182]
    DIRECTION OUTPUT ;
    USE SIGNAL ;
    SHAPE ABUTMENT ;
    PORT
      LAYER M4 ;
      RECT 0 946.032 0.024 946.056 ;
    END
  END rw0_rd_out[182]
  PIN rw0_rd_out[183]
    DIRECTION OUTPUT ;
    USE SIGNAL ;
    SHAPE ABUTMENT ;
    PORT
      LAYER M4 ;
      RECT 0 947.28 0.024 947.304 ;
    END
  END rw0_rd_out[183]
  PIN rw0_rd_out[184]
    DIRECTION OUTPUT ;
    USE SIGNAL ;
    SHAPE ABUTMENT ;
    PORT
      LAYER M4 ;
      RECT 0 948.528 0.024 948.552 ;
    END
  END rw0_rd_out[184]
  PIN rw0_rd_out[185]
    DIRECTION OUTPUT ;
    USE SIGNAL ;
    SHAPE ABUTMENT ;
    PORT
      LAYER M4 ;
      RECT 0 949.776 0.024 949.8 ;
    END
  END rw0_rd_out[185]
  PIN rw0_rd_out[186]
    DIRECTION OUTPUT ;
    USE SIGNAL ;
    SHAPE ABUTMENT ;
    PORT
      LAYER M4 ;
      RECT 0 951.024 0.024 951.048 ;
    END
  END rw0_rd_out[186]
  PIN rw0_rd_out[187]
    DIRECTION OUTPUT ;
    USE SIGNAL ;
    SHAPE ABUTMENT ;
    PORT
      LAYER M4 ;
      RECT 0 952.272 0.024 952.296 ;
    END
  END rw0_rd_out[187]
  PIN rw0_rd_out[188]
    DIRECTION OUTPUT ;
    USE SIGNAL ;
    SHAPE ABUTMENT ;
    PORT
      LAYER M4 ;
      RECT 0 953.52 0.024 953.544 ;
    END
  END rw0_rd_out[188]
  PIN rw0_rd_out[189]
    DIRECTION OUTPUT ;
    USE SIGNAL ;
    SHAPE ABUTMENT ;
    PORT
      LAYER M4 ;
      RECT 0 954.768 0.024 954.792 ;
    END
  END rw0_rd_out[189]
  PIN rw0_rd_out[190]
    DIRECTION OUTPUT ;
    USE SIGNAL ;
    SHAPE ABUTMENT ;
    PORT
      LAYER M4 ;
      RECT 0 956.016 0.024 956.04 ;
    END
  END rw0_rd_out[190]
  PIN rw0_rd_out[191]
    DIRECTION OUTPUT ;
    USE SIGNAL ;
    SHAPE ABUTMENT ;
    PORT
      LAYER M4 ;
      RECT 0 957.264 0.024 957.288 ;
    END
  END rw0_rd_out[191]
  PIN rw0_rd_out[192]
    DIRECTION OUTPUT ;
    USE SIGNAL ;
    SHAPE ABUTMENT ;
    PORT
      LAYER M4 ;
      RECT 0 958.512 0.024 958.536 ;
    END
  END rw0_rd_out[192]
  PIN rw0_rd_out[193]
    DIRECTION OUTPUT ;
    USE SIGNAL ;
    SHAPE ABUTMENT ;
    PORT
      LAYER M4 ;
      RECT 0 959.76 0.024 959.784 ;
    END
  END rw0_rd_out[193]
  PIN rw0_rd_out[194]
    DIRECTION OUTPUT ;
    USE SIGNAL ;
    SHAPE ABUTMENT ;
    PORT
      LAYER M4 ;
      RECT 0 961.008 0.024 961.032 ;
    END
  END rw0_rd_out[194]
  PIN rw0_rd_out[195]
    DIRECTION OUTPUT ;
    USE SIGNAL ;
    SHAPE ABUTMENT ;
    PORT
      LAYER M4 ;
      RECT 0 962.256 0.024 962.28 ;
    END
  END rw0_rd_out[195]
  PIN rw0_rd_out[196]
    DIRECTION OUTPUT ;
    USE SIGNAL ;
    SHAPE ABUTMENT ;
    PORT
      LAYER M4 ;
      RECT 0 963.504 0.024 963.528 ;
    END
  END rw0_rd_out[196]
  PIN rw0_rd_out[197]
    DIRECTION OUTPUT ;
    USE SIGNAL ;
    SHAPE ABUTMENT ;
    PORT
      LAYER M4 ;
      RECT 0 964.752 0.024 964.776 ;
    END
  END rw0_rd_out[197]
  PIN rw0_rd_out[198]
    DIRECTION OUTPUT ;
    USE SIGNAL ;
    SHAPE ABUTMENT ;
    PORT
      LAYER M4 ;
      RECT 0 966 0.024 966.024 ;
    END
  END rw0_rd_out[198]
  PIN rw0_rd_out[199]
    DIRECTION OUTPUT ;
    USE SIGNAL ;
    SHAPE ABUTMENT ;
    PORT
      LAYER M4 ;
      RECT 0 967.248 0.024 967.272 ;
    END
  END rw0_rd_out[199]
  PIN rw0_rd_out[200]
    DIRECTION OUTPUT ;
    USE SIGNAL ;
    SHAPE ABUTMENT ;
    PORT
      LAYER M4 ;
      RECT 0 968.496 0.024 968.52 ;
    END
  END rw0_rd_out[200]
  PIN rw0_rd_out[201]
    DIRECTION OUTPUT ;
    USE SIGNAL ;
    SHAPE ABUTMENT ;
    PORT
      LAYER M4 ;
      RECT 0 969.744 0.024 969.768 ;
    END
  END rw0_rd_out[201]
  PIN rw0_rd_out[202]
    DIRECTION OUTPUT ;
    USE SIGNAL ;
    SHAPE ABUTMENT ;
    PORT
      LAYER M4 ;
      RECT 0 970.992 0.024 971.016 ;
    END
  END rw0_rd_out[202]
  PIN rw0_rd_out[203]
    DIRECTION OUTPUT ;
    USE SIGNAL ;
    SHAPE ABUTMENT ;
    PORT
      LAYER M4 ;
      RECT 0 972.24 0.024 972.264 ;
    END
  END rw0_rd_out[203]
  PIN rw0_rd_out[204]
    DIRECTION OUTPUT ;
    USE SIGNAL ;
    SHAPE ABUTMENT ;
    PORT
      LAYER M4 ;
      RECT 0 973.488 0.024 973.512 ;
    END
  END rw0_rd_out[204]
  PIN rw0_rd_out[205]
    DIRECTION OUTPUT ;
    USE SIGNAL ;
    SHAPE ABUTMENT ;
    PORT
      LAYER M4 ;
      RECT 0 974.736 0.024 974.76 ;
    END
  END rw0_rd_out[205]
  PIN rw0_rd_out[206]
    DIRECTION OUTPUT ;
    USE SIGNAL ;
    SHAPE ABUTMENT ;
    PORT
      LAYER M4 ;
      RECT 0 975.984 0.024 976.008 ;
    END
  END rw0_rd_out[206]
  PIN rw0_rd_out[207]
    DIRECTION OUTPUT ;
    USE SIGNAL ;
    SHAPE ABUTMENT ;
    PORT
      LAYER M4 ;
      RECT 0 977.232 0.024 977.256 ;
    END
  END rw0_rd_out[207]
  PIN rw0_rd_out[208]
    DIRECTION OUTPUT ;
    USE SIGNAL ;
    SHAPE ABUTMENT ;
    PORT
      LAYER M4 ;
      RECT 0 978.48 0.024 978.504 ;
    END
  END rw0_rd_out[208]
  PIN rw0_rd_out[209]
    DIRECTION OUTPUT ;
    USE SIGNAL ;
    SHAPE ABUTMENT ;
    PORT
      LAYER M4 ;
      RECT 0 979.728 0.024 979.752 ;
    END
  END rw0_rd_out[209]
  PIN rw0_rd_out[210]
    DIRECTION OUTPUT ;
    USE SIGNAL ;
    SHAPE ABUTMENT ;
    PORT
      LAYER M4 ;
      RECT 0 980.976 0.024 981 ;
    END
  END rw0_rd_out[210]
  PIN rw0_rd_out[211]
    DIRECTION OUTPUT ;
    USE SIGNAL ;
    SHAPE ABUTMENT ;
    PORT
      LAYER M4 ;
      RECT 0 982.224 0.024 982.248 ;
    END
  END rw0_rd_out[211]
  PIN rw0_rd_out[212]
    DIRECTION OUTPUT ;
    USE SIGNAL ;
    SHAPE ABUTMENT ;
    PORT
      LAYER M4 ;
      RECT 0 983.472 0.024 983.496 ;
    END
  END rw0_rd_out[212]
  PIN rw0_rd_out[213]
    DIRECTION OUTPUT ;
    USE SIGNAL ;
    SHAPE ABUTMENT ;
    PORT
      LAYER M4 ;
      RECT 0 984.72 0.024 984.744 ;
    END
  END rw0_rd_out[213]
  PIN rw0_rd_out[214]
    DIRECTION OUTPUT ;
    USE SIGNAL ;
    SHAPE ABUTMENT ;
    PORT
      LAYER M4 ;
      RECT 0 985.968 0.024 985.992 ;
    END
  END rw0_rd_out[214]
  PIN rw0_rd_out[215]
    DIRECTION OUTPUT ;
    USE SIGNAL ;
    SHAPE ABUTMENT ;
    PORT
      LAYER M4 ;
      RECT 0 987.216 0.024 987.24 ;
    END
  END rw0_rd_out[215]
  PIN rw0_rd_out[216]
    DIRECTION OUTPUT ;
    USE SIGNAL ;
    SHAPE ABUTMENT ;
    PORT
      LAYER M4 ;
      RECT 0 988.464 0.024 988.488 ;
    END
  END rw0_rd_out[216]
  PIN rw0_rd_out[217]
    DIRECTION OUTPUT ;
    USE SIGNAL ;
    SHAPE ABUTMENT ;
    PORT
      LAYER M4 ;
      RECT 0 989.712 0.024 989.736 ;
    END
  END rw0_rd_out[217]
  PIN rw0_rd_out[218]
    DIRECTION OUTPUT ;
    USE SIGNAL ;
    SHAPE ABUTMENT ;
    PORT
      LAYER M4 ;
      RECT 0 990.96 0.024 990.984 ;
    END
  END rw0_rd_out[218]
  PIN rw0_rd_out[219]
    DIRECTION OUTPUT ;
    USE SIGNAL ;
    SHAPE ABUTMENT ;
    PORT
      LAYER M4 ;
      RECT 0 992.208 0.024 992.232 ;
    END
  END rw0_rd_out[219]
  PIN rw0_rd_out[220]
    DIRECTION OUTPUT ;
    USE SIGNAL ;
    SHAPE ABUTMENT ;
    PORT
      LAYER M4 ;
      RECT 0 993.456 0.024 993.48 ;
    END
  END rw0_rd_out[220]
  PIN rw0_rd_out[221]
    DIRECTION OUTPUT ;
    USE SIGNAL ;
    SHAPE ABUTMENT ;
    PORT
      LAYER M4 ;
      RECT 0 994.704 0.024 994.728 ;
    END
  END rw0_rd_out[221]
  PIN rw0_rd_out[222]
    DIRECTION OUTPUT ;
    USE SIGNAL ;
    SHAPE ABUTMENT ;
    PORT
      LAYER M4 ;
      RECT 0 995.952 0.024 995.976 ;
    END
  END rw0_rd_out[222]
  PIN rw0_rd_out[223]
    DIRECTION OUTPUT ;
    USE SIGNAL ;
    SHAPE ABUTMENT ;
    PORT
      LAYER M4 ;
      RECT 0 997.2 0.024 997.224 ;
    END
  END rw0_rd_out[223]
  PIN rw0_rd_out[224]
    DIRECTION OUTPUT ;
    USE SIGNAL ;
    SHAPE ABUTMENT ;
    PORT
      LAYER M4 ;
      RECT 0 998.448 0.024 998.472 ;
    END
  END rw0_rd_out[224]
  PIN rw0_rd_out[225]
    DIRECTION OUTPUT ;
    USE SIGNAL ;
    SHAPE ABUTMENT ;
    PORT
      LAYER M4 ;
      RECT 0 999.696 0.024 999.72 ;
    END
  END rw0_rd_out[225]
  PIN rw0_rd_out[226]
    DIRECTION OUTPUT ;
    USE SIGNAL ;
    SHAPE ABUTMENT ;
    PORT
      LAYER M4 ;
      RECT 0 1000.944 0.024 1000.968 ;
    END
  END rw0_rd_out[226]
  PIN rw0_rd_out[227]
    DIRECTION OUTPUT ;
    USE SIGNAL ;
    SHAPE ABUTMENT ;
    PORT
      LAYER M4 ;
      RECT 0 1002.192 0.024 1002.216 ;
    END
  END rw0_rd_out[227]
  PIN rw0_rd_out[228]
    DIRECTION OUTPUT ;
    USE SIGNAL ;
    SHAPE ABUTMENT ;
    PORT
      LAYER M4 ;
      RECT 0 1003.44 0.024 1003.464 ;
    END
  END rw0_rd_out[228]
  PIN rw0_rd_out[229]
    DIRECTION OUTPUT ;
    USE SIGNAL ;
    SHAPE ABUTMENT ;
    PORT
      LAYER M4 ;
      RECT 0 1004.688 0.024 1004.712 ;
    END
  END rw0_rd_out[229]
  PIN rw0_rd_out[230]
    DIRECTION OUTPUT ;
    USE SIGNAL ;
    SHAPE ABUTMENT ;
    PORT
      LAYER M4 ;
      RECT 0 1005.936 0.024 1005.96 ;
    END
  END rw0_rd_out[230]
  PIN rw0_rd_out[231]
    DIRECTION OUTPUT ;
    USE SIGNAL ;
    SHAPE ABUTMENT ;
    PORT
      LAYER M4 ;
      RECT 0 1007.184 0.024 1007.208 ;
    END
  END rw0_rd_out[231]
  PIN rw0_rd_out[232]
    DIRECTION OUTPUT ;
    USE SIGNAL ;
    SHAPE ABUTMENT ;
    PORT
      LAYER M4 ;
      RECT 0 1008.432 0.024 1008.456 ;
    END
  END rw0_rd_out[232]
  PIN rw0_rd_out[233]
    DIRECTION OUTPUT ;
    USE SIGNAL ;
    SHAPE ABUTMENT ;
    PORT
      LAYER M4 ;
      RECT 0 1009.68 0.024 1009.704 ;
    END
  END rw0_rd_out[233]
  PIN rw0_rd_out[234]
    DIRECTION OUTPUT ;
    USE SIGNAL ;
    SHAPE ABUTMENT ;
    PORT
      LAYER M4 ;
      RECT 0 1010.928 0.024 1010.952 ;
    END
  END rw0_rd_out[234]
  PIN rw0_rd_out[235]
    DIRECTION OUTPUT ;
    USE SIGNAL ;
    SHAPE ABUTMENT ;
    PORT
      LAYER M4 ;
      RECT 0 1012.176 0.024 1012.2 ;
    END
  END rw0_rd_out[235]
  PIN rw0_rd_out[236]
    DIRECTION OUTPUT ;
    USE SIGNAL ;
    SHAPE ABUTMENT ;
    PORT
      LAYER M4 ;
      RECT 0 1013.424 0.024 1013.448 ;
    END
  END rw0_rd_out[236]
  PIN rw0_rd_out[237]
    DIRECTION OUTPUT ;
    USE SIGNAL ;
    SHAPE ABUTMENT ;
    PORT
      LAYER M4 ;
      RECT 0 1014.672 0.024 1014.696 ;
    END
  END rw0_rd_out[237]
  PIN rw0_rd_out[238]
    DIRECTION OUTPUT ;
    USE SIGNAL ;
    SHAPE ABUTMENT ;
    PORT
      LAYER M4 ;
      RECT 0 1015.92 0.024 1015.944 ;
    END
  END rw0_rd_out[238]
  PIN rw0_rd_out[239]
    DIRECTION OUTPUT ;
    USE SIGNAL ;
    SHAPE ABUTMENT ;
    PORT
      LAYER M4 ;
      RECT 0 1017.168 0.024 1017.192 ;
    END
  END rw0_rd_out[239]
  PIN rw0_rd_out[240]
    DIRECTION OUTPUT ;
    USE SIGNAL ;
    SHAPE ABUTMENT ;
    PORT
      LAYER M4 ;
      RECT 0 1018.416 0.024 1018.44 ;
    END
  END rw0_rd_out[240]
  PIN rw0_rd_out[241]
    DIRECTION OUTPUT ;
    USE SIGNAL ;
    SHAPE ABUTMENT ;
    PORT
      LAYER M4 ;
      RECT 0 1019.664 0.024 1019.688 ;
    END
  END rw0_rd_out[241]
  PIN rw0_rd_out[242]
    DIRECTION OUTPUT ;
    USE SIGNAL ;
    SHAPE ABUTMENT ;
    PORT
      LAYER M4 ;
      RECT 0 1020.912 0.024 1020.936 ;
    END
  END rw0_rd_out[242]
  PIN rw0_rd_out[243]
    DIRECTION OUTPUT ;
    USE SIGNAL ;
    SHAPE ABUTMENT ;
    PORT
      LAYER M4 ;
      RECT 0 1022.16 0.024 1022.184 ;
    END
  END rw0_rd_out[243]
  PIN rw0_rd_out[244]
    DIRECTION OUTPUT ;
    USE SIGNAL ;
    SHAPE ABUTMENT ;
    PORT
      LAYER M4 ;
      RECT 0 1023.408 0.024 1023.432 ;
    END
  END rw0_rd_out[244]
  PIN rw0_rd_out[245]
    DIRECTION OUTPUT ;
    USE SIGNAL ;
    SHAPE ABUTMENT ;
    PORT
      LAYER M4 ;
      RECT 0 1024.656 0.024 1024.68 ;
    END
  END rw0_rd_out[245]
  PIN rw0_rd_out[246]
    DIRECTION OUTPUT ;
    USE SIGNAL ;
    SHAPE ABUTMENT ;
    PORT
      LAYER M4 ;
      RECT 0 1025.904 0.024 1025.928 ;
    END
  END rw0_rd_out[246]
  PIN rw0_rd_out[247]
    DIRECTION OUTPUT ;
    USE SIGNAL ;
    SHAPE ABUTMENT ;
    PORT
      LAYER M4 ;
      RECT 0 1027.152 0.024 1027.176 ;
    END
  END rw0_rd_out[247]
  PIN rw0_rd_out[248]
    DIRECTION OUTPUT ;
    USE SIGNAL ;
    SHAPE ABUTMENT ;
    PORT
      LAYER M4 ;
      RECT 0 1028.4 0.024 1028.424 ;
    END
  END rw0_rd_out[248]
  PIN rw0_rd_out[249]
    DIRECTION OUTPUT ;
    USE SIGNAL ;
    SHAPE ABUTMENT ;
    PORT
      LAYER M4 ;
      RECT 0 1029.648 0.024 1029.672 ;
    END
  END rw0_rd_out[249]
  PIN rw0_rd_out[250]
    DIRECTION OUTPUT ;
    USE SIGNAL ;
    SHAPE ABUTMENT ;
    PORT
      LAYER M4 ;
      RECT 0 1030.896 0.024 1030.92 ;
    END
  END rw0_rd_out[250]
  PIN rw0_rd_out[251]
    DIRECTION OUTPUT ;
    USE SIGNAL ;
    SHAPE ABUTMENT ;
    PORT
      LAYER M4 ;
      RECT 0 1032.144 0.024 1032.168 ;
    END
  END rw0_rd_out[251]
  PIN rw0_rd_out[252]
    DIRECTION OUTPUT ;
    USE SIGNAL ;
    SHAPE ABUTMENT ;
    PORT
      LAYER M4 ;
      RECT 0 1033.392 0.024 1033.416 ;
    END
  END rw0_rd_out[252]
  PIN rw0_rd_out[253]
    DIRECTION OUTPUT ;
    USE SIGNAL ;
    SHAPE ABUTMENT ;
    PORT
      LAYER M4 ;
      RECT 0 1034.64 0.024 1034.664 ;
    END
  END rw0_rd_out[253]
  PIN rw0_rd_out[254]
    DIRECTION OUTPUT ;
    USE SIGNAL ;
    SHAPE ABUTMENT ;
    PORT
      LAYER M4 ;
      RECT 0 1035.888 0.024 1035.912 ;
    END
  END rw0_rd_out[254]
  PIN rw0_rd_out[255]
    DIRECTION OUTPUT ;
    USE SIGNAL ;
    SHAPE ABUTMENT ;
    PORT
      LAYER M4 ;
      RECT 0 1037.136 0.024 1037.16 ;
    END
  END rw0_rd_out[255]
  PIN rw0_rd_out[256]
    DIRECTION OUTPUT ;
    USE SIGNAL ;
    SHAPE ABUTMENT ;
    PORT
      LAYER M4 ;
      RECT 0 1038.384 0.024 1038.408 ;
    END
  END rw0_rd_out[256]
  PIN rw0_rd_out[257]
    DIRECTION OUTPUT ;
    USE SIGNAL ;
    SHAPE ABUTMENT ;
    PORT
      LAYER M4 ;
      RECT 0 1039.632 0.024 1039.656 ;
    END
  END rw0_rd_out[257]
  PIN rw0_rd_out[258]
    DIRECTION OUTPUT ;
    USE SIGNAL ;
    SHAPE ABUTMENT ;
    PORT
      LAYER M4 ;
      RECT 0 1040.88 0.024 1040.904 ;
    END
  END rw0_rd_out[258]
  PIN rw0_rd_out[259]
    DIRECTION OUTPUT ;
    USE SIGNAL ;
    SHAPE ABUTMENT ;
    PORT
      LAYER M4 ;
      RECT 0 1042.128 0.024 1042.152 ;
    END
  END rw0_rd_out[259]
  PIN rw0_rd_out[260]
    DIRECTION OUTPUT ;
    USE SIGNAL ;
    SHAPE ABUTMENT ;
    PORT
      LAYER M4 ;
      RECT 0 1043.376 0.024 1043.4 ;
    END
  END rw0_rd_out[260]
  PIN rw0_rd_out[261]
    DIRECTION OUTPUT ;
    USE SIGNAL ;
    SHAPE ABUTMENT ;
    PORT
      LAYER M4 ;
      RECT 0 1044.624 0.024 1044.648 ;
    END
  END rw0_rd_out[261]
  PIN rw0_rd_out[262]
    DIRECTION OUTPUT ;
    USE SIGNAL ;
    SHAPE ABUTMENT ;
    PORT
      LAYER M4 ;
      RECT 0 1045.872 0.024 1045.896 ;
    END
  END rw0_rd_out[262]
  PIN rw0_rd_out[263]
    DIRECTION OUTPUT ;
    USE SIGNAL ;
    SHAPE ABUTMENT ;
    PORT
      LAYER M4 ;
      RECT 0 1047.12 0.024 1047.144 ;
    END
  END rw0_rd_out[263]
  PIN rw0_rd_out[264]
    DIRECTION OUTPUT ;
    USE SIGNAL ;
    SHAPE ABUTMENT ;
    PORT
      LAYER M4 ;
      RECT 0 1048.368 0.024 1048.392 ;
    END
  END rw0_rd_out[264]
  PIN rw0_rd_out[265]
    DIRECTION OUTPUT ;
    USE SIGNAL ;
    SHAPE ABUTMENT ;
    PORT
      LAYER M4 ;
      RECT 0 1049.616 0.024 1049.64 ;
    END
  END rw0_rd_out[265]
  PIN rw0_rd_out[266]
    DIRECTION OUTPUT ;
    USE SIGNAL ;
    SHAPE ABUTMENT ;
    PORT
      LAYER M4 ;
      RECT 0 1050.864 0.024 1050.888 ;
    END
  END rw0_rd_out[266]
  PIN rw0_rd_out[267]
    DIRECTION OUTPUT ;
    USE SIGNAL ;
    SHAPE ABUTMENT ;
    PORT
      LAYER M4 ;
      RECT 0 1052.112 0.024 1052.136 ;
    END
  END rw0_rd_out[267]
  PIN rw0_rd_out[268]
    DIRECTION OUTPUT ;
    USE SIGNAL ;
    SHAPE ABUTMENT ;
    PORT
      LAYER M4 ;
      RECT 0 1053.36 0.024 1053.384 ;
    END
  END rw0_rd_out[268]
  PIN rw0_rd_out[269]
    DIRECTION OUTPUT ;
    USE SIGNAL ;
    SHAPE ABUTMENT ;
    PORT
      LAYER M4 ;
      RECT 0 1054.608 0.024 1054.632 ;
    END
  END rw0_rd_out[269]
  PIN rw0_rd_out[270]
    DIRECTION OUTPUT ;
    USE SIGNAL ;
    SHAPE ABUTMENT ;
    PORT
      LAYER M4 ;
      RECT 0 1055.856 0.024 1055.88 ;
    END
  END rw0_rd_out[270]
  PIN rw0_rd_out[271]
    DIRECTION OUTPUT ;
    USE SIGNAL ;
    SHAPE ABUTMENT ;
    PORT
      LAYER M4 ;
      RECT 0 1057.104 0.024 1057.128 ;
    END
  END rw0_rd_out[271]
  PIN rw0_rd_out[272]
    DIRECTION OUTPUT ;
    USE SIGNAL ;
    SHAPE ABUTMENT ;
    PORT
      LAYER M4 ;
      RECT 0 1058.352 0.024 1058.376 ;
    END
  END rw0_rd_out[272]
  PIN rw0_rd_out[273]
    DIRECTION OUTPUT ;
    USE SIGNAL ;
    SHAPE ABUTMENT ;
    PORT
      LAYER M4 ;
      RECT 0 1059.6 0.024 1059.624 ;
    END
  END rw0_rd_out[273]
  PIN rw0_rd_out[274]
    DIRECTION OUTPUT ;
    USE SIGNAL ;
    SHAPE ABUTMENT ;
    PORT
      LAYER M4 ;
      RECT 0 1060.848 0.024 1060.872 ;
    END
  END rw0_rd_out[274]
  PIN rw0_rd_out[275]
    DIRECTION OUTPUT ;
    USE SIGNAL ;
    SHAPE ABUTMENT ;
    PORT
      LAYER M4 ;
      RECT 0 1062.096 0.024 1062.12 ;
    END
  END rw0_rd_out[275]
  PIN rw0_rd_out[276]
    DIRECTION OUTPUT ;
    USE SIGNAL ;
    SHAPE ABUTMENT ;
    PORT
      LAYER M4 ;
      RECT 0 1063.344 0.024 1063.368 ;
    END
  END rw0_rd_out[276]
  PIN rw0_rd_out[277]
    DIRECTION OUTPUT ;
    USE SIGNAL ;
    SHAPE ABUTMENT ;
    PORT
      LAYER M4 ;
      RECT 0 1064.592 0.024 1064.616 ;
    END
  END rw0_rd_out[277]
  PIN rw0_rd_out[278]
    DIRECTION OUTPUT ;
    USE SIGNAL ;
    SHAPE ABUTMENT ;
    PORT
      LAYER M4 ;
      RECT 0 1065.84 0.024 1065.864 ;
    END
  END rw0_rd_out[278]
  PIN rw0_rd_out[279]
    DIRECTION OUTPUT ;
    USE SIGNAL ;
    SHAPE ABUTMENT ;
    PORT
      LAYER M4 ;
      RECT 0 1067.088 0.024 1067.112 ;
    END
  END rw0_rd_out[279]
  PIN rw0_rd_out[280]
    DIRECTION OUTPUT ;
    USE SIGNAL ;
    SHAPE ABUTMENT ;
    PORT
      LAYER M4 ;
      RECT 0 1068.336 0.024 1068.36 ;
    END
  END rw0_rd_out[280]
  PIN rw0_rd_out[281]
    DIRECTION OUTPUT ;
    USE SIGNAL ;
    SHAPE ABUTMENT ;
    PORT
      LAYER M4 ;
      RECT 0 1069.584 0.024 1069.608 ;
    END
  END rw0_rd_out[281]
  PIN rw0_rd_out[282]
    DIRECTION OUTPUT ;
    USE SIGNAL ;
    SHAPE ABUTMENT ;
    PORT
      LAYER M4 ;
      RECT 0 1070.832 0.024 1070.856 ;
    END
  END rw0_rd_out[282]
  PIN rw0_rd_out[283]
    DIRECTION OUTPUT ;
    USE SIGNAL ;
    SHAPE ABUTMENT ;
    PORT
      LAYER M4 ;
      RECT 0 1072.08 0.024 1072.104 ;
    END
  END rw0_rd_out[283]
  PIN rw0_rd_out[284]
    DIRECTION OUTPUT ;
    USE SIGNAL ;
    SHAPE ABUTMENT ;
    PORT
      LAYER M4 ;
      RECT 0 1073.328 0.024 1073.352 ;
    END
  END rw0_rd_out[284]
  PIN rw0_rd_out[285]
    DIRECTION OUTPUT ;
    USE SIGNAL ;
    SHAPE ABUTMENT ;
    PORT
      LAYER M4 ;
      RECT 0 1074.576 0.024 1074.6 ;
    END
  END rw0_rd_out[285]
  PIN rw0_rd_out[286]
    DIRECTION OUTPUT ;
    USE SIGNAL ;
    SHAPE ABUTMENT ;
    PORT
      LAYER M4 ;
      RECT 0 1075.824 0.024 1075.848 ;
    END
  END rw0_rd_out[286]
  PIN rw0_rd_out[287]
    DIRECTION OUTPUT ;
    USE SIGNAL ;
    SHAPE ABUTMENT ;
    PORT
      LAYER M4 ;
      RECT 0 1077.072 0.024 1077.096 ;
    END
  END rw0_rd_out[287]
  PIN rw0_rd_out[288]
    DIRECTION OUTPUT ;
    USE SIGNAL ;
    SHAPE ABUTMENT ;
    PORT
      LAYER M4 ;
      RECT 0 1078.32 0.024 1078.344 ;
    END
  END rw0_rd_out[288]
  PIN rw0_rd_out[289]
    DIRECTION OUTPUT ;
    USE SIGNAL ;
    SHAPE ABUTMENT ;
    PORT
      LAYER M4 ;
      RECT 0 1079.568 0.024 1079.592 ;
    END
  END rw0_rd_out[289]
  PIN rw0_rd_out[290]
    DIRECTION OUTPUT ;
    USE SIGNAL ;
    SHAPE ABUTMENT ;
    PORT
      LAYER M4 ;
      RECT 0 1080.816 0.024 1080.84 ;
    END
  END rw0_rd_out[290]
  PIN rw0_rd_out[291]
    DIRECTION OUTPUT ;
    USE SIGNAL ;
    SHAPE ABUTMENT ;
    PORT
      LAYER M4 ;
      RECT 0 1082.064 0.024 1082.088 ;
    END
  END rw0_rd_out[291]
  PIN rw0_rd_out[292]
    DIRECTION OUTPUT ;
    USE SIGNAL ;
    SHAPE ABUTMENT ;
    PORT
      LAYER M4 ;
      RECT 0 1083.312 0.024 1083.336 ;
    END
  END rw0_rd_out[292]
  PIN rw0_rd_out[293]
    DIRECTION OUTPUT ;
    USE SIGNAL ;
    SHAPE ABUTMENT ;
    PORT
      LAYER M4 ;
      RECT 0 1084.56 0.024 1084.584 ;
    END
  END rw0_rd_out[293]
  PIN rw0_rd_out[294]
    DIRECTION OUTPUT ;
    USE SIGNAL ;
    SHAPE ABUTMENT ;
    PORT
      LAYER M4 ;
      RECT 0 1085.808 0.024 1085.832 ;
    END
  END rw0_rd_out[294]
  PIN rw0_rd_out[295]
    DIRECTION OUTPUT ;
    USE SIGNAL ;
    SHAPE ABUTMENT ;
    PORT
      LAYER M4 ;
      RECT 0 1087.056 0.024 1087.08 ;
    END
  END rw0_rd_out[295]
  PIN rw0_rd_out[296]
    DIRECTION OUTPUT ;
    USE SIGNAL ;
    SHAPE ABUTMENT ;
    PORT
      LAYER M4 ;
      RECT 0 1088.304 0.024 1088.328 ;
    END
  END rw0_rd_out[296]
  PIN rw0_rd_out[297]
    DIRECTION OUTPUT ;
    USE SIGNAL ;
    SHAPE ABUTMENT ;
    PORT
      LAYER M4 ;
      RECT 0 1089.552 0.024 1089.576 ;
    END
  END rw0_rd_out[297]
  PIN rw0_rd_out[298]
    DIRECTION OUTPUT ;
    USE SIGNAL ;
    SHAPE ABUTMENT ;
    PORT
      LAYER M4 ;
      RECT 0 1090.8 0.024 1090.824 ;
    END
  END rw0_rd_out[298]
  PIN rw0_rd_out[299]
    DIRECTION OUTPUT ;
    USE SIGNAL ;
    SHAPE ABUTMENT ;
    PORT
      LAYER M4 ;
      RECT 0 1092.048 0.024 1092.072 ;
    END
  END rw0_rd_out[299]
  PIN rw0_rd_out[300]
    DIRECTION OUTPUT ;
    USE SIGNAL ;
    SHAPE ABUTMENT ;
    PORT
      LAYER M4 ;
      RECT 0 1093.296 0.024 1093.32 ;
    END
  END rw0_rd_out[300]
  PIN rw0_rd_out[301]
    DIRECTION OUTPUT ;
    USE SIGNAL ;
    SHAPE ABUTMENT ;
    PORT
      LAYER M4 ;
      RECT 0 1094.544 0.024 1094.568 ;
    END
  END rw0_rd_out[301]
  PIN rw0_rd_out[302]
    DIRECTION OUTPUT ;
    USE SIGNAL ;
    SHAPE ABUTMENT ;
    PORT
      LAYER M4 ;
      RECT 0 1095.792 0.024 1095.816 ;
    END
  END rw0_rd_out[302]
  PIN rw0_rd_out[303]
    DIRECTION OUTPUT ;
    USE SIGNAL ;
    SHAPE ABUTMENT ;
    PORT
      LAYER M4 ;
      RECT 0 1097.04 0.024 1097.064 ;
    END
  END rw0_rd_out[303]
  PIN rw0_rd_out[304]
    DIRECTION OUTPUT ;
    USE SIGNAL ;
    SHAPE ABUTMENT ;
    PORT
      LAYER M4 ;
      RECT 0 1098.288 0.024 1098.312 ;
    END
  END rw0_rd_out[304]
  PIN rw0_rd_out[305]
    DIRECTION OUTPUT ;
    USE SIGNAL ;
    SHAPE ABUTMENT ;
    PORT
      LAYER M4 ;
      RECT 0 1099.536 0.024 1099.56 ;
    END
  END rw0_rd_out[305]
  PIN rw0_rd_out[306]
    DIRECTION OUTPUT ;
    USE SIGNAL ;
    SHAPE ABUTMENT ;
    PORT
      LAYER M4 ;
      RECT 0 1100.784 0.024 1100.808 ;
    END
  END rw0_rd_out[306]
  PIN rw0_rd_out[307]
    DIRECTION OUTPUT ;
    USE SIGNAL ;
    SHAPE ABUTMENT ;
    PORT
      LAYER M4 ;
      RECT 0 1102.032 0.024 1102.056 ;
    END
  END rw0_rd_out[307]
  PIN rw0_rd_out[308]
    DIRECTION OUTPUT ;
    USE SIGNAL ;
    SHAPE ABUTMENT ;
    PORT
      LAYER M4 ;
      RECT 0 1103.28 0.024 1103.304 ;
    END
  END rw0_rd_out[308]
  PIN rw0_rd_out[309]
    DIRECTION OUTPUT ;
    USE SIGNAL ;
    SHAPE ABUTMENT ;
    PORT
      LAYER M4 ;
      RECT 0 1104.528 0.024 1104.552 ;
    END
  END rw0_rd_out[309]
  PIN rw0_rd_out[310]
    DIRECTION OUTPUT ;
    USE SIGNAL ;
    SHAPE ABUTMENT ;
    PORT
      LAYER M4 ;
      RECT 0 1105.776 0.024 1105.8 ;
    END
  END rw0_rd_out[310]
  PIN rw0_rd_out[311]
    DIRECTION OUTPUT ;
    USE SIGNAL ;
    SHAPE ABUTMENT ;
    PORT
      LAYER M4 ;
      RECT 0 1107.024 0.024 1107.048 ;
    END
  END rw0_rd_out[311]
  PIN rw0_rd_out[312]
    DIRECTION OUTPUT ;
    USE SIGNAL ;
    SHAPE ABUTMENT ;
    PORT
      LAYER M4 ;
      RECT 0 1108.272 0.024 1108.296 ;
    END
  END rw0_rd_out[312]
  PIN rw0_rd_out[313]
    DIRECTION OUTPUT ;
    USE SIGNAL ;
    SHAPE ABUTMENT ;
    PORT
      LAYER M4 ;
      RECT 0 1109.52 0.024 1109.544 ;
    END
  END rw0_rd_out[313]
  PIN rw0_rd_out[314]
    DIRECTION OUTPUT ;
    USE SIGNAL ;
    SHAPE ABUTMENT ;
    PORT
      LAYER M4 ;
      RECT 0 1110.768 0.024 1110.792 ;
    END
  END rw0_rd_out[314]
  PIN rw0_rd_out[315]
    DIRECTION OUTPUT ;
    USE SIGNAL ;
    SHAPE ABUTMENT ;
    PORT
      LAYER M4 ;
      RECT 0 1112.016 0.024 1112.04 ;
    END
  END rw0_rd_out[315]
  PIN rw0_rd_out[316]
    DIRECTION OUTPUT ;
    USE SIGNAL ;
    SHAPE ABUTMENT ;
    PORT
      LAYER M4 ;
      RECT 0 1113.264 0.024 1113.288 ;
    END
  END rw0_rd_out[316]
  PIN rw0_rd_out[317]
    DIRECTION OUTPUT ;
    USE SIGNAL ;
    SHAPE ABUTMENT ;
    PORT
      LAYER M4 ;
      RECT 0 1114.512 0.024 1114.536 ;
    END
  END rw0_rd_out[317]
  PIN rw0_rd_out[318]
    DIRECTION OUTPUT ;
    USE SIGNAL ;
    SHAPE ABUTMENT ;
    PORT
      LAYER M4 ;
      RECT 0 1115.76 0.024 1115.784 ;
    END
  END rw0_rd_out[318]
  PIN rw0_rd_out[319]
    DIRECTION OUTPUT ;
    USE SIGNAL ;
    SHAPE ABUTMENT ;
    PORT
      LAYER M4 ;
      RECT 0 1117.008 0.024 1117.032 ;
    END
  END rw0_rd_out[319]
  PIN rw0_rd_out[320]
    DIRECTION OUTPUT ;
    USE SIGNAL ;
    SHAPE ABUTMENT ;
    PORT
      LAYER M4 ;
      RECT 0 1118.256 0.024 1118.28 ;
    END
  END rw0_rd_out[320]
  PIN rw0_rd_out[321]
    DIRECTION OUTPUT ;
    USE SIGNAL ;
    SHAPE ABUTMENT ;
    PORT
      LAYER M4 ;
      RECT 0 1119.504 0.024 1119.528 ;
    END
  END rw0_rd_out[321]
  PIN rw0_rd_out[322]
    DIRECTION OUTPUT ;
    USE SIGNAL ;
    SHAPE ABUTMENT ;
    PORT
      LAYER M4 ;
      RECT 0 1120.752 0.024 1120.776 ;
    END
  END rw0_rd_out[322]
  PIN rw0_rd_out[323]
    DIRECTION OUTPUT ;
    USE SIGNAL ;
    SHAPE ABUTMENT ;
    PORT
      LAYER M4 ;
      RECT 0 1122 0.024 1122.024 ;
    END
  END rw0_rd_out[323]
  PIN rw0_rd_out[324]
    DIRECTION OUTPUT ;
    USE SIGNAL ;
    SHAPE ABUTMENT ;
    PORT
      LAYER M4 ;
      RECT 0 1123.248 0.024 1123.272 ;
    END
  END rw0_rd_out[324]
  PIN rw0_rd_out[325]
    DIRECTION OUTPUT ;
    USE SIGNAL ;
    SHAPE ABUTMENT ;
    PORT
      LAYER M4 ;
      RECT 0 1124.496 0.024 1124.52 ;
    END
  END rw0_rd_out[325]
  PIN rw0_rd_out[326]
    DIRECTION OUTPUT ;
    USE SIGNAL ;
    SHAPE ABUTMENT ;
    PORT
      LAYER M4 ;
      RECT 0 1125.744 0.024 1125.768 ;
    END
  END rw0_rd_out[326]
  PIN rw0_rd_out[327]
    DIRECTION OUTPUT ;
    USE SIGNAL ;
    SHAPE ABUTMENT ;
    PORT
      LAYER M4 ;
      RECT 0 1126.992 0.024 1127.016 ;
    END
  END rw0_rd_out[327]
  PIN rw0_rd_out[328]
    DIRECTION OUTPUT ;
    USE SIGNAL ;
    SHAPE ABUTMENT ;
    PORT
      LAYER M4 ;
      RECT 0 1128.24 0.024 1128.264 ;
    END
  END rw0_rd_out[328]
  PIN rw0_rd_out[329]
    DIRECTION OUTPUT ;
    USE SIGNAL ;
    SHAPE ABUTMENT ;
    PORT
      LAYER M4 ;
      RECT 0 1129.488 0.024 1129.512 ;
    END
  END rw0_rd_out[329]
  PIN rw0_rd_out[330]
    DIRECTION OUTPUT ;
    USE SIGNAL ;
    SHAPE ABUTMENT ;
    PORT
      LAYER M4 ;
      RECT 0 1130.736 0.024 1130.76 ;
    END
  END rw0_rd_out[330]
  PIN rw0_rd_out[331]
    DIRECTION OUTPUT ;
    USE SIGNAL ;
    SHAPE ABUTMENT ;
    PORT
      LAYER M4 ;
      RECT 0 1131.984 0.024 1132.008 ;
    END
  END rw0_rd_out[331]
  PIN rw0_rd_out[332]
    DIRECTION OUTPUT ;
    USE SIGNAL ;
    SHAPE ABUTMENT ;
    PORT
      LAYER M4 ;
      RECT 0 1133.232 0.024 1133.256 ;
    END
  END rw0_rd_out[332]
  PIN rw0_rd_out[333]
    DIRECTION OUTPUT ;
    USE SIGNAL ;
    SHAPE ABUTMENT ;
    PORT
      LAYER M4 ;
      RECT 0 1134.48 0.024 1134.504 ;
    END
  END rw0_rd_out[333]
  PIN rw0_rd_out[334]
    DIRECTION OUTPUT ;
    USE SIGNAL ;
    SHAPE ABUTMENT ;
    PORT
      LAYER M4 ;
      RECT 0 1135.728 0.024 1135.752 ;
    END
  END rw0_rd_out[334]
  PIN rw0_rd_out[335]
    DIRECTION OUTPUT ;
    USE SIGNAL ;
    SHAPE ABUTMENT ;
    PORT
      LAYER M4 ;
      RECT 0 1136.976 0.024 1137 ;
    END
  END rw0_rd_out[335]
  PIN rw0_rd_out[336]
    DIRECTION OUTPUT ;
    USE SIGNAL ;
    SHAPE ABUTMENT ;
    PORT
      LAYER M4 ;
      RECT 0 1138.224 0.024 1138.248 ;
    END
  END rw0_rd_out[336]
  PIN rw0_rd_out[337]
    DIRECTION OUTPUT ;
    USE SIGNAL ;
    SHAPE ABUTMENT ;
    PORT
      LAYER M4 ;
      RECT 0 1139.472 0.024 1139.496 ;
    END
  END rw0_rd_out[337]
  PIN rw0_rd_out[338]
    DIRECTION OUTPUT ;
    USE SIGNAL ;
    SHAPE ABUTMENT ;
    PORT
      LAYER M4 ;
      RECT 0 1140.72 0.024 1140.744 ;
    END
  END rw0_rd_out[338]
  PIN rw0_rd_out[339]
    DIRECTION OUTPUT ;
    USE SIGNAL ;
    SHAPE ABUTMENT ;
    PORT
      LAYER M4 ;
      RECT 0 1141.968 0.024 1141.992 ;
    END
  END rw0_rd_out[339]
  PIN rw0_rd_out[340]
    DIRECTION OUTPUT ;
    USE SIGNAL ;
    SHAPE ABUTMENT ;
    PORT
      LAYER M4 ;
      RECT 0 1143.216 0.024 1143.24 ;
    END
  END rw0_rd_out[340]
  PIN rw0_rd_out[341]
    DIRECTION OUTPUT ;
    USE SIGNAL ;
    SHAPE ABUTMENT ;
    PORT
      LAYER M4 ;
      RECT 0 1144.464 0.024 1144.488 ;
    END
  END rw0_rd_out[341]
  PIN rw0_rd_out[342]
    DIRECTION OUTPUT ;
    USE SIGNAL ;
    SHAPE ABUTMENT ;
    PORT
      LAYER M4 ;
      RECT 0 1145.712 0.024 1145.736 ;
    END
  END rw0_rd_out[342]
  PIN rw0_rd_out[343]
    DIRECTION OUTPUT ;
    USE SIGNAL ;
    SHAPE ABUTMENT ;
    PORT
      LAYER M4 ;
      RECT 0 1146.96 0.024 1146.984 ;
    END
  END rw0_rd_out[343]
  PIN rw0_rd_out[344]
    DIRECTION OUTPUT ;
    USE SIGNAL ;
    SHAPE ABUTMENT ;
    PORT
      LAYER M4 ;
      RECT 0 1148.208 0.024 1148.232 ;
    END
  END rw0_rd_out[344]
  PIN rw0_rd_out[345]
    DIRECTION OUTPUT ;
    USE SIGNAL ;
    SHAPE ABUTMENT ;
    PORT
      LAYER M4 ;
      RECT 0 1149.456 0.024 1149.48 ;
    END
  END rw0_rd_out[345]
  PIN rw0_rd_out[346]
    DIRECTION OUTPUT ;
    USE SIGNAL ;
    SHAPE ABUTMENT ;
    PORT
      LAYER M4 ;
      RECT 0 1150.704 0.024 1150.728 ;
    END
  END rw0_rd_out[346]
  PIN rw0_rd_out[347]
    DIRECTION OUTPUT ;
    USE SIGNAL ;
    SHAPE ABUTMENT ;
    PORT
      LAYER M4 ;
      RECT 0 1151.952 0.024 1151.976 ;
    END
  END rw0_rd_out[347]
  PIN rw0_rd_out[348]
    DIRECTION OUTPUT ;
    USE SIGNAL ;
    SHAPE ABUTMENT ;
    PORT
      LAYER M4 ;
      RECT 0 1153.2 0.024 1153.224 ;
    END
  END rw0_rd_out[348]
  PIN rw0_rd_out[349]
    DIRECTION OUTPUT ;
    USE SIGNAL ;
    SHAPE ABUTMENT ;
    PORT
      LAYER M4 ;
      RECT 0 1154.448 0.024 1154.472 ;
    END
  END rw0_rd_out[349]
  PIN rw0_rd_out[350]
    DIRECTION OUTPUT ;
    USE SIGNAL ;
    SHAPE ABUTMENT ;
    PORT
      LAYER M4 ;
      RECT 0 1155.696 0.024 1155.72 ;
    END
  END rw0_rd_out[350]
  PIN rw0_rd_out[351]
    DIRECTION OUTPUT ;
    USE SIGNAL ;
    SHAPE ABUTMENT ;
    PORT
      LAYER M4 ;
      RECT 0 1156.944 0.024 1156.968 ;
    END
  END rw0_rd_out[351]
  PIN rw0_rd_out[352]
    DIRECTION OUTPUT ;
    USE SIGNAL ;
    SHAPE ABUTMENT ;
    PORT
      LAYER M4 ;
      RECT 0 1158.192 0.024 1158.216 ;
    END
  END rw0_rd_out[352]
  PIN rw0_rd_out[353]
    DIRECTION OUTPUT ;
    USE SIGNAL ;
    SHAPE ABUTMENT ;
    PORT
      LAYER M4 ;
      RECT 0 1159.44 0.024 1159.464 ;
    END
  END rw0_rd_out[353]
  PIN rw0_rd_out[354]
    DIRECTION OUTPUT ;
    USE SIGNAL ;
    SHAPE ABUTMENT ;
    PORT
      LAYER M4 ;
      RECT 0 1160.688 0.024 1160.712 ;
    END
  END rw0_rd_out[354]
  PIN rw0_rd_out[355]
    DIRECTION OUTPUT ;
    USE SIGNAL ;
    SHAPE ABUTMENT ;
    PORT
      LAYER M4 ;
      RECT 0 1161.936 0.024 1161.96 ;
    END
  END rw0_rd_out[355]
  PIN rw0_rd_out[356]
    DIRECTION OUTPUT ;
    USE SIGNAL ;
    SHAPE ABUTMENT ;
    PORT
      LAYER M4 ;
      RECT 0 1163.184 0.024 1163.208 ;
    END
  END rw0_rd_out[356]
  PIN rw0_rd_out[357]
    DIRECTION OUTPUT ;
    USE SIGNAL ;
    SHAPE ABUTMENT ;
    PORT
      LAYER M4 ;
      RECT 0 1164.432 0.024 1164.456 ;
    END
  END rw0_rd_out[357]
  PIN rw0_rd_out[358]
    DIRECTION OUTPUT ;
    USE SIGNAL ;
    SHAPE ABUTMENT ;
    PORT
      LAYER M4 ;
      RECT 0 1165.68 0.024 1165.704 ;
    END
  END rw0_rd_out[358]
  PIN rw0_rd_out[359]
    DIRECTION OUTPUT ;
    USE SIGNAL ;
    SHAPE ABUTMENT ;
    PORT
      LAYER M4 ;
      RECT 0 1166.928 0.024 1166.952 ;
    END
  END rw0_rd_out[359]
  PIN rw0_rd_out[360]
    DIRECTION OUTPUT ;
    USE SIGNAL ;
    SHAPE ABUTMENT ;
    PORT
      LAYER M4 ;
      RECT 0 1168.176 0.024 1168.2 ;
    END
  END rw0_rd_out[360]
  PIN rw0_rd_out[361]
    DIRECTION OUTPUT ;
    USE SIGNAL ;
    SHAPE ABUTMENT ;
    PORT
      LAYER M4 ;
      RECT 0 1169.424 0.024 1169.448 ;
    END
  END rw0_rd_out[361]
  PIN rw0_rd_out[362]
    DIRECTION OUTPUT ;
    USE SIGNAL ;
    SHAPE ABUTMENT ;
    PORT
      LAYER M4 ;
      RECT 0 1170.672 0.024 1170.696 ;
    END
  END rw0_rd_out[362]
  PIN rw0_rd_out[363]
    DIRECTION OUTPUT ;
    USE SIGNAL ;
    SHAPE ABUTMENT ;
    PORT
      LAYER M4 ;
      RECT 0 1171.92 0.024 1171.944 ;
    END
  END rw0_rd_out[363]
  PIN rw0_rd_out[364]
    DIRECTION OUTPUT ;
    USE SIGNAL ;
    SHAPE ABUTMENT ;
    PORT
      LAYER M4 ;
      RECT 0 1173.168 0.024 1173.192 ;
    END
  END rw0_rd_out[364]
  PIN rw0_rd_out[365]
    DIRECTION OUTPUT ;
    USE SIGNAL ;
    SHAPE ABUTMENT ;
    PORT
      LAYER M4 ;
      RECT 0 1174.416 0.024 1174.44 ;
    END
  END rw0_rd_out[365]
  PIN rw0_rd_out[366]
    DIRECTION OUTPUT ;
    USE SIGNAL ;
    SHAPE ABUTMENT ;
    PORT
      LAYER M4 ;
      RECT 0 1175.664 0.024 1175.688 ;
    END
  END rw0_rd_out[366]
  PIN rw0_rd_out[367]
    DIRECTION OUTPUT ;
    USE SIGNAL ;
    SHAPE ABUTMENT ;
    PORT
      LAYER M4 ;
      RECT 0 1176.912 0.024 1176.936 ;
    END
  END rw0_rd_out[367]
  PIN rw0_rd_out[368]
    DIRECTION OUTPUT ;
    USE SIGNAL ;
    SHAPE ABUTMENT ;
    PORT
      LAYER M4 ;
      RECT 0 1178.16 0.024 1178.184 ;
    END
  END rw0_rd_out[368]
  PIN rw0_rd_out[369]
    DIRECTION OUTPUT ;
    USE SIGNAL ;
    SHAPE ABUTMENT ;
    PORT
      LAYER M4 ;
      RECT 0 1179.408 0.024 1179.432 ;
    END
  END rw0_rd_out[369]
  PIN rw0_rd_out[370]
    DIRECTION OUTPUT ;
    USE SIGNAL ;
    SHAPE ABUTMENT ;
    PORT
      LAYER M4 ;
      RECT 0 1180.656 0.024 1180.68 ;
    END
  END rw0_rd_out[370]
  PIN rw0_rd_out[371]
    DIRECTION OUTPUT ;
    USE SIGNAL ;
    SHAPE ABUTMENT ;
    PORT
      LAYER M4 ;
      RECT 0 1181.904 0.024 1181.928 ;
    END
  END rw0_rd_out[371]
  PIN rw0_rd_out[372]
    DIRECTION OUTPUT ;
    USE SIGNAL ;
    SHAPE ABUTMENT ;
    PORT
      LAYER M4 ;
      RECT 0 1183.152 0.024 1183.176 ;
    END
  END rw0_rd_out[372]
  PIN rw0_rd_out[373]
    DIRECTION OUTPUT ;
    USE SIGNAL ;
    SHAPE ABUTMENT ;
    PORT
      LAYER M4 ;
      RECT 0 1184.4 0.024 1184.424 ;
    END
  END rw0_rd_out[373]
  PIN rw0_rd_out[374]
    DIRECTION OUTPUT ;
    USE SIGNAL ;
    SHAPE ABUTMENT ;
    PORT
      LAYER M4 ;
      RECT 0 1185.648 0.024 1185.672 ;
    END
  END rw0_rd_out[374]
  PIN rw0_rd_out[375]
    DIRECTION OUTPUT ;
    USE SIGNAL ;
    SHAPE ABUTMENT ;
    PORT
      LAYER M4 ;
      RECT 0 1186.896 0.024 1186.92 ;
    END
  END rw0_rd_out[375]
  PIN rw0_rd_out[376]
    DIRECTION OUTPUT ;
    USE SIGNAL ;
    SHAPE ABUTMENT ;
    PORT
      LAYER M4 ;
      RECT 0 1188.144 0.024 1188.168 ;
    END
  END rw0_rd_out[376]
  PIN rw0_rd_out[377]
    DIRECTION OUTPUT ;
    USE SIGNAL ;
    SHAPE ABUTMENT ;
    PORT
      LAYER M4 ;
      RECT 0 1189.392 0.024 1189.416 ;
    END
  END rw0_rd_out[377]
  PIN rw0_rd_out[378]
    DIRECTION OUTPUT ;
    USE SIGNAL ;
    SHAPE ABUTMENT ;
    PORT
      LAYER M4 ;
      RECT 0 1190.64 0.024 1190.664 ;
    END
  END rw0_rd_out[378]
  PIN rw0_rd_out[379]
    DIRECTION OUTPUT ;
    USE SIGNAL ;
    SHAPE ABUTMENT ;
    PORT
      LAYER M4 ;
      RECT 0 1191.888 0.024 1191.912 ;
    END
  END rw0_rd_out[379]
  PIN rw0_rd_out[380]
    DIRECTION OUTPUT ;
    USE SIGNAL ;
    SHAPE ABUTMENT ;
    PORT
      LAYER M4 ;
      RECT 0 1193.136 0.024 1193.16 ;
    END
  END rw0_rd_out[380]
  PIN rw0_rd_out[381]
    DIRECTION OUTPUT ;
    USE SIGNAL ;
    SHAPE ABUTMENT ;
    PORT
      LAYER M4 ;
      RECT 0 1194.384 0.024 1194.408 ;
    END
  END rw0_rd_out[381]
  PIN rw0_rd_out[382]
    DIRECTION OUTPUT ;
    USE SIGNAL ;
    SHAPE ABUTMENT ;
    PORT
      LAYER M4 ;
      RECT 0 1195.632 0.024 1195.656 ;
    END
  END rw0_rd_out[382]
  PIN rw0_rd_out[383]
    DIRECTION OUTPUT ;
    USE SIGNAL ;
    SHAPE ABUTMENT ;
    PORT
      LAYER M4 ;
      RECT 0 1196.88 0.024 1196.904 ;
    END
  END rw0_rd_out[383]
  PIN rw0_rd_out[384]
    DIRECTION OUTPUT ;
    USE SIGNAL ;
    SHAPE ABUTMENT ;
    PORT
      LAYER M4 ;
      RECT 0 1198.128 0.024 1198.152 ;
    END
  END rw0_rd_out[384]
  PIN rw0_rd_out[385]
    DIRECTION OUTPUT ;
    USE SIGNAL ;
    SHAPE ABUTMENT ;
    PORT
      LAYER M4 ;
      RECT 0 1199.376 0.024 1199.4 ;
    END
  END rw0_rd_out[385]
  PIN rw0_rd_out[386]
    DIRECTION OUTPUT ;
    USE SIGNAL ;
    SHAPE ABUTMENT ;
    PORT
      LAYER M4 ;
      RECT 0 1200.624 0.024 1200.648 ;
    END
  END rw0_rd_out[386]
  PIN rw0_rd_out[387]
    DIRECTION OUTPUT ;
    USE SIGNAL ;
    SHAPE ABUTMENT ;
    PORT
      LAYER M4 ;
      RECT 0 1201.872 0.024 1201.896 ;
    END
  END rw0_rd_out[387]
  PIN rw0_rd_out[388]
    DIRECTION OUTPUT ;
    USE SIGNAL ;
    SHAPE ABUTMENT ;
    PORT
      LAYER M4 ;
      RECT 0 1203.12 0.024 1203.144 ;
    END
  END rw0_rd_out[388]
  PIN rw0_rd_out[389]
    DIRECTION OUTPUT ;
    USE SIGNAL ;
    SHAPE ABUTMENT ;
    PORT
      LAYER M4 ;
      RECT 0 1204.368 0.024 1204.392 ;
    END
  END rw0_rd_out[389]
  PIN rw0_rd_out[390]
    DIRECTION OUTPUT ;
    USE SIGNAL ;
    SHAPE ABUTMENT ;
    PORT
      LAYER M4 ;
      RECT 0 1205.616 0.024 1205.64 ;
    END
  END rw0_rd_out[390]
  PIN rw0_rd_out[391]
    DIRECTION OUTPUT ;
    USE SIGNAL ;
    SHAPE ABUTMENT ;
    PORT
      LAYER M4 ;
      RECT 0 1206.864 0.024 1206.888 ;
    END
  END rw0_rd_out[391]
  PIN rw0_rd_out[392]
    DIRECTION OUTPUT ;
    USE SIGNAL ;
    SHAPE ABUTMENT ;
    PORT
      LAYER M4 ;
      RECT 0 1208.112 0.024 1208.136 ;
    END
  END rw0_rd_out[392]
  PIN rw0_rd_out[393]
    DIRECTION OUTPUT ;
    USE SIGNAL ;
    SHAPE ABUTMENT ;
    PORT
      LAYER M4 ;
      RECT 0 1209.36 0.024 1209.384 ;
    END
  END rw0_rd_out[393]
  PIN rw0_rd_out[394]
    DIRECTION OUTPUT ;
    USE SIGNAL ;
    SHAPE ABUTMENT ;
    PORT
      LAYER M4 ;
      RECT 0 1210.608 0.024 1210.632 ;
    END
  END rw0_rd_out[394]
  PIN rw0_rd_out[395]
    DIRECTION OUTPUT ;
    USE SIGNAL ;
    SHAPE ABUTMENT ;
    PORT
      LAYER M4 ;
      RECT 0 1211.856 0.024 1211.88 ;
    END
  END rw0_rd_out[395]
  PIN rw0_rd_out[396]
    DIRECTION OUTPUT ;
    USE SIGNAL ;
    SHAPE ABUTMENT ;
    PORT
      LAYER M4 ;
      RECT 0 1213.104 0.024 1213.128 ;
    END
  END rw0_rd_out[396]
  PIN rw0_rd_out[397]
    DIRECTION OUTPUT ;
    USE SIGNAL ;
    SHAPE ABUTMENT ;
    PORT
      LAYER M4 ;
      RECT 0 1214.352 0.024 1214.376 ;
    END
  END rw0_rd_out[397]
  PIN rw0_rd_out[398]
    DIRECTION OUTPUT ;
    USE SIGNAL ;
    SHAPE ABUTMENT ;
    PORT
      LAYER M4 ;
      RECT 0 1215.6 0.024 1215.624 ;
    END
  END rw0_rd_out[398]
  PIN rw0_rd_out[399]
    DIRECTION OUTPUT ;
    USE SIGNAL ;
    SHAPE ABUTMENT ;
    PORT
      LAYER M4 ;
      RECT 0 1216.848 0.024 1216.872 ;
    END
  END rw0_rd_out[399]
  PIN rw0_rd_out[400]
    DIRECTION OUTPUT ;
    USE SIGNAL ;
    SHAPE ABUTMENT ;
    PORT
      LAYER M4 ;
      RECT 0 1218.096 0.024 1218.12 ;
    END
  END rw0_rd_out[400]
  PIN rw0_rd_out[401]
    DIRECTION OUTPUT ;
    USE SIGNAL ;
    SHAPE ABUTMENT ;
    PORT
      LAYER M4 ;
      RECT 0 1219.344 0.024 1219.368 ;
    END
  END rw0_rd_out[401]
  PIN rw0_rd_out[402]
    DIRECTION OUTPUT ;
    USE SIGNAL ;
    SHAPE ABUTMENT ;
    PORT
      LAYER M4 ;
      RECT 0 1220.592 0.024 1220.616 ;
    END
  END rw0_rd_out[402]
  PIN rw0_rd_out[403]
    DIRECTION OUTPUT ;
    USE SIGNAL ;
    SHAPE ABUTMENT ;
    PORT
      LAYER M4 ;
      RECT 0 1221.84 0.024 1221.864 ;
    END
  END rw0_rd_out[403]
  PIN rw0_rd_out[404]
    DIRECTION OUTPUT ;
    USE SIGNAL ;
    SHAPE ABUTMENT ;
    PORT
      LAYER M4 ;
      RECT 0 1223.088 0.024 1223.112 ;
    END
  END rw0_rd_out[404]
  PIN rw0_rd_out[405]
    DIRECTION OUTPUT ;
    USE SIGNAL ;
    SHAPE ABUTMENT ;
    PORT
      LAYER M4 ;
      RECT 0 1224.336 0.024 1224.36 ;
    END
  END rw0_rd_out[405]
  PIN rw0_rd_out[406]
    DIRECTION OUTPUT ;
    USE SIGNAL ;
    SHAPE ABUTMENT ;
    PORT
      LAYER M4 ;
      RECT 0 1225.584 0.024 1225.608 ;
    END
  END rw0_rd_out[406]
  PIN rw0_rd_out[407]
    DIRECTION OUTPUT ;
    USE SIGNAL ;
    SHAPE ABUTMENT ;
    PORT
      LAYER M4 ;
      RECT 0 1226.832 0.024 1226.856 ;
    END
  END rw0_rd_out[407]
  PIN rw0_rd_out[408]
    DIRECTION OUTPUT ;
    USE SIGNAL ;
    SHAPE ABUTMENT ;
    PORT
      LAYER M4 ;
      RECT 0 1228.08 0.024 1228.104 ;
    END
  END rw0_rd_out[408]
  PIN rw0_rd_out[409]
    DIRECTION OUTPUT ;
    USE SIGNAL ;
    SHAPE ABUTMENT ;
    PORT
      LAYER M4 ;
      RECT 0 1229.328 0.024 1229.352 ;
    END
  END rw0_rd_out[409]
  PIN rw0_rd_out[410]
    DIRECTION OUTPUT ;
    USE SIGNAL ;
    SHAPE ABUTMENT ;
    PORT
      LAYER M4 ;
      RECT 0 1230.576 0.024 1230.6 ;
    END
  END rw0_rd_out[410]
  PIN rw0_rd_out[411]
    DIRECTION OUTPUT ;
    USE SIGNAL ;
    SHAPE ABUTMENT ;
    PORT
      LAYER M4 ;
      RECT 0 1231.824 0.024 1231.848 ;
    END
  END rw0_rd_out[411]
  PIN rw0_rd_out[412]
    DIRECTION OUTPUT ;
    USE SIGNAL ;
    SHAPE ABUTMENT ;
    PORT
      LAYER M4 ;
      RECT 0 1233.072 0.024 1233.096 ;
    END
  END rw0_rd_out[412]
  PIN rw0_rd_out[413]
    DIRECTION OUTPUT ;
    USE SIGNAL ;
    SHAPE ABUTMENT ;
    PORT
      LAYER M4 ;
      RECT 0 1234.32 0.024 1234.344 ;
    END
  END rw0_rd_out[413]
  PIN rw0_rd_out[414]
    DIRECTION OUTPUT ;
    USE SIGNAL ;
    SHAPE ABUTMENT ;
    PORT
      LAYER M4 ;
      RECT 0 1235.568 0.024 1235.592 ;
    END
  END rw0_rd_out[414]
  PIN rw0_rd_out[415]
    DIRECTION OUTPUT ;
    USE SIGNAL ;
    SHAPE ABUTMENT ;
    PORT
      LAYER M4 ;
      RECT 0 1236.816 0.024 1236.84 ;
    END
  END rw0_rd_out[415]
  PIN rw0_rd_out[416]
    DIRECTION OUTPUT ;
    USE SIGNAL ;
    SHAPE ABUTMENT ;
    PORT
      LAYER M4 ;
      RECT 0 1238.064 0.024 1238.088 ;
    END
  END rw0_rd_out[416]
  PIN rw0_rd_out[417]
    DIRECTION OUTPUT ;
    USE SIGNAL ;
    SHAPE ABUTMENT ;
    PORT
      LAYER M4 ;
      RECT 0 1239.312 0.024 1239.336 ;
    END
  END rw0_rd_out[417]
  PIN rw0_rd_out[418]
    DIRECTION OUTPUT ;
    USE SIGNAL ;
    SHAPE ABUTMENT ;
    PORT
      LAYER M4 ;
      RECT 0 1240.56 0.024 1240.584 ;
    END
  END rw0_rd_out[418]
  PIN rw0_rd_out[419]
    DIRECTION OUTPUT ;
    USE SIGNAL ;
    SHAPE ABUTMENT ;
    PORT
      LAYER M4 ;
      RECT 0 1241.808 0.024 1241.832 ;
    END
  END rw0_rd_out[419]
  PIN rw0_rd_out[420]
    DIRECTION OUTPUT ;
    USE SIGNAL ;
    SHAPE ABUTMENT ;
    PORT
      LAYER M4 ;
      RECT 0 1243.056 0.024 1243.08 ;
    END
  END rw0_rd_out[420]
  PIN rw0_rd_out[421]
    DIRECTION OUTPUT ;
    USE SIGNAL ;
    SHAPE ABUTMENT ;
    PORT
      LAYER M4 ;
      RECT 0 1244.304 0.024 1244.328 ;
    END
  END rw0_rd_out[421]
  PIN rw0_rd_out[422]
    DIRECTION OUTPUT ;
    USE SIGNAL ;
    SHAPE ABUTMENT ;
    PORT
      LAYER M4 ;
      RECT 0 1245.552 0.024 1245.576 ;
    END
  END rw0_rd_out[422]
  PIN rw0_rd_out[423]
    DIRECTION OUTPUT ;
    USE SIGNAL ;
    SHAPE ABUTMENT ;
    PORT
      LAYER M4 ;
      RECT 0 1246.8 0.024 1246.824 ;
    END
  END rw0_rd_out[423]
  PIN rw0_rd_out[424]
    DIRECTION OUTPUT ;
    USE SIGNAL ;
    SHAPE ABUTMENT ;
    PORT
      LAYER M4 ;
      RECT 0 1248.048 0.024 1248.072 ;
    END
  END rw0_rd_out[424]
  PIN rw0_rd_out[425]
    DIRECTION OUTPUT ;
    USE SIGNAL ;
    SHAPE ABUTMENT ;
    PORT
      LAYER M4 ;
      RECT 0 1249.296 0.024 1249.32 ;
    END
  END rw0_rd_out[425]
  PIN rw0_rd_out[426]
    DIRECTION OUTPUT ;
    USE SIGNAL ;
    SHAPE ABUTMENT ;
    PORT
      LAYER M4 ;
      RECT 0 1250.544 0.024 1250.568 ;
    END
  END rw0_rd_out[426]
  PIN rw0_rd_out[427]
    DIRECTION OUTPUT ;
    USE SIGNAL ;
    SHAPE ABUTMENT ;
    PORT
      LAYER M4 ;
      RECT 0 1251.792 0.024 1251.816 ;
    END
  END rw0_rd_out[427]
  PIN rw0_rd_out[428]
    DIRECTION OUTPUT ;
    USE SIGNAL ;
    SHAPE ABUTMENT ;
    PORT
      LAYER M4 ;
      RECT 0 1253.04 0.024 1253.064 ;
    END
  END rw0_rd_out[428]
  PIN rw0_rd_out[429]
    DIRECTION OUTPUT ;
    USE SIGNAL ;
    SHAPE ABUTMENT ;
    PORT
      LAYER M4 ;
      RECT 0 1254.288 0.024 1254.312 ;
    END
  END rw0_rd_out[429]
  PIN rw0_rd_out[430]
    DIRECTION OUTPUT ;
    USE SIGNAL ;
    SHAPE ABUTMENT ;
    PORT
      LAYER M4 ;
      RECT 0 1255.536 0.024 1255.56 ;
    END
  END rw0_rd_out[430]
  PIN rw0_rd_out[431]
    DIRECTION OUTPUT ;
    USE SIGNAL ;
    SHAPE ABUTMENT ;
    PORT
      LAYER M4 ;
      RECT 0 1256.784 0.024 1256.808 ;
    END
  END rw0_rd_out[431]
  PIN rw0_rd_out[432]
    DIRECTION OUTPUT ;
    USE SIGNAL ;
    SHAPE ABUTMENT ;
    PORT
      LAYER M4 ;
      RECT 0 1258.032 0.024 1258.056 ;
    END
  END rw0_rd_out[432]
  PIN rw0_rd_out[433]
    DIRECTION OUTPUT ;
    USE SIGNAL ;
    SHAPE ABUTMENT ;
    PORT
      LAYER M4 ;
      RECT 0 1259.28 0.024 1259.304 ;
    END
  END rw0_rd_out[433]
  PIN rw0_rd_out[434]
    DIRECTION OUTPUT ;
    USE SIGNAL ;
    SHAPE ABUTMENT ;
    PORT
      LAYER M4 ;
      RECT 0 1260.528 0.024 1260.552 ;
    END
  END rw0_rd_out[434]
  PIN rw0_rd_out[435]
    DIRECTION OUTPUT ;
    USE SIGNAL ;
    SHAPE ABUTMENT ;
    PORT
      LAYER M4 ;
      RECT 0 1261.776 0.024 1261.8 ;
    END
  END rw0_rd_out[435]
  PIN rw0_rd_out[436]
    DIRECTION OUTPUT ;
    USE SIGNAL ;
    SHAPE ABUTMENT ;
    PORT
      LAYER M4 ;
      RECT 0 1263.024 0.024 1263.048 ;
    END
  END rw0_rd_out[436]
  PIN rw0_rd_out[437]
    DIRECTION OUTPUT ;
    USE SIGNAL ;
    SHAPE ABUTMENT ;
    PORT
      LAYER M4 ;
      RECT 0 1264.272 0.024 1264.296 ;
    END
  END rw0_rd_out[437]
  PIN rw0_rd_out[438]
    DIRECTION OUTPUT ;
    USE SIGNAL ;
    SHAPE ABUTMENT ;
    PORT
      LAYER M4 ;
      RECT 0 1265.52 0.024 1265.544 ;
    END
  END rw0_rd_out[438]
  PIN rw0_rd_out[439]
    DIRECTION OUTPUT ;
    USE SIGNAL ;
    SHAPE ABUTMENT ;
    PORT
      LAYER M4 ;
      RECT 0 1266.768 0.024 1266.792 ;
    END
  END rw0_rd_out[439]
  PIN rw0_rd_out[440]
    DIRECTION OUTPUT ;
    USE SIGNAL ;
    SHAPE ABUTMENT ;
    PORT
      LAYER M4 ;
      RECT 0 1268.016 0.024 1268.04 ;
    END
  END rw0_rd_out[440]
  PIN rw0_rd_out[441]
    DIRECTION OUTPUT ;
    USE SIGNAL ;
    SHAPE ABUTMENT ;
    PORT
      LAYER M4 ;
      RECT 0 1269.264 0.024 1269.288 ;
    END
  END rw0_rd_out[441]
  PIN rw0_rd_out[442]
    DIRECTION OUTPUT ;
    USE SIGNAL ;
    SHAPE ABUTMENT ;
    PORT
      LAYER M4 ;
      RECT 0 1270.512 0.024 1270.536 ;
    END
  END rw0_rd_out[442]
  PIN rw0_rd_out[443]
    DIRECTION OUTPUT ;
    USE SIGNAL ;
    SHAPE ABUTMENT ;
    PORT
      LAYER M4 ;
      RECT 0 1271.76 0.024 1271.784 ;
    END
  END rw0_rd_out[443]
  PIN rw0_rd_out[444]
    DIRECTION OUTPUT ;
    USE SIGNAL ;
    SHAPE ABUTMENT ;
    PORT
      LAYER M4 ;
      RECT 0 1273.008 0.024 1273.032 ;
    END
  END rw0_rd_out[444]
  PIN rw0_rd_out[445]
    DIRECTION OUTPUT ;
    USE SIGNAL ;
    SHAPE ABUTMENT ;
    PORT
      LAYER M4 ;
      RECT 0 1274.256 0.024 1274.28 ;
    END
  END rw0_rd_out[445]
  PIN rw0_rd_out[446]
    DIRECTION OUTPUT ;
    USE SIGNAL ;
    SHAPE ABUTMENT ;
    PORT
      LAYER M4 ;
      RECT 0 1275.504 0.024 1275.528 ;
    END
  END rw0_rd_out[446]
  PIN rw0_rd_out[447]
    DIRECTION OUTPUT ;
    USE SIGNAL ;
    SHAPE ABUTMENT ;
    PORT
      LAYER M4 ;
      RECT 0 1276.752 0.024 1276.776 ;
    END
  END rw0_rd_out[447]
  PIN rw0_rd_out[448]
    DIRECTION OUTPUT ;
    USE SIGNAL ;
    SHAPE ABUTMENT ;
    PORT
      LAYER M4 ;
      RECT 0 1278 0.024 1278.024 ;
    END
  END rw0_rd_out[448]
  PIN rw0_rd_out[449]
    DIRECTION OUTPUT ;
    USE SIGNAL ;
    SHAPE ABUTMENT ;
    PORT
      LAYER M4 ;
      RECT 0 1279.248 0.024 1279.272 ;
    END
  END rw0_rd_out[449]
  PIN rw0_rd_out[450]
    DIRECTION OUTPUT ;
    USE SIGNAL ;
    SHAPE ABUTMENT ;
    PORT
      LAYER M4 ;
      RECT 0 1280.496 0.024 1280.52 ;
    END
  END rw0_rd_out[450]
  PIN rw0_rd_out[451]
    DIRECTION OUTPUT ;
    USE SIGNAL ;
    SHAPE ABUTMENT ;
    PORT
      LAYER M4 ;
      RECT 0 1281.744 0.024 1281.768 ;
    END
  END rw0_rd_out[451]
  PIN rw0_rd_out[452]
    DIRECTION OUTPUT ;
    USE SIGNAL ;
    SHAPE ABUTMENT ;
    PORT
      LAYER M4 ;
      RECT 0 1282.992 0.024 1283.016 ;
    END
  END rw0_rd_out[452]
  PIN rw0_rd_out[453]
    DIRECTION OUTPUT ;
    USE SIGNAL ;
    SHAPE ABUTMENT ;
    PORT
      LAYER M4 ;
      RECT 0 1284.24 0.024 1284.264 ;
    END
  END rw0_rd_out[453]
  PIN rw0_rd_out[454]
    DIRECTION OUTPUT ;
    USE SIGNAL ;
    SHAPE ABUTMENT ;
    PORT
      LAYER M4 ;
      RECT 0 1285.488 0.024 1285.512 ;
    END
  END rw0_rd_out[454]
  PIN rw0_rd_out[455]
    DIRECTION OUTPUT ;
    USE SIGNAL ;
    SHAPE ABUTMENT ;
    PORT
      LAYER M4 ;
      RECT 0 1286.736 0.024 1286.76 ;
    END
  END rw0_rd_out[455]
  PIN rw0_rd_out[456]
    DIRECTION OUTPUT ;
    USE SIGNAL ;
    SHAPE ABUTMENT ;
    PORT
      LAYER M4 ;
      RECT 0 1287.984 0.024 1288.008 ;
    END
  END rw0_rd_out[456]
  PIN rw0_rd_out[457]
    DIRECTION OUTPUT ;
    USE SIGNAL ;
    SHAPE ABUTMENT ;
    PORT
      LAYER M4 ;
      RECT 0 1289.232 0.024 1289.256 ;
    END
  END rw0_rd_out[457]
  PIN rw0_rd_out[458]
    DIRECTION OUTPUT ;
    USE SIGNAL ;
    SHAPE ABUTMENT ;
    PORT
      LAYER M4 ;
      RECT 0 1290.48 0.024 1290.504 ;
    END
  END rw0_rd_out[458]
  PIN rw0_rd_out[459]
    DIRECTION OUTPUT ;
    USE SIGNAL ;
    SHAPE ABUTMENT ;
    PORT
      LAYER M4 ;
      RECT 0 1291.728 0.024 1291.752 ;
    END
  END rw0_rd_out[459]
  PIN rw0_rd_out[460]
    DIRECTION OUTPUT ;
    USE SIGNAL ;
    SHAPE ABUTMENT ;
    PORT
      LAYER M4 ;
      RECT 0 1292.976 0.024 1293 ;
    END
  END rw0_rd_out[460]
  PIN rw0_rd_out[461]
    DIRECTION OUTPUT ;
    USE SIGNAL ;
    SHAPE ABUTMENT ;
    PORT
      LAYER M4 ;
      RECT 0 1294.224 0.024 1294.248 ;
    END
  END rw0_rd_out[461]
  PIN rw0_rd_out[462]
    DIRECTION OUTPUT ;
    USE SIGNAL ;
    SHAPE ABUTMENT ;
    PORT
      LAYER M4 ;
      RECT 0 1295.472 0.024 1295.496 ;
    END
  END rw0_rd_out[462]
  PIN rw0_rd_out[463]
    DIRECTION OUTPUT ;
    USE SIGNAL ;
    SHAPE ABUTMENT ;
    PORT
      LAYER M4 ;
      RECT 0 1296.72 0.024 1296.744 ;
    END
  END rw0_rd_out[463]
  PIN rw0_rd_out[464]
    DIRECTION OUTPUT ;
    USE SIGNAL ;
    SHAPE ABUTMENT ;
    PORT
      LAYER M4 ;
      RECT 0 1297.968 0.024 1297.992 ;
    END
  END rw0_rd_out[464]
  PIN rw0_rd_out[465]
    DIRECTION OUTPUT ;
    USE SIGNAL ;
    SHAPE ABUTMENT ;
    PORT
      LAYER M4 ;
      RECT 0 1299.216 0.024 1299.24 ;
    END
  END rw0_rd_out[465]
  PIN rw0_rd_out[466]
    DIRECTION OUTPUT ;
    USE SIGNAL ;
    SHAPE ABUTMENT ;
    PORT
      LAYER M4 ;
      RECT 0 1300.464 0.024 1300.488 ;
    END
  END rw0_rd_out[466]
  PIN rw0_rd_out[467]
    DIRECTION OUTPUT ;
    USE SIGNAL ;
    SHAPE ABUTMENT ;
    PORT
      LAYER M4 ;
      RECT 0 1301.712 0.024 1301.736 ;
    END
  END rw0_rd_out[467]
  PIN rw0_rd_out[468]
    DIRECTION OUTPUT ;
    USE SIGNAL ;
    SHAPE ABUTMENT ;
    PORT
      LAYER M4 ;
      RECT 0 1302.96 0.024 1302.984 ;
    END
  END rw0_rd_out[468]
  PIN rw0_rd_out[469]
    DIRECTION OUTPUT ;
    USE SIGNAL ;
    SHAPE ABUTMENT ;
    PORT
      LAYER M4 ;
      RECT 0 1304.208 0.024 1304.232 ;
    END
  END rw0_rd_out[469]
  PIN rw0_rd_out[470]
    DIRECTION OUTPUT ;
    USE SIGNAL ;
    SHAPE ABUTMENT ;
    PORT
      LAYER M4 ;
      RECT 0 1305.456 0.024 1305.48 ;
    END
  END rw0_rd_out[470]
  PIN rw0_rd_out[471]
    DIRECTION OUTPUT ;
    USE SIGNAL ;
    SHAPE ABUTMENT ;
    PORT
      LAYER M4 ;
      RECT 0 1306.704 0.024 1306.728 ;
    END
  END rw0_rd_out[471]
  PIN rw0_rd_out[472]
    DIRECTION OUTPUT ;
    USE SIGNAL ;
    SHAPE ABUTMENT ;
    PORT
      LAYER M4 ;
      RECT 0 1307.952 0.024 1307.976 ;
    END
  END rw0_rd_out[472]
  PIN rw0_rd_out[473]
    DIRECTION OUTPUT ;
    USE SIGNAL ;
    SHAPE ABUTMENT ;
    PORT
      LAYER M4 ;
      RECT 0 1309.2 0.024 1309.224 ;
    END
  END rw0_rd_out[473]
  PIN rw0_rd_out[474]
    DIRECTION OUTPUT ;
    USE SIGNAL ;
    SHAPE ABUTMENT ;
    PORT
      LAYER M4 ;
      RECT 0 1310.448 0.024 1310.472 ;
    END
  END rw0_rd_out[474]
  PIN rw0_rd_out[475]
    DIRECTION OUTPUT ;
    USE SIGNAL ;
    SHAPE ABUTMENT ;
    PORT
      LAYER M4 ;
      RECT 0 1311.696 0.024 1311.72 ;
    END
  END rw0_rd_out[475]
  PIN rw0_rd_out[476]
    DIRECTION OUTPUT ;
    USE SIGNAL ;
    SHAPE ABUTMENT ;
    PORT
      LAYER M4 ;
      RECT 0 1312.944 0.024 1312.968 ;
    END
  END rw0_rd_out[476]
  PIN rw0_rd_out[477]
    DIRECTION OUTPUT ;
    USE SIGNAL ;
    SHAPE ABUTMENT ;
    PORT
      LAYER M4 ;
      RECT 0 1314.192 0.024 1314.216 ;
    END
  END rw0_rd_out[477]
  PIN rw0_rd_out[478]
    DIRECTION OUTPUT ;
    USE SIGNAL ;
    SHAPE ABUTMENT ;
    PORT
      LAYER M4 ;
      RECT 0 1315.44 0.024 1315.464 ;
    END
  END rw0_rd_out[478]
  PIN rw0_rd_out[479]
    DIRECTION OUTPUT ;
    USE SIGNAL ;
    SHAPE ABUTMENT ;
    PORT
      LAYER M4 ;
      RECT 0 1316.688 0.024 1316.712 ;
    END
  END rw0_rd_out[479]
  PIN rw0_rd_out[480]
    DIRECTION OUTPUT ;
    USE SIGNAL ;
    SHAPE ABUTMENT ;
    PORT
      LAYER M4 ;
      RECT 0 1317.936 0.024 1317.96 ;
    END
  END rw0_rd_out[480]
  PIN rw0_rd_out[481]
    DIRECTION OUTPUT ;
    USE SIGNAL ;
    SHAPE ABUTMENT ;
    PORT
      LAYER M4 ;
      RECT 0 1319.184 0.024 1319.208 ;
    END
  END rw0_rd_out[481]
  PIN rw0_rd_out[482]
    DIRECTION OUTPUT ;
    USE SIGNAL ;
    SHAPE ABUTMENT ;
    PORT
      LAYER M4 ;
      RECT 0 1320.432 0.024 1320.456 ;
    END
  END rw0_rd_out[482]
  PIN rw0_rd_out[483]
    DIRECTION OUTPUT ;
    USE SIGNAL ;
    SHAPE ABUTMENT ;
    PORT
      LAYER M4 ;
      RECT 0 1321.68 0.024 1321.704 ;
    END
  END rw0_rd_out[483]
  PIN rw0_rd_out[484]
    DIRECTION OUTPUT ;
    USE SIGNAL ;
    SHAPE ABUTMENT ;
    PORT
      LAYER M4 ;
      RECT 0 1322.928 0.024 1322.952 ;
    END
  END rw0_rd_out[484]
  PIN rw0_rd_out[485]
    DIRECTION OUTPUT ;
    USE SIGNAL ;
    SHAPE ABUTMENT ;
    PORT
      LAYER M4 ;
      RECT 0 1324.176 0.024 1324.2 ;
    END
  END rw0_rd_out[485]
  PIN rw0_rd_out[486]
    DIRECTION OUTPUT ;
    USE SIGNAL ;
    SHAPE ABUTMENT ;
    PORT
      LAYER M4 ;
      RECT 0 1325.424 0.024 1325.448 ;
    END
  END rw0_rd_out[486]
  PIN rw0_rd_out[487]
    DIRECTION OUTPUT ;
    USE SIGNAL ;
    SHAPE ABUTMENT ;
    PORT
      LAYER M4 ;
      RECT 0 1326.672 0.024 1326.696 ;
    END
  END rw0_rd_out[487]
  PIN rw0_rd_out[488]
    DIRECTION OUTPUT ;
    USE SIGNAL ;
    SHAPE ABUTMENT ;
    PORT
      LAYER M4 ;
      RECT 0 1327.92 0.024 1327.944 ;
    END
  END rw0_rd_out[488]
  PIN rw0_rd_out[489]
    DIRECTION OUTPUT ;
    USE SIGNAL ;
    SHAPE ABUTMENT ;
    PORT
      LAYER M4 ;
      RECT 0 1329.168 0.024 1329.192 ;
    END
  END rw0_rd_out[489]
  PIN rw0_rd_out[490]
    DIRECTION OUTPUT ;
    USE SIGNAL ;
    SHAPE ABUTMENT ;
    PORT
      LAYER M4 ;
      RECT 0 1330.416 0.024 1330.44 ;
    END
  END rw0_rd_out[490]
  PIN rw0_rd_out[491]
    DIRECTION OUTPUT ;
    USE SIGNAL ;
    SHAPE ABUTMENT ;
    PORT
      LAYER M4 ;
      RECT 0 1331.664 0.024 1331.688 ;
    END
  END rw0_rd_out[491]
  PIN rw0_rd_out[492]
    DIRECTION OUTPUT ;
    USE SIGNAL ;
    SHAPE ABUTMENT ;
    PORT
      LAYER M4 ;
      RECT 0 1332.912 0.024 1332.936 ;
    END
  END rw0_rd_out[492]
  PIN rw0_rd_out[493]
    DIRECTION OUTPUT ;
    USE SIGNAL ;
    SHAPE ABUTMENT ;
    PORT
      LAYER M4 ;
      RECT 0 1334.16 0.024 1334.184 ;
    END
  END rw0_rd_out[493]
  PIN rw0_rd_out[494]
    DIRECTION OUTPUT ;
    USE SIGNAL ;
    SHAPE ABUTMENT ;
    PORT
      LAYER M4 ;
      RECT 0 1335.408 0.024 1335.432 ;
    END
  END rw0_rd_out[494]
  PIN rw0_rd_out[495]
    DIRECTION OUTPUT ;
    USE SIGNAL ;
    SHAPE ABUTMENT ;
    PORT
      LAYER M4 ;
      RECT 0 1336.656 0.024 1336.68 ;
    END
  END rw0_rd_out[495]
  PIN rw0_rd_out[496]
    DIRECTION OUTPUT ;
    USE SIGNAL ;
    SHAPE ABUTMENT ;
    PORT
      LAYER M4 ;
      RECT 0 1337.904 0.024 1337.928 ;
    END
  END rw0_rd_out[496]
  PIN rw0_rd_out[497]
    DIRECTION OUTPUT ;
    USE SIGNAL ;
    SHAPE ABUTMENT ;
    PORT
      LAYER M4 ;
      RECT 0 1339.152 0.024 1339.176 ;
    END
  END rw0_rd_out[497]
  PIN rw0_rd_out[498]
    DIRECTION OUTPUT ;
    USE SIGNAL ;
    SHAPE ABUTMENT ;
    PORT
      LAYER M4 ;
      RECT 0 1340.4 0.024 1340.424 ;
    END
  END rw0_rd_out[498]
  PIN rw0_rd_out[499]
    DIRECTION OUTPUT ;
    USE SIGNAL ;
    SHAPE ABUTMENT ;
    PORT
      LAYER M4 ;
      RECT 0 1341.648 0.024 1341.672 ;
    END
  END rw0_rd_out[499]
  PIN rw0_rd_out[500]
    DIRECTION OUTPUT ;
    USE SIGNAL ;
    SHAPE ABUTMENT ;
    PORT
      LAYER M4 ;
      RECT 0 1342.896 0.024 1342.92 ;
    END
  END rw0_rd_out[500]
  PIN rw0_rd_out[501]
    DIRECTION OUTPUT ;
    USE SIGNAL ;
    SHAPE ABUTMENT ;
    PORT
      LAYER M4 ;
      RECT 0 1344.144 0.024 1344.168 ;
    END
  END rw0_rd_out[501]
  PIN rw0_rd_out[502]
    DIRECTION OUTPUT ;
    USE SIGNAL ;
    SHAPE ABUTMENT ;
    PORT
      LAYER M4 ;
      RECT 0 1345.392 0.024 1345.416 ;
    END
  END rw0_rd_out[502]
  PIN rw0_rd_out[503]
    DIRECTION OUTPUT ;
    USE SIGNAL ;
    SHAPE ABUTMENT ;
    PORT
      LAYER M4 ;
      RECT 0 1346.64 0.024 1346.664 ;
    END
  END rw0_rd_out[503]
  PIN rw0_rd_out[504]
    DIRECTION OUTPUT ;
    USE SIGNAL ;
    SHAPE ABUTMENT ;
    PORT
      LAYER M4 ;
      RECT 0 1347.888 0.024 1347.912 ;
    END
  END rw0_rd_out[504]
  PIN rw0_rd_out[505]
    DIRECTION OUTPUT ;
    USE SIGNAL ;
    SHAPE ABUTMENT ;
    PORT
      LAYER M4 ;
      RECT 0 1349.136 0.024 1349.16 ;
    END
  END rw0_rd_out[505]
  PIN rw0_rd_out[506]
    DIRECTION OUTPUT ;
    USE SIGNAL ;
    SHAPE ABUTMENT ;
    PORT
      LAYER M4 ;
      RECT 0 1350.384 0.024 1350.408 ;
    END
  END rw0_rd_out[506]
  PIN rw0_rd_out[507]
    DIRECTION OUTPUT ;
    USE SIGNAL ;
    SHAPE ABUTMENT ;
    PORT
      LAYER M4 ;
      RECT 0 1351.632 0.024 1351.656 ;
    END
  END rw0_rd_out[507]
  PIN rw0_rd_out[508]
    DIRECTION OUTPUT ;
    USE SIGNAL ;
    SHAPE ABUTMENT ;
    PORT
      LAYER M4 ;
      RECT 0 1352.88 0.024 1352.904 ;
    END
  END rw0_rd_out[508]
  PIN rw0_rd_out[509]
    DIRECTION OUTPUT ;
    USE SIGNAL ;
    SHAPE ABUTMENT ;
    PORT
      LAYER M4 ;
      RECT 0 1354.128 0.024 1354.152 ;
    END
  END rw0_rd_out[509]
  PIN rw0_rd_out[510]
    DIRECTION OUTPUT ;
    USE SIGNAL ;
    SHAPE ABUTMENT ;
    PORT
      LAYER M4 ;
      RECT 0 1355.376 0.024 1355.4 ;
    END
  END rw0_rd_out[510]
  PIN rw0_rd_out[511]
    DIRECTION OUTPUT ;
    USE SIGNAL ;
    SHAPE ABUTMENT ;
    PORT
      LAYER M4 ;
      RECT 0 1356.624 0.024 1356.648 ;
    END
  END rw0_rd_out[511]
  PIN rw0_addr_in[0]
    DIRECTION INPUT ;
    USE SIGNAL ;
    SHAPE ABUTMENT ;
    PORT
      LAYER M4 ;
      RECT 0 1357.872 0.024 1357.896 ;
    END
  END rw0_addr_in[0]
  PIN rw0_addr_in[1]
    DIRECTION INPUT ;
    USE SIGNAL ;
    SHAPE ABUTMENT ;
    PORT
      LAYER M4 ;
      RECT 0 1359.12 0.024 1359.144 ;
    END
  END rw0_addr_in[1]
  PIN rw0_addr_in[2]
    DIRECTION INPUT ;
    USE SIGNAL ;
    SHAPE ABUTMENT ;
    PORT
      LAYER M4 ;
      RECT 0 1360.368 0.024 1360.392 ;
    END
  END rw0_addr_in[2]
  PIN rw0_addr_in[3]
    DIRECTION INPUT ;
    USE SIGNAL ;
    SHAPE ABUTMENT ;
    PORT
      LAYER M4 ;
      RECT 0 1361.616 0.024 1361.64 ;
    END
  END rw0_addr_in[3]
  PIN rw0_addr_in[4]
    DIRECTION INPUT ;
    USE SIGNAL ;
    SHAPE ABUTMENT ;
    PORT
      LAYER M4 ;
      RECT 0 1362.864 0.024 1362.888 ;
    END
  END rw0_addr_in[4]
  PIN rw0_addr_in[5]
    DIRECTION INPUT ;
    USE SIGNAL ;
    SHAPE ABUTMENT ;
    PORT
      LAYER M4 ;
      RECT 0 1364.112 0.024 1364.136 ;
    END
  END rw0_addr_in[5]
  PIN rw0_addr_in[6]
    DIRECTION INPUT ;
    USE SIGNAL ;
    SHAPE ABUTMENT ;
    PORT
      LAYER M4 ;
      RECT 0 1365.36 0.024 1365.384 ;
    END
  END rw0_addr_in[6]
  PIN rw0_addr_in[7]
    DIRECTION INPUT ;
    USE SIGNAL ;
    SHAPE ABUTMENT ;
    PORT
      LAYER M4 ;
      RECT 0 1366.608 0.024 1366.632 ;
    END
  END rw0_addr_in[7]
  PIN rw0_addr_in[8]
    DIRECTION INPUT ;
    USE SIGNAL ;
    SHAPE ABUTMENT ;
    PORT
      LAYER M4 ;
      RECT 0 1367.856 0.024 1367.88 ;
    END
  END rw0_addr_in[8]
  PIN rw0_addr_in[9]
    DIRECTION INPUT ;
    USE SIGNAL ;
    SHAPE ABUTMENT ;
    PORT
      LAYER M4 ;
      RECT 0 1369.104 0.024 1369.128 ;
    END
  END rw0_addr_in[9]
  PIN rw0_addr_in[10]
    DIRECTION INPUT ;
    USE SIGNAL ;
    SHAPE ABUTMENT ;
    PORT
      LAYER M4 ;
      RECT 0 1370.352 0.024 1370.376 ;
    END
  END rw0_addr_in[10]
  PIN rw0_addr_in[11]
    DIRECTION INPUT ;
    USE SIGNAL ;
    SHAPE ABUTMENT ;
    PORT
      LAYER M4 ;
      RECT 0 1371.6 0.024 1371.624 ;
    END
  END rw0_addr_in[11]
  PIN rw0_addr_in[12]
    DIRECTION INPUT ;
    USE SIGNAL ;
    SHAPE ABUTMENT ;
    PORT
      LAYER M4 ;
      RECT 0 1372.848 0.024 1372.872 ;
    END
  END rw0_addr_in[12]
  PIN rw0_addr_in[13]
    DIRECTION INPUT ;
    USE SIGNAL ;
    SHAPE ABUTMENT ;
    PORT
      LAYER M4 ;
      RECT 0 1374.096 0.024 1374.12 ;
    END
  END rw0_addr_in[13]
  PIN rw0_we_in
    DIRECTION INPUT ;
    USE SIGNAL ;
    SHAPE ABUTMENT ;
    PORT
      LAYER M4 ;
      RECT 0 1375.344 0.024 1375.368 ;
    END
  END rw0_we_in
  PIN rw0_ce_in
    DIRECTION INPUT ;
    USE SIGNAL ;
    SHAPE ABUTMENT ;
    PORT
      LAYER M4 ;
      RECT 0 1376.592 0.024 1376.616 ;
    END
  END rw0_ce_in
  PIN rw0_clk
    DIRECTION INPUT ;
    USE SIGNAL ;
    SHAPE ABUTMENT ;
    PORT
      LAYER M4 ;
      RECT 0 1377.84 0.024 1377.864 ;
    END
  END rw0_clk
  PIN VSS
    DIRECTION INOUT ;
    USE GROUND ;
    PORT
      LAYER M4 ;
      RECT 0.048 0 138.635 0.096 ;
      RECT 0.048 0.768 138.635 0.864 ;
      RECT 0.048 1.536 138.635 1.632 ;
      RECT 0.048 2.304 138.635 2.4 ;
      RECT 0.048 3.072 138.635 3.168 ;
      RECT 0.048 3.84 138.635 3.936 ;
      RECT 0.048 4.608 138.635 4.704 ;
      RECT 0.048 5.376 138.635 5.472 ;
      RECT 0.048 6.144 138.635 6.24 ;
      RECT 0.048 6.912 138.635 7.008 ;
      RECT 0.048 7.68 138.635 7.776 ;
      RECT 0.048 8.448 138.635 8.544 ;
      RECT 0.048 9.216 138.635 9.312 ;
      RECT 0.048 9.984 138.635 10.08 ;
      RECT 0.048 10.752 138.635 10.848 ;
      RECT 0.048 11.52 138.635 11.616 ;
      RECT 0.048 12.288 138.635 12.384 ;
      RECT 0.048 13.056 138.635 13.152 ;
      RECT 0.048 13.824 138.635 13.92 ;
      RECT 0.048 14.592 138.635 14.688 ;
      RECT 0.048 15.36 138.635 15.456 ;
      RECT 0.048 16.128 138.635 16.224 ;
      RECT 0.048 16.896 138.635 16.992 ;
      RECT 0.048 17.664 138.635 17.76 ;
      RECT 0.048 18.432 138.635 18.528 ;
      RECT 0.048 19.2 138.635 19.296 ;
      RECT 0.048 19.968 138.635 20.064 ;
      RECT 0.048 20.736 138.635 20.832 ;
      RECT 0.048 21.504 138.635 21.6 ;
      RECT 0.048 22.272 138.635 22.368 ;
      RECT 0.048 23.04 138.635 23.136 ;
      RECT 0.048 23.808 138.635 23.904 ;
      RECT 0.048 24.576 138.635 24.672 ;
      RECT 0.048 25.344 138.635 25.44 ;
      RECT 0.048 26.112 138.635 26.208 ;
      RECT 0.048 26.88 138.635 26.976 ;
      RECT 0.048 27.648 138.635 27.744 ;
      RECT 0.048 28.416 138.635 28.512 ;
      RECT 0.048 29.184 138.635 29.28 ;
      RECT 0.048 29.952 138.635 30.048 ;
      RECT 0.048 30.72 138.635 30.816 ;
      RECT 0.048 31.488 138.635 31.584 ;
      RECT 0.048 32.256 138.635 32.352 ;
      RECT 0.048 33.024 138.635 33.12 ;
      RECT 0.048 33.792 138.635 33.888 ;
      RECT 0.048 34.56 138.635 34.656 ;
      RECT 0.048 35.328 138.635 35.424 ;
      RECT 0.048 36.096 138.635 36.192 ;
      RECT 0.048 36.864 138.635 36.96 ;
      RECT 0.048 37.632 138.635 37.728 ;
      RECT 0.048 38.4 138.635 38.496 ;
      RECT 0.048 39.168 138.635 39.264 ;
      RECT 0.048 39.936 138.635 40.032 ;
      RECT 0.048 40.704 138.635 40.8 ;
      RECT 0.048 41.472 138.635 41.568 ;
      RECT 0.048 42.24 138.635 42.336 ;
      RECT 0.048 43.008 138.635 43.104 ;
      RECT 0.048 43.776 138.635 43.872 ;
      RECT 0.048 44.544 138.635 44.64 ;
      RECT 0.048 45.312 138.635 45.408 ;
      RECT 0.048 46.08 138.635 46.176 ;
      RECT 0.048 46.848 138.635 46.944 ;
      RECT 0.048 47.616 138.635 47.712 ;
      RECT 0.048 48.384 138.635 48.48 ;
      RECT 0.048 49.152 138.635 49.248 ;
      RECT 0.048 49.92 138.635 50.016 ;
      RECT 0.048 50.688 138.635 50.784 ;
      RECT 0.048 51.456 138.635 51.552 ;
      RECT 0.048 52.224 138.635 52.32 ;
      RECT 0.048 52.992 138.635 53.088 ;
      RECT 0.048 53.76 138.635 53.856 ;
      RECT 0.048 54.528 138.635 54.624 ;
      RECT 0.048 55.296 138.635 55.392 ;
      RECT 0.048 56.064 138.635 56.16 ;
      RECT 0.048 56.832 138.635 56.928 ;
      RECT 0.048 57.6 138.635 57.696 ;
      RECT 0.048 58.368 138.635 58.464 ;
      RECT 0.048 59.136 138.635 59.232 ;
      RECT 0.048 59.904 138.635 60 ;
      RECT 0.048 60.672 138.635 60.768 ;
      RECT 0.048 61.44 138.635 61.536 ;
      RECT 0.048 62.208 138.635 62.304 ;
      RECT 0.048 62.976 138.635 63.072 ;
      RECT 0.048 63.744 138.635 63.84 ;
      RECT 0.048 64.512 138.635 64.608 ;
      RECT 0.048 65.28 138.635 65.376 ;
      RECT 0.048 66.048 138.635 66.144 ;
      RECT 0.048 66.816 138.635 66.912 ;
      RECT 0.048 67.584 138.635 67.68 ;
      RECT 0.048 68.352 138.635 68.448 ;
      RECT 0.048 69.12 138.635 69.216 ;
      RECT 0.048 69.888 138.635 69.984 ;
      RECT 0.048 70.656 138.635 70.752 ;
      RECT 0.048 71.424 138.635 71.52 ;
      RECT 0.048 72.192 138.635 72.288 ;
      RECT 0.048 72.96 138.635 73.056 ;
      RECT 0.048 73.728 138.635 73.824 ;
      RECT 0.048 74.496 138.635 74.592 ;
      RECT 0.048 75.264 138.635 75.36 ;
      RECT 0.048 76.032 138.635 76.128 ;
      RECT 0.048 76.8 138.635 76.896 ;
      RECT 0.048 77.568 138.635 77.664 ;
      RECT 0.048 78.336 138.635 78.432 ;
      RECT 0.048 79.104 138.635 79.2 ;
      RECT 0.048 79.872 138.635 79.968 ;
      RECT 0.048 80.64 138.635 80.736 ;
      RECT 0.048 81.408 138.635 81.504 ;
      RECT 0.048 82.176 138.635 82.272 ;
      RECT 0.048 82.944 138.635 83.04 ;
      RECT 0.048 83.712 138.635 83.808 ;
      RECT 0.048 84.48 138.635 84.576 ;
      RECT 0.048 85.248 138.635 85.344 ;
      RECT 0.048 86.016 138.635 86.112 ;
      RECT 0.048 86.784 138.635 86.88 ;
      RECT 0.048 87.552 138.635 87.648 ;
      RECT 0.048 88.32 138.635 88.416 ;
      RECT 0.048 89.088 138.635 89.184 ;
      RECT 0.048 89.856 138.635 89.952 ;
      RECT 0.048 90.624 138.635 90.72 ;
      RECT 0.048 91.392 138.635 91.488 ;
      RECT 0.048 92.16 138.635 92.256 ;
      RECT 0.048 92.928 138.635 93.024 ;
      RECT 0.048 93.696 138.635 93.792 ;
      RECT 0.048 94.464 138.635 94.56 ;
      RECT 0.048 95.232 138.635 95.328 ;
      RECT 0.048 96 138.635 96.096 ;
      RECT 0.048 96.768 138.635 96.864 ;
      RECT 0.048 97.536 138.635 97.632 ;
      RECT 0.048 98.304 138.635 98.4 ;
      RECT 0.048 99.072 138.635 99.168 ;
      RECT 0.048 99.84 138.635 99.936 ;
      RECT 0.048 100.608 138.635 100.704 ;
      RECT 0.048 101.376 138.635 101.472 ;
      RECT 0.048 102.144 138.635 102.24 ;
      RECT 0.048 102.912 138.635 103.008 ;
      RECT 0.048 103.68 138.635 103.776 ;
      RECT 0.048 104.448 138.635 104.544 ;
      RECT 0.048 105.216 138.635 105.312 ;
      RECT 0.048 105.984 138.635 106.08 ;
      RECT 0.048 106.752 138.635 106.848 ;
      RECT 0.048 107.52 138.635 107.616 ;
      RECT 0.048 108.288 138.635 108.384 ;
      RECT 0.048 109.056 138.635 109.152 ;
      RECT 0.048 109.824 138.635 109.92 ;
      RECT 0.048 110.592 138.635 110.688 ;
      RECT 0.048 111.36 138.635 111.456 ;
      RECT 0.048 112.128 138.635 112.224 ;
      RECT 0.048 112.896 138.635 112.992 ;
      RECT 0.048 113.664 138.635 113.76 ;
      RECT 0.048 114.432 138.635 114.528 ;
      RECT 0.048 115.2 138.635 115.296 ;
      RECT 0.048 115.968 138.635 116.064 ;
      RECT 0.048 116.736 138.635 116.832 ;
      RECT 0.048 117.504 138.635 117.6 ;
      RECT 0.048 118.272 138.635 118.368 ;
      RECT 0.048 119.04 138.635 119.136 ;
      RECT 0.048 119.808 138.635 119.904 ;
      RECT 0.048 120.576 138.635 120.672 ;
      RECT 0.048 121.344 138.635 121.44 ;
      RECT 0.048 122.112 138.635 122.208 ;
      RECT 0.048 122.88 138.635 122.976 ;
      RECT 0.048 123.648 138.635 123.744 ;
      RECT 0.048 124.416 138.635 124.512 ;
      RECT 0.048 125.184 138.635 125.28 ;
      RECT 0.048 125.952 138.635 126.048 ;
      RECT 0.048 126.72 138.635 126.816 ;
      RECT 0.048 127.488 138.635 127.584 ;
      RECT 0.048 128.256 138.635 128.352 ;
      RECT 0.048 129.024 138.635 129.12 ;
      RECT 0.048 129.792 138.635 129.888 ;
      RECT 0.048 130.56 138.635 130.656 ;
      RECT 0.048 131.328 138.635 131.424 ;
      RECT 0.048 132.096 138.635 132.192 ;
      RECT 0.048 132.864 138.635 132.96 ;
      RECT 0.048 133.632 138.635 133.728 ;
      RECT 0.048 134.4 138.635 134.496 ;
      RECT 0.048 135.168 138.635 135.264 ;
      RECT 0.048 135.936 138.635 136.032 ;
      RECT 0.048 136.704 138.635 136.8 ;
      RECT 0.048 137.472 138.635 137.568 ;
      RECT 0.048 138.24 138.635 138.336 ;
      RECT 0.048 139.008 138.635 139.104 ;
      RECT 0.048 139.776 138.635 139.872 ;
      RECT 0.048 140.544 138.635 140.64 ;
      RECT 0.048 141.312 138.635 141.408 ;
      RECT 0.048 142.08 138.635 142.176 ;
      RECT 0.048 142.848 138.635 142.944 ;
      RECT 0.048 143.616 138.635 143.712 ;
      RECT 0.048 144.384 138.635 144.48 ;
      RECT 0.048 145.152 138.635 145.248 ;
      RECT 0.048 145.92 138.635 146.016 ;
      RECT 0.048 146.688 138.635 146.784 ;
      RECT 0.048 147.456 138.635 147.552 ;
      RECT 0.048 148.224 138.635 148.32 ;
      RECT 0.048 148.992 138.635 149.088 ;
      RECT 0.048 149.76 138.635 149.856 ;
      RECT 0.048 150.528 138.635 150.624 ;
      RECT 0.048 151.296 138.635 151.392 ;
      RECT 0.048 152.064 138.635 152.16 ;
      RECT 0.048 152.832 138.635 152.928 ;
      RECT 0.048 153.6 138.635 153.696 ;
      RECT 0.048 154.368 138.635 154.464 ;
      RECT 0.048 155.136 138.635 155.232 ;
      RECT 0.048 155.904 138.635 156 ;
      RECT 0.048 156.672 138.635 156.768 ;
      RECT 0.048 157.44 138.635 157.536 ;
      RECT 0.048 158.208 138.635 158.304 ;
      RECT 0.048 158.976 138.635 159.072 ;
      RECT 0.048 159.744 138.635 159.84 ;
      RECT 0.048 160.512 138.635 160.608 ;
      RECT 0.048 161.28 138.635 161.376 ;
      RECT 0.048 162.048 138.635 162.144 ;
      RECT 0.048 162.816 138.635 162.912 ;
      RECT 0.048 163.584 138.635 163.68 ;
      RECT 0.048 164.352 138.635 164.448 ;
      RECT 0.048 165.12 138.635 165.216 ;
      RECT 0.048 165.888 138.635 165.984 ;
      RECT 0.048 166.656 138.635 166.752 ;
      RECT 0.048 167.424 138.635 167.52 ;
      RECT 0.048 168.192 138.635 168.288 ;
      RECT 0.048 168.96 138.635 169.056 ;
      RECT 0.048 169.728 138.635 169.824 ;
      RECT 0.048 170.496 138.635 170.592 ;
      RECT 0.048 171.264 138.635 171.36 ;
      RECT 0.048 172.032 138.635 172.128 ;
      RECT 0.048 172.8 138.635 172.896 ;
      RECT 0.048 173.568 138.635 173.664 ;
      RECT 0.048 174.336 138.635 174.432 ;
      RECT 0.048 175.104 138.635 175.2 ;
      RECT 0.048 175.872 138.635 175.968 ;
      RECT 0.048 176.64 138.635 176.736 ;
      RECT 0.048 177.408 138.635 177.504 ;
      RECT 0.048 178.176 138.635 178.272 ;
      RECT 0.048 178.944 138.635 179.04 ;
      RECT 0.048 179.712 138.635 179.808 ;
      RECT 0.048 180.48 138.635 180.576 ;
      RECT 0.048 181.248 138.635 181.344 ;
      RECT 0.048 182.016 138.635 182.112 ;
      RECT 0.048 182.784 138.635 182.88 ;
      RECT 0.048 183.552 138.635 183.648 ;
      RECT 0.048 184.32 138.635 184.416 ;
      RECT 0.048 185.088 138.635 185.184 ;
      RECT 0.048 185.856 138.635 185.952 ;
      RECT 0.048 186.624 138.635 186.72 ;
      RECT 0.048 187.392 138.635 187.488 ;
      RECT 0.048 188.16 138.635 188.256 ;
      RECT 0.048 188.928 138.635 189.024 ;
      RECT 0.048 189.696 138.635 189.792 ;
      RECT 0.048 190.464 138.635 190.56 ;
      RECT 0.048 191.232 138.635 191.328 ;
      RECT 0.048 192 138.635 192.096 ;
      RECT 0.048 192.768 138.635 192.864 ;
      RECT 0.048 193.536 138.635 193.632 ;
      RECT 0.048 194.304 138.635 194.4 ;
      RECT 0.048 195.072 138.635 195.168 ;
      RECT 0.048 195.84 138.635 195.936 ;
      RECT 0.048 196.608 138.635 196.704 ;
      RECT 0.048 197.376 138.635 197.472 ;
      RECT 0.048 198.144 138.635 198.24 ;
      RECT 0.048 198.912 138.635 199.008 ;
      RECT 0.048 199.68 138.635 199.776 ;
      RECT 0.048 200.448 138.635 200.544 ;
      RECT 0.048 201.216 138.635 201.312 ;
      RECT 0.048 201.984 138.635 202.08 ;
      RECT 0.048 202.752 138.635 202.848 ;
      RECT 0.048 203.52 138.635 203.616 ;
      RECT 0.048 204.288 138.635 204.384 ;
      RECT 0.048 205.056 138.635 205.152 ;
      RECT 0.048 205.824 138.635 205.92 ;
      RECT 0.048 206.592 138.635 206.688 ;
      RECT 0.048 207.36 138.635 207.456 ;
      RECT 0.048 208.128 138.635 208.224 ;
      RECT 0.048 208.896 138.635 208.992 ;
      RECT 0.048 209.664 138.635 209.76 ;
      RECT 0.048 210.432 138.635 210.528 ;
      RECT 0.048 211.2 138.635 211.296 ;
      RECT 0.048 211.968 138.635 212.064 ;
      RECT 0.048 212.736 138.635 212.832 ;
      RECT 0.048 213.504 138.635 213.6 ;
      RECT 0.048 214.272 138.635 214.368 ;
      RECT 0.048 215.04 138.635 215.136 ;
      RECT 0.048 215.808 138.635 215.904 ;
      RECT 0.048 216.576 138.635 216.672 ;
      RECT 0.048 217.344 138.635 217.44 ;
      RECT 0.048 218.112 138.635 218.208 ;
      RECT 0.048 218.88 138.635 218.976 ;
      RECT 0.048 219.648 138.635 219.744 ;
      RECT 0.048 220.416 138.635 220.512 ;
      RECT 0.048 221.184 138.635 221.28 ;
      RECT 0.048 221.952 138.635 222.048 ;
      RECT 0.048 222.72 138.635 222.816 ;
      RECT 0.048 223.488 138.635 223.584 ;
      RECT 0.048 224.256 138.635 224.352 ;
      RECT 0.048 225.024 138.635 225.12 ;
      RECT 0.048 225.792 138.635 225.888 ;
      RECT 0.048 226.56 138.635 226.656 ;
      RECT 0.048 227.328 138.635 227.424 ;
      RECT 0.048 228.096 138.635 228.192 ;
      RECT 0.048 228.864 138.635 228.96 ;
      RECT 0.048 229.632 138.635 229.728 ;
      RECT 0.048 230.4 138.635 230.496 ;
      RECT 0.048 231.168 138.635 231.264 ;
      RECT 0.048 231.936 138.635 232.032 ;
      RECT 0.048 232.704 138.635 232.8 ;
      RECT 0.048 233.472 138.635 233.568 ;
      RECT 0.048 234.24 138.635 234.336 ;
      RECT 0.048 235.008 138.635 235.104 ;
      RECT 0.048 235.776 138.635 235.872 ;
      RECT 0.048 236.544 138.635 236.64 ;
      RECT 0.048 237.312 138.635 237.408 ;
      RECT 0.048 238.08 138.635 238.176 ;
      RECT 0.048 238.848 138.635 238.944 ;
      RECT 0.048 239.616 138.635 239.712 ;
      RECT 0.048 240.384 138.635 240.48 ;
      RECT 0.048 241.152 138.635 241.248 ;
      RECT 0.048 241.92 138.635 242.016 ;
      RECT 0.048 242.688 138.635 242.784 ;
      RECT 0.048 243.456 138.635 243.552 ;
      RECT 0.048 244.224 138.635 244.32 ;
      RECT 0.048 244.992 138.635 245.088 ;
      RECT 0.048 245.76 138.635 245.856 ;
      RECT 0.048 246.528 138.635 246.624 ;
      RECT 0.048 247.296 138.635 247.392 ;
      RECT 0.048 248.064 138.635 248.16 ;
      RECT 0.048 248.832 138.635 248.928 ;
      RECT 0.048 249.6 138.635 249.696 ;
      RECT 0.048 250.368 138.635 250.464 ;
      RECT 0.048 251.136 138.635 251.232 ;
      RECT 0.048 251.904 138.635 252 ;
      RECT 0.048 252.672 138.635 252.768 ;
      RECT 0.048 253.44 138.635 253.536 ;
      RECT 0.048 254.208 138.635 254.304 ;
      RECT 0.048 254.976 138.635 255.072 ;
      RECT 0.048 255.744 138.635 255.84 ;
      RECT 0.048 256.512 138.635 256.608 ;
      RECT 0.048 257.28 138.635 257.376 ;
      RECT 0.048 258.048 138.635 258.144 ;
      RECT 0.048 258.816 138.635 258.912 ;
      RECT 0.048 259.584 138.635 259.68 ;
      RECT 0.048 260.352 138.635 260.448 ;
      RECT 0.048 261.12 138.635 261.216 ;
      RECT 0.048 261.888 138.635 261.984 ;
      RECT 0.048 262.656 138.635 262.752 ;
      RECT 0.048 263.424 138.635 263.52 ;
      RECT 0.048 264.192 138.635 264.288 ;
      RECT 0.048 264.96 138.635 265.056 ;
      RECT 0.048 265.728 138.635 265.824 ;
      RECT 0.048 266.496 138.635 266.592 ;
      RECT 0.048 267.264 138.635 267.36 ;
      RECT 0.048 268.032 138.635 268.128 ;
      RECT 0.048 268.8 138.635 268.896 ;
      RECT 0.048 269.568 138.635 269.664 ;
      RECT 0.048 270.336 138.635 270.432 ;
      RECT 0.048 271.104 138.635 271.2 ;
      RECT 0.048 271.872 138.635 271.968 ;
      RECT 0.048 272.64 138.635 272.736 ;
      RECT 0.048 273.408 138.635 273.504 ;
      RECT 0.048 274.176 138.635 274.272 ;
      RECT 0.048 274.944 138.635 275.04 ;
      RECT 0.048 275.712 138.635 275.808 ;
      RECT 0.048 276.48 138.635 276.576 ;
      RECT 0.048 277.248 138.635 277.344 ;
      RECT 0.048 278.016 138.635 278.112 ;
      RECT 0.048 278.784 138.635 278.88 ;
      RECT 0.048 279.552 138.635 279.648 ;
      RECT 0.048 280.32 138.635 280.416 ;
      RECT 0.048 281.088 138.635 281.184 ;
      RECT 0.048 281.856 138.635 281.952 ;
      RECT 0.048 282.624 138.635 282.72 ;
      RECT 0.048 283.392 138.635 283.488 ;
      RECT 0.048 284.16 138.635 284.256 ;
      RECT 0.048 284.928 138.635 285.024 ;
      RECT 0.048 285.696 138.635 285.792 ;
      RECT 0.048 286.464 138.635 286.56 ;
      RECT 0.048 287.232 138.635 287.328 ;
      RECT 0.048 288 138.635 288.096 ;
      RECT 0.048 288.768 138.635 288.864 ;
      RECT 0.048 289.536 138.635 289.632 ;
      RECT 0.048 290.304 138.635 290.4 ;
      RECT 0.048 291.072 138.635 291.168 ;
      RECT 0.048 291.84 138.635 291.936 ;
      RECT 0.048 292.608 138.635 292.704 ;
      RECT 0.048 293.376 138.635 293.472 ;
      RECT 0.048 294.144 138.635 294.24 ;
      RECT 0.048 294.912 138.635 295.008 ;
      RECT 0.048 295.68 138.635 295.776 ;
      RECT 0.048 296.448 138.635 296.544 ;
      RECT 0.048 297.216 138.635 297.312 ;
      RECT 0.048 297.984 138.635 298.08 ;
      RECT 0.048 298.752 138.635 298.848 ;
      RECT 0.048 299.52 138.635 299.616 ;
      RECT 0.048 300.288 138.635 300.384 ;
      RECT 0.048 301.056 138.635 301.152 ;
      RECT 0.048 301.824 138.635 301.92 ;
      RECT 0.048 302.592 138.635 302.688 ;
      RECT 0.048 303.36 138.635 303.456 ;
      RECT 0.048 304.128 138.635 304.224 ;
      RECT 0.048 304.896 138.635 304.992 ;
      RECT 0.048 305.664 138.635 305.76 ;
      RECT 0.048 306.432 138.635 306.528 ;
      RECT 0.048 307.2 138.635 307.296 ;
      RECT 0.048 307.968 138.635 308.064 ;
      RECT 0.048 308.736 138.635 308.832 ;
      RECT 0.048 309.504 138.635 309.6 ;
      RECT 0.048 310.272 138.635 310.368 ;
      RECT 0.048 311.04 138.635 311.136 ;
      RECT 0.048 311.808 138.635 311.904 ;
      RECT 0.048 312.576 138.635 312.672 ;
      RECT 0.048 313.344 138.635 313.44 ;
      RECT 0.048 314.112 138.635 314.208 ;
      RECT 0.048 314.88 138.635 314.976 ;
      RECT 0.048 315.648 138.635 315.744 ;
      RECT 0.048 316.416 138.635 316.512 ;
      RECT 0.048 317.184 138.635 317.28 ;
      RECT 0.048 317.952 138.635 318.048 ;
      RECT 0.048 318.72 138.635 318.816 ;
      RECT 0.048 319.488 138.635 319.584 ;
      RECT 0.048 320.256 138.635 320.352 ;
      RECT 0.048 321.024 138.635 321.12 ;
      RECT 0.048 321.792 138.635 321.888 ;
      RECT 0.048 322.56 138.635 322.656 ;
      RECT 0.048 323.328 138.635 323.424 ;
      RECT 0.048 324.096 138.635 324.192 ;
      RECT 0.048 324.864 138.635 324.96 ;
      RECT 0.048 325.632 138.635 325.728 ;
      RECT 0.048 326.4 138.635 326.496 ;
      RECT 0.048 327.168 138.635 327.264 ;
      RECT 0.048 327.936 138.635 328.032 ;
      RECT 0.048 328.704 138.635 328.8 ;
      RECT 0.048 329.472 138.635 329.568 ;
      RECT 0.048 330.24 138.635 330.336 ;
      RECT 0.048 331.008 138.635 331.104 ;
      RECT 0.048 331.776 138.635 331.872 ;
      RECT 0.048 332.544 138.635 332.64 ;
      RECT 0.048 333.312 138.635 333.408 ;
      RECT 0.048 334.08 138.635 334.176 ;
      RECT 0.048 334.848 138.635 334.944 ;
      RECT 0.048 335.616 138.635 335.712 ;
      RECT 0.048 336.384 138.635 336.48 ;
      RECT 0.048 337.152 138.635 337.248 ;
      RECT 0.048 337.92 138.635 338.016 ;
      RECT 0.048 338.688 138.635 338.784 ;
      RECT 0.048 339.456 138.635 339.552 ;
      RECT 0.048 340.224 138.635 340.32 ;
      RECT 0.048 340.992 138.635 341.088 ;
      RECT 0.048 341.76 138.635 341.856 ;
      RECT 0.048 342.528 138.635 342.624 ;
      RECT 0.048 343.296 138.635 343.392 ;
      RECT 0.048 344.064 138.635 344.16 ;
      RECT 0.048 344.832 138.635 344.928 ;
      RECT 0.048 345.6 138.635 345.696 ;
      RECT 0.048 346.368 138.635 346.464 ;
      RECT 0.048 347.136 138.635 347.232 ;
      RECT 0.048 347.904 138.635 348 ;
      RECT 0.048 348.672 138.635 348.768 ;
      RECT 0.048 349.44 138.635 349.536 ;
      RECT 0.048 350.208 138.635 350.304 ;
      RECT 0.048 350.976 138.635 351.072 ;
      RECT 0.048 351.744 138.635 351.84 ;
      RECT 0.048 352.512 138.635 352.608 ;
      RECT 0.048 353.28 138.635 353.376 ;
      RECT 0.048 354.048 138.635 354.144 ;
      RECT 0.048 354.816 138.635 354.912 ;
      RECT 0.048 355.584 138.635 355.68 ;
      RECT 0.048 356.352 138.635 356.448 ;
      RECT 0.048 357.12 138.635 357.216 ;
      RECT 0.048 357.888 138.635 357.984 ;
      RECT 0.048 358.656 138.635 358.752 ;
      RECT 0.048 359.424 138.635 359.52 ;
      RECT 0.048 360.192 138.635 360.288 ;
      RECT 0.048 360.96 138.635 361.056 ;
      RECT 0.048 361.728 138.635 361.824 ;
      RECT 0.048 362.496 138.635 362.592 ;
      RECT 0.048 363.264 138.635 363.36 ;
      RECT 0.048 364.032 138.635 364.128 ;
      RECT 0.048 364.8 138.635 364.896 ;
      RECT 0.048 365.568 138.635 365.664 ;
      RECT 0.048 366.336 138.635 366.432 ;
      RECT 0.048 367.104 138.635 367.2 ;
      RECT 0.048 367.872 138.635 367.968 ;
      RECT 0.048 368.64 138.635 368.736 ;
      RECT 0.048 369.408 138.635 369.504 ;
      RECT 0.048 370.176 138.635 370.272 ;
      RECT 0.048 370.944 138.635 371.04 ;
      RECT 0.048 371.712 138.635 371.808 ;
      RECT 0.048 372.48 138.635 372.576 ;
      RECT 0.048 373.248 138.635 373.344 ;
      RECT 0.048 374.016 138.635 374.112 ;
      RECT 0.048 374.784 138.635 374.88 ;
      RECT 0.048 375.552 138.635 375.648 ;
      RECT 0.048 376.32 138.635 376.416 ;
      RECT 0.048 377.088 138.635 377.184 ;
      RECT 0.048 377.856 138.635 377.952 ;
      RECT 0.048 378.624 138.635 378.72 ;
      RECT 0.048 379.392 138.635 379.488 ;
      RECT 0.048 380.16 138.635 380.256 ;
      RECT 0.048 380.928 138.635 381.024 ;
      RECT 0.048 381.696 138.635 381.792 ;
      RECT 0.048 382.464 138.635 382.56 ;
      RECT 0.048 383.232 138.635 383.328 ;
      RECT 0.048 384 138.635 384.096 ;
      RECT 0.048 384.768 138.635 384.864 ;
      RECT 0.048 385.536 138.635 385.632 ;
      RECT 0.048 386.304 138.635 386.4 ;
      RECT 0.048 387.072 138.635 387.168 ;
      RECT 0.048 387.84 138.635 387.936 ;
      RECT 0.048 388.608 138.635 388.704 ;
      RECT 0.048 389.376 138.635 389.472 ;
      RECT 0.048 390.144 138.635 390.24 ;
      RECT 0.048 390.912 138.635 391.008 ;
      RECT 0.048 391.68 138.635 391.776 ;
      RECT 0.048 392.448 138.635 392.544 ;
      RECT 0.048 393.216 138.635 393.312 ;
      RECT 0.048 393.984 138.635 394.08 ;
      RECT 0.048 394.752 138.635 394.848 ;
      RECT 0.048 395.52 138.635 395.616 ;
      RECT 0.048 396.288 138.635 396.384 ;
      RECT 0.048 397.056 138.635 397.152 ;
      RECT 0.048 397.824 138.635 397.92 ;
      RECT 0.048 398.592 138.635 398.688 ;
      RECT 0.048 399.36 138.635 399.456 ;
      RECT 0.048 400.128 138.635 400.224 ;
      RECT 0.048 400.896 138.635 400.992 ;
      RECT 0.048 401.664 138.635 401.76 ;
      RECT 0.048 402.432 138.635 402.528 ;
      RECT 0.048 403.2 138.635 403.296 ;
      RECT 0.048 403.968 138.635 404.064 ;
      RECT 0.048 404.736 138.635 404.832 ;
      RECT 0.048 405.504 138.635 405.6 ;
      RECT 0.048 406.272 138.635 406.368 ;
      RECT 0.048 407.04 138.635 407.136 ;
      RECT 0.048 407.808 138.635 407.904 ;
      RECT 0.048 408.576 138.635 408.672 ;
      RECT 0.048 409.344 138.635 409.44 ;
      RECT 0.048 410.112 138.635 410.208 ;
      RECT 0.048 410.88 138.635 410.976 ;
      RECT 0.048 411.648 138.635 411.744 ;
      RECT 0.048 412.416 138.635 412.512 ;
      RECT 0.048 413.184 138.635 413.28 ;
      RECT 0.048 413.952 138.635 414.048 ;
      RECT 0.048 414.72 138.635 414.816 ;
      RECT 0.048 415.488 138.635 415.584 ;
      RECT 0.048 416.256 138.635 416.352 ;
      RECT 0.048 417.024 138.635 417.12 ;
      RECT 0.048 417.792 138.635 417.888 ;
      RECT 0.048 418.56 138.635 418.656 ;
      RECT 0.048 419.328 138.635 419.424 ;
      RECT 0.048 420.096 138.635 420.192 ;
      RECT 0.048 420.864 138.635 420.96 ;
      RECT 0.048 421.632 138.635 421.728 ;
      RECT 0.048 422.4 138.635 422.496 ;
      RECT 0.048 423.168 138.635 423.264 ;
      RECT 0.048 423.936 138.635 424.032 ;
      RECT 0.048 424.704 138.635 424.8 ;
      RECT 0.048 425.472 138.635 425.568 ;
      RECT 0.048 426.24 138.635 426.336 ;
      RECT 0.048 427.008 138.635 427.104 ;
      RECT 0.048 427.776 138.635 427.872 ;
      RECT 0.048 428.544 138.635 428.64 ;
      RECT 0.048 429.312 138.635 429.408 ;
      RECT 0.048 430.08 138.635 430.176 ;
      RECT 0.048 430.848 138.635 430.944 ;
      RECT 0.048 431.616 138.635 431.712 ;
      RECT 0.048 432.384 138.635 432.48 ;
      RECT 0.048 433.152 138.635 433.248 ;
      RECT 0.048 433.92 138.635 434.016 ;
      RECT 0.048 434.688 138.635 434.784 ;
      RECT 0.048 435.456 138.635 435.552 ;
      RECT 0.048 436.224 138.635 436.32 ;
      RECT 0.048 436.992 138.635 437.088 ;
      RECT 0.048 437.76 138.635 437.856 ;
      RECT 0.048 438.528 138.635 438.624 ;
      RECT 0.048 439.296 138.635 439.392 ;
      RECT 0.048 440.064 138.635 440.16 ;
      RECT 0.048 440.832 138.635 440.928 ;
      RECT 0.048 441.6 138.635 441.696 ;
      RECT 0.048 442.368 138.635 442.464 ;
      RECT 0.048 443.136 138.635 443.232 ;
      RECT 0.048 443.904 138.635 444 ;
      RECT 0.048 444.672 138.635 444.768 ;
      RECT 0.048 445.44 138.635 445.536 ;
      RECT 0.048 446.208 138.635 446.304 ;
      RECT 0.048 446.976 138.635 447.072 ;
      RECT 0.048 447.744 138.635 447.84 ;
      RECT 0.048 448.512 138.635 448.608 ;
      RECT 0.048 449.28 138.635 449.376 ;
      RECT 0.048 450.048 138.635 450.144 ;
      RECT 0.048 450.816 138.635 450.912 ;
      RECT 0.048 451.584 138.635 451.68 ;
      RECT 0.048 452.352 138.635 452.448 ;
      RECT 0.048 453.12 138.635 453.216 ;
      RECT 0.048 453.888 138.635 453.984 ;
      RECT 0.048 454.656 138.635 454.752 ;
      RECT 0.048 455.424 138.635 455.52 ;
      RECT 0.048 456.192 138.635 456.288 ;
      RECT 0.048 456.96 138.635 457.056 ;
      RECT 0.048 457.728 138.635 457.824 ;
      RECT 0.048 458.496 138.635 458.592 ;
      RECT 0.048 459.264 138.635 459.36 ;
      RECT 0.048 460.032 138.635 460.128 ;
      RECT 0.048 460.8 138.635 460.896 ;
      RECT 0.048 461.568 138.635 461.664 ;
      RECT 0.048 462.336 138.635 462.432 ;
      RECT 0.048 463.104 138.635 463.2 ;
      RECT 0.048 463.872 138.635 463.968 ;
      RECT 0.048 464.64 138.635 464.736 ;
      RECT 0.048 465.408 138.635 465.504 ;
      RECT 0.048 466.176 138.635 466.272 ;
      RECT 0.048 466.944 138.635 467.04 ;
      RECT 0.048 467.712 138.635 467.808 ;
      RECT 0.048 468.48 138.635 468.576 ;
      RECT 0.048 469.248 138.635 469.344 ;
      RECT 0.048 470.016 138.635 470.112 ;
      RECT 0.048 470.784 138.635 470.88 ;
      RECT 0.048 471.552 138.635 471.648 ;
      RECT 0.048 472.32 138.635 472.416 ;
      RECT 0.048 473.088 138.635 473.184 ;
      RECT 0.048 473.856 138.635 473.952 ;
      RECT 0.048 474.624 138.635 474.72 ;
      RECT 0.048 475.392 138.635 475.488 ;
      RECT 0.048 476.16 138.635 476.256 ;
      RECT 0.048 476.928 138.635 477.024 ;
      RECT 0.048 477.696 138.635 477.792 ;
      RECT 0.048 478.464 138.635 478.56 ;
      RECT 0.048 479.232 138.635 479.328 ;
      RECT 0.048 480 138.635 480.096 ;
      RECT 0.048 480.768 138.635 480.864 ;
      RECT 0.048 481.536 138.635 481.632 ;
      RECT 0.048 482.304 138.635 482.4 ;
      RECT 0.048 483.072 138.635 483.168 ;
      RECT 0.048 483.84 138.635 483.936 ;
      RECT 0.048 484.608 138.635 484.704 ;
      RECT 0.048 485.376 138.635 485.472 ;
      RECT 0.048 486.144 138.635 486.24 ;
      RECT 0.048 486.912 138.635 487.008 ;
      RECT 0.048 487.68 138.635 487.776 ;
      RECT 0.048 488.448 138.635 488.544 ;
      RECT 0.048 489.216 138.635 489.312 ;
      RECT 0.048 489.984 138.635 490.08 ;
      RECT 0.048 490.752 138.635 490.848 ;
      RECT 0.048 491.52 138.635 491.616 ;
      RECT 0.048 492.288 138.635 492.384 ;
      RECT 0.048 493.056 138.635 493.152 ;
      RECT 0.048 493.824 138.635 493.92 ;
      RECT 0.048 494.592 138.635 494.688 ;
      RECT 0.048 495.36 138.635 495.456 ;
      RECT 0.048 496.128 138.635 496.224 ;
      RECT 0.048 496.896 138.635 496.992 ;
      RECT 0.048 497.664 138.635 497.76 ;
      RECT 0.048 498.432 138.635 498.528 ;
      RECT 0.048 499.2 138.635 499.296 ;
      RECT 0.048 499.968 138.635 500.064 ;
      RECT 0.048 500.736 138.635 500.832 ;
      RECT 0.048 501.504 138.635 501.6 ;
      RECT 0.048 502.272 138.635 502.368 ;
      RECT 0.048 503.04 138.635 503.136 ;
      RECT 0.048 503.808 138.635 503.904 ;
      RECT 0.048 504.576 138.635 504.672 ;
      RECT 0.048 505.344 138.635 505.44 ;
      RECT 0.048 506.112 138.635 506.208 ;
      RECT 0.048 506.88 138.635 506.976 ;
      RECT 0.048 507.648 138.635 507.744 ;
      RECT 0.048 508.416 138.635 508.512 ;
      RECT 0.048 509.184 138.635 509.28 ;
      RECT 0.048 509.952 138.635 510.048 ;
      RECT 0.048 510.72 138.635 510.816 ;
      RECT 0.048 511.488 138.635 511.584 ;
      RECT 0.048 512.256 138.635 512.352 ;
      RECT 0.048 513.024 138.635 513.12 ;
      RECT 0.048 513.792 138.635 513.888 ;
      RECT 0.048 514.56 138.635 514.656 ;
      RECT 0.048 515.328 138.635 515.424 ;
      RECT 0.048 516.096 138.635 516.192 ;
      RECT 0.048 516.864 138.635 516.96 ;
      RECT 0.048 517.632 138.635 517.728 ;
      RECT 0.048 518.4 138.635 518.496 ;
      RECT 0.048 519.168 138.635 519.264 ;
      RECT 0.048 519.936 138.635 520.032 ;
      RECT 0.048 520.704 138.635 520.8 ;
      RECT 0.048 521.472 138.635 521.568 ;
      RECT 0.048 522.24 138.635 522.336 ;
      RECT 0.048 523.008 138.635 523.104 ;
      RECT 0.048 523.776 138.635 523.872 ;
      RECT 0.048 524.544 138.635 524.64 ;
      RECT 0.048 525.312 138.635 525.408 ;
      RECT 0.048 526.08 138.635 526.176 ;
      RECT 0.048 526.848 138.635 526.944 ;
      RECT 0.048 527.616 138.635 527.712 ;
      RECT 0.048 528.384 138.635 528.48 ;
      RECT 0.048 529.152 138.635 529.248 ;
      RECT 0.048 529.92 138.635 530.016 ;
      RECT 0.048 530.688 138.635 530.784 ;
      RECT 0.048 531.456 138.635 531.552 ;
      RECT 0.048 532.224 138.635 532.32 ;
      RECT 0.048 532.992 138.635 533.088 ;
      RECT 0.048 533.76 138.635 533.856 ;
      RECT 0.048 534.528 138.635 534.624 ;
      RECT 0.048 535.296 138.635 535.392 ;
      RECT 0.048 536.064 138.635 536.16 ;
      RECT 0.048 536.832 138.635 536.928 ;
      RECT 0.048 537.6 138.635 537.696 ;
      RECT 0.048 538.368 138.635 538.464 ;
      RECT 0.048 539.136 138.635 539.232 ;
      RECT 0.048 539.904 138.635 540 ;
      RECT 0.048 540.672 138.635 540.768 ;
      RECT 0.048 541.44 138.635 541.536 ;
      RECT 0.048 542.208 138.635 542.304 ;
      RECT 0.048 542.976 138.635 543.072 ;
      RECT 0.048 543.744 138.635 543.84 ;
      RECT 0.048 544.512 138.635 544.608 ;
      RECT 0.048 545.28 138.635 545.376 ;
      RECT 0.048 546.048 138.635 546.144 ;
      RECT 0.048 546.816 138.635 546.912 ;
      RECT 0.048 547.584 138.635 547.68 ;
      RECT 0.048 548.352 138.635 548.448 ;
      RECT 0.048 549.12 138.635 549.216 ;
      RECT 0.048 549.888 138.635 549.984 ;
      RECT 0.048 550.656 138.635 550.752 ;
      RECT 0.048 551.424 138.635 551.52 ;
      RECT 0.048 552.192 138.635 552.288 ;
      RECT 0.048 552.96 138.635 553.056 ;
      RECT 0.048 553.728 138.635 553.824 ;
      RECT 0.048 554.496 138.635 554.592 ;
      RECT 0.048 555.264 138.635 555.36 ;
      RECT 0.048 556.032 138.635 556.128 ;
      RECT 0.048 556.8 138.635 556.896 ;
      RECT 0.048 557.568 138.635 557.664 ;
      RECT 0.048 558.336 138.635 558.432 ;
      RECT 0.048 559.104 138.635 559.2 ;
      RECT 0.048 559.872 138.635 559.968 ;
      RECT 0.048 560.64 138.635 560.736 ;
      RECT 0.048 561.408 138.635 561.504 ;
      RECT 0.048 562.176 138.635 562.272 ;
      RECT 0.048 562.944 138.635 563.04 ;
      RECT 0.048 563.712 138.635 563.808 ;
      RECT 0.048 564.48 138.635 564.576 ;
      RECT 0.048 565.248 138.635 565.344 ;
      RECT 0.048 566.016 138.635 566.112 ;
      RECT 0.048 566.784 138.635 566.88 ;
      RECT 0.048 567.552 138.635 567.648 ;
      RECT 0.048 568.32 138.635 568.416 ;
      RECT 0.048 569.088 138.635 569.184 ;
      RECT 0.048 569.856 138.635 569.952 ;
      RECT 0.048 570.624 138.635 570.72 ;
      RECT 0.048 571.392 138.635 571.488 ;
      RECT 0.048 572.16 138.635 572.256 ;
      RECT 0.048 572.928 138.635 573.024 ;
      RECT 0.048 573.696 138.635 573.792 ;
      RECT 0.048 574.464 138.635 574.56 ;
      RECT 0.048 575.232 138.635 575.328 ;
      RECT 0.048 576 138.635 576.096 ;
      RECT 0.048 576.768 138.635 576.864 ;
      RECT 0.048 577.536 138.635 577.632 ;
      RECT 0.048 578.304 138.635 578.4 ;
      RECT 0.048 579.072 138.635 579.168 ;
      RECT 0.048 579.84 138.635 579.936 ;
      RECT 0.048 580.608 138.635 580.704 ;
      RECT 0.048 581.376 138.635 581.472 ;
      RECT 0.048 582.144 138.635 582.24 ;
      RECT 0.048 582.912 138.635 583.008 ;
      RECT 0.048 583.68 138.635 583.776 ;
      RECT 0.048 584.448 138.635 584.544 ;
      RECT 0.048 585.216 138.635 585.312 ;
      RECT 0.048 585.984 138.635 586.08 ;
      RECT 0.048 586.752 138.635 586.848 ;
      RECT 0.048 587.52 138.635 587.616 ;
      RECT 0.048 588.288 138.635 588.384 ;
      RECT 0.048 589.056 138.635 589.152 ;
      RECT 0.048 589.824 138.635 589.92 ;
      RECT 0.048 590.592 138.635 590.688 ;
      RECT 0.048 591.36 138.635 591.456 ;
      RECT 0.048 592.128 138.635 592.224 ;
      RECT 0.048 592.896 138.635 592.992 ;
      RECT 0.048 593.664 138.635 593.76 ;
      RECT 0.048 594.432 138.635 594.528 ;
      RECT 0.048 595.2 138.635 595.296 ;
      RECT 0.048 595.968 138.635 596.064 ;
      RECT 0.048 596.736 138.635 596.832 ;
      RECT 0.048 597.504 138.635 597.6 ;
      RECT 0.048 598.272 138.635 598.368 ;
      RECT 0.048 599.04 138.635 599.136 ;
      RECT 0.048 599.808 138.635 599.904 ;
      RECT 0.048 600.576 138.635 600.672 ;
      RECT 0.048 601.344 138.635 601.44 ;
      RECT 0.048 602.112 138.635 602.208 ;
      RECT 0.048 602.88 138.635 602.976 ;
      RECT 0.048 603.648 138.635 603.744 ;
      RECT 0.048 604.416 138.635 604.512 ;
      RECT 0.048 605.184 138.635 605.28 ;
      RECT 0.048 605.952 138.635 606.048 ;
      RECT 0.048 606.72 138.635 606.816 ;
      RECT 0.048 607.488 138.635 607.584 ;
      RECT 0.048 608.256 138.635 608.352 ;
      RECT 0.048 609.024 138.635 609.12 ;
      RECT 0.048 609.792 138.635 609.888 ;
      RECT 0.048 610.56 138.635 610.656 ;
      RECT 0.048 611.328 138.635 611.424 ;
      RECT 0.048 612.096 138.635 612.192 ;
      RECT 0.048 612.864 138.635 612.96 ;
      RECT 0.048 613.632 138.635 613.728 ;
      RECT 0.048 614.4 138.635 614.496 ;
      RECT 0.048 615.168 138.635 615.264 ;
      RECT 0.048 615.936 138.635 616.032 ;
      RECT 0.048 616.704 138.635 616.8 ;
      RECT 0.048 617.472 138.635 617.568 ;
      RECT 0.048 618.24 138.635 618.336 ;
      RECT 0.048 619.008 138.635 619.104 ;
      RECT 0.048 619.776 138.635 619.872 ;
      RECT 0.048 620.544 138.635 620.64 ;
      RECT 0.048 621.312 138.635 621.408 ;
      RECT 0.048 622.08 138.635 622.176 ;
      RECT 0.048 622.848 138.635 622.944 ;
      RECT 0.048 623.616 138.635 623.712 ;
      RECT 0.048 624.384 138.635 624.48 ;
      RECT 0.048 625.152 138.635 625.248 ;
      RECT 0.048 625.92 138.635 626.016 ;
      RECT 0.048 626.688 138.635 626.784 ;
      RECT 0.048 627.456 138.635 627.552 ;
      RECT 0.048 628.224 138.635 628.32 ;
      RECT 0.048 628.992 138.635 629.088 ;
      RECT 0.048 629.76 138.635 629.856 ;
      RECT 0.048 630.528 138.635 630.624 ;
      RECT 0.048 631.296 138.635 631.392 ;
      RECT 0.048 632.064 138.635 632.16 ;
      RECT 0.048 632.832 138.635 632.928 ;
      RECT 0.048 633.6 138.635 633.696 ;
      RECT 0.048 634.368 138.635 634.464 ;
      RECT 0.048 635.136 138.635 635.232 ;
      RECT 0.048 635.904 138.635 636 ;
      RECT 0.048 636.672 138.635 636.768 ;
      RECT 0.048 637.44 138.635 637.536 ;
      RECT 0.048 638.208 138.635 638.304 ;
      RECT 0.048 638.976 138.635 639.072 ;
      RECT 0.048 639.744 138.635 639.84 ;
      RECT 0.048 640.512 138.635 640.608 ;
      RECT 0.048 641.28 138.635 641.376 ;
      RECT 0.048 642.048 138.635 642.144 ;
      RECT 0.048 642.816 138.635 642.912 ;
      RECT 0.048 643.584 138.635 643.68 ;
      RECT 0.048 644.352 138.635 644.448 ;
      RECT 0.048 645.12 138.635 645.216 ;
      RECT 0.048 645.888 138.635 645.984 ;
      RECT 0.048 646.656 138.635 646.752 ;
      RECT 0.048 647.424 138.635 647.52 ;
      RECT 0.048 648.192 138.635 648.288 ;
      RECT 0.048 648.96 138.635 649.056 ;
      RECT 0.048 649.728 138.635 649.824 ;
      RECT 0.048 650.496 138.635 650.592 ;
      RECT 0.048 651.264 138.635 651.36 ;
      RECT 0.048 652.032 138.635 652.128 ;
      RECT 0.048 652.8 138.635 652.896 ;
      RECT 0.048 653.568 138.635 653.664 ;
      RECT 0.048 654.336 138.635 654.432 ;
      RECT 0.048 655.104 138.635 655.2 ;
      RECT 0.048 655.872 138.635 655.968 ;
      RECT 0.048 656.64 138.635 656.736 ;
      RECT 0.048 657.408 138.635 657.504 ;
      RECT 0.048 658.176 138.635 658.272 ;
      RECT 0.048 658.944 138.635 659.04 ;
      RECT 0.048 659.712 138.635 659.808 ;
      RECT 0.048 660.48 138.635 660.576 ;
      RECT 0.048 661.248 138.635 661.344 ;
      RECT 0.048 662.016 138.635 662.112 ;
      RECT 0.048 662.784 138.635 662.88 ;
      RECT 0.048 663.552 138.635 663.648 ;
      RECT 0.048 664.32 138.635 664.416 ;
      RECT 0.048 665.088 138.635 665.184 ;
      RECT 0.048 665.856 138.635 665.952 ;
      RECT 0.048 666.624 138.635 666.72 ;
      RECT 0.048 667.392 138.635 667.488 ;
      RECT 0.048 668.16 138.635 668.256 ;
      RECT 0.048 668.928 138.635 669.024 ;
      RECT 0.048 669.696 138.635 669.792 ;
      RECT 0.048 670.464 138.635 670.56 ;
      RECT 0.048 671.232 138.635 671.328 ;
      RECT 0.048 672 138.635 672.096 ;
      RECT 0.048 672.768 138.635 672.864 ;
      RECT 0.048 673.536 138.635 673.632 ;
      RECT 0.048 674.304 138.635 674.4 ;
      RECT 0.048 675.072 138.635 675.168 ;
      RECT 0.048 675.84 138.635 675.936 ;
      RECT 0.048 676.608 138.635 676.704 ;
      RECT 0.048 677.376 138.635 677.472 ;
      RECT 0.048 678.144 138.635 678.24 ;
      RECT 0.048 678.912 138.635 679.008 ;
      RECT 0.048 679.68 138.635 679.776 ;
      RECT 0.048 680.448 138.635 680.544 ;
      RECT 0.048 681.216 138.635 681.312 ;
      RECT 0.048 681.984 138.635 682.08 ;
      RECT 0.048 682.752 138.635 682.848 ;
      RECT 0.048 683.52 138.635 683.616 ;
      RECT 0.048 684.288 138.635 684.384 ;
      RECT 0.048 685.056 138.635 685.152 ;
      RECT 0.048 685.824 138.635 685.92 ;
      RECT 0.048 686.592 138.635 686.688 ;
      RECT 0.048 687.36 138.635 687.456 ;
      RECT 0.048 688.128 138.635 688.224 ;
      RECT 0.048 688.896 138.635 688.992 ;
      RECT 0.048 689.664 138.635 689.76 ;
      RECT 0.048 690.432 138.635 690.528 ;
      RECT 0.048 691.2 138.635 691.296 ;
      RECT 0.048 691.968 138.635 692.064 ;
      RECT 0.048 692.736 138.635 692.832 ;
      RECT 0.048 693.504 138.635 693.6 ;
      RECT 0.048 694.272 138.635 694.368 ;
      RECT 0.048 695.04 138.635 695.136 ;
      RECT 0.048 695.808 138.635 695.904 ;
      RECT 0.048 696.576 138.635 696.672 ;
      RECT 0.048 697.344 138.635 697.44 ;
      RECT 0.048 698.112 138.635 698.208 ;
      RECT 0.048 698.88 138.635 698.976 ;
      RECT 0.048 699.648 138.635 699.744 ;
      RECT 0.048 700.416 138.635 700.512 ;
      RECT 0.048 701.184 138.635 701.28 ;
      RECT 0.048 701.952 138.635 702.048 ;
      RECT 0.048 702.72 138.635 702.816 ;
      RECT 0.048 703.488 138.635 703.584 ;
      RECT 0.048 704.256 138.635 704.352 ;
      RECT 0.048 705.024 138.635 705.12 ;
      RECT 0.048 705.792 138.635 705.888 ;
      RECT 0.048 706.56 138.635 706.656 ;
      RECT 0.048 707.328 138.635 707.424 ;
      RECT 0.048 708.096 138.635 708.192 ;
      RECT 0.048 708.864 138.635 708.96 ;
      RECT 0.048 709.632 138.635 709.728 ;
      RECT 0.048 710.4 138.635 710.496 ;
      RECT 0.048 711.168 138.635 711.264 ;
      RECT 0.048 711.936 138.635 712.032 ;
      RECT 0.048 712.704 138.635 712.8 ;
      RECT 0.048 713.472 138.635 713.568 ;
      RECT 0.048 714.24 138.635 714.336 ;
      RECT 0.048 715.008 138.635 715.104 ;
      RECT 0.048 715.776 138.635 715.872 ;
      RECT 0.048 716.544 138.635 716.64 ;
      RECT 0.048 717.312 138.635 717.408 ;
      RECT 0.048 718.08 138.635 718.176 ;
      RECT 0.048 718.848 138.635 718.944 ;
      RECT 0.048 719.616 138.635 719.712 ;
      RECT 0.048 720.384 138.635 720.48 ;
      RECT 0.048 721.152 138.635 721.248 ;
      RECT 0.048 721.92 138.635 722.016 ;
      RECT 0.048 722.688 138.635 722.784 ;
      RECT 0.048 723.456 138.635 723.552 ;
      RECT 0.048 724.224 138.635 724.32 ;
      RECT 0.048 724.992 138.635 725.088 ;
      RECT 0.048 725.76 138.635 725.856 ;
      RECT 0.048 726.528 138.635 726.624 ;
      RECT 0.048 727.296 138.635 727.392 ;
      RECT 0.048 728.064 138.635 728.16 ;
      RECT 0.048 728.832 138.635 728.928 ;
      RECT 0.048 729.6 138.635 729.696 ;
      RECT 0.048 730.368 138.635 730.464 ;
      RECT 0.048 731.136 138.635 731.232 ;
      RECT 0.048 731.904 138.635 732 ;
      RECT 0.048 732.672 138.635 732.768 ;
      RECT 0.048 733.44 138.635 733.536 ;
      RECT 0.048 734.208 138.635 734.304 ;
      RECT 0.048 734.976 138.635 735.072 ;
      RECT 0.048 735.744 138.635 735.84 ;
      RECT 0.048 736.512 138.635 736.608 ;
      RECT 0.048 737.28 138.635 737.376 ;
      RECT 0.048 738.048 138.635 738.144 ;
      RECT 0.048 738.816 138.635 738.912 ;
      RECT 0.048 739.584 138.635 739.68 ;
      RECT 0.048 740.352 138.635 740.448 ;
      RECT 0.048 741.12 138.635 741.216 ;
      RECT 0.048 741.888 138.635 741.984 ;
      RECT 0.048 742.656 138.635 742.752 ;
      RECT 0.048 743.424 138.635 743.52 ;
      RECT 0.048 744.192 138.635 744.288 ;
      RECT 0.048 744.96 138.635 745.056 ;
      RECT 0.048 745.728 138.635 745.824 ;
      RECT 0.048 746.496 138.635 746.592 ;
      RECT 0.048 747.264 138.635 747.36 ;
      RECT 0.048 748.032 138.635 748.128 ;
      RECT 0.048 748.8 138.635 748.896 ;
      RECT 0.048 749.568 138.635 749.664 ;
      RECT 0.048 750.336 138.635 750.432 ;
      RECT 0.048 751.104 138.635 751.2 ;
      RECT 0.048 751.872 138.635 751.968 ;
      RECT 0.048 752.64 138.635 752.736 ;
      RECT 0.048 753.408 138.635 753.504 ;
      RECT 0.048 754.176 138.635 754.272 ;
      RECT 0.048 754.944 138.635 755.04 ;
      RECT 0.048 755.712 138.635 755.808 ;
      RECT 0.048 756.48 138.635 756.576 ;
      RECT 0.048 757.248 138.635 757.344 ;
      RECT 0.048 758.016 138.635 758.112 ;
      RECT 0.048 758.784 138.635 758.88 ;
      RECT 0.048 759.552 138.635 759.648 ;
      RECT 0.048 760.32 138.635 760.416 ;
      RECT 0.048 761.088 138.635 761.184 ;
      RECT 0.048 761.856 138.635 761.952 ;
      RECT 0.048 762.624 138.635 762.72 ;
      RECT 0.048 763.392 138.635 763.488 ;
      RECT 0.048 764.16 138.635 764.256 ;
      RECT 0.048 764.928 138.635 765.024 ;
      RECT 0.048 765.696 138.635 765.792 ;
      RECT 0.048 766.464 138.635 766.56 ;
      RECT 0.048 767.232 138.635 767.328 ;
      RECT 0.048 768 138.635 768.096 ;
      RECT 0.048 768.768 138.635 768.864 ;
      RECT 0.048 769.536 138.635 769.632 ;
      RECT 0.048 770.304 138.635 770.4 ;
      RECT 0.048 771.072 138.635 771.168 ;
      RECT 0.048 771.84 138.635 771.936 ;
      RECT 0.048 772.608 138.635 772.704 ;
      RECT 0.048 773.376 138.635 773.472 ;
      RECT 0.048 774.144 138.635 774.24 ;
      RECT 0.048 774.912 138.635 775.008 ;
      RECT 0.048 775.68 138.635 775.776 ;
      RECT 0.048 776.448 138.635 776.544 ;
      RECT 0.048 777.216 138.635 777.312 ;
      RECT 0.048 777.984 138.635 778.08 ;
      RECT 0.048 778.752 138.635 778.848 ;
      RECT 0.048 779.52 138.635 779.616 ;
      RECT 0.048 780.288 138.635 780.384 ;
      RECT 0.048 781.056 138.635 781.152 ;
      RECT 0.048 781.824 138.635 781.92 ;
      RECT 0.048 782.592 138.635 782.688 ;
      RECT 0.048 783.36 138.635 783.456 ;
      RECT 0.048 784.128 138.635 784.224 ;
      RECT 0.048 784.896 138.635 784.992 ;
      RECT 0.048 785.664 138.635 785.76 ;
      RECT 0.048 786.432 138.635 786.528 ;
      RECT 0.048 787.2 138.635 787.296 ;
      RECT 0.048 787.968 138.635 788.064 ;
      RECT 0.048 788.736 138.635 788.832 ;
      RECT 0.048 789.504 138.635 789.6 ;
      RECT 0.048 790.272 138.635 790.368 ;
      RECT 0.048 791.04 138.635 791.136 ;
      RECT 0.048 791.808 138.635 791.904 ;
      RECT 0.048 792.576 138.635 792.672 ;
      RECT 0.048 793.344 138.635 793.44 ;
      RECT 0.048 794.112 138.635 794.208 ;
      RECT 0.048 794.88 138.635 794.976 ;
      RECT 0.048 795.648 138.635 795.744 ;
      RECT 0.048 796.416 138.635 796.512 ;
      RECT 0.048 797.184 138.635 797.28 ;
      RECT 0.048 797.952 138.635 798.048 ;
      RECT 0.048 798.72 138.635 798.816 ;
      RECT 0.048 799.488 138.635 799.584 ;
      RECT 0.048 800.256 138.635 800.352 ;
      RECT 0.048 801.024 138.635 801.12 ;
      RECT 0.048 801.792 138.635 801.888 ;
      RECT 0.048 802.56 138.635 802.656 ;
      RECT 0.048 803.328 138.635 803.424 ;
      RECT 0.048 804.096 138.635 804.192 ;
      RECT 0.048 804.864 138.635 804.96 ;
      RECT 0.048 805.632 138.635 805.728 ;
      RECT 0.048 806.4 138.635 806.496 ;
      RECT 0.048 807.168 138.635 807.264 ;
      RECT 0.048 807.936 138.635 808.032 ;
      RECT 0.048 808.704 138.635 808.8 ;
      RECT 0.048 809.472 138.635 809.568 ;
      RECT 0.048 810.24 138.635 810.336 ;
      RECT 0.048 811.008 138.635 811.104 ;
      RECT 0.048 811.776 138.635 811.872 ;
      RECT 0.048 812.544 138.635 812.64 ;
      RECT 0.048 813.312 138.635 813.408 ;
      RECT 0.048 814.08 138.635 814.176 ;
      RECT 0.048 814.848 138.635 814.944 ;
      RECT 0.048 815.616 138.635 815.712 ;
      RECT 0.048 816.384 138.635 816.48 ;
      RECT 0.048 817.152 138.635 817.248 ;
      RECT 0.048 817.92 138.635 818.016 ;
      RECT 0.048 818.688 138.635 818.784 ;
      RECT 0.048 819.456 138.635 819.552 ;
      RECT 0.048 820.224 138.635 820.32 ;
      RECT 0.048 820.992 138.635 821.088 ;
      RECT 0.048 821.76 138.635 821.856 ;
      RECT 0.048 822.528 138.635 822.624 ;
      RECT 0.048 823.296 138.635 823.392 ;
      RECT 0.048 824.064 138.635 824.16 ;
      RECT 0.048 824.832 138.635 824.928 ;
      RECT 0.048 825.6 138.635 825.696 ;
      RECT 0.048 826.368 138.635 826.464 ;
      RECT 0.048 827.136 138.635 827.232 ;
      RECT 0.048 827.904 138.635 828 ;
      RECT 0.048 828.672 138.635 828.768 ;
      RECT 0.048 829.44 138.635 829.536 ;
      RECT 0.048 830.208 138.635 830.304 ;
      RECT 0.048 830.976 138.635 831.072 ;
      RECT 0.048 831.744 138.635 831.84 ;
      RECT 0.048 832.512 138.635 832.608 ;
      RECT 0.048 833.28 138.635 833.376 ;
      RECT 0.048 834.048 138.635 834.144 ;
      RECT 0.048 834.816 138.635 834.912 ;
      RECT 0.048 835.584 138.635 835.68 ;
      RECT 0.048 836.352 138.635 836.448 ;
      RECT 0.048 837.12 138.635 837.216 ;
      RECT 0.048 837.888 138.635 837.984 ;
      RECT 0.048 838.656 138.635 838.752 ;
      RECT 0.048 839.424 138.635 839.52 ;
      RECT 0.048 840.192 138.635 840.288 ;
      RECT 0.048 840.96 138.635 841.056 ;
      RECT 0.048 841.728 138.635 841.824 ;
      RECT 0.048 842.496 138.635 842.592 ;
      RECT 0.048 843.264 138.635 843.36 ;
      RECT 0.048 844.032 138.635 844.128 ;
      RECT 0.048 844.8 138.635 844.896 ;
      RECT 0.048 845.568 138.635 845.664 ;
      RECT 0.048 846.336 138.635 846.432 ;
      RECT 0.048 847.104 138.635 847.2 ;
      RECT 0.048 847.872 138.635 847.968 ;
      RECT 0.048 848.64 138.635 848.736 ;
      RECT 0.048 849.408 138.635 849.504 ;
      RECT 0.048 850.176 138.635 850.272 ;
      RECT 0.048 850.944 138.635 851.04 ;
      RECT 0.048 851.712 138.635 851.808 ;
      RECT 0.048 852.48 138.635 852.576 ;
      RECT 0.048 853.248 138.635 853.344 ;
      RECT 0.048 854.016 138.635 854.112 ;
      RECT 0.048 854.784 138.635 854.88 ;
      RECT 0.048 855.552 138.635 855.648 ;
      RECT 0.048 856.32 138.635 856.416 ;
      RECT 0.048 857.088 138.635 857.184 ;
      RECT 0.048 857.856 138.635 857.952 ;
      RECT 0.048 858.624 138.635 858.72 ;
      RECT 0.048 859.392 138.635 859.488 ;
      RECT 0.048 860.16 138.635 860.256 ;
      RECT 0.048 860.928 138.635 861.024 ;
      RECT 0.048 861.696 138.635 861.792 ;
      RECT 0.048 862.464 138.635 862.56 ;
      RECT 0.048 863.232 138.635 863.328 ;
      RECT 0.048 864 138.635 864.096 ;
      RECT 0.048 864.768 138.635 864.864 ;
      RECT 0.048 865.536 138.635 865.632 ;
      RECT 0.048 866.304 138.635 866.4 ;
      RECT 0.048 867.072 138.635 867.168 ;
      RECT 0.048 867.84 138.635 867.936 ;
      RECT 0.048 868.608 138.635 868.704 ;
      RECT 0.048 869.376 138.635 869.472 ;
      RECT 0.048 870.144 138.635 870.24 ;
      RECT 0.048 870.912 138.635 871.008 ;
      RECT 0.048 871.68 138.635 871.776 ;
      RECT 0.048 872.448 138.635 872.544 ;
      RECT 0.048 873.216 138.635 873.312 ;
      RECT 0.048 873.984 138.635 874.08 ;
      RECT 0.048 874.752 138.635 874.848 ;
      RECT 0.048 875.52 138.635 875.616 ;
      RECT 0.048 876.288 138.635 876.384 ;
      RECT 0.048 877.056 138.635 877.152 ;
      RECT 0.048 877.824 138.635 877.92 ;
      RECT 0.048 878.592 138.635 878.688 ;
      RECT 0.048 879.36 138.635 879.456 ;
      RECT 0.048 880.128 138.635 880.224 ;
      RECT 0.048 880.896 138.635 880.992 ;
      RECT 0.048 881.664 138.635 881.76 ;
      RECT 0.048 882.432 138.635 882.528 ;
      RECT 0.048 883.2 138.635 883.296 ;
      RECT 0.048 883.968 138.635 884.064 ;
      RECT 0.048 884.736 138.635 884.832 ;
      RECT 0.048 885.504 138.635 885.6 ;
      RECT 0.048 886.272 138.635 886.368 ;
      RECT 0.048 887.04 138.635 887.136 ;
      RECT 0.048 887.808 138.635 887.904 ;
      RECT 0.048 888.576 138.635 888.672 ;
      RECT 0.048 889.344 138.635 889.44 ;
      RECT 0.048 890.112 138.635 890.208 ;
      RECT 0.048 890.88 138.635 890.976 ;
      RECT 0.048 891.648 138.635 891.744 ;
      RECT 0.048 892.416 138.635 892.512 ;
      RECT 0.048 893.184 138.635 893.28 ;
      RECT 0.048 893.952 138.635 894.048 ;
      RECT 0.048 894.72 138.635 894.816 ;
      RECT 0.048 895.488 138.635 895.584 ;
      RECT 0.048 896.256 138.635 896.352 ;
      RECT 0.048 897.024 138.635 897.12 ;
      RECT 0.048 897.792 138.635 897.888 ;
      RECT 0.048 898.56 138.635 898.656 ;
      RECT 0.048 899.328 138.635 899.424 ;
      RECT 0.048 900.096 138.635 900.192 ;
      RECT 0.048 900.864 138.635 900.96 ;
      RECT 0.048 901.632 138.635 901.728 ;
      RECT 0.048 902.4 138.635 902.496 ;
      RECT 0.048 903.168 138.635 903.264 ;
      RECT 0.048 903.936 138.635 904.032 ;
      RECT 0.048 904.704 138.635 904.8 ;
      RECT 0.048 905.472 138.635 905.568 ;
      RECT 0.048 906.24 138.635 906.336 ;
      RECT 0.048 907.008 138.635 907.104 ;
      RECT 0.048 907.776 138.635 907.872 ;
      RECT 0.048 908.544 138.635 908.64 ;
      RECT 0.048 909.312 138.635 909.408 ;
      RECT 0.048 910.08 138.635 910.176 ;
      RECT 0.048 910.848 138.635 910.944 ;
      RECT 0.048 911.616 138.635 911.712 ;
      RECT 0.048 912.384 138.635 912.48 ;
      RECT 0.048 913.152 138.635 913.248 ;
      RECT 0.048 913.92 138.635 914.016 ;
      RECT 0.048 914.688 138.635 914.784 ;
      RECT 0.048 915.456 138.635 915.552 ;
      RECT 0.048 916.224 138.635 916.32 ;
      RECT 0.048 916.992 138.635 917.088 ;
      RECT 0.048 917.76 138.635 917.856 ;
      RECT 0.048 918.528 138.635 918.624 ;
      RECT 0.048 919.296 138.635 919.392 ;
      RECT 0.048 920.064 138.635 920.16 ;
      RECT 0.048 920.832 138.635 920.928 ;
      RECT 0.048 921.6 138.635 921.696 ;
      RECT 0.048 922.368 138.635 922.464 ;
      RECT 0.048 923.136 138.635 923.232 ;
      RECT 0.048 923.904 138.635 924 ;
      RECT 0.048 924.672 138.635 924.768 ;
      RECT 0.048 925.44 138.635 925.536 ;
      RECT 0.048 926.208 138.635 926.304 ;
      RECT 0.048 926.976 138.635 927.072 ;
      RECT 0.048 927.744 138.635 927.84 ;
      RECT 0.048 928.512 138.635 928.608 ;
      RECT 0.048 929.28 138.635 929.376 ;
      RECT 0.048 930.048 138.635 930.144 ;
      RECT 0.048 930.816 138.635 930.912 ;
      RECT 0.048 931.584 138.635 931.68 ;
      RECT 0.048 932.352 138.635 932.448 ;
      RECT 0.048 933.12 138.635 933.216 ;
      RECT 0.048 933.888 138.635 933.984 ;
      RECT 0.048 934.656 138.635 934.752 ;
      RECT 0.048 935.424 138.635 935.52 ;
      RECT 0.048 936.192 138.635 936.288 ;
      RECT 0.048 936.96 138.635 937.056 ;
      RECT 0.048 937.728 138.635 937.824 ;
      RECT 0.048 938.496 138.635 938.592 ;
      RECT 0.048 939.264 138.635 939.36 ;
      RECT 0.048 940.032 138.635 940.128 ;
      RECT 0.048 940.8 138.635 940.896 ;
      RECT 0.048 941.568 138.635 941.664 ;
      RECT 0.048 942.336 138.635 942.432 ;
      RECT 0.048 943.104 138.635 943.2 ;
      RECT 0.048 943.872 138.635 943.968 ;
      RECT 0.048 944.64 138.635 944.736 ;
      RECT 0.048 945.408 138.635 945.504 ;
      RECT 0.048 946.176 138.635 946.272 ;
      RECT 0.048 946.944 138.635 947.04 ;
      RECT 0.048 947.712 138.635 947.808 ;
      RECT 0.048 948.48 138.635 948.576 ;
      RECT 0.048 949.248 138.635 949.344 ;
      RECT 0.048 950.016 138.635 950.112 ;
      RECT 0.048 950.784 138.635 950.88 ;
      RECT 0.048 951.552 138.635 951.648 ;
      RECT 0.048 952.32 138.635 952.416 ;
      RECT 0.048 953.088 138.635 953.184 ;
      RECT 0.048 953.856 138.635 953.952 ;
      RECT 0.048 954.624 138.635 954.72 ;
      RECT 0.048 955.392 138.635 955.488 ;
      RECT 0.048 956.16 138.635 956.256 ;
      RECT 0.048 956.928 138.635 957.024 ;
      RECT 0.048 957.696 138.635 957.792 ;
      RECT 0.048 958.464 138.635 958.56 ;
      RECT 0.048 959.232 138.635 959.328 ;
      RECT 0.048 960 138.635 960.096 ;
      RECT 0.048 960.768 138.635 960.864 ;
      RECT 0.048 961.536 138.635 961.632 ;
      RECT 0.048 962.304 138.635 962.4 ;
      RECT 0.048 963.072 138.635 963.168 ;
      RECT 0.048 963.84 138.635 963.936 ;
      RECT 0.048 964.608 138.635 964.704 ;
      RECT 0.048 965.376 138.635 965.472 ;
      RECT 0.048 966.144 138.635 966.24 ;
      RECT 0.048 966.912 138.635 967.008 ;
      RECT 0.048 967.68 138.635 967.776 ;
      RECT 0.048 968.448 138.635 968.544 ;
      RECT 0.048 969.216 138.635 969.312 ;
      RECT 0.048 969.984 138.635 970.08 ;
      RECT 0.048 970.752 138.635 970.848 ;
      RECT 0.048 971.52 138.635 971.616 ;
      RECT 0.048 972.288 138.635 972.384 ;
      RECT 0.048 973.056 138.635 973.152 ;
      RECT 0.048 973.824 138.635 973.92 ;
      RECT 0.048 974.592 138.635 974.688 ;
      RECT 0.048 975.36 138.635 975.456 ;
      RECT 0.048 976.128 138.635 976.224 ;
      RECT 0.048 976.896 138.635 976.992 ;
      RECT 0.048 977.664 138.635 977.76 ;
      RECT 0.048 978.432 138.635 978.528 ;
      RECT 0.048 979.2 138.635 979.296 ;
      RECT 0.048 979.968 138.635 980.064 ;
      RECT 0.048 980.736 138.635 980.832 ;
      RECT 0.048 981.504 138.635 981.6 ;
      RECT 0.048 982.272 138.635 982.368 ;
      RECT 0.048 983.04 138.635 983.136 ;
      RECT 0.048 983.808 138.635 983.904 ;
      RECT 0.048 984.576 138.635 984.672 ;
      RECT 0.048 985.344 138.635 985.44 ;
      RECT 0.048 986.112 138.635 986.208 ;
      RECT 0.048 986.88 138.635 986.976 ;
      RECT 0.048 987.648 138.635 987.744 ;
      RECT 0.048 988.416 138.635 988.512 ;
      RECT 0.048 989.184 138.635 989.28 ;
      RECT 0.048 989.952 138.635 990.048 ;
      RECT 0.048 990.72 138.635 990.816 ;
      RECT 0.048 991.488 138.635 991.584 ;
      RECT 0.048 992.256 138.635 992.352 ;
      RECT 0.048 993.024 138.635 993.12 ;
      RECT 0.048 993.792 138.635 993.888 ;
      RECT 0.048 994.56 138.635 994.656 ;
      RECT 0.048 995.328 138.635 995.424 ;
      RECT 0.048 996.096 138.635 996.192 ;
      RECT 0.048 996.864 138.635 996.96 ;
      RECT 0.048 997.632 138.635 997.728 ;
      RECT 0.048 998.4 138.635 998.496 ;
      RECT 0.048 999.168 138.635 999.264 ;
      RECT 0.048 999.936 138.635 1000.032 ;
      RECT 0.048 1000.704 138.635 1000.8 ;
      RECT 0.048 1001.472 138.635 1001.568 ;
      RECT 0.048 1002.24 138.635 1002.336 ;
      RECT 0.048 1003.008 138.635 1003.104 ;
      RECT 0.048 1003.776 138.635 1003.872 ;
      RECT 0.048 1004.544 138.635 1004.64 ;
      RECT 0.048 1005.312 138.635 1005.408 ;
      RECT 0.048 1006.08 138.635 1006.176 ;
      RECT 0.048 1006.848 138.635 1006.944 ;
      RECT 0.048 1007.616 138.635 1007.712 ;
      RECT 0.048 1008.384 138.635 1008.48 ;
      RECT 0.048 1009.152 138.635 1009.248 ;
      RECT 0.048 1009.92 138.635 1010.016 ;
      RECT 0.048 1010.688 138.635 1010.784 ;
      RECT 0.048 1011.456 138.635 1011.552 ;
      RECT 0.048 1012.224 138.635 1012.32 ;
      RECT 0.048 1012.992 138.635 1013.088 ;
      RECT 0.048 1013.76 138.635 1013.856 ;
      RECT 0.048 1014.528 138.635 1014.624 ;
      RECT 0.048 1015.296 138.635 1015.392 ;
      RECT 0.048 1016.064 138.635 1016.16 ;
      RECT 0.048 1016.832 138.635 1016.928 ;
      RECT 0.048 1017.6 138.635 1017.696 ;
      RECT 0.048 1018.368 138.635 1018.464 ;
      RECT 0.048 1019.136 138.635 1019.232 ;
      RECT 0.048 1019.904 138.635 1020 ;
      RECT 0.048 1020.672 138.635 1020.768 ;
      RECT 0.048 1021.44 138.635 1021.536 ;
      RECT 0.048 1022.208 138.635 1022.304 ;
      RECT 0.048 1022.976 138.635 1023.072 ;
      RECT 0.048 1023.744 138.635 1023.84 ;
      RECT 0.048 1024.512 138.635 1024.608 ;
      RECT 0.048 1025.28 138.635 1025.376 ;
      RECT 0.048 1026.048 138.635 1026.144 ;
      RECT 0.048 1026.816 138.635 1026.912 ;
      RECT 0.048 1027.584 138.635 1027.68 ;
      RECT 0.048 1028.352 138.635 1028.448 ;
      RECT 0.048 1029.12 138.635 1029.216 ;
      RECT 0.048 1029.888 138.635 1029.984 ;
      RECT 0.048 1030.656 138.635 1030.752 ;
      RECT 0.048 1031.424 138.635 1031.52 ;
      RECT 0.048 1032.192 138.635 1032.288 ;
      RECT 0.048 1032.96 138.635 1033.056 ;
      RECT 0.048 1033.728 138.635 1033.824 ;
      RECT 0.048 1034.496 138.635 1034.592 ;
      RECT 0.048 1035.264 138.635 1035.36 ;
      RECT 0.048 1036.032 138.635 1036.128 ;
      RECT 0.048 1036.8 138.635 1036.896 ;
      RECT 0.048 1037.568 138.635 1037.664 ;
      RECT 0.048 1038.336 138.635 1038.432 ;
      RECT 0.048 1039.104 138.635 1039.2 ;
      RECT 0.048 1039.872 138.635 1039.968 ;
      RECT 0.048 1040.64 138.635 1040.736 ;
      RECT 0.048 1041.408 138.635 1041.504 ;
      RECT 0.048 1042.176 138.635 1042.272 ;
      RECT 0.048 1042.944 138.635 1043.04 ;
      RECT 0.048 1043.712 138.635 1043.808 ;
      RECT 0.048 1044.48 138.635 1044.576 ;
      RECT 0.048 1045.248 138.635 1045.344 ;
      RECT 0.048 1046.016 138.635 1046.112 ;
      RECT 0.048 1046.784 138.635 1046.88 ;
      RECT 0.048 1047.552 138.635 1047.648 ;
      RECT 0.048 1048.32 138.635 1048.416 ;
      RECT 0.048 1049.088 138.635 1049.184 ;
      RECT 0.048 1049.856 138.635 1049.952 ;
      RECT 0.048 1050.624 138.635 1050.72 ;
      RECT 0.048 1051.392 138.635 1051.488 ;
      RECT 0.048 1052.16 138.635 1052.256 ;
      RECT 0.048 1052.928 138.635 1053.024 ;
      RECT 0.048 1053.696 138.635 1053.792 ;
      RECT 0.048 1054.464 138.635 1054.56 ;
      RECT 0.048 1055.232 138.635 1055.328 ;
      RECT 0.048 1056 138.635 1056.096 ;
      RECT 0.048 1056.768 138.635 1056.864 ;
      RECT 0.048 1057.536 138.635 1057.632 ;
      RECT 0.048 1058.304 138.635 1058.4 ;
      RECT 0.048 1059.072 138.635 1059.168 ;
      RECT 0.048 1059.84 138.635 1059.936 ;
      RECT 0.048 1060.608 138.635 1060.704 ;
      RECT 0.048 1061.376 138.635 1061.472 ;
      RECT 0.048 1062.144 138.635 1062.24 ;
      RECT 0.048 1062.912 138.635 1063.008 ;
      RECT 0.048 1063.68 138.635 1063.776 ;
      RECT 0.048 1064.448 138.635 1064.544 ;
      RECT 0.048 1065.216 138.635 1065.312 ;
      RECT 0.048 1065.984 138.635 1066.08 ;
      RECT 0.048 1066.752 138.635 1066.848 ;
      RECT 0.048 1067.52 138.635 1067.616 ;
      RECT 0.048 1068.288 138.635 1068.384 ;
      RECT 0.048 1069.056 138.635 1069.152 ;
      RECT 0.048 1069.824 138.635 1069.92 ;
      RECT 0.048 1070.592 138.635 1070.688 ;
      RECT 0.048 1071.36 138.635 1071.456 ;
      RECT 0.048 1072.128 138.635 1072.224 ;
      RECT 0.048 1072.896 138.635 1072.992 ;
      RECT 0.048 1073.664 138.635 1073.76 ;
      RECT 0.048 1074.432 138.635 1074.528 ;
      RECT 0.048 1075.2 138.635 1075.296 ;
      RECT 0.048 1075.968 138.635 1076.064 ;
      RECT 0.048 1076.736 138.635 1076.832 ;
      RECT 0.048 1077.504 138.635 1077.6 ;
      RECT 0.048 1078.272 138.635 1078.368 ;
      RECT 0.048 1079.04 138.635 1079.136 ;
      RECT 0.048 1079.808 138.635 1079.904 ;
      RECT 0.048 1080.576 138.635 1080.672 ;
      RECT 0.048 1081.344 138.635 1081.44 ;
      RECT 0.048 1082.112 138.635 1082.208 ;
      RECT 0.048 1082.88 138.635 1082.976 ;
      RECT 0.048 1083.648 138.635 1083.744 ;
      RECT 0.048 1084.416 138.635 1084.512 ;
      RECT 0.048 1085.184 138.635 1085.28 ;
      RECT 0.048 1085.952 138.635 1086.048 ;
      RECT 0.048 1086.72 138.635 1086.816 ;
      RECT 0.048 1087.488 138.635 1087.584 ;
      RECT 0.048 1088.256 138.635 1088.352 ;
      RECT 0.048 1089.024 138.635 1089.12 ;
      RECT 0.048 1089.792 138.635 1089.888 ;
      RECT 0.048 1090.56 138.635 1090.656 ;
      RECT 0.048 1091.328 138.635 1091.424 ;
      RECT 0.048 1092.096 138.635 1092.192 ;
      RECT 0.048 1092.864 138.635 1092.96 ;
      RECT 0.048 1093.632 138.635 1093.728 ;
      RECT 0.048 1094.4 138.635 1094.496 ;
      RECT 0.048 1095.168 138.635 1095.264 ;
      RECT 0.048 1095.936 138.635 1096.032 ;
      RECT 0.048 1096.704 138.635 1096.8 ;
      RECT 0.048 1097.472 138.635 1097.568 ;
      RECT 0.048 1098.24 138.635 1098.336 ;
      RECT 0.048 1099.008 138.635 1099.104 ;
      RECT 0.048 1099.776 138.635 1099.872 ;
      RECT 0.048 1100.544 138.635 1100.64 ;
      RECT 0.048 1101.312 138.635 1101.408 ;
      RECT 0.048 1102.08 138.635 1102.176 ;
      RECT 0.048 1102.848 138.635 1102.944 ;
      RECT 0.048 1103.616 138.635 1103.712 ;
      RECT 0.048 1104.384 138.635 1104.48 ;
      RECT 0.048 1105.152 138.635 1105.248 ;
      RECT 0.048 1105.92 138.635 1106.016 ;
      RECT 0.048 1106.688 138.635 1106.784 ;
      RECT 0.048 1107.456 138.635 1107.552 ;
      RECT 0.048 1108.224 138.635 1108.32 ;
      RECT 0.048 1108.992 138.635 1109.088 ;
      RECT 0.048 1109.76 138.635 1109.856 ;
      RECT 0.048 1110.528 138.635 1110.624 ;
      RECT 0.048 1111.296 138.635 1111.392 ;
      RECT 0.048 1112.064 138.635 1112.16 ;
      RECT 0.048 1112.832 138.635 1112.928 ;
      RECT 0.048 1113.6 138.635 1113.696 ;
      RECT 0.048 1114.368 138.635 1114.464 ;
      RECT 0.048 1115.136 138.635 1115.232 ;
      RECT 0.048 1115.904 138.635 1116 ;
      RECT 0.048 1116.672 138.635 1116.768 ;
      RECT 0.048 1117.44 138.635 1117.536 ;
      RECT 0.048 1118.208 138.635 1118.304 ;
      RECT 0.048 1118.976 138.635 1119.072 ;
      RECT 0.048 1119.744 138.635 1119.84 ;
      RECT 0.048 1120.512 138.635 1120.608 ;
      RECT 0.048 1121.28 138.635 1121.376 ;
      RECT 0.048 1122.048 138.635 1122.144 ;
      RECT 0.048 1122.816 138.635 1122.912 ;
      RECT 0.048 1123.584 138.635 1123.68 ;
      RECT 0.048 1124.352 138.635 1124.448 ;
      RECT 0.048 1125.12 138.635 1125.216 ;
      RECT 0.048 1125.888 138.635 1125.984 ;
      RECT 0.048 1126.656 138.635 1126.752 ;
      RECT 0.048 1127.424 138.635 1127.52 ;
      RECT 0.048 1128.192 138.635 1128.288 ;
      RECT 0.048 1128.96 138.635 1129.056 ;
      RECT 0.048 1129.728 138.635 1129.824 ;
      RECT 0.048 1130.496 138.635 1130.592 ;
      RECT 0.048 1131.264 138.635 1131.36 ;
      RECT 0.048 1132.032 138.635 1132.128 ;
      RECT 0.048 1132.8 138.635 1132.896 ;
      RECT 0.048 1133.568 138.635 1133.664 ;
      RECT 0.048 1134.336 138.635 1134.432 ;
      RECT 0.048 1135.104 138.635 1135.2 ;
      RECT 0.048 1135.872 138.635 1135.968 ;
      RECT 0.048 1136.64 138.635 1136.736 ;
      RECT 0.048 1137.408 138.635 1137.504 ;
      RECT 0.048 1138.176 138.635 1138.272 ;
      RECT 0.048 1138.944 138.635 1139.04 ;
      RECT 0.048 1139.712 138.635 1139.808 ;
      RECT 0.048 1140.48 138.635 1140.576 ;
      RECT 0.048 1141.248 138.635 1141.344 ;
      RECT 0.048 1142.016 138.635 1142.112 ;
      RECT 0.048 1142.784 138.635 1142.88 ;
      RECT 0.048 1143.552 138.635 1143.648 ;
      RECT 0.048 1144.32 138.635 1144.416 ;
      RECT 0.048 1145.088 138.635 1145.184 ;
      RECT 0.048 1145.856 138.635 1145.952 ;
      RECT 0.048 1146.624 138.635 1146.72 ;
      RECT 0.048 1147.392 138.635 1147.488 ;
      RECT 0.048 1148.16 138.635 1148.256 ;
      RECT 0.048 1148.928 138.635 1149.024 ;
      RECT 0.048 1149.696 138.635 1149.792 ;
      RECT 0.048 1150.464 138.635 1150.56 ;
      RECT 0.048 1151.232 138.635 1151.328 ;
      RECT 0.048 1152 138.635 1152.096 ;
      RECT 0.048 1152.768 138.635 1152.864 ;
      RECT 0.048 1153.536 138.635 1153.632 ;
      RECT 0.048 1154.304 138.635 1154.4 ;
      RECT 0.048 1155.072 138.635 1155.168 ;
      RECT 0.048 1155.84 138.635 1155.936 ;
      RECT 0.048 1156.608 138.635 1156.704 ;
      RECT 0.048 1157.376 138.635 1157.472 ;
      RECT 0.048 1158.144 138.635 1158.24 ;
      RECT 0.048 1158.912 138.635 1159.008 ;
      RECT 0.048 1159.68 138.635 1159.776 ;
      RECT 0.048 1160.448 138.635 1160.544 ;
      RECT 0.048 1161.216 138.635 1161.312 ;
      RECT 0.048 1161.984 138.635 1162.08 ;
      RECT 0.048 1162.752 138.635 1162.848 ;
      RECT 0.048 1163.52 138.635 1163.616 ;
      RECT 0.048 1164.288 138.635 1164.384 ;
      RECT 0.048 1165.056 138.635 1165.152 ;
      RECT 0.048 1165.824 138.635 1165.92 ;
      RECT 0.048 1166.592 138.635 1166.688 ;
      RECT 0.048 1167.36 138.635 1167.456 ;
      RECT 0.048 1168.128 138.635 1168.224 ;
      RECT 0.048 1168.896 138.635 1168.992 ;
      RECT 0.048 1169.664 138.635 1169.76 ;
      RECT 0.048 1170.432 138.635 1170.528 ;
      RECT 0.048 1171.2 138.635 1171.296 ;
      RECT 0.048 1171.968 138.635 1172.064 ;
      RECT 0.048 1172.736 138.635 1172.832 ;
      RECT 0.048 1173.504 138.635 1173.6 ;
      RECT 0.048 1174.272 138.635 1174.368 ;
      RECT 0.048 1175.04 138.635 1175.136 ;
      RECT 0.048 1175.808 138.635 1175.904 ;
      RECT 0.048 1176.576 138.635 1176.672 ;
      RECT 0.048 1177.344 138.635 1177.44 ;
      RECT 0.048 1178.112 138.635 1178.208 ;
      RECT 0.048 1178.88 138.635 1178.976 ;
      RECT 0.048 1179.648 138.635 1179.744 ;
      RECT 0.048 1180.416 138.635 1180.512 ;
      RECT 0.048 1181.184 138.635 1181.28 ;
      RECT 0.048 1181.952 138.635 1182.048 ;
      RECT 0.048 1182.72 138.635 1182.816 ;
      RECT 0.048 1183.488 138.635 1183.584 ;
      RECT 0.048 1184.256 138.635 1184.352 ;
      RECT 0.048 1185.024 138.635 1185.12 ;
      RECT 0.048 1185.792 138.635 1185.888 ;
      RECT 0.048 1186.56 138.635 1186.656 ;
      RECT 0.048 1187.328 138.635 1187.424 ;
      RECT 0.048 1188.096 138.635 1188.192 ;
      RECT 0.048 1188.864 138.635 1188.96 ;
      RECT 0.048 1189.632 138.635 1189.728 ;
      RECT 0.048 1190.4 138.635 1190.496 ;
      RECT 0.048 1191.168 138.635 1191.264 ;
      RECT 0.048 1191.936 138.635 1192.032 ;
      RECT 0.048 1192.704 138.635 1192.8 ;
      RECT 0.048 1193.472 138.635 1193.568 ;
      RECT 0.048 1194.24 138.635 1194.336 ;
      RECT 0.048 1195.008 138.635 1195.104 ;
      RECT 0.048 1195.776 138.635 1195.872 ;
      RECT 0.048 1196.544 138.635 1196.64 ;
      RECT 0.048 1197.312 138.635 1197.408 ;
      RECT 0.048 1198.08 138.635 1198.176 ;
      RECT 0.048 1198.848 138.635 1198.944 ;
      RECT 0.048 1199.616 138.635 1199.712 ;
      RECT 0.048 1200.384 138.635 1200.48 ;
      RECT 0.048 1201.152 138.635 1201.248 ;
      RECT 0.048 1201.92 138.635 1202.016 ;
      RECT 0.048 1202.688 138.635 1202.784 ;
      RECT 0.048 1203.456 138.635 1203.552 ;
      RECT 0.048 1204.224 138.635 1204.32 ;
      RECT 0.048 1204.992 138.635 1205.088 ;
      RECT 0.048 1205.76 138.635 1205.856 ;
      RECT 0.048 1206.528 138.635 1206.624 ;
      RECT 0.048 1207.296 138.635 1207.392 ;
      RECT 0.048 1208.064 138.635 1208.16 ;
      RECT 0.048 1208.832 138.635 1208.928 ;
      RECT 0.048 1209.6 138.635 1209.696 ;
      RECT 0.048 1210.368 138.635 1210.464 ;
      RECT 0.048 1211.136 138.635 1211.232 ;
      RECT 0.048 1211.904 138.635 1212 ;
      RECT 0.048 1212.672 138.635 1212.768 ;
      RECT 0.048 1213.44 138.635 1213.536 ;
      RECT 0.048 1214.208 138.635 1214.304 ;
      RECT 0.048 1214.976 138.635 1215.072 ;
      RECT 0.048 1215.744 138.635 1215.84 ;
      RECT 0.048 1216.512 138.635 1216.608 ;
      RECT 0.048 1217.28 138.635 1217.376 ;
      RECT 0.048 1218.048 138.635 1218.144 ;
      RECT 0.048 1218.816 138.635 1218.912 ;
      RECT 0.048 1219.584 138.635 1219.68 ;
      RECT 0.048 1220.352 138.635 1220.448 ;
      RECT 0.048 1221.12 138.635 1221.216 ;
      RECT 0.048 1221.888 138.635 1221.984 ;
      RECT 0.048 1222.656 138.635 1222.752 ;
      RECT 0.048 1223.424 138.635 1223.52 ;
      RECT 0.048 1224.192 138.635 1224.288 ;
      RECT 0.048 1224.96 138.635 1225.056 ;
      RECT 0.048 1225.728 138.635 1225.824 ;
      RECT 0.048 1226.496 138.635 1226.592 ;
      RECT 0.048 1227.264 138.635 1227.36 ;
      RECT 0.048 1228.032 138.635 1228.128 ;
      RECT 0.048 1228.8 138.635 1228.896 ;
      RECT 0.048 1229.568 138.635 1229.664 ;
      RECT 0.048 1230.336 138.635 1230.432 ;
      RECT 0.048 1231.104 138.635 1231.2 ;
      RECT 0.048 1231.872 138.635 1231.968 ;
      RECT 0.048 1232.64 138.635 1232.736 ;
      RECT 0.048 1233.408 138.635 1233.504 ;
      RECT 0.048 1234.176 138.635 1234.272 ;
      RECT 0.048 1234.944 138.635 1235.04 ;
      RECT 0.048 1235.712 138.635 1235.808 ;
      RECT 0.048 1236.48 138.635 1236.576 ;
      RECT 0.048 1237.248 138.635 1237.344 ;
      RECT 0.048 1238.016 138.635 1238.112 ;
      RECT 0.048 1238.784 138.635 1238.88 ;
      RECT 0.048 1239.552 138.635 1239.648 ;
      RECT 0.048 1240.32 138.635 1240.416 ;
      RECT 0.048 1241.088 138.635 1241.184 ;
      RECT 0.048 1241.856 138.635 1241.952 ;
      RECT 0.048 1242.624 138.635 1242.72 ;
      RECT 0.048 1243.392 138.635 1243.488 ;
      RECT 0.048 1244.16 138.635 1244.256 ;
      RECT 0.048 1244.928 138.635 1245.024 ;
      RECT 0.048 1245.696 138.635 1245.792 ;
      RECT 0.048 1246.464 138.635 1246.56 ;
      RECT 0.048 1247.232 138.635 1247.328 ;
      RECT 0.048 1248 138.635 1248.096 ;
      RECT 0.048 1248.768 138.635 1248.864 ;
      RECT 0.048 1249.536 138.635 1249.632 ;
      RECT 0.048 1250.304 138.635 1250.4 ;
      RECT 0.048 1251.072 138.635 1251.168 ;
      RECT 0.048 1251.84 138.635 1251.936 ;
      RECT 0.048 1252.608 138.635 1252.704 ;
      RECT 0.048 1253.376 138.635 1253.472 ;
      RECT 0.048 1254.144 138.635 1254.24 ;
      RECT 0.048 1254.912 138.635 1255.008 ;
      RECT 0.048 1255.68 138.635 1255.776 ;
      RECT 0.048 1256.448 138.635 1256.544 ;
      RECT 0.048 1257.216 138.635 1257.312 ;
      RECT 0.048 1257.984 138.635 1258.08 ;
      RECT 0.048 1258.752 138.635 1258.848 ;
      RECT 0.048 1259.52 138.635 1259.616 ;
      RECT 0.048 1260.288 138.635 1260.384 ;
      RECT 0.048 1261.056 138.635 1261.152 ;
      RECT 0.048 1261.824 138.635 1261.92 ;
      RECT 0.048 1262.592 138.635 1262.688 ;
      RECT 0.048 1263.36 138.635 1263.456 ;
      RECT 0.048 1264.128 138.635 1264.224 ;
      RECT 0.048 1264.896 138.635 1264.992 ;
      RECT 0.048 1265.664 138.635 1265.76 ;
      RECT 0.048 1266.432 138.635 1266.528 ;
      RECT 0.048 1267.2 138.635 1267.296 ;
      RECT 0.048 1267.968 138.635 1268.064 ;
      RECT 0.048 1268.736 138.635 1268.832 ;
      RECT 0.048 1269.504 138.635 1269.6 ;
      RECT 0.048 1270.272 138.635 1270.368 ;
      RECT 0.048 1271.04 138.635 1271.136 ;
      RECT 0.048 1271.808 138.635 1271.904 ;
      RECT 0.048 1272.576 138.635 1272.672 ;
      RECT 0.048 1273.344 138.635 1273.44 ;
      RECT 0.048 1274.112 138.635 1274.208 ;
      RECT 0.048 1274.88 138.635 1274.976 ;
      RECT 0.048 1275.648 138.635 1275.744 ;
      RECT 0.048 1276.416 138.635 1276.512 ;
      RECT 0.048 1277.184 138.635 1277.28 ;
      RECT 0.048 1277.952 138.635 1278.048 ;
      RECT 0.048 1278.72 138.635 1278.816 ;
      RECT 0.048 1279.488 138.635 1279.584 ;
      RECT 0.048 1280.256 138.635 1280.352 ;
      RECT 0.048 1281.024 138.635 1281.12 ;
      RECT 0.048 1281.792 138.635 1281.888 ;
      RECT 0.048 1282.56 138.635 1282.656 ;
      RECT 0.048 1283.328 138.635 1283.424 ;
      RECT 0.048 1284.096 138.635 1284.192 ;
      RECT 0.048 1284.864 138.635 1284.96 ;
      RECT 0.048 1285.632 138.635 1285.728 ;
      RECT 0.048 1286.4 138.635 1286.496 ;
      RECT 0.048 1287.168 138.635 1287.264 ;
      RECT 0.048 1287.936 138.635 1288.032 ;
      RECT 0.048 1288.704 138.635 1288.8 ;
      RECT 0.048 1289.472 138.635 1289.568 ;
      RECT 0.048 1290.24 138.635 1290.336 ;
      RECT 0.048 1291.008 138.635 1291.104 ;
      RECT 0.048 1291.776 138.635 1291.872 ;
      RECT 0.048 1292.544 138.635 1292.64 ;
      RECT 0.048 1293.312 138.635 1293.408 ;
      RECT 0.048 1294.08 138.635 1294.176 ;
      RECT 0.048 1294.848 138.635 1294.944 ;
      RECT 0.048 1295.616 138.635 1295.712 ;
      RECT 0.048 1296.384 138.635 1296.48 ;
      RECT 0.048 1297.152 138.635 1297.248 ;
      RECT 0.048 1297.92 138.635 1298.016 ;
      RECT 0.048 1298.688 138.635 1298.784 ;
      RECT 0.048 1299.456 138.635 1299.552 ;
      RECT 0.048 1300.224 138.635 1300.32 ;
      RECT 0.048 1300.992 138.635 1301.088 ;
      RECT 0.048 1301.76 138.635 1301.856 ;
      RECT 0.048 1302.528 138.635 1302.624 ;
      RECT 0.048 1303.296 138.635 1303.392 ;
      RECT 0.048 1304.064 138.635 1304.16 ;
      RECT 0.048 1304.832 138.635 1304.928 ;
      RECT 0.048 1305.6 138.635 1305.696 ;
      RECT 0.048 1306.368 138.635 1306.464 ;
      RECT 0.048 1307.136 138.635 1307.232 ;
      RECT 0.048 1307.904 138.635 1308 ;
      RECT 0.048 1308.672 138.635 1308.768 ;
      RECT 0.048 1309.44 138.635 1309.536 ;
      RECT 0.048 1310.208 138.635 1310.304 ;
      RECT 0.048 1310.976 138.635 1311.072 ;
      RECT 0.048 1311.744 138.635 1311.84 ;
      RECT 0.048 1312.512 138.635 1312.608 ;
      RECT 0.048 1313.28 138.635 1313.376 ;
      RECT 0.048 1314.048 138.635 1314.144 ;
      RECT 0.048 1314.816 138.635 1314.912 ;
      RECT 0.048 1315.584 138.635 1315.68 ;
      RECT 0.048 1316.352 138.635 1316.448 ;
      RECT 0.048 1317.12 138.635 1317.216 ;
      RECT 0.048 1317.888 138.635 1317.984 ;
      RECT 0.048 1318.656 138.635 1318.752 ;
      RECT 0.048 1319.424 138.635 1319.52 ;
      RECT 0.048 1320.192 138.635 1320.288 ;
      RECT 0.048 1320.96 138.635 1321.056 ;
      RECT 0.048 1321.728 138.635 1321.824 ;
      RECT 0.048 1322.496 138.635 1322.592 ;
      RECT 0.048 1323.264 138.635 1323.36 ;
      RECT 0.048 1324.032 138.635 1324.128 ;
      RECT 0.048 1324.8 138.635 1324.896 ;
      RECT 0.048 1325.568 138.635 1325.664 ;
      RECT 0.048 1326.336 138.635 1326.432 ;
      RECT 0.048 1327.104 138.635 1327.2 ;
      RECT 0.048 1327.872 138.635 1327.968 ;
      RECT 0.048 1328.64 138.635 1328.736 ;
      RECT 0.048 1329.408 138.635 1329.504 ;
      RECT 0.048 1330.176 138.635 1330.272 ;
      RECT 0.048 1330.944 138.635 1331.04 ;
      RECT 0.048 1331.712 138.635 1331.808 ;
      RECT 0.048 1332.48 138.635 1332.576 ;
      RECT 0.048 1333.248 138.635 1333.344 ;
      RECT 0.048 1334.016 138.635 1334.112 ;
      RECT 0.048 1334.784 138.635 1334.88 ;
      RECT 0.048 1335.552 138.635 1335.648 ;
      RECT 0.048 1336.32 138.635 1336.416 ;
      RECT 0.048 1337.088 138.635 1337.184 ;
      RECT 0.048 1337.856 138.635 1337.952 ;
      RECT 0.048 1338.624 138.635 1338.72 ;
      RECT 0.048 1339.392 138.635 1339.488 ;
      RECT 0.048 1340.16 138.635 1340.256 ;
      RECT 0.048 1340.928 138.635 1341.024 ;
      RECT 0.048 1341.696 138.635 1341.792 ;
      RECT 0.048 1342.464 138.635 1342.56 ;
      RECT 0.048 1343.232 138.635 1343.328 ;
      RECT 0.048 1344 138.635 1344.096 ;
      RECT 0.048 1344.768 138.635 1344.864 ;
      RECT 0.048 1345.536 138.635 1345.632 ;
      RECT 0.048 1346.304 138.635 1346.4 ;
      RECT 0.048 1347.072 138.635 1347.168 ;
      RECT 0.048 1347.84 138.635 1347.936 ;
      RECT 0.048 1348.608 138.635 1348.704 ;
      RECT 0.048 1349.376 138.635 1349.472 ;
      RECT 0.048 1350.144 138.635 1350.24 ;
      RECT 0.048 1350.912 138.635 1351.008 ;
      RECT 0.048 1351.68 138.635 1351.776 ;
      RECT 0.048 1352.448 138.635 1352.544 ;
      RECT 0.048 1353.216 138.635 1353.312 ;
      RECT 0.048 1353.984 138.635 1354.08 ;
      RECT 0.048 1354.752 138.635 1354.848 ;
      RECT 0.048 1355.52 138.635 1355.616 ;
      RECT 0.048 1356.288 138.635 1356.384 ;
      RECT 0.048 1357.056 138.635 1357.152 ;
      RECT 0.048 1357.824 138.635 1357.92 ;
      RECT 0.048 1358.592 138.635 1358.688 ;
      RECT 0.048 1359.36 138.635 1359.456 ;
      RECT 0.048 1360.128 138.635 1360.224 ;
      RECT 0.048 1360.896 138.635 1360.992 ;
      RECT 0.048 1361.664 138.635 1361.76 ;
      RECT 0.048 1362.432 138.635 1362.528 ;
      RECT 0.048 1363.2 138.635 1363.296 ;
      RECT 0.048 1363.968 138.635 1364.064 ;
      RECT 0.048 1364.736 138.635 1364.832 ;
      RECT 0.048 1365.504 138.635 1365.6 ;
      RECT 0.048 1366.272 138.635 1366.368 ;
      RECT 0.048 1367.04 138.635 1367.136 ;
      RECT 0.048 1367.808 138.635 1367.904 ;
      RECT 0.048 1368.576 138.635 1368.672 ;
      RECT 0.048 1369.344 138.635 1369.44 ;
      RECT 0.048 1370.112 138.635 1370.208 ;
      RECT 0.048 1370.88 138.635 1370.976 ;
      RECT 0.048 1371.648 138.635 1371.744 ;
      RECT 0.048 1372.416 138.635 1372.512 ;
      RECT 0.048 1373.184 138.635 1373.28 ;
      RECT 0.048 1373.952 138.635 1374.048 ;
      RECT 0.048 1374.72 138.635 1374.816 ;
      RECT 0.048 1375.488 138.635 1375.584 ;
      RECT 0.048 1376.256 138.635 1376.352 ;
      RECT 0.048 1377.024 138.635 1377.12 ;
      RECT 0.048 1377.792 138.635 1377.888 ;
      RECT 0.048 1378.56 138.635 1378.656 ;
      RECT 0.048 1379.328 138.635 1379.424 ;
      RECT 0.048 1380.096 138.635 1380.192 ;
      RECT 0.048 1380.864 138.635 1380.96 ;
      RECT 0.048 1381.632 138.635 1381.728 ;
      RECT 0.048 1382.4 138.635 1382.496 ;
      RECT 0.048 1383.168 138.635 1383.264 ;
      RECT 0.048 1383.936 138.635 1384.032 ;
      RECT 0.048 1384.704 138.635 1384.8 ;
      RECT 0.048 1385.472 138.635 1385.568 ;
      RECT 0.048 1386.24 138.635 1386.336 ;
      RECT 0.048 1387.008 138.635 1387.104 ;
      RECT 0.048 1387.776 138.635 1387.872 ;
      RECT 0.048 1388.544 138.635 1388.64 ;
      RECT 0.048 1389.312 138.635 1389.408 ;
      RECT 0.048 1390.08 138.635 1390.176 ;
      RECT 0.048 1390.848 138.635 1390.944 ;
      RECT 0.048 1391.616 138.635 1391.712 ;
      RECT 0.048 1392.384 138.635 1392.48 ;
      RECT 0.048 1393.152 138.635 1393.248 ;
      RECT 0.048 1393.92 138.635 1394.016 ;
      RECT 0.048 1394.688 138.635 1394.784 ;
      RECT 0.048 1395.456 138.635 1395.552 ;
      RECT 0.048 1396.224 138.635 1396.32 ;
      RECT 0.048 1396.992 138.635 1397.088 ;
      RECT 0.048 1397.76 138.635 1397.856 ;
      RECT 0.048 1398.528 138.635 1398.624 ;
      RECT 0.048 1399.296 138.635 1399.392 ;
      RECT 0.048 1400.064 138.635 1400.16 ;
      RECT 0.048 1400.832 138.635 1400.928 ;
      RECT 0.048 1401.6 138.635 1401.696 ;
      RECT 0.048 1402.368 138.635 1402.464 ;
      RECT 0.048 1403.136 138.635 1403.232 ;
      RECT 0.048 1403.904 138.635 1404 ;
      RECT 0.048 1404.672 138.635 1404.768 ;
      RECT 0.048 1405.44 138.635 1405.536 ;
      RECT 0.048 1406.208 138.635 1406.304 ;
      RECT 0.048 1406.976 138.635 1407.072 ;
      RECT 0.048 1407.744 138.635 1407.84 ;
    END
  END VSS
  PIN VDD
    DIRECTION INOUT ;
    USE POWER ;
    PORT
      LAYER M4 ;
      RECT 0.048 0.384 138.635 0.48 ;
      RECT 0.048 1.152 138.635 1.248 ;
      RECT 0.048 1.92 138.635 2.016 ;
      RECT 0.048 2.688 138.635 2.784 ;
      RECT 0.048 3.456 138.635 3.552 ;
      RECT 0.048 4.224 138.635 4.32 ;
      RECT 0.048 4.992 138.635 5.088 ;
      RECT 0.048 5.76 138.635 5.856 ;
      RECT 0.048 6.528 138.635 6.624 ;
      RECT 0.048 7.296 138.635 7.392 ;
      RECT 0.048 8.064 138.635 8.16 ;
      RECT 0.048 8.832 138.635 8.928 ;
      RECT 0.048 9.6 138.635 9.696 ;
      RECT 0.048 10.368 138.635 10.464 ;
      RECT 0.048 11.136 138.635 11.232 ;
      RECT 0.048 11.904 138.635 12 ;
      RECT 0.048 12.672 138.635 12.768 ;
      RECT 0.048 13.44 138.635 13.536 ;
      RECT 0.048 14.208 138.635 14.304 ;
      RECT 0.048 14.976 138.635 15.072 ;
      RECT 0.048 15.744 138.635 15.84 ;
      RECT 0.048 16.512 138.635 16.608 ;
      RECT 0.048 17.28 138.635 17.376 ;
      RECT 0.048 18.048 138.635 18.144 ;
      RECT 0.048 18.816 138.635 18.912 ;
      RECT 0.048 19.584 138.635 19.68 ;
      RECT 0.048 20.352 138.635 20.448 ;
      RECT 0.048 21.12 138.635 21.216 ;
      RECT 0.048 21.888 138.635 21.984 ;
      RECT 0.048 22.656 138.635 22.752 ;
      RECT 0.048 23.424 138.635 23.52 ;
      RECT 0.048 24.192 138.635 24.288 ;
      RECT 0.048 24.96 138.635 25.056 ;
      RECT 0.048 25.728 138.635 25.824 ;
      RECT 0.048 26.496 138.635 26.592 ;
      RECT 0.048 27.264 138.635 27.36 ;
      RECT 0.048 28.032 138.635 28.128 ;
      RECT 0.048 28.8 138.635 28.896 ;
      RECT 0.048 29.568 138.635 29.664 ;
      RECT 0.048 30.336 138.635 30.432 ;
      RECT 0.048 31.104 138.635 31.2 ;
      RECT 0.048 31.872 138.635 31.968 ;
      RECT 0.048 32.64 138.635 32.736 ;
      RECT 0.048 33.408 138.635 33.504 ;
      RECT 0.048 34.176 138.635 34.272 ;
      RECT 0.048 34.944 138.635 35.04 ;
      RECT 0.048 35.712 138.635 35.808 ;
      RECT 0.048 36.48 138.635 36.576 ;
      RECT 0.048 37.248 138.635 37.344 ;
      RECT 0.048 38.016 138.635 38.112 ;
      RECT 0.048 38.784 138.635 38.88 ;
      RECT 0.048 39.552 138.635 39.648 ;
      RECT 0.048 40.32 138.635 40.416 ;
      RECT 0.048 41.088 138.635 41.184 ;
      RECT 0.048 41.856 138.635 41.952 ;
      RECT 0.048 42.624 138.635 42.72 ;
      RECT 0.048 43.392 138.635 43.488 ;
      RECT 0.048 44.16 138.635 44.256 ;
      RECT 0.048 44.928 138.635 45.024 ;
      RECT 0.048 45.696 138.635 45.792 ;
      RECT 0.048 46.464 138.635 46.56 ;
      RECT 0.048 47.232 138.635 47.328 ;
      RECT 0.048 48 138.635 48.096 ;
      RECT 0.048 48.768 138.635 48.864 ;
      RECT 0.048 49.536 138.635 49.632 ;
      RECT 0.048 50.304 138.635 50.4 ;
      RECT 0.048 51.072 138.635 51.168 ;
      RECT 0.048 51.84 138.635 51.936 ;
      RECT 0.048 52.608 138.635 52.704 ;
      RECT 0.048 53.376 138.635 53.472 ;
      RECT 0.048 54.144 138.635 54.24 ;
      RECT 0.048 54.912 138.635 55.008 ;
      RECT 0.048 55.68 138.635 55.776 ;
      RECT 0.048 56.448 138.635 56.544 ;
      RECT 0.048 57.216 138.635 57.312 ;
      RECT 0.048 57.984 138.635 58.08 ;
      RECT 0.048 58.752 138.635 58.848 ;
      RECT 0.048 59.52 138.635 59.616 ;
      RECT 0.048 60.288 138.635 60.384 ;
      RECT 0.048 61.056 138.635 61.152 ;
      RECT 0.048 61.824 138.635 61.92 ;
      RECT 0.048 62.592 138.635 62.688 ;
      RECT 0.048 63.36 138.635 63.456 ;
      RECT 0.048 64.128 138.635 64.224 ;
      RECT 0.048 64.896 138.635 64.992 ;
      RECT 0.048 65.664 138.635 65.76 ;
      RECT 0.048 66.432 138.635 66.528 ;
      RECT 0.048 67.2 138.635 67.296 ;
      RECT 0.048 67.968 138.635 68.064 ;
      RECT 0.048 68.736 138.635 68.832 ;
      RECT 0.048 69.504 138.635 69.6 ;
      RECT 0.048 70.272 138.635 70.368 ;
      RECT 0.048 71.04 138.635 71.136 ;
      RECT 0.048 71.808 138.635 71.904 ;
      RECT 0.048 72.576 138.635 72.672 ;
      RECT 0.048 73.344 138.635 73.44 ;
      RECT 0.048 74.112 138.635 74.208 ;
      RECT 0.048 74.88 138.635 74.976 ;
      RECT 0.048 75.648 138.635 75.744 ;
      RECT 0.048 76.416 138.635 76.512 ;
      RECT 0.048 77.184 138.635 77.28 ;
      RECT 0.048 77.952 138.635 78.048 ;
      RECT 0.048 78.72 138.635 78.816 ;
      RECT 0.048 79.488 138.635 79.584 ;
      RECT 0.048 80.256 138.635 80.352 ;
      RECT 0.048 81.024 138.635 81.12 ;
      RECT 0.048 81.792 138.635 81.888 ;
      RECT 0.048 82.56 138.635 82.656 ;
      RECT 0.048 83.328 138.635 83.424 ;
      RECT 0.048 84.096 138.635 84.192 ;
      RECT 0.048 84.864 138.635 84.96 ;
      RECT 0.048 85.632 138.635 85.728 ;
      RECT 0.048 86.4 138.635 86.496 ;
      RECT 0.048 87.168 138.635 87.264 ;
      RECT 0.048 87.936 138.635 88.032 ;
      RECT 0.048 88.704 138.635 88.8 ;
      RECT 0.048 89.472 138.635 89.568 ;
      RECT 0.048 90.24 138.635 90.336 ;
      RECT 0.048 91.008 138.635 91.104 ;
      RECT 0.048 91.776 138.635 91.872 ;
      RECT 0.048 92.544 138.635 92.64 ;
      RECT 0.048 93.312 138.635 93.408 ;
      RECT 0.048 94.08 138.635 94.176 ;
      RECT 0.048 94.848 138.635 94.944 ;
      RECT 0.048 95.616 138.635 95.712 ;
      RECT 0.048 96.384 138.635 96.48 ;
      RECT 0.048 97.152 138.635 97.248 ;
      RECT 0.048 97.92 138.635 98.016 ;
      RECT 0.048 98.688 138.635 98.784 ;
      RECT 0.048 99.456 138.635 99.552 ;
      RECT 0.048 100.224 138.635 100.32 ;
      RECT 0.048 100.992 138.635 101.088 ;
      RECT 0.048 101.76 138.635 101.856 ;
      RECT 0.048 102.528 138.635 102.624 ;
      RECT 0.048 103.296 138.635 103.392 ;
      RECT 0.048 104.064 138.635 104.16 ;
      RECT 0.048 104.832 138.635 104.928 ;
      RECT 0.048 105.6 138.635 105.696 ;
      RECT 0.048 106.368 138.635 106.464 ;
      RECT 0.048 107.136 138.635 107.232 ;
      RECT 0.048 107.904 138.635 108 ;
      RECT 0.048 108.672 138.635 108.768 ;
      RECT 0.048 109.44 138.635 109.536 ;
      RECT 0.048 110.208 138.635 110.304 ;
      RECT 0.048 110.976 138.635 111.072 ;
      RECT 0.048 111.744 138.635 111.84 ;
      RECT 0.048 112.512 138.635 112.608 ;
      RECT 0.048 113.28 138.635 113.376 ;
      RECT 0.048 114.048 138.635 114.144 ;
      RECT 0.048 114.816 138.635 114.912 ;
      RECT 0.048 115.584 138.635 115.68 ;
      RECT 0.048 116.352 138.635 116.448 ;
      RECT 0.048 117.12 138.635 117.216 ;
      RECT 0.048 117.888 138.635 117.984 ;
      RECT 0.048 118.656 138.635 118.752 ;
      RECT 0.048 119.424 138.635 119.52 ;
      RECT 0.048 120.192 138.635 120.288 ;
      RECT 0.048 120.96 138.635 121.056 ;
      RECT 0.048 121.728 138.635 121.824 ;
      RECT 0.048 122.496 138.635 122.592 ;
      RECT 0.048 123.264 138.635 123.36 ;
      RECT 0.048 124.032 138.635 124.128 ;
      RECT 0.048 124.8 138.635 124.896 ;
      RECT 0.048 125.568 138.635 125.664 ;
      RECT 0.048 126.336 138.635 126.432 ;
      RECT 0.048 127.104 138.635 127.2 ;
      RECT 0.048 127.872 138.635 127.968 ;
      RECT 0.048 128.64 138.635 128.736 ;
      RECT 0.048 129.408 138.635 129.504 ;
      RECT 0.048 130.176 138.635 130.272 ;
      RECT 0.048 130.944 138.635 131.04 ;
      RECT 0.048 131.712 138.635 131.808 ;
      RECT 0.048 132.48 138.635 132.576 ;
      RECT 0.048 133.248 138.635 133.344 ;
      RECT 0.048 134.016 138.635 134.112 ;
      RECT 0.048 134.784 138.635 134.88 ;
      RECT 0.048 135.552 138.635 135.648 ;
      RECT 0.048 136.32 138.635 136.416 ;
      RECT 0.048 137.088 138.635 137.184 ;
      RECT 0.048 137.856 138.635 137.952 ;
      RECT 0.048 138.624 138.635 138.72 ;
      RECT 0.048 139.392 138.635 139.488 ;
      RECT 0.048 140.16 138.635 140.256 ;
      RECT 0.048 140.928 138.635 141.024 ;
      RECT 0.048 141.696 138.635 141.792 ;
      RECT 0.048 142.464 138.635 142.56 ;
      RECT 0.048 143.232 138.635 143.328 ;
      RECT 0.048 144 138.635 144.096 ;
      RECT 0.048 144.768 138.635 144.864 ;
      RECT 0.048 145.536 138.635 145.632 ;
      RECT 0.048 146.304 138.635 146.4 ;
      RECT 0.048 147.072 138.635 147.168 ;
      RECT 0.048 147.84 138.635 147.936 ;
      RECT 0.048 148.608 138.635 148.704 ;
      RECT 0.048 149.376 138.635 149.472 ;
      RECT 0.048 150.144 138.635 150.24 ;
      RECT 0.048 150.912 138.635 151.008 ;
      RECT 0.048 151.68 138.635 151.776 ;
      RECT 0.048 152.448 138.635 152.544 ;
      RECT 0.048 153.216 138.635 153.312 ;
      RECT 0.048 153.984 138.635 154.08 ;
      RECT 0.048 154.752 138.635 154.848 ;
      RECT 0.048 155.52 138.635 155.616 ;
      RECT 0.048 156.288 138.635 156.384 ;
      RECT 0.048 157.056 138.635 157.152 ;
      RECT 0.048 157.824 138.635 157.92 ;
      RECT 0.048 158.592 138.635 158.688 ;
      RECT 0.048 159.36 138.635 159.456 ;
      RECT 0.048 160.128 138.635 160.224 ;
      RECT 0.048 160.896 138.635 160.992 ;
      RECT 0.048 161.664 138.635 161.76 ;
      RECT 0.048 162.432 138.635 162.528 ;
      RECT 0.048 163.2 138.635 163.296 ;
      RECT 0.048 163.968 138.635 164.064 ;
      RECT 0.048 164.736 138.635 164.832 ;
      RECT 0.048 165.504 138.635 165.6 ;
      RECT 0.048 166.272 138.635 166.368 ;
      RECT 0.048 167.04 138.635 167.136 ;
      RECT 0.048 167.808 138.635 167.904 ;
      RECT 0.048 168.576 138.635 168.672 ;
      RECT 0.048 169.344 138.635 169.44 ;
      RECT 0.048 170.112 138.635 170.208 ;
      RECT 0.048 170.88 138.635 170.976 ;
      RECT 0.048 171.648 138.635 171.744 ;
      RECT 0.048 172.416 138.635 172.512 ;
      RECT 0.048 173.184 138.635 173.28 ;
      RECT 0.048 173.952 138.635 174.048 ;
      RECT 0.048 174.72 138.635 174.816 ;
      RECT 0.048 175.488 138.635 175.584 ;
      RECT 0.048 176.256 138.635 176.352 ;
      RECT 0.048 177.024 138.635 177.12 ;
      RECT 0.048 177.792 138.635 177.888 ;
      RECT 0.048 178.56 138.635 178.656 ;
      RECT 0.048 179.328 138.635 179.424 ;
      RECT 0.048 180.096 138.635 180.192 ;
      RECT 0.048 180.864 138.635 180.96 ;
      RECT 0.048 181.632 138.635 181.728 ;
      RECT 0.048 182.4 138.635 182.496 ;
      RECT 0.048 183.168 138.635 183.264 ;
      RECT 0.048 183.936 138.635 184.032 ;
      RECT 0.048 184.704 138.635 184.8 ;
      RECT 0.048 185.472 138.635 185.568 ;
      RECT 0.048 186.24 138.635 186.336 ;
      RECT 0.048 187.008 138.635 187.104 ;
      RECT 0.048 187.776 138.635 187.872 ;
      RECT 0.048 188.544 138.635 188.64 ;
      RECT 0.048 189.312 138.635 189.408 ;
      RECT 0.048 190.08 138.635 190.176 ;
      RECT 0.048 190.848 138.635 190.944 ;
      RECT 0.048 191.616 138.635 191.712 ;
      RECT 0.048 192.384 138.635 192.48 ;
      RECT 0.048 193.152 138.635 193.248 ;
      RECT 0.048 193.92 138.635 194.016 ;
      RECT 0.048 194.688 138.635 194.784 ;
      RECT 0.048 195.456 138.635 195.552 ;
      RECT 0.048 196.224 138.635 196.32 ;
      RECT 0.048 196.992 138.635 197.088 ;
      RECT 0.048 197.76 138.635 197.856 ;
      RECT 0.048 198.528 138.635 198.624 ;
      RECT 0.048 199.296 138.635 199.392 ;
      RECT 0.048 200.064 138.635 200.16 ;
      RECT 0.048 200.832 138.635 200.928 ;
      RECT 0.048 201.6 138.635 201.696 ;
      RECT 0.048 202.368 138.635 202.464 ;
      RECT 0.048 203.136 138.635 203.232 ;
      RECT 0.048 203.904 138.635 204 ;
      RECT 0.048 204.672 138.635 204.768 ;
      RECT 0.048 205.44 138.635 205.536 ;
      RECT 0.048 206.208 138.635 206.304 ;
      RECT 0.048 206.976 138.635 207.072 ;
      RECT 0.048 207.744 138.635 207.84 ;
      RECT 0.048 208.512 138.635 208.608 ;
      RECT 0.048 209.28 138.635 209.376 ;
      RECT 0.048 210.048 138.635 210.144 ;
      RECT 0.048 210.816 138.635 210.912 ;
      RECT 0.048 211.584 138.635 211.68 ;
      RECT 0.048 212.352 138.635 212.448 ;
      RECT 0.048 213.12 138.635 213.216 ;
      RECT 0.048 213.888 138.635 213.984 ;
      RECT 0.048 214.656 138.635 214.752 ;
      RECT 0.048 215.424 138.635 215.52 ;
      RECT 0.048 216.192 138.635 216.288 ;
      RECT 0.048 216.96 138.635 217.056 ;
      RECT 0.048 217.728 138.635 217.824 ;
      RECT 0.048 218.496 138.635 218.592 ;
      RECT 0.048 219.264 138.635 219.36 ;
      RECT 0.048 220.032 138.635 220.128 ;
      RECT 0.048 220.8 138.635 220.896 ;
      RECT 0.048 221.568 138.635 221.664 ;
      RECT 0.048 222.336 138.635 222.432 ;
      RECT 0.048 223.104 138.635 223.2 ;
      RECT 0.048 223.872 138.635 223.968 ;
      RECT 0.048 224.64 138.635 224.736 ;
      RECT 0.048 225.408 138.635 225.504 ;
      RECT 0.048 226.176 138.635 226.272 ;
      RECT 0.048 226.944 138.635 227.04 ;
      RECT 0.048 227.712 138.635 227.808 ;
      RECT 0.048 228.48 138.635 228.576 ;
      RECT 0.048 229.248 138.635 229.344 ;
      RECT 0.048 230.016 138.635 230.112 ;
      RECT 0.048 230.784 138.635 230.88 ;
      RECT 0.048 231.552 138.635 231.648 ;
      RECT 0.048 232.32 138.635 232.416 ;
      RECT 0.048 233.088 138.635 233.184 ;
      RECT 0.048 233.856 138.635 233.952 ;
      RECT 0.048 234.624 138.635 234.72 ;
      RECT 0.048 235.392 138.635 235.488 ;
      RECT 0.048 236.16 138.635 236.256 ;
      RECT 0.048 236.928 138.635 237.024 ;
      RECT 0.048 237.696 138.635 237.792 ;
      RECT 0.048 238.464 138.635 238.56 ;
      RECT 0.048 239.232 138.635 239.328 ;
      RECT 0.048 240 138.635 240.096 ;
      RECT 0.048 240.768 138.635 240.864 ;
      RECT 0.048 241.536 138.635 241.632 ;
      RECT 0.048 242.304 138.635 242.4 ;
      RECT 0.048 243.072 138.635 243.168 ;
      RECT 0.048 243.84 138.635 243.936 ;
      RECT 0.048 244.608 138.635 244.704 ;
      RECT 0.048 245.376 138.635 245.472 ;
      RECT 0.048 246.144 138.635 246.24 ;
      RECT 0.048 246.912 138.635 247.008 ;
      RECT 0.048 247.68 138.635 247.776 ;
      RECT 0.048 248.448 138.635 248.544 ;
      RECT 0.048 249.216 138.635 249.312 ;
      RECT 0.048 249.984 138.635 250.08 ;
      RECT 0.048 250.752 138.635 250.848 ;
      RECT 0.048 251.52 138.635 251.616 ;
      RECT 0.048 252.288 138.635 252.384 ;
      RECT 0.048 253.056 138.635 253.152 ;
      RECT 0.048 253.824 138.635 253.92 ;
      RECT 0.048 254.592 138.635 254.688 ;
      RECT 0.048 255.36 138.635 255.456 ;
      RECT 0.048 256.128 138.635 256.224 ;
      RECT 0.048 256.896 138.635 256.992 ;
      RECT 0.048 257.664 138.635 257.76 ;
      RECT 0.048 258.432 138.635 258.528 ;
      RECT 0.048 259.2 138.635 259.296 ;
      RECT 0.048 259.968 138.635 260.064 ;
      RECT 0.048 260.736 138.635 260.832 ;
      RECT 0.048 261.504 138.635 261.6 ;
      RECT 0.048 262.272 138.635 262.368 ;
      RECT 0.048 263.04 138.635 263.136 ;
      RECT 0.048 263.808 138.635 263.904 ;
      RECT 0.048 264.576 138.635 264.672 ;
      RECT 0.048 265.344 138.635 265.44 ;
      RECT 0.048 266.112 138.635 266.208 ;
      RECT 0.048 266.88 138.635 266.976 ;
      RECT 0.048 267.648 138.635 267.744 ;
      RECT 0.048 268.416 138.635 268.512 ;
      RECT 0.048 269.184 138.635 269.28 ;
      RECT 0.048 269.952 138.635 270.048 ;
      RECT 0.048 270.72 138.635 270.816 ;
      RECT 0.048 271.488 138.635 271.584 ;
      RECT 0.048 272.256 138.635 272.352 ;
      RECT 0.048 273.024 138.635 273.12 ;
      RECT 0.048 273.792 138.635 273.888 ;
      RECT 0.048 274.56 138.635 274.656 ;
      RECT 0.048 275.328 138.635 275.424 ;
      RECT 0.048 276.096 138.635 276.192 ;
      RECT 0.048 276.864 138.635 276.96 ;
      RECT 0.048 277.632 138.635 277.728 ;
      RECT 0.048 278.4 138.635 278.496 ;
      RECT 0.048 279.168 138.635 279.264 ;
      RECT 0.048 279.936 138.635 280.032 ;
      RECT 0.048 280.704 138.635 280.8 ;
      RECT 0.048 281.472 138.635 281.568 ;
      RECT 0.048 282.24 138.635 282.336 ;
      RECT 0.048 283.008 138.635 283.104 ;
      RECT 0.048 283.776 138.635 283.872 ;
      RECT 0.048 284.544 138.635 284.64 ;
      RECT 0.048 285.312 138.635 285.408 ;
      RECT 0.048 286.08 138.635 286.176 ;
      RECT 0.048 286.848 138.635 286.944 ;
      RECT 0.048 287.616 138.635 287.712 ;
      RECT 0.048 288.384 138.635 288.48 ;
      RECT 0.048 289.152 138.635 289.248 ;
      RECT 0.048 289.92 138.635 290.016 ;
      RECT 0.048 290.688 138.635 290.784 ;
      RECT 0.048 291.456 138.635 291.552 ;
      RECT 0.048 292.224 138.635 292.32 ;
      RECT 0.048 292.992 138.635 293.088 ;
      RECT 0.048 293.76 138.635 293.856 ;
      RECT 0.048 294.528 138.635 294.624 ;
      RECT 0.048 295.296 138.635 295.392 ;
      RECT 0.048 296.064 138.635 296.16 ;
      RECT 0.048 296.832 138.635 296.928 ;
      RECT 0.048 297.6 138.635 297.696 ;
      RECT 0.048 298.368 138.635 298.464 ;
      RECT 0.048 299.136 138.635 299.232 ;
      RECT 0.048 299.904 138.635 300 ;
      RECT 0.048 300.672 138.635 300.768 ;
      RECT 0.048 301.44 138.635 301.536 ;
      RECT 0.048 302.208 138.635 302.304 ;
      RECT 0.048 302.976 138.635 303.072 ;
      RECT 0.048 303.744 138.635 303.84 ;
      RECT 0.048 304.512 138.635 304.608 ;
      RECT 0.048 305.28 138.635 305.376 ;
      RECT 0.048 306.048 138.635 306.144 ;
      RECT 0.048 306.816 138.635 306.912 ;
      RECT 0.048 307.584 138.635 307.68 ;
      RECT 0.048 308.352 138.635 308.448 ;
      RECT 0.048 309.12 138.635 309.216 ;
      RECT 0.048 309.888 138.635 309.984 ;
      RECT 0.048 310.656 138.635 310.752 ;
      RECT 0.048 311.424 138.635 311.52 ;
      RECT 0.048 312.192 138.635 312.288 ;
      RECT 0.048 312.96 138.635 313.056 ;
      RECT 0.048 313.728 138.635 313.824 ;
      RECT 0.048 314.496 138.635 314.592 ;
      RECT 0.048 315.264 138.635 315.36 ;
      RECT 0.048 316.032 138.635 316.128 ;
      RECT 0.048 316.8 138.635 316.896 ;
      RECT 0.048 317.568 138.635 317.664 ;
      RECT 0.048 318.336 138.635 318.432 ;
      RECT 0.048 319.104 138.635 319.2 ;
      RECT 0.048 319.872 138.635 319.968 ;
      RECT 0.048 320.64 138.635 320.736 ;
      RECT 0.048 321.408 138.635 321.504 ;
      RECT 0.048 322.176 138.635 322.272 ;
      RECT 0.048 322.944 138.635 323.04 ;
      RECT 0.048 323.712 138.635 323.808 ;
      RECT 0.048 324.48 138.635 324.576 ;
      RECT 0.048 325.248 138.635 325.344 ;
      RECT 0.048 326.016 138.635 326.112 ;
      RECT 0.048 326.784 138.635 326.88 ;
      RECT 0.048 327.552 138.635 327.648 ;
      RECT 0.048 328.32 138.635 328.416 ;
      RECT 0.048 329.088 138.635 329.184 ;
      RECT 0.048 329.856 138.635 329.952 ;
      RECT 0.048 330.624 138.635 330.72 ;
      RECT 0.048 331.392 138.635 331.488 ;
      RECT 0.048 332.16 138.635 332.256 ;
      RECT 0.048 332.928 138.635 333.024 ;
      RECT 0.048 333.696 138.635 333.792 ;
      RECT 0.048 334.464 138.635 334.56 ;
      RECT 0.048 335.232 138.635 335.328 ;
      RECT 0.048 336 138.635 336.096 ;
      RECT 0.048 336.768 138.635 336.864 ;
      RECT 0.048 337.536 138.635 337.632 ;
      RECT 0.048 338.304 138.635 338.4 ;
      RECT 0.048 339.072 138.635 339.168 ;
      RECT 0.048 339.84 138.635 339.936 ;
      RECT 0.048 340.608 138.635 340.704 ;
      RECT 0.048 341.376 138.635 341.472 ;
      RECT 0.048 342.144 138.635 342.24 ;
      RECT 0.048 342.912 138.635 343.008 ;
      RECT 0.048 343.68 138.635 343.776 ;
      RECT 0.048 344.448 138.635 344.544 ;
      RECT 0.048 345.216 138.635 345.312 ;
      RECT 0.048 345.984 138.635 346.08 ;
      RECT 0.048 346.752 138.635 346.848 ;
      RECT 0.048 347.52 138.635 347.616 ;
      RECT 0.048 348.288 138.635 348.384 ;
      RECT 0.048 349.056 138.635 349.152 ;
      RECT 0.048 349.824 138.635 349.92 ;
      RECT 0.048 350.592 138.635 350.688 ;
      RECT 0.048 351.36 138.635 351.456 ;
      RECT 0.048 352.128 138.635 352.224 ;
      RECT 0.048 352.896 138.635 352.992 ;
      RECT 0.048 353.664 138.635 353.76 ;
      RECT 0.048 354.432 138.635 354.528 ;
      RECT 0.048 355.2 138.635 355.296 ;
      RECT 0.048 355.968 138.635 356.064 ;
      RECT 0.048 356.736 138.635 356.832 ;
      RECT 0.048 357.504 138.635 357.6 ;
      RECT 0.048 358.272 138.635 358.368 ;
      RECT 0.048 359.04 138.635 359.136 ;
      RECT 0.048 359.808 138.635 359.904 ;
      RECT 0.048 360.576 138.635 360.672 ;
      RECT 0.048 361.344 138.635 361.44 ;
      RECT 0.048 362.112 138.635 362.208 ;
      RECT 0.048 362.88 138.635 362.976 ;
      RECT 0.048 363.648 138.635 363.744 ;
      RECT 0.048 364.416 138.635 364.512 ;
      RECT 0.048 365.184 138.635 365.28 ;
      RECT 0.048 365.952 138.635 366.048 ;
      RECT 0.048 366.72 138.635 366.816 ;
      RECT 0.048 367.488 138.635 367.584 ;
      RECT 0.048 368.256 138.635 368.352 ;
      RECT 0.048 369.024 138.635 369.12 ;
      RECT 0.048 369.792 138.635 369.888 ;
      RECT 0.048 370.56 138.635 370.656 ;
      RECT 0.048 371.328 138.635 371.424 ;
      RECT 0.048 372.096 138.635 372.192 ;
      RECT 0.048 372.864 138.635 372.96 ;
      RECT 0.048 373.632 138.635 373.728 ;
      RECT 0.048 374.4 138.635 374.496 ;
      RECT 0.048 375.168 138.635 375.264 ;
      RECT 0.048 375.936 138.635 376.032 ;
      RECT 0.048 376.704 138.635 376.8 ;
      RECT 0.048 377.472 138.635 377.568 ;
      RECT 0.048 378.24 138.635 378.336 ;
      RECT 0.048 379.008 138.635 379.104 ;
      RECT 0.048 379.776 138.635 379.872 ;
      RECT 0.048 380.544 138.635 380.64 ;
      RECT 0.048 381.312 138.635 381.408 ;
      RECT 0.048 382.08 138.635 382.176 ;
      RECT 0.048 382.848 138.635 382.944 ;
      RECT 0.048 383.616 138.635 383.712 ;
      RECT 0.048 384.384 138.635 384.48 ;
      RECT 0.048 385.152 138.635 385.248 ;
      RECT 0.048 385.92 138.635 386.016 ;
      RECT 0.048 386.688 138.635 386.784 ;
      RECT 0.048 387.456 138.635 387.552 ;
      RECT 0.048 388.224 138.635 388.32 ;
      RECT 0.048 388.992 138.635 389.088 ;
      RECT 0.048 389.76 138.635 389.856 ;
      RECT 0.048 390.528 138.635 390.624 ;
      RECT 0.048 391.296 138.635 391.392 ;
      RECT 0.048 392.064 138.635 392.16 ;
      RECT 0.048 392.832 138.635 392.928 ;
      RECT 0.048 393.6 138.635 393.696 ;
      RECT 0.048 394.368 138.635 394.464 ;
      RECT 0.048 395.136 138.635 395.232 ;
      RECT 0.048 395.904 138.635 396 ;
      RECT 0.048 396.672 138.635 396.768 ;
      RECT 0.048 397.44 138.635 397.536 ;
      RECT 0.048 398.208 138.635 398.304 ;
      RECT 0.048 398.976 138.635 399.072 ;
      RECT 0.048 399.744 138.635 399.84 ;
      RECT 0.048 400.512 138.635 400.608 ;
      RECT 0.048 401.28 138.635 401.376 ;
      RECT 0.048 402.048 138.635 402.144 ;
      RECT 0.048 402.816 138.635 402.912 ;
      RECT 0.048 403.584 138.635 403.68 ;
      RECT 0.048 404.352 138.635 404.448 ;
      RECT 0.048 405.12 138.635 405.216 ;
      RECT 0.048 405.888 138.635 405.984 ;
      RECT 0.048 406.656 138.635 406.752 ;
      RECT 0.048 407.424 138.635 407.52 ;
      RECT 0.048 408.192 138.635 408.288 ;
      RECT 0.048 408.96 138.635 409.056 ;
      RECT 0.048 409.728 138.635 409.824 ;
      RECT 0.048 410.496 138.635 410.592 ;
      RECT 0.048 411.264 138.635 411.36 ;
      RECT 0.048 412.032 138.635 412.128 ;
      RECT 0.048 412.8 138.635 412.896 ;
      RECT 0.048 413.568 138.635 413.664 ;
      RECT 0.048 414.336 138.635 414.432 ;
      RECT 0.048 415.104 138.635 415.2 ;
      RECT 0.048 415.872 138.635 415.968 ;
      RECT 0.048 416.64 138.635 416.736 ;
      RECT 0.048 417.408 138.635 417.504 ;
      RECT 0.048 418.176 138.635 418.272 ;
      RECT 0.048 418.944 138.635 419.04 ;
      RECT 0.048 419.712 138.635 419.808 ;
      RECT 0.048 420.48 138.635 420.576 ;
      RECT 0.048 421.248 138.635 421.344 ;
      RECT 0.048 422.016 138.635 422.112 ;
      RECT 0.048 422.784 138.635 422.88 ;
      RECT 0.048 423.552 138.635 423.648 ;
      RECT 0.048 424.32 138.635 424.416 ;
      RECT 0.048 425.088 138.635 425.184 ;
      RECT 0.048 425.856 138.635 425.952 ;
      RECT 0.048 426.624 138.635 426.72 ;
      RECT 0.048 427.392 138.635 427.488 ;
      RECT 0.048 428.16 138.635 428.256 ;
      RECT 0.048 428.928 138.635 429.024 ;
      RECT 0.048 429.696 138.635 429.792 ;
      RECT 0.048 430.464 138.635 430.56 ;
      RECT 0.048 431.232 138.635 431.328 ;
      RECT 0.048 432 138.635 432.096 ;
      RECT 0.048 432.768 138.635 432.864 ;
      RECT 0.048 433.536 138.635 433.632 ;
      RECT 0.048 434.304 138.635 434.4 ;
      RECT 0.048 435.072 138.635 435.168 ;
      RECT 0.048 435.84 138.635 435.936 ;
      RECT 0.048 436.608 138.635 436.704 ;
      RECT 0.048 437.376 138.635 437.472 ;
      RECT 0.048 438.144 138.635 438.24 ;
      RECT 0.048 438.912 138.635 439.008 ;
      RECT 0.048 439.68 138.635 439.776 ;
      RECT 0.048 440.448 138.635 440.544 ;
      RECT 0.048 441.216 138.635 441.312 ;
      RECT 0.048 441.984 138.635 442.08 ;
      RECT 0.048 442.752 138.635 442.848 ;
      RECT 0.048 443.52 138.635 443.616 ;
      RECT 0.048 444.288 138.635 444.384 ;
      RECT 0.048 445.056 138.635 445.152 ;
      RECT 0.048 445.824 138.635 445.92 ;
      RECT 0.048 446.592 138.635 446.688 ;
      RECT 0.048 447.36 138.635 447.456 ;
      RECT 0.048 448.128 138.635 448.224 ;
      RECT 0.048 448.896 138.635 448.992 ;
      RECT 0.048 449.664 138.635 449.76 ;
      RECT 0.048 450.432 138.635 450.528 ;
      RECT 0.048 451.2 138.635 451.296 ;
      RECT 0.048 451.968 138.635 452.064 ;
      RECT 0.048 452.736 138.635 452.832 ;
      RECT 0.048 453.504 138.635 453.6 ;
      RECT 0.048 454.272 138.635 454.368 ;
      RECT 0.048 455.04 138.635 455.136 ;
      RECT 0.048 455.808 138.635 455.904 ;
      RECT 0.048 456.576 138.635 456.672 ;
      RECT 0.048 457.344 138.635 457.44 ;
      RECT 0.048 458.112 138.635 458.208 ;
      RECT 0.048 458.88 138.635 458.976 ;
      RECT 0.048 459.648 138.635 459.744 ;
      RECT 0.048 460.416 138.635 460.512 ;
      RECT 0.048 461.184 138.635 461.28 ;
      RECT 0.048 461.952 138.635 462.048 ;
      RECT 0.048 462.72 138.635 462.816 ;
      RECT 0.048 463.488 138.635 463.584 ;
      RECT 0.048 464.256 138.635 464.352 ;
      RECT 0.048 465.024 138.635 465.12 ;
      RECT 0.048 465.792 138.635 465.888 ;
      RECT 0.048 466.56 138.635 466.656 ;
      RECT 0.048 467.328 138.635 467.424 ;
      RECT 0.048 468.096 138.635 468.192 ;
      RECT 0.048 468.864 138.635 468.96 ;
      RECT 0.048 469.632 138.635 469.728 ;
      RECT 0.048 470.4 138.635 470.496 ;
      RECT 0.048 471.168 138.635 471.264 ;
      RECT 0.048 471.936 138.635 472.032 ;
      RECT 0.048 472.704 138.635 472.8 ;
      RECT 0.048 473.472 138.635 473.568 ;
      RECT 0.048 474.24 138.635 474.336 ;
      RECT 0.048 475.008 138.635 475.104 ;
      RECT 0.048 475.776 138.635 475.872 ;
      RECT 0.048 476.544 138.635 476.64 ;
      RECT 0.048 477.312 138.635 477.408 ;
      RECT 0.048 478.08 138.635 478.176 ;
      RECT 0.048 478.848 138.635 478.944 ;
      RECT 0.048 479.616 138.635 479.712 ;
      RECT 0.048 480.384 138.635 480.48 ;
      RECT 0.048 481.152 138.635 481.248 ;
      RECT 0.048 481.92 138.635 482.016 ;
      RECT 0.048 482.688 138.635 482.784 ;
      RECT 0.048 483.456 138.635 483.552 ;
      RECT 0.048 484.224 138.635 484.32 ;
      RECT 0.048 484.992 138.635 485.088 ;
      RECT 0.048 485.76 138.635 485.856 ;
      RECT 0.048 486.528 138.635 486.624 ;
      RECT 0.048 487.296 138.635 487.392 ;
      RECT 0.048 488.064 138.635 488.16 ;
      RECT 0.048 488.832 138.635 488.928 ;
      RECT 0.048 489.6 138.635 489.696 ;
      RECT 0.048 490.368 138.635 490.464 ;
      RECT 0.048 491.136 138.635 491.232 ;
      RECT 0.048 491.904 138.635 492 ;
      RECT 0.048 492.672 138.635 492.768 ;
      RECT 0.048 493.44 138.635 493.536 ;
      RECT 0.048 494.208 138.635 494.304 ;
      RECT 0.048 494.976 138.635 495.072 ;
      RECT 0.048 495.744 138.635 495.84 ;
      RECT 0.048 496.512 138.635 496.608 ;
      RECT 0.048 497.28 138.635 497.376 ;
      RECT 0.048 498.048 138.635 498.144 ;
      RECT 0.048 498.816 138.635 498.912 ;
      RECT 0.048 499.584 138.635 499.68 ;
      RECT 0.048 500.352 138.635 500.448 ;
      RECT 0.048 501.12 138.635 501.216 ;
      RECT 0.048 501.888 138.635 501.984 ;
      RECT 0.048 502.656 138.635 502.752 ;
      RECT 0.048 503.424 138.635 503.52 ;
      RECT 0.048 504.192 138.635 504.288 ;
      RECT 0.048 504.96 138.635 505.056 ;
      RECT 0.048 505.728 138.635 505.824 ;
      RECT 0.048 506.496 138.635 506.592 ;
      RECT 0.048 507.264 138.635 507.36 ;
      RECT 0.048 508.032 138.635 508.128 ;
      RECT 0.048 508.8 138.635 508.896 ;
      RECT 0.048 509.568 138.635 509.664 ;
      RECT 0.048 510.336 138.635 510.432 ;
      RECT 0.048 511.104 138.635 511.2 ;
      RECT 0.048 511.872 138.635 511.968 ;
      RECT 0.048 512.64 138.635 512.736 ;
      RECT 0.048 513.408 138.635 513.504 ;
      RECT 0.048 514.176 138.635 514.272 ;
      RECT 0.048 514.944 138.635 515.04 ;
      RECT 0.048 515.712 138.635 515.808 ;
      RECT 0.048 516.48 138.635 516.576 ;
      RECT 0.048 517.248 138.635 517.344 ;
      RECT 0.048 518.016 138.635 518.112 ;
      RECT 0.048 518.784 138.635 518.88 ;
      RECT 0.048 519.552 138.635 519.648 ;
      RECT 0.048 520.32 138.635 520.416 ;
      RECT 0.048 521.088 138.635 521.184 ;
      RECT 0.048 521.856 138.635 521.952 ;
      RECT 0.048 522.624 138.635 522.72 ;
      RECT 0.048 523.392 138.635 523.488 ;
      RECT 0.048 524.16 138.635 524.256 ;
      RECT 0.048 524.928 138.635 525.024 ;
      RECT 0.048 525.696 138.635 525.792 ;
      RECT 0.048 526.464 138.635 526.56 ;
      RECT 0.048 527.232 138.635 527.328 ;
      RECT 0.048 528 138.635 528.096 ;
      RECT 0.048 528.768 138.635 528.864 ;
      RECT 0.048 529.536 138.635 529.632 ;
      RECT 0.048 530.304 138.635 530.4 ;
      RECT 0.048 531.072 138.635 531.168 ;
      RECT 0.048 531.84 138.635 531.936 ;
      RECT 0.048 532.608 138.635 532.704 ;
      RECT 0.048 533.376 138.635 533.472 ;
      RECT 0.048 534.144 138.635 534.24 ;
      RECT 0.048 534.912 138.635 535.008 ;
      RECT 0.048 535.68 138.635 535.776 ;
      RECT 0.048 536.448 138.635 536.544 ;
      RECT 0.048 537.216 138.635 537.312 ;
      RECT 0.048 537.984 138.635 538.08 ;
      RECT 0.048 538.752 138.635 538.848 ;
      RECT 0.048 539.52 138.635 539.616 ;
      RECT 0.048 540.288 138.635 540.384 ;
      RECT 0.048 541.056 138.635 541.152 ;
      RECT 0.048 541.824 138.635 541.92 ;
      RECT 0.048 542.592 138.635 542.688 ;
      RECT 0.048 543.36 138.635 543.456 ;
      RECT 0.048 544.128 138.635 544.224 ;
      RECT 0.048 544.896 138.635 544.992 ;
      RECT 0.048 545.664 138.635 545.76 ;
      RECT 0.048 546.432 138.635 546.528 ;
      RECT 0.048 547.2 138.635 547.296 ;
      RECT 0.048 547.968 138.635 548.064 ;
      RECT 0.048 548.736 138.635 548.832 ;
      RECT 0.048 549.504 138.635 549.6 ;
      RECT 0.048 550.272 138.635 550.368 ;
      RECT 0.048 551.04 138.635 551.136 ;
      RECT 0.048 551.808 138.635 551.904 ;
      RECT 0.048 552.576 138.635 552.672 ;
      RECT 0.048 553.344 138.635 553.44 ;
      RECT 0.048 554.112 138.635 554.208 ;
      RECT 0.048 554.88 138.635 554.976 ;
      RECT 0.048 555.648 138.635 555.744 ;
      RECT 0.048 556.416 138.635 556.512 ;
      RECT 0.048 557.184 138.635 557.28 ;
      RECT 0.048 557.952 138.635 558.048 ;
      RECT 0.048 558.72 138.635 558.816 ;
      RECT 0.048 559.488 138.635 559.584 ;
      RECT 0.048 560.256 138.635 560.352 ;
      RECT 0.048 561.024 138.635 561.12 ;
      RECT 0.048 561.792 138.635 561.888 ;
      RECT 0.048 562.56 138.635 562.656 ;
      RECT 0.048 563.328 138.635 563.424 ;
      RECT 0.048 564.096 138.635 564.192 ;
      RECT 0.048 564.864 138.635 564.96 ;
      RECT 0.048 565.632 138.635 565.728 ;
      RECT 0.048 566.4 138.635 566.496 ;
      RECT 0.048 567.168 138.635 567.264 ;
      RECT 0.048 567.936 138.635 568.032 ;
      RECT 0.048 568.704 138.635 568.8 ;
      RECT 0.048 569.472 138.635 569.568 ;
      RECT 0.048 570.24 138.635 570.336 ;
      RECT 0.048 571.008 138.635 571.104 ;
      RECT 0.048 571.776 138.635 571.872 ;
      RECT 0.048 572.544 138.635 572.64 ;
      RECT 0.048 573.312 138.635 573.408 ;
      RECT 0.048 574.08 138.635 574.176 ;
      RECT 0.048 574.848 138.635 574.944 ;
      RECT 0.048 575.616 138.635 575.712 ;
      RECT 0.048 576.384 138.635 576.48 ;
      RECT 0.048 577.152 138.635 577.248 ;
      RECT 0.048 577.92 138.635 578.016 ;
      RECT 0.048 578.688 138.635 578.784 ;
      RECT 0.048 579.456 138.635 579.552 ;
      RECT 0.048 580.224 138.635 580.32 ;
      RECT 0.048 580.992 138.635 581.088 ;
      RECT 0.048 581.76 138.635 581.856 ;
      RECT 0.048 582.528 138.635 582.624 ;
      RECT 0.048 583.296 138.635 583.392 ;
      RECT 0.048 584.064 138.635 584.16 ;
      RECT 0.048 584.832 138.635 584.928 ;
      RECT 0.048 585.6 138.635 585.696 ;
      RECT 0.048 586.368 138.635 586.464 ;
      RECT 0.048 587.136 138.635 587.232 ;
      RECT 0.048 587.904 138.635 588 ;
      RECT 0.048 588.672 138.635 588.768 ;
      RECT 0.048 589.44 138.635 589.536 ;
      RECT 0.048 590.208 138.635 590.304 ;
      RECT 0.048 590.976 138.635 591.072 ;
      RECT 0.048 591.744 138.635 591.84 ;
      RECT 0.048 592.512 138.635 592.608 ;
      RECT 0.048 593.28 138.635 593.376 ;
      RECT 0.048 594.048 138.635 594.144 ;
      RECT 0.048 594.816 138.635 594.912 ;
      RECT 0.048 595.584 138.635 595.68 ;
      RECT 0.048 596.352 138.635 596.448 ;
      RECT 0.048 597.12 138.635 597.216 ;
      RECT 0.048 597.888 138.635 597.984 ;
      RECT 0.048 598.656 138.635 598.752 ;
      RECT 0.048 599.424 138.635 599.52 ;
      RECT 0.048 600.192 138.635 600.288 ;
      RECT 0.048 600.96 138.635 601.056 ;
      RECT 0.048 601.728 138.635 601.824 ;
      RECT 0.048 602.496 138.635 602.592 ;
      RECT 0.048 603.264 138.635 603.36 ;
      RECT 0.048 604.032 138.635 604.128 ;
      RECT 0.048 604.8 138.635 604.896 ;
      RECT 0.048 605.568 138.635 605.664 ;
      RECT 0.048 606.336 138.635 606.432 ;
      RECT 0.048 607.104 138.635 607.2 ;
      RECT 0.048 607.872 138.635 607.968 ;
      RECT 0.048 608.64 138.635 608.736 ;
      RECT 0.048 609.408 138.635 609.504 ;
      RECT 0.048 610.176 138.635 610.272 ;
      RECT 0.048 610.944 138.635 611.04 ;
      RECT 0.048 611.712 138.635 611.808 ;
      RECT 0.048 612.48 138.635 612.576 ;
      RECT 0.048 613.248 138.635 613.344 ;
      RECT 0.048 614.016 138.635 614.112 ;
      RECT 0.048 614.784 138.635 614.88 ;
      RECT 0.048 615.552 138.635 615.648 ;
      RECT 0.048 616.32 138.635 616.416 ;
      RECT 0.048 617.088 138.635 617.184 ;
      RECT 0.048 617.856 138.635 617.952 ;
      RECT 0.048 618.624 138.635 618.72 ;
      RECT 0.048 619.392 138.635 619.488 ;
      RECT 0.048 620.16 138.635 620.256 ;
      RECT 0.048 620.928 138.635 621.024 ;
      RECT 0.048 621.696 138.635 621.792 ;
      RECT 0.048 622.464 138.635 622.56 ;
      RECT 0.048 623.232 138.635 623.328 ;
      RECT 0.048 624 138.635 624.096 ;
      RECT 0.048 624.768 138.635 624.864 ;
      RECT 0.048 625.536 138.635 625.632 ;
      RECT 0.048 626.304 138.635 626.4 ;
      RECT 0.048 627.072 138.635 627.168 ;
      RECT 0.048 627.84 138.635 627.936 ;
      RECT 0.048 628.608 138.635 628.704 ;
      RECT 0.048 629.376 138.635 629.472 ;
      RECT 0.048 630.144 138.635 630.24 ;
      RECT 0.048 630.912 138.635 631.008 ;
      RECT 0.048 631.68 138.635 631.776 ;
      RECT 0.048 632.448 138.635 632.544 ;
      RECT 0.048 633.216 138.635 633.312 ;
      RECT 0.048 633.984 138.635 634.08 ;
      RECT 0.048 634.752 138.635 634.848 ;
      RECT 0.048 635.52 138.635 635.616 ;
      RECT 0.048 636.288 138.635 636.384 ;
      RECT 0.048 637.056 138.635 637.152 ;
      RECT 0.048 637.824 138.635 637.92 ;
      RECT 0.048 638.592 138.635 638.688 ;
      RECT 0.048 639.36 138.635 639.456 ;
      RECT 0.048 640.128 138.635 640.224 ;
      RECT 0.048 640.896 138.635 640.992 ;
      RECT 0.048 641.664 138.635 641.76 ;
      RECT 0.048 642.432 138.635 642.528 ;
      RECT 0.048 643.2 138.635 643.296 ;
      RECT 0.048 643.968 138.635 644.064 ;
      RECT 0.048 644.736 138.635 644.832 ;
      RECT 0.048 645.504 138.635 645.6 ;
      RECT 0.048 646.272 138.635 646.368 ;
      RECT 0.048 647.04 138.635 647.136 ;
      RECT 0.048 647.808 138.635 647.904 ;
      RECT 0.048 648.576 138.635 648.672 ;
      RECT 0.048 649.344 138.635 649.44 ;
      RECT 0.048 650.112 138.635 650.208 ;
      RECT 0.048 650.88 138.635 650.976 ;
      RECT 0.048 651.648 138.635 651.744 ;
      RECT 0.048 652.416 138.635 652.512 ;
      RECT 0.048 653.184 138.635 653.28 ;
      RECT 0.048 653.952 138.635 654.048 ;
      RECT 0.048 654.72 138.635 654.816 ;
      RECT 0.048 655.488 138.635 655.584 ;
      RECT 0.048 656.256 138.635 656.352 ;
      RECT 0.048 657.024 138.635 657.12 ;
      RECT 0.048 657.792 138.635 657.888 ;
      RECT 0.048 658.56 138.635 658.656 ;
      RECT 0.048 659.328 138.635 659.424 ;
      RECT 0.048 660.096 138.635 660.192 ;
      RECT 0.048 660.864 138.635 660.96 ;
      RECT 0.048 661.632 138.635 661.728 ;
      RECT 0.048 662.4 138.635 662.496 ;
      RECT 0.048 663.168 138.635 663.264 ;
      RECT 0.048 663.936 138.635 664.032 ;
      RECT 0.048 664.704 138.635 664.8 ;
      RECT 0.048 665.472 138.635 665.568 ;
      RECT 0.048 666.24 138.635 666.336 ;
      RECT 0.048 667.008 138.635 667.104 ;
      RECT 0.048 667.776 138.635 667.872 ;
      RECT 0.048 668.544 138.635 668.64 ;
      RECT 0.048 669.312 138.635 669.408 ;
      RECT 0.048 670.08 138.635 670.176 ;
      RECT 0.048 670.848 138.635 670.944 ;
      RECT 0.048 671.616 138.635 671.712 ;
      RECT 0.048 672.384 138.635 672.48 ;
      RECT 0.048 673.152 138.635 673.248 ;
      RECT 0.048 673.92 138.635 674.016 ;
      RECT 0.048 674.688 138.635 674.784 ;
      RECT 0.048 675.456 138.635 675.552 ;
      RECT 0.048 676.224 138.635 676.32 ;
      RECT 0.048 676.992 138.635 677.088 ;
      RECT 0.048 677.76 138.635 677.856 ;
      RECT 0.048 678.528 138.635 678.624 ;
      RECT 0.048 679.296 138.635 679.392 ;
      RECT 0.048 680.064 138.635 680.16 ;
      RECT 0.048 680.832 138.635 680.928 ;
      RECT 0.048 681.6 138.635 681.696 ;
      RECT 0.048 682.368 138.635 682.464 ;
      RECT 0.048 683.136 138.635 683.232 ;
      RECT 0.048 683.904 138.635 684 ;
      RECT 0.048 684.672 138.635 684.768 ;
      RECT 0.048 685.44 138.635 685.536 ;
      RECT 0.048 686.208 138.635 686.304 ;
      RECT 0.048 686.976 138.635 687.072 ;
      RECT 0.048 687.744 138.635 687.84 ;
      RECT 0.048 688.512 138.635 688.608 ;
      RECT 0.048 689.28 138.635 689.376 ;
      RECT 0.048 690.048 138.635 690.144 ;
      RECT 0.048 690.816 138.635 690.912 ;
      RECT 0.048 691.584 138.635 691.68 ;
      RECT 0.048 692.352 138.635 692.448 ;
      RECT 0.048 693.12 138.635 693.216 ;
      RECT 0.048 693.888 138.635 693.984 ;
      RECT 0.048 694.656 138.635 694.752 ;
      RECT 0.048 695.424 138.635 695.52 ;
      RECT 0.048 696.192 138.635 696.288 ;
      RECT 0.048 696.96 138.635 697.056 ;
      RECT 0.048 697.728 138.635 697.824 ;
      RECT 0.048 698.496 138.635 698.592 ;
      RECT 0.048 699.264 138.635 699.36 ;
      RECT 0.048 700.032 138.635 700.128 ;
      RECT 0.048 700.8 138.635 700.896 ;
      RECT 0.048 701.568 138.635 701.664 ;
      RECT 0.048 702.336 138.635 702.432 ;
      RECT 0.048 703.104 138.635 703.2 ;
      RECT 0.048 703.872 138.635 703.968 ;
      RECT 0.048 704.64 138.635 704.736 ;
      RECT 0.048 705.408 138.635 705.504 ;
      RECT 0.048 706.176 138.635 706.272 ;
      RECT 0.048 706.944 138.635 707.04 ;
      RECT 0.048 707.712 138.635 707.808 ;
      RECT 0.048 708.48 138.635 708.576 ;
      RECT 0.048 709.248 138.635 709.344 ;
      RECT 0.048 710.016 138.635 710.112 ;
      RECT 0.048 710.784 138.635 710.88 ;
      RECT 0.048 711.552 138.635 711.648 ;
      RECT 0.048 712.32 138.635 712.416 ;
      RECT 0.048 713.088 138.635 713.184 ;
      RECT 0.048 713.856 138.635 713.952 ;
      RECT 0.048 714.624 138.635 714.72 ;
      RECT 0.048 715.392 138.635 715.488 ;
      RECT 0.048 716.16 138.635 716.256 ;
      RECT 0.048 716.928 138.635 717.024 ;
      RECT 0.048 717.696 138.635 717.792 ;
      RECT 0.048 718.464 138.635 718.56 ;
      RECT 0.048 719.232 138.635 719.328 ;
      RECT 0.048 720 138.635 720.096 ;
      RECT 0.048 720.768 138.635 720.864 ;
      RECT 0.048 721.536 138.635 721.632 ;
      RECT 0.048 722.304 138.635 722.4 ;
      RECT 0.048 723.072 138.635 723.168 ;
      RECT 0.048 723.84 138.635 723.936 ;
      RECT 0.048 724.608 138.635 724.704 ;
      RECT 0.048 725.376 138.635 725.472 ;
      RECT 0.048 726.144 138.635 726.24 ;
      RECT 0.048 726.912 138.635 727.008 ;
      RECT 0.048 727.68 138.635 727.776 ;
      RECT 0.048 728.448 138.635 728.544 ;
      RECT 0.048 729.216 138.635 729.312 ;
      RECT 0.048 729.984 138.635 730.08 ;
      RECT 0.048 730.752 138.635 730.848 ;
      RECT 0.048 731.52 138.635 731.616 ;
      RECT 0.048 732.288 138.635 732.384 ;
      RECT 0.048 733.056 138.635 733.152 ;
      RECT 0.048 733.824 138.635 733.92 ;
      RECT 0.048 734.592 138.635 734.688 ;
      RECT 0.048 735.36 138.635 735.456 ;
      RECT 0.048 736.128 138.635 736.224 ;
      RECT 0.048 736.896 138.635 736.992 ;
      RECT 0.048 737.664 138.635 737.76 ;
      RECT 0.048 738.432 138.635 738.528 ;
      RECT 0.048 739.2 138.635 739.296 ;
      RECT 0.048 739.968 138.635 740.064 ;
      RECT 0.048 740.736 138.635 740.832 ;
      RECT 0.048 741.504 138.635 741.6 ;
      RECT 0.048 742.272 138.635 742.368 ;
      RECT 0.048 743.04 138.635 743.136 ;
      RECT 0.048 743.808 138.635 743.904 ;
      RECT 0.048 744.576 138.635 744.672 ;
      RECT 0.048 745.344 138.635 745.44 ;
      RECT 0.048 746.112 138.635 746.208 ;
      RECT 0.048 746.88 138.635 746.976 ;
      RECT 0.048 747.648 138.635 747.744 ;
      RECT 0.048 748.416 138.635 748.512 ;
      RECT 0.048 749.184 138.635 749.28 ;
      RECT 0.048 749.952 138.635 750.048 ;
      RECT 0.048 750.72 138.635 750.816 ;
      RECT 0.048 751.488 138.635 751.584 ;
      RECT 0.048 752.256 138.635 752.352 ;
      RECT 0.048 753.024 138.635 753.12 ;
      RECT 0.048 753.792 138.635 753.888 ;
      RECT 0.048 754.56 138.635 754.656 ;
      RECT 0.048 755.328 138.635 755.424 ;
      RECT 0.048 756.096 138.635 756.192 ;
      RECT 0.048 756.864 138.635 756.96 ;
      RECT 0.048 757.632 138.635 757.728 ;
      RECT 0.048 758.4 138.635 758.496 ;
      RECT 0.048 759.168 138.635 759.264 ;
      RECT 0.048 759.936 138.635 760.032 ;
      RECT 0.048 760.704 138.635 760.8 ;
      RECT 0.048 761.472 138.635 761.568 ;
      RECT 0.048 762.24 138.635 762.336 ;
      RECT 0.048 763.008 138.635 763.104 ;
      RECT 0.048 763.776 138.635 763.872 ;
      RECT 0.048 764.544 138.635 764.64 ;
      RECT 0.048 765.312 138.635 765.408 ;
      RECT 0.048 766.08 138.635 766.176 ;
      RECT 0.048 766.848 138.635 766.944 ;
      RECT 0.048 767.616 138.635 767.712 ;
      RECT 0.048 768.384 138.635 768.48 ;
      RECT 0.048 769.152 138.635 769.248 ;
      RECT 0.048 769.92 138.635 770.016 ;
      RECT 0.048 770.688 138.635 770.784 ;
      RECT 0.048 771.456 138.635 771.552 ;
      RECT 0.048 772.224 138.635 772.32 ;
      RECT 0.048 772.992 138.635 773.088 ;
      RECT 0.048 773.76 138.635 773.856 ;
      RECT 0.048 774.528 138.635 774.624 ;
      RECT 0.048 775.296 138.635 775.392 ;
      RECT 0.048 776.064 138.635 776.16 ;
      RECT 0.048 776.832 138.635 776.928 ;
      RECT 0.048 777.6 138.635 777.696 ;
      RECT 0.048 778.368 138.635 778.464 ;
      RECT 0.048 779.136 138.635 779.232 ;
      RECT 0.048 779.904 138.635 780 ;
      RECT 0.048 780.672 138.635 780.768 ;
      RECT 0.048 781.44 138.635 781.536 ;
      RECT 0.048 782.208 138.635 782.304 ;
      RECT 0.048 782.976 138.635 783.072 ;
      RECT 0.048 783.744 138.635 783.84 ;
      RECT 0.048 784.512 138.635 784.608 ;
      RECT 0.048 785.28 138.635 785.376 ;
      RECT 0.048 786.048 138.635 786.144 ;
      RECT 0.048 786.816 138.635 786.912 ;
      RECT 0.048 787.584 138.635 787.68 ;
      RECT 0.048 788.352 138.635 788.448 ;
      RECT 0.048 789.12 138.635 789.216 ;
      RECT 0.048 789.888 138.635 789.984 ;
      RECT 0.048 790.656 138.635 790.752 ;
      RECT 0.048 791.424 138.635 791.52 ;
      RECT 0.048 792.192 138.635 792.288 ;
      RECT 0.048 792.96 138.635 793.056 ;
      RECT 0.048 793.728 138.635 793.824 ;
      RECT 0.048 794.496 138.635 794.592 ;
      RECT 0.048 795.264 138.635 795.36 ;
      RECT 0.048 796.032 138.635 796.128 ;
      RECT 0.048 796.8 138.635 796.896 ;
      RECT 0.048 797.568 138.635 797.664 ;
      RECT 0.048 798.336 138.635 798.432 ;
      RECT 0.048 799.104 138.635 799.2 ;
      RECT 0.048 799.872 138.635 799.968 ;
      RECT 0.048 800.64 138.635 800.736 ;
      RECT 0.048 801.408 138.635 801.504 ;
      RECT 0.048 802.176 138.635 802.272 ;
      RECT 0.048 802.944 138.635 803.04 ;
      RECT 0.048 803.712 138.635 803.808 ;
      RECT 0.048 804.48 138.635 804.576 ;
      RECT 0.048 805.248 138.635 805.344 ;
      RECT 0.048 806.016 138.635 806.112 ;
      RECT 0.048 806.784 138.635 806.88 ;
      RECT 0.048 807.552 138.635 807.648 ;
      RECT 0.048 808.32 138.635 808.416 ;
      RECT 0.048 809.088 138.635 809.184 ;
      RECT 0.048 809.856 138.635 809.952 ;
      RECT 0.048 810.624 138.635 810.72 ;
      RECT 0.048 811.392 138.635 811.488 ;
      RECT 0.048 812.16 138.635 812.256 ;
      RECT 0.048 812.928 138.635 813.024 ;
      RECT 0.048 813.696 138.635 813.792 ;
      RECT 0.048 814.464 138.635 814.56 ;
      RECT 0.048 815.232 138.635 815.328 ;
      RECT 0.048 816 138.635 816.096 ;
      RECT 0.048 816.768 138.635 816.864 ;
      RECT 0.048 817.536 138.635 817.632 ;
      RECT 0.048 818.304 138.635 818.4 ;
      RECT 0.048 819.072 138.635 819.168 ;
      RECT 0.048 819.84 138.635 819.936 ;
      RECT 0.048 820.608 138.635 820.704 ;
      RECT 0.048 821.376 138.635 821.472 ;
      RECT 0.048 822.144 138.635 822.24 ;
      RECT 0.048 822.912 138.635 823.008 ;
      RECT 0.048 823.68 138.635 823.776 ;
      RECT 0.048 824.448 138.635 824.544 ;
      RECT 0.048 825.216 138.635 825.312 ;
      RECT 0.048 825.984 138.635 826.08 ;
      RECT 0.048 826.752 138.635 826.848 ;
      RECT 0.048 827.52 138.635 827.616 ;
      RECT 0.048 828.288 138.635 828.384 ;
      RECT 0.048 829.056 138.635 829.152 ;
      RECT 0.048 829.824 138.635 829.92 ;
      RECT 0.048 830.592 138.635 830.688 ;
      RECT 0.048 831.36 138.635 831.456 ;
      RECT 0.048 832.128 138.635 832.224 ;
      RECT 0.048 832.896 138.635 832.992 ;
      RECT 0.048 833.664 138.635 833.76 ;
      RECT 0.048 834.432 138.635 834.528 ;
      RECT 0.048 835.2 138.635 835.296 ;
      RECT 0.048 835.968 138.635 836.064 ;
      RECT 0.048 836.736 138.635 836.832 ;
      RECT 0.048 837.504 138.635 837.6 ;
      RECT 0.048 838.272 138.635 838.368 ;
      RECT 0.048 839.04 138.635 839.136 ;
      RECT 0.048 839.808 138.635 839.904 ;
      RECT 0.048 840.576 138.635 840.672 ;
      RECT 0.048 841.344 138.635 841.44 ;
      RECT 0.048 842.112 138.635 842.208 ;
      RECT 0.048 842.88 138.635 842.976 ;
      RECT 0.048 843.648 138.635 843.744 ;
      RECT 0.048 844.416 138.635 844.512 ;
      RECT 0.048 845.184 138.635 845.28 ;
      RECT 0.048 845.952 138.635 846.048 ;
      RECT 0.048 846.72 138.635 846.816 ;
      RECT 0.048 847.488 138.635 847.584 ;
      RECT 0.048 848.256 138.635 848.352 ;
      RECT 0.048 849.024 138.635 849.12 ;
      RECT 0.048 849.792 138.635 849.888 ;
      RECT 0.048 850.56 138.635 850.656 ;
      RECT 0.048 851.328 138.635 851.424 ;
      RECT 0.048 852.096 138.635 852.192 ;
      RECT 0.048 852.864 138.635 852.96 ;
      RECT 0.048 853.632 138.635 853.728 ;
      RECT 0.048 854.4 138.635 854.496 ;
      RECT 0.048 855.168 138.635 855.264 ;
      RECT 0.048 855.936 138.635 856.032 ;
      RECT 0.048 856.704 138.635 856.8 ;
      RECT 0.048 857.472 138.635 857.568 ;
      RECT 0.048 858.24 138.635 858.336 ;
      RECT 0.048 859.008 138.635 859.104 ;
      RECT 0.048 859.776 138.635 859.872 ;
      RECT 0.048 860.544 138.635 860.64 ;
      RECT 0.048 861.312 138.635 861.408 ;
      RECT 0.048 862.08 138.635 862.176 ;
      RECT 0.048 862.848 138.635 862.944 ;
      RECT 0.048 863.616 138.635 863.712 ;
      RECT 0.048 864.384 138.635 864.48 ;
      RECT 0.048 865.152 138.635 865.248 ;
      RECT 0.048 865.92 138.635 866.016 ;
      RECT 0.048 866.688 138.635 866.784 ;
      RECT 0.048 867.456 138.635 867.552 ;
      RECT 0.048 868.224 138.635 868.32 ;
      RECT 0.048 868.992 138.635 869.088 ;
      RECT 0.048 869.76 138.635 869.856 ;
      RECT 0.048 870.528 138.635 870.624 ;
      RECT 0.048 871.296 138.635 871.392 ;
      RECT 0.048 872.064 138.635 872.16 ;
      RECT 0.048 872.832 138.635 872.928 ;
      RECT 0.048 873.6 138.635 873.696 ;
      RECT 0.048 874.368 138.635 874.464 ;
      RECT 0.048 875.136 138.635 875.232 ;
      RECT 0.048 875.904 138.635 876 ;
      RECT 0.048 876.672 138.635 876.768 ;
      RECT 0.048 877.44 138.635 877.536 ;
      RECT 0.048 878.208 138.635 878.304 ;
      RECT 0.048 878.976 138.635 879.072 ;
      RECT 0.048 879.744 138.635 879.84 ;
      RECT 0.048 880.512 138.635 880.608 ;
      RECT 0.048 881.28 138.635 881.376 ;
      RECT 0.048 882.048 138.635 882.144 ;
      RECT 0.048 882.816 138.635 882.912 ;
      RECT 0.048 883.584 138.635 883.68 ;
      RECT 0.048 884.352 138.635 884.448 ;
      RECT 0.048 885.12 138.635 885.216 ;
      RECT 0.048 885.888 138.635 885.984 ;
      RECT 0.048 886.656 138.635 886.752 ;
      RECT 0.048 887.424 138.635 887.52 ;
      RECT 0.048 888.192 138.635 888.288 ;
      RECT 0.048 888.96 138.635 889.056 ;
      RECT 0.048 889.728 138.635 889.824 ;
      RECT 0.048 890.496 138.635 890.592 ;
      RECT 0.048 891.264 138.635 891.36 ;
      RECT 0.048 892.032 138.635 892.128 ;
      RECT 0.048 892.8 138.635 892.896 ;
      RECT 0.048 893.568 138.635 893.664 ;
      RECT 0.048 894.336 138.635 894.432 ;
      RECT 0.048 895.104 138.635 895.2 ;
      RECT 0.048 895.872 138.635 895.968 ;
      RECT 0.048 896.64 138.635 896.736 ;
      RECT 0.048 897.408 138.635 897.504 ;
      RECT 0.048 898.176 138.635 898.272 ;
      RECT 0.048 898.944 138.635 899.04 ;
      RECT 0.048 899.712 138.635 899.808 ;
      RECT 0.048 900.48 138.635 900.576 ;
      RECT 0.048 901.248 138.635 901.344 ;
      RECT 0.048 902.016 138.635 902.112 ;
      RECT 0.048 902.784 138.635 902.88 ;
      RECT 0.048 903.552 138.635 903.648 ;
      RECT 0.048 904.32 138.635 904.416 ;
      RECT 0.048 905.088 138.635 905.184 ;
      RECT 0.048 905.856 138.635 905.952 ;
      RECT 0.048 906.624 138.635 906.72 ;
      RECT 0.048 907.392 138.635 907.488 ;
      RECT 0.048 908.16 138.635 908.256 ;
      RECT 0.048 908.928 138.635 909.024 ;
      RECT 0.048 909.696 138.635 909.792 ;
      RECT 0.048 910.464 138.635 910.56 ;
      RECT 0.048 911.232 138.635 911.328 ;
      RECT 0.048 912 138.635 912.096 ;
      RECT 0.048 912.768 138.635 912.864 ;
      RECT 0.048 913.536 138.635 913.632 ;
      RECT 0.048 914.304 138.635 914.4 ;
      RECT 0.048 915.072 138.635 915.168 ;
      RECT 0.048 915.84 138.635 915.936 ;
      RECT 0.048 916.608 138.635 916.704 ;
      RECT 0.048 917.376 138.635 917.472 ;
      RECT 0.048 918.144 138.635 918.24 ;
      RECT 0.048 918.912 138.635 919.008 ;
      RECT 0.048 919.68 138.635 919.776 ;
      RECT 0.048 920.448 138.635 920.544 ;
      RECT 0.048 921.216 138.635 921.312 ;
      RECT 0.048 921.984 138.635 922.08 ;
      RECT 0.048 922.752 138.635 922.848 ;
      RECT 0.048 923.52 138.635 923.616 ;
      RECT 0.048 924.288 138.635 924.384 ;
      RECT 0.048 925.056 138.635 925.152 ;
      RECT 0.048 925.824 138.635 925.92 ;
      RECT 0.048 926.592 138.635 926.688 ;
      RECT 0.048 927.36 138.635 927.456 ;
      RECT 0.048 928.128 138.635 928.224 ;
      RECT 0.048 928.896 138.635 928.992 ;
      RECT 0.048 929.664 138.635 929.76 ;
      RECT 0.048 930.432 138.635 930.528 ;
      RECT 0.048 931.2 138.635 931.296 ;
      RECT 0.048 931.968 138.635 932.064 ;
      RECT 0.048 932.736 138.635 932.832 ;
      RECT 0.048 933.504 138.635 933.6 ;
      RECT 0.048 934.272 138.635 934.368 ;
      RECT 0.048 935.04 138.635 935.136 ;
      RECT 0.048 935.808 138.635 935.904 ;
      RECT 0.048 936.576 138.635 936.672 ;
      RECT 0.048 937.344 138.635 937.44 ;
      RECT 0.048 938.112 138.635 938.208 ;
      RECT 0.048 938.88 138.635 938.976 ;
      RECT 0.048 939.648 138.635 939.744 ;
      RECT 0.048 940.416 138.635 940.512 ;
      RECT 0.048 941.184 138.635 941.28 ;
      RECT 0.048 941.952 138.635 942.048 ;
      RECT 0.048 942.72 138.635 942.816 ;
      RECT 0.048 943.488 138.635 943.584 ;
      RECT 0.048 944.256 138.635 944.352 ;
      RECT 0.048 945.024 138.635 945.12 ;
      RECT 0.048 945.792 138.635 945.888 ;
      RECT 0.048 946.56 138.635 946.656 ;
      RECT 0.048 947.328 138.635 947.424 ;
      RECT 0.048 948.096 138.635 948.192 ;
      RECT 0.048 948.864 138.635 948.96 ;
      RECT 0.048 949.632 138.635 949.728 ;
      RECT 0.048 950.4 138.635 950.496 ;
      RECT 0.048 951.168 138.635 951.264 ;
      RECT 0.048 951.936 138.635 952.032 ;
      RECT 0.048 952.704 138.635 952.8 ;
      RECT 0.048 953.472 138.635 953.568 ;
      RECT 0.048 954.24 138.635 954.336 ;
      RECT 0.048 955.008 138.635 955.104 ;
      RECT 0.048 955.776 138.635 955.872 ;
      RECT 0.048 956.544 138.635 956.64 ;
      RECT 0.048 957.312 138.635 957.408 ;
      RECT 0.048 958.08 138.635 958.176 ;
      RECT 0.048 958.848 138.635 958.944 ;
      RECT 0.048 959.616 138.635 959.712 ;
      RECT 0.048 960.384 138.635 960.48 ;
      RECT 0.048 961.152 138.635 961.248 ;
      RECT 0.048 961.92 138.635 962.016 ;
      RECT 0.048 962.688 138.635 962.784 ;
      RECT 0.048 963.456 138.635 963.552 ;
      RECT 0.048 964.224 138.635 964.32 ;
      RECT 0.048 964.992 138.635 965.088 ;
      RECT 0.048 965.76 138.635 965.856 ;
      RECT 0.048 966.528 138.635 966.624 ;
      RECT 0.048 967.296 138.635 967.392 ;
      RECT 0.048 968.064 138.635 968.16 ;
      RECT 0.048 968.832 138.635 968.928 ;
      RECT 0.048 969.6 138.635 969.696 ;
      RECT 0.048 970.368 138.635 970.464 ;
      RECT 0.048 971.136 138.635 971.232 ;
      RECT 0.048 971.904 138.635 972 ;
      RECT 0.048 972.672 138.635 972.768 ;
      RECT 0.048 973.44 138.635 973.536 ;
      RECT 0.048 974.208 138.635 974.304 ;
      RECT 0.048 974.976 138.635 975.072 ;
      RECT 0.048 975.744 138.635 975.84 ;
      RECT 0.048 976.512 138.635 976.608 ;
      RECT 0.048 977.28 138.635 977.376 ;
      RECT 0.048 978.048 138.635 978.144 ;
      RECT 0.048 978.816 138.635 978.912 ;
      RECT 0.048 979.584 138.635 979.68 ;
      RECT 0.048 980.352 138.635 980.448 ;
      RECT 0.048 981.12 138.635 981.216 ;
      RECT 0.048 981.888 138.635 981.984 ;
      RECT 0.048 982.656 138.635 982.752 ;
      RECT 0.048 983.424 138.635 983.52 ;
      RECT 0.048 984.192 138.635 984.288 ;
      RECT 0.048 984.96 138.635 985.056 ;
      RECT 0.048 985.728 138.635 985.824 ;
      RECT 0.048 986.496 138.635 986.592 ;
      RECT 0.048 987.264 138.635 987.36 ;
      RECT 0.048 988.032 138.635 988.128 ;
      RECT 0.048 988.8 138.635 988.896 ;
      RECT 0.048 989.568 138.635 989.664 ;
      RECT 0.048 990.336 138.635 990.432 ;
      RECT 0.048 991.104 138.635 991.2 ;
      RECT 0.048 991.872 138.635 991.968 ;
      RECT 0.048 992.64 138.635 992.736 ;
      RECT 0.048 993.408 138.635 993.504 ;
      RECT 0.048 994.176 138.635 994.272 ;
      RECT 0.048 994.944 138.635 995.04 ;
      RECT 0.048 995.712 138.635 995.808 ;
      RECT 0.048 996.48 138.635 996.576 ;
      RECT 0.048 997.248 138.635 997.344 ;
      RECT 0.048 998.016 138.635 998.112 ;
      RECT 0.048 998.784 138.635 998.88 ;
      RECT 0.048 999.552 138.635 999.648 ;
      RECT 0.048 1000.32 138.635 1000.416 ;
      RECT 0.048 1001.088 138.635 1001.184 ;
      RECT 0.048 1001.856 138.635 1001.952 ;
      RECT 0.048 1002.624 138.635 1002.72 ;
      RECT 0.048 1003.392 138.635 1003.488 ;
      RECT 0.048 1004.16 138.635 1004.256 ;
      RECT 0.048 1004.928 138.635 1005.024 ;
      RECT 0.048 1005.696 138.635 1005.792 ;
      RECT 0.048 1006.464 138.635 1006.56 ;
      RECT 0.048 1007.232 138.635 1007.328 ;
      RECT 0.048 1008 138.635 1008.096 ;
      RECT 0.048 1008.768 138.635 1008.864 ;
      RECT 0.048 1009.536 138.635 1009.632 ;
      RECT 0.048 1010.304 138.635 1010.4 ;
      RECT 0.048 1011.072 138.635 1011.168 ;
      RECT 0.048 1011.84 138.635 1011.936 ;
      RECT 0.048 1012.608 138.635 1012.704 ;
      RECT 0.048 1013.376 138.635 1013.472 ;
      RECT 0.048 1014.144 138.635 1014.24 ;
      RECT 0.048 1014.912 138.635 1015.008 ;
      RECT 0.048 1015.68 138.635 1015.776 ;
      RECT 0.048 1016.448 138.635 1016.544 ;
      RECT 0.048 1017.216 138.635 1017.312 ;
      RECT 0.048 1017.984 138.635 1018.08 ;
      RECT 0.048 1018.752 138.635 1018.848 ;
      RECT 0.048 1019.52 138.635 1019.616 ;
      RECT 0.048 1020.288 138.635 1020.384 ;
      RECT 0.048 1021.056 138.635 1021.152 ;
      RECT 0.048 1021.824 138.635 1021.92 ;
      RECT 0.048 1022.592 138.635 1022.688 ;
      RECT 0.048 1023.36 138.635 1023.456 ;
      RECT 0.048 1024.128 138.635 1024.224 ;
      RECT 0.048 1024.896 138.635 1024.992 ;
      RECT 0.048 1025.664 138.635 1025.76 ;
      RECT 0.048 1026.432 138.635 1026.528 ;
      RECT 0.048 1027.2 138.635 1027.296 ;
      RECT 0.048 1027.968 138.635 1028.064 ;
      RECT 0.048 1028.736 138.635 1028.832 ;
      RECT 0.048 1029.504 138.635 1029.6 ;
      RECT 0.048 1030.272 138.635 1030.368 ;
      RECT 0.048 1031.04 138.635 1031.136 ;
      RECT 0.048 1031.808 138.635 1031.904 ;
      RECT 0.048 1032.576 138.635 1032.672 ;
      RECT 0.048 1033.344 138.635 1033.44 ;
      RECT 0.048 1034.112 138.635 1034.208 ;
      RECT 0.048 1034.88 138.635 1034.976 ;
      RECT 0.048 1035.648 138.635 1035.744 ;
      RECT 0.048 1036.416 138.635 1036.512 ;
      RECT 0.048 1037.184 138.635 1037.28 ;
      RECT 0.048 1037.952 138.635 1038.048 ;
      RECT 0.048 1038.72 138.635 1038.816 ;
      RECT 0.048 1039.488 138.635 1039.584 ;
      RECT 0.048 1040.256 138.635 1040.352 ;
      RECT 0.048 1041.024 138.635 1041.12 ;
      RECT 0.048 1041.792 138.635 1041.888 ;
      RECT 0.048 1042.56 138.635 1042.656 ;
      RECT 0.048 1043.328 138.635 1043.424 ;
      RECT 0.048 1044.096 138.635 1044.192 ;
      RECT 0.048 1044.864 138.635 1044.96 ;
      RECT 0.048 1045.632 138.635 1045.728 ;
      RECT 0.048 1046.4 138.635 1046.496 ;
      RECT 0.048 1047.168 138.635 1047.264 ;
      RECT 0.048 1047.936 138.635 1048.032 ;
      RECT 0.048 1048.704 138.635 1048.8 ;
      RECT 0.048 1049.472 138.635 1049.568 ;
      RECT 0.048 1050.24 138.635 1050.336 ;
      RECT 0.048 1051.008 138.635 1051.104 ;
      RECT 0.048 1051.776 138.635 1051.872 ;
      RECT 0.048 1052.544 138.635 1052.64 ;
      RECT 0.048 1053.312 138.635 1053.408 ;
      RECT 0.048 1054.08 138.635 1054.176 ;
      RECT 0.048 1054.848 138.635 1054.944 ;
      RECT 0.048 1055.616 138.635 1055.712 ;
      RECT 0.048 1056.384 138.635 1056.48 ;
      RECT 0.048 1057.152 138.635 1057.248 ;
      RECT 0.048 1057.92 138.635 1058.016 ;
      RECT 0.048 1058.688 138.635 1058.784 ;
      RECT 0.048 1059.456 138.635 1059.552 ;
      RECT 0.048 1060.224 138.635 1060.32 ;
      RECT 0.048 1060.992 138.635 1061.088 ;
      RECT 0.048 1061.76 138.635 1061.856 ;
      RECT 0.048 1062.528 138.635 1062.624 ;
      RECT 0.048 1063.296 138.635 1063.392 ;
      RECT 0.048 1064.064 138.635 1064.16 ;
      RECT 0.048 1064.832 138.635 1064.928 ;
      RECT 0.048 1065.6 138.635 1065.696 ;
      RECT 0.048 1066.368 138.635 1066.464 ;
      RECT 0.048 1067.136 138.635 1067.232 ;
      RECT 0.048 1067.904 138.635 1068 ;
      RECT 0.048 1068.672 138.635 1068.768 ;
      RECT 0.048 1069.44 138.635 1069.536 ;
      RECT 0.048 1070.208 138.635 1070.304 ;
      RECT 0.048 1070.976 138.635 1071.072 ;
      RECT 0.048 1071.744 138.635 1071.84 ;
      RECT 0.048 1072.512 138.635 1072.608 ;
      RECT 0.048 1073.28 138.635 1073.376 ;
      RECT 0.048 1074.048 138.635 1074.144 ;
      RECT 0.048 1074.816 138.635 1074.912 ;
      RECT 0.048 1075.584 138.635 1075.68 ;
      RECT 0.048 1076.352 138.635 1076.448 ;
      RECT 0.048 1077.12 138.635 1077.216 ;
      RECT 0.048 1077.888 138.635 1077.984 ;
      RECT 0.048 1078.656 138.635 1078.752 ;
      RECT 0.048 1079.424 138.635 1079.52 ;
      RECT 0.048 1080.192 138.635 1080.288 ;
      RECT 0.048 1080.96 138.635 1081.056 ;
      RECT 0.048 1081.728 138.635 1081.824 ;
      RECT 0.048 1082.496 138.635 1082.592 ;
      RECT 0.048 1083.264 138.635 1083.36 ;
      RECT 0.048 1084.032 138.635 1084.128 ;
      RECT 0.048 1084.8 138.635 1084.896 ;
      RECT 0.048 1085.568 138.635 1085.664 ;
      RECT 0.048 1086.336 138.635 1086.432 ;
      RECT 0.048 1087.104 138.635 1087.2 ;
      RECT 0.048 1087.872 138.635 1087.968 ;
      RECT 0.048 1088.64 138.635 1088.736 ;
      RECT 0.048 1089.408 138.635 1089.504 ;
      RECT 0.048 1090.176 138.635 1090.272 ;
      RECT 0.048 1090.944 138.635 1091.04 ;
      RECT 0.048 1091.712 138.635 1091.808 ;
      RECT 0.048 1092.48 138.635 1092.576 ;
      RECT 0.048 1093.248 138.635 1093.344 ;
      RECT 0.048 1094.016 138.635 1094.112 ;
      RECT 0.048 1094.784 138.635 1094.88 ;
      RECT 0.048 1095.552 138.635 1095.648 ;
      RECT 0.048 1096.32 138.635 1096.416 ;
      RECT 0.048 1097.088 138.635 1097.184 ;
      RECT 0.048 1097.856 138.635 1097.952 ;
      RECT 0.048 1098.624 138.635 1098.72 ;
      RECT 0.048 1099.392 138.635 1099.488 ;
      RECT 0.048 1100.16 138.635 1100.256 ;
      RECT 0.048 1100.928 138.635 1101.024 ;
      RECT 0.048 1101.696 138.635 1101.792 ;
      RECT 0.048 1102.464 138.635 1102.56 ;
      RECT 0.048 1103.232 138.635 1103.328 ;
      RECT 0.048 1104 138.635 1104.096 ;
      RECT 0.048 1104.768 138.635 1104.864 ;
      RECT 0.048 1105.536 138.635 1105.632 ;
      RECT 0.048 1106.304 138.635 1106.4 ;
      RECT 0.048 1107.072 138.635 1107.168 ;
      RECT 0.048 1107.84 138.635 1107.936 ;
      RECT 0.048 1108.608 138.635 1108.704 ;
      RECT 0.048 1109.376 138.635 1109.472 ;
      RECT 0.048 1110.144 138.635 1110.24 ;
      RECT 0.048 1110.912 138.635 1111.008 ;
      RECT 0.048 1111.68 138.635 1111.776 ;
      RECT 0.048 1112.448 138.635 1112.544 ;
      RECT 0.048 1113.216 138.635 1113.312 ;
      RECT 0.048 1113.984 138.635 1114.08 ;
      RECT 0.048 1114.752 138.635 1114.848 ;
      RECT 0.048 1115.52 138.635 1115.616 ;
      RECT 0.048 1116.288 138.635 1116.384 ;
      RECT 0.048 1117.056 138.635 1117.152 ;
      RECT 0.048 1117.824 138.635 1117.92 ;
      RECT 0.048 1118.592 138.635 1118.688 ;
      RECT 0.048 1119.36 138.635 1119.456 ;
      RECT 0.048 1120.128 138.635 1120.224 ;
      RECT 0.048 1120.896 138.635 1120.992 ;
      RECT 0.048 1121.664 138.635 1121.76 ;
      RECT 0.048 1122.432 138.635 1122.528 ;
      RECT 0.048 1123.2 138.635 1123.296 ;
      RECT 0.048 1123.968 138.635 1124.064 ;
      RECT 0.048 1124.736 138.635 1124.832 ;
      RECT 0.048 1125.504 138.635 1125.6 ;
      RECT 0.048 1126.272 138.635 1126.368 ;
      RECT 0.048 1127.04 138.635 1127.136 ;
      RECT 0.048 1127.808 138.635 1127.904 ;
      RECT 0.048 1128.576 138.635 1128.672 ;
      RECT 0.048 1129.344 138.635 1129.44 ;
      RECT 0.048 1130.112 138.635 1130.208 ;
      RECT 0.048 1130.88 138.635 1130.976 ;
      RECT 0.048 1131.648 138.635 1131.744 ;
      RECT 0.048 1132.416 138.635 1132.512 ;
      RECT 0.048 1133.184 138.635 1133.28 ;
      RECT 0.048 1133.952 138.635 1134.048 ;
      RECT 0.048 1134.72 138.635 1134.816 ;
      RECT 0.048 1135.488 138.635 1135.584 ;
      RECT 0.048 1136.256 138.635 1136.352 ;
      RECT 0.048 1137.024 138.635 1137.12 ;
      RECT 0.048 1137.792 138.635 1137.888 ;
      RECT 0.048 1138.56 138.635 1138.656 ;
      RECT 0.048 1139.328 138.635 1139.424 ;
      RECT 0.048 1140.096 138.635 1140.192 ;
      RECT 0.048 1140.864 138.635 1140.96 ;
      RECT 0.048 1141.632 138.635 1141.728 ;
      RECT 0.048 1142.4 138.635 1142.496 ;
      RECT 0.048 1143.168 138.635 1143.264 ;
      RECT 0.048 1143.936 138.635 1144.032 ;
      RECT 0.048 1144.704 138.635 1144.8 ;
      RECT 0.048 1145.472 138.635 1145.568 ;
      RECT 0.048 1146.24 138.635 1146.336 ;
      RECT 0.048 1147.008 138.635 1147.104 ;
      RECT 0.048 1147.776 138.635 1147.872 ;
      RECT 0.048 1148.544 138.635 1148.64 ;
      RECT 0.048 1149.312 138.635 1149.408 ;
      RECT 0.048 1150.08 138.635 1150.176 ;
      RECT 0.048 1150.848 138.635 1150.944 ;
      RECT 0.048 1151.616 138.635 1151.712 ;
      RECT 0.048 1152.384 138.635 1152.48 ;
      RECT 0.048 1153.152 138.635 1153.248 ;
      RECT 0.048 1153.92 138.635 1154.016 ;
      RECT 0.048 1154.688 138.635 1154.784 ;
      RECT 0.048 1155.456 138.635 1155.552 ;
      RECT 0.048 1156.224 138.635 1156.32 ;
      RECT 0.048 1156.992 138.635 1157.088 ;
      RECT 0.048 1157.76 138.635 1157.856 ;
      RECT 0.048 1158.528 138.635 1158.624 ;
      RECT 0.048 1159.296 138.635 1159.392 ;
      RECT 0.048 1160.064 138.635 1160.16 ;
      RECT 0.048 1160.832 138.635 1160.928 ;
      RECT 0.048 1161.6 138.635 1161.696 ;
      RECT 0.048 1162.368 138.635 1162.464 ;
      RECT 0.048 1163.136 138.635 1163.232 ;
      RECT 0.048 1163.904 138.635 1164 ;
      RECT 0.048 1164.672 138.635 1164.768 ;
      RECT 0.048 1165.44 138.635 1165.536 ;
      RECT 0.048 1166.208 138.635 1166.304 ;
      RECT 0.048 1166.976 138.635 1167.072 ;
      RECT 0.048 1167.744 138.635 1167.84 ;
      RECT 0.048 1168.512 138.635 1168.608 ;
      RECT 0.048 1169.28 138.635 1169.376 ;
      RECT 0.048 1170.048 138.635 1170.144 ;
      RECT 0.048 1170.816 138.635 1170.912 ;
      RECT 0.048 1171.584 138.635 1171.68 ;
      RECT 0.048 1172.352 138.635 1172.448 ;
      RECT 0.048 1173.12 138.635 1173.216 ;
      RECT 0.048 1173.888 138.635 1173.984 ;
      RECT 0.048 1174.656 138.635 1174.752 ;
      RECT 0.048 1175.424 138.635 1175.52 ;
      RECT 0.048 1176.192 138.635 1176.288 ;
      RECT 0.048 1176.96 138.635 1177.056 ;
      RECT 0.048 1177.728 138.635 1177.824 ;
      RECT 0.048 1178.496 138.635 1178.592 ;
      RECT 0.048 1179.264 138.635 1179.36 ;
      RECT 0.048 1180.032 138.635 1180.128 ;
      RECT 0.048 1180.8 138.635 1180.896 ;
      RECT 0.048 1181.568 138.635 1181.664 ;
      RECT 0.048 1182.336 138.635 1182.432 ;
      RECT 0.048 1183.104 138.635 1183.2 ;
      RECT 0.048 1183.872 138.635 1183.968 ;
      RECT 0.048 1184.64 138.635 1184.736 ;
      RECT 0.048 1185.408 138.635 1185.504 ;
      RECT 0.048 1186.176 138.635 1186.272 ;
      RECT 0.048 1186.944 138.635 1187.04 ;
      RECT 0.048 1187.712 138.635 1187.808 ;
      RECT 0.048 1188.48 138.635 1188.576 ;
      RECT 0.048 1189.248 138.635 1189.344 ;
      RECT 0.048 1190.016 138.635 1190.112 ;
      RECT 0.048 1190.784 138.635 1190.88 ;
      RECT 0.048 1191.552 138.635 1191.648 ;
      RECT 0.048 1192.32 138.635 1192.416 ;
      RECT 0.048 1193.088 138.635 1193.184 ;
      RECT 0.048 1193.856 138.635 1193.952 ;
      RECT 0.048 1194.624 138.635 1194.72 ;
      RECT 0.048 1195.392 138.635 1195.488 ;
      RECT 0.048 1196.16 138.635 1196.256 ;
      RECT 0.048 1196.928 138.635 1197.024 ;
      RECT 0.048 1197.696 138.635 1197.792 ;
      RECT 0.048 1198.464 138.635 1198.56 ;
      RECT 0.048 1199.232 138.635 1199.328 ;
      RECT 0.048 1200 138.635 1200.096 ;
      RECT 0.048 1200.768 138.635 1200.864 ;
      RECT 0.048 1201.536 138.635 1201.632 ;
      RECT 0.048 1202.304 138.635 1202.4 ;
      RECT 0.048 1203.072 138.635 1203.168 ;
      RECT 0.048 1203.84 138.635 1203.936 ;
      RECT 0.048 1204.608 138.635 1204.704 ;
      RECT 0.048 1205.376 138.635 1205.472 ;
      RECT 0.048 1206.144 138.635 1206.24 ;
      RECT 0.048 1206.912 138.635 1207.008 ;
      RECT 0.048 1207.68 138.635 1207.776 ;
      RECT 0.048 1208.448 138.635 1208.544 ;
      RECT 0.048 1209.216 138.635 1209.312 ;
      RECT 0.048 1209.984 138.635 1210.08 ;
      RECT 0.048 1210.752 138.635 1210.848 ;
      RECT 0.048 1211.52 138.635 1211.616 ;
      RECT 0.048 1212.288 138.635 1212.384 ;
      RECT 0.048 1213.056 138.635 1213.152 ;
      RECT 0.048 1213.824 138.635 1213.92 ;
      RECT 0.048 1214.592 138.635 1214.688 ;
      RECT 0.048 1215.36 138.635 1215.456 ;
      RECT 0.048 1216.128 138.635 1216.224 ;
      RECT 0.048 1216.896 138.635 1216.992 ;
      RECT 0.048 1217.664 138.635 1217.76 ;
      RECT 0.048 1218.432 138.635 1218.528 ;
      RECT 0.048 1219.2 138.635 1219.296 ;
      RECT 0.048 1219.968 138.635 1220.064 ;
      RECT 0.048 1220.736 138.635 1220.832 ;
      RECT 0.048 1221.504 138.635 1221.6 ;
      RECT 0.048 1222.272 138.635 1222.368 ;
      RECT 0.048 1223.04 138.635 1223.136 ;
      RECT 0.048 1223.808 138.635 1223.904 ;
      RECT 0.048 1224.576 138.635 1224.672 ;
      RECT 0.048 1225.344 138.635 1225.44 ;
      RECT 0.048 1226.112 138.635 1226.208 ;
      RECT 0.048 1226.88 138.635 1226.976 ;
      RECT 0.048 1227.648 138.635 1227.744 ;
      RECT 0.048 1228.416 138.635 1228.512 ;
      RECT 0.048 1229.184 138.635 1229.28 ;
      RECT 0.048 1229.952 138.635 1230.048 ;
      RECT 0.048 1230.72 138.635 1230.816 ;
      RECT 0.048 1231.488 138.635 1231.584 ;
      RECT 0.048 1232.256 138.635 1232.352 ;
      RECT 0.048 1233.024 138.635 1233.12 ;
      RECT 0.048 1233.792 138.635 1233.888 ;
      RECT 0.048 1234.56 138.635 1234.656 ;
      RECT 0.048 1235.328 138.635 1235.424 ;
      RECT 0.048 1236.096 138.635 1236.192 ;
      RECT 0.048 1236.864 138.635 1236.96 ;
      RECT 0.048 1237.632 138.635 1237.728 ;
      RECT 0.048 1238.4 138.635 1238.496 ;
      RECT 0.048 1239.168 138.635 1239.264 ;
      RECT 0.048 1239.936 138.635 1240.032 ;
      RECT 0.048 1240.704 138.635 1240.8 ;
      RECT 0.048 1241.472 138.635 1241.568 ;
      RECT 0.048 1242.24 138.635 1242.336 ;
      RECT 0.048 1243.008 138.635 1243.104 ;
      RECT 0.048 1243.776 138.635 1243.872 ;
      RECT 0.048 1244.544 138.635 1244.64 ;
      RECT 0.048 1245.312 138.635 1245.408 ;
      RECT 0.048 1246.08 138.635 1246.176 ;
      RECT 0.048 1246.848 138.635 1246.944 ;
      RECT 0.048 1247.616 138.635 1247.712 ;
      RECT 0.048 1248.384 138.635 1248.48 ;
      RECT 0.048 1249.152 138.635 1249.248 ;
      RECT 0.048 1249.92 138.635 1250.016 ;
      RECT 0.048 1250.688 138.635 1250.784 ;
      RECT 0.048 1251.456 138.635 1251.552 ;
      RECT 0.048 1252.224 138.635 1252.32 ;
      RECT 0.048 1252.992 138.635 1253.088 ;
      RECT 0.048 1253.76 138.635 1253.856 ;
      RECT 0.048 1254.528 138.635 1254.624 ;
      RECT 0.048 1255.296 138.635 1255.392 ;
      RECT 0.048 1256.064 138.635 1256.16 ;
      RECT 0.048 1256.832 138.635 1256.928 ;
      RECT 0.048 1257.6 138.635 1257.696 ;
      RECT 0.048 1258.368 138.635 1258.464 ;
      RECT 0.048 1259.136 138.635 1259.232 ;
      RECT 0.048 1259.904 138.635 1260 ;
      RECT 0.048 1260.672 138.635 1260.768 ;
      RECT 0.048 1261.44 138.635 1261.536 ;
      RECT 0.048 1262.208 138.635 1262.304 ;
      RECT 0.048 1262.976 138.635 1263.072 ;
      RECT 0.048 1263.744 138.635 1263.84 ;
      RECT 0.048 1264.512 138.635 1264.608 ;
      RECT 0.048 1265.28 138.635 1265.376 ;
      RECT 0.048 1266.048 138.635 1266.144 ;
      RECT 0.048 1266.816 138.635 1266.912 ;
      RECT 0.048 1267.584 138.635 1267.68 ;
      RECT 0.048 1268.352 138.635 1268.448 ;
      RECT 0.048 1269.12 138.635 1269.216 ;
      RECT 0.048 1269.888 138.635 1269.984 ;
      RECT 0.048 1270.656 138.635 1270.752 ;
      RECT 0.048 1271.424 138.635 1271.52 ;
      RECT 0.048 1272.192 138.635 1272.288 ;
      RECT 0.048 1272.96 138.635 1273.056 ;
      RECT 0.048 1273.728 138.635 1273.824 ;
      RECT 0.048 1274.496 138.635 1274.592 ;
      RECT 0.048 1275.264 138.635 1275.36 ;
      RECT 0.048 1276.032 138.635 1276.128 ;
      RECT 0.048 1276.8 138.635 1276.896 ;
      RECT 0.048 1277.568 138.635 1277.664 ;
      RECT 0.048 1278.336 138.635 1278.432 ;
      RECT 0.048 1279.104 138.635 1279.2 ;
      RECT 0.048 1279.872 138.635 1279.968 ;
      RECT 0.048 1280.64 138.635 1280.736 ;
      RECT 0.048 1281.408 138.635 1281.504 ;
      RECT 0.048 1282.176 138.635 1282.272 ;
      RECT 0.048 1282.944 138.635 1283.04 ;
      RECT 0.048 1283.712 138.635 1283.808 ;
      RECT 0.048 1284.48 138.635 1284.576 ;
      RECT 0.048 1285.248 138.635 1285.344 ;
      RECT 0.048 1286.016 138.635 1286.112 ;
      RECT 0.048 1286.784 138.635 1286.88 ;
      RECT 0.048 1287.552 138.635 1287.648 ;
      RECT 0.048 1288.32 138.635 1288.416 ;
      RECT 0.048 1289.088 138.635 1289.184 ;
      RECT 0.048 1289.856 138.635 1289.952 ;
      RECT 0.048 1290.624 138.635 1290.72 ;
      RECT 0.048 1291.392 138.635 1291.488 ;
      RECT 0.048 1292.16 138.635 1292.256 ;
      RECT 0.048 1292.928 138.635 1293.024 ;
      RECT 0.048 1293.696 138.635 1293.792 ;
      RECT 0.048 1294.464 138.635 1294.56 ;
      RECT 0.048 1295.232 138.635 1295.328 ;
      RECT 0.048 1296 138.635 1296.096 ;
      RECT 0.048 1296.768 138.635 1296.864 ;
      RECT 0.048 1297.536 138.635 1297.632 ;
      RECT 0.048 1298.304 138.635 1298.4 ;
      RECT 0.048 1299.072 138.635 1299.168 ;
      RECT 0.048 1299.84 138.635 1299.936 ;
      RECT 0.048 1300.608 138.635 1300.704 ;
      RECT 0.048 1301.376 138.635 1301.472 ;
      RECT 0.048 1302.144 138.635 1302.24 ;
      RECT 0.048 1302.912 138.635 1303.008 ;
      RECT 0.048 1303.68 138.635 1303.776 ;
      RECT 0.048 1304.448 138.635 1304.544 ;
      RECT 0.048 1305.216 138.635 1305.312 ;
      RECT 0.048 1305.984 138.635 1306.08 ;
      RECT 0.048 1306.752 138.635 1306.848 ;
      RECT 0.048 1307.52 138.635 1307.616 ;
      RECT 0.048 1308.288 138.635 1308.384 ;
      RECT 0.048 1309.056 138.635 1309.152 ;
      RECT 0.048 1309.824 138.635 1309.92 ;
      RECT 0.048 1310.592 138.635 1310.688 ;
      RECT 0.048 1311.36 138.635 1311.456 ;
      RECT 0.048 1312.128 138.635 1312.224 ;
      RECT 0.048 1312.896 138.635 1312.992 ;
      RECT 0.048 1313.664 138.635 1313.76 ;
      RECT 0.048 1314.432 138.635 1314.528 ;
      RECT 0.048 1315.2 138.635 1315.296 ;
      RECT 0.048 1315.968 138.635 1316.064 ;
      RECT 0.048 1316.736 138.635 1316.832 ;
      RECT 0.048 1317.504 138.635 1317.6 ;
      RECT 0.048 1318.272 138.635 1318.368 ;
      RECT 0.048 1319.04 138.635 1319.136 ;
      RECT 0.048 1319.808 138.635 1319.904 ;
      RECT 0.048 1320.576 138.635 1320.672 ;
      RECT 0.048 1321.344 138.635 1321.44 ;
      RECT 0.048 1322.112 138.635 1322.208 ;
      RECT 0.048 1322.88 138.635 1322.976 ;
      RECT 0.048 1323.648 138.635 1323.744 ;
      RECT 0.048 1324.416 138.635 1324.512 ;
      RECT 0.048 1325.184 138.635 1325.28 ;
      RECT 0.048 1325.952 138.635 1326.048 ;
      RECT 0.048 1326.72 138.635 1326.816 ;
      RECT 0.048 1327.488 138.635 1327.584 ;
      RECT 0.048 1328.256 138.635 1328.352 ;
      RECT 0.048 1329.024 138.635 1329.12 ;
      RECT 0.048 1329.792 138.635 1329.888 ;
      RECT 0.048 1330.56 138.635 1330.656 ;
      RECT 0.048 1331.328 138.635 1331.424 ;
      RECT 0.048 1332.096 138.635 1332.192 ;
      RECT 0.048 1332.864 138.635 1332.96 ;
      RECT 0.048 1333.632 138.635 1333.728 ;
      RECT 0.048 1334.4 138.635 1334.496 ;
      RECT 0.048 1335.168 138.635 1335.264 ;
      RECT 0.048 1335.936 138.635 1336.032 ;
      RECT 0.048 1336.704 138.635 1336.8 ;
      RECT 0.048 1337.472 138.635 1337.568 ;
      RECT 0.048 1338.24 138.635 1338.336 ;
      RECT 0.048 1339.008 138.635 1339.104 ;
      RECT 0.048 1339.776 138.635 1339.872 ;
      RECT 0.048 1340.544 138.635 1340.64 ;
      RECT 0.048 1341.312 138.635 1341.408 ;
      RECT 0.048 1342.08 138.635 1342.176 ;
      RECT 0.048 1342.848 138.635 1342.944 ;
      RECT 0.048 1343.616 138.635 1343.712 ;
      RECT 0.048 1344.384 138.635 1344.48 ;
      RECT 0.048 1345.152 138.635 1345.248 ;
      RECT 0.048 1345.92 138.635 1346.016 ;
      RECT 0.048 1346.688 138.635 1346.784 ;
      RECT 0.048 1347.456 138.635 1347.552 ;
      RECT 0.048 1348.224 138.635 1348.32 ;
      RECT 0.048 1348.992 138.635 1349.088 ;
      RECT 0.048 1349.76 138.635 1349.856 ;
      RECT 0.048 1350.528 138.635 1350.624 ;
      RECT 0.048 1351.296 138.635 1351.392 ;
      RECT 0.048 1352.064 138.635 1352.16 ;
      RECT 0.048 1352.832 138.635 1352.928 ;
      RECT 0.048 1353.6 138.635 1353.696 ;
      RECT 0.048 1354.368 138.635 1354.464 ;
      RECT 0.048 1355.136 138.635 1355.232 ;
      RECT 0.048 1355.904 138.635 1356 ;
      RECT 0.048 1356.672 138.635 1356.768 ;
      RECT 0.048 1357.44 138.635 1357.536 ;
      RECT 0.048 1358.208 138.635 1358.304 ;
      RECT 0.048 1358.976 138.635 1359.072 ;
      RECT 0.048 1359.744 138.635 1359.84 ;
      RECT 0.048 1360.512 138.635 1360.608 ;
      RECT 0.048 1361.28 138.635 1361.376 ;
      RECT 0.048 1362.048 138.635 1362.144 ;
      RECT 0.048 1362.816 138.635 1362.912 ;
      RECT 0.048 1363.584 138.635 1363.68 ;
      RECT 0.048 1364.352 138.635 1364.448 ;
      RECT 0.048 1365.12 138.635 1365.216 ;
      RECT 0.048 1365.888 138.635 1365.984 ;
      RECT 0.048 1366.656 138.635 1366.752 ;
      RECT 0.048 1367.424 138.635 1367.52 ;
      RECT 0.048 1368.192 138.635 1368.288 ;
      RECT 0.048 1368.96 138.635 1369.056 ;
      RECT 0.048 1369.728 138.635 1369.824 ;
      RECT 0.048 1370.496 138.635 1370.592 ;
      RECT 0.048 1371.264 138.635 1371.36 ;
      RECT 0.048 1372.032 138.635 1372.128 ;
      RECT 0.048 1372.8 138.635 1372.896 ;
      RECT 0.048 1373.568 138.635 1373.664 ;
      RECT 0.048 1374.336 138.635 1374.432 ;
      RECT 0.048 1375.104 138.635 1375.2 ;
      RECT 0.048 1375.872 138.635 1375.968 ;
      RECT 0.048 1376.64 138.635 1376.736 ;
      RECT 0.048 1377.408 138.635 1377.504 ;
      RECT 0.048 1378.176 138.635 1378.272 ;
      RECT 0.048 1378.944 138.635 1379.04 ;
      RECT 0.048 1379.712 138.635 1379.808 ;
      RECT 0.048 1380.48 138.635 1380.576 ;
      RECT 0.048 1381.248 138.635 1381.344 ;
      RECT 0.048 1382.016 138.635 1382.112 ;
      RECT 0.048 1382.784 138.635 1382.88 ;
      RECT 0.048 1383.552 138.635 1383.648 ;
      RECT 0.048 1384.32 138.635 1384.416 ;
      RECT 0.048 1385.088 138.635 1385.184 ;
      RECT 0.048 1385.856 138.635 1385.952 ;
      RECT 0.048 1386.624 138.635 1386.72 ;
      RECT 0.048 1387.392 138.635 1387.488 ;
      RECT 0.048 1388.16 138.635 1388.256 ;
      RECT 0.048 1388.928 138.635 1389.024 ;
      RECT 0.048 1389.696 138.635 1389.792 ;
      RECT 0.048 1390.464 138.635 1390.56 ;
      RECT 0.048 1391.232 138.635 1391.328 ;
      RECT 0.048 1392 138.635 1392.096 ;
      RECT 0.048 1392.768 138.635 1392.864 ;
      RECT 0.048 1393.536 138.635 1393.632 ;
      RECT 0.048 1394.304 138.635 1394.4 ;
      RECT 0.048 1395.072 138.635 1395.168 ;
      RECT 0.048 1395.84 138.635 1395.936 ;
      RECT 0.048 1396.608 138.635 1396.704 ;
      RECT 0.048 1397.376 138.635 1397.472 ;
      RECT 0.048 1398.144 138.635 1398.24 ;
      RECT 0.048 1398.912 138.635 1399.008 ;
      RECT 0.048 1399.68 138.635 1399.776 ;
      RECT 0.048 1400.448 138.635 1400.544 ;
      RECT 0.048 1401.216 138.635 1401.312 ;
      RECT 0.048 1401.984 138.635 1402.08 ;
      RECT 0.048 1402.752 138.635 1402.848 ;
      RECT 0.048 1403.52 138.635 1403.616 ;
      RECT 0.048 1404.288 138.635 1404.384 ;
      RECT 0.048 1405.056 138.635 1405.152 ;
      RECT 0.048 1405.824 138.635 1405.92 ;
      RECT 0.048 1406.592 138.635 1406.688 ;
      RECT 0.048 1407.36 138.635 1407.456 ;
      RECT 0.048 1408.128 138.635 1408.224 ;
    END
  END VDD
  OBS
    LAYER M1 ;
    RECT 0 0 138.683 1408.493 ;
    LAYER M2 ;
    RECT 0 0 138.683 1408.493 ;
    LAYER M3 ;
    RECT 0 0 138.683 1408.493 ;
  END
END ht_asap7_mempoolgroup_512x16384

END LIBRARY
